VERSION 5.8 ;
BUSBITCHARS "[]" ;
DIVIDERCHAR "/" ;
UNITS
    DATABASE MICRONS 1000 ;
END UNITS

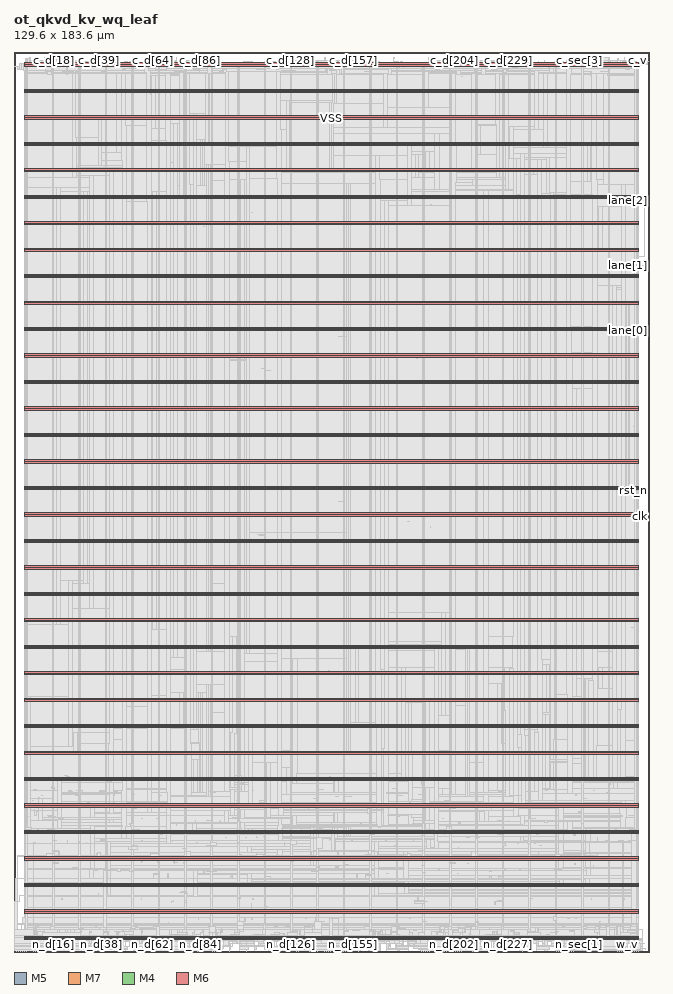
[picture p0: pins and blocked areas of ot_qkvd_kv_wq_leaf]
MACRO ot_qkvd_kv_wq_leaf
  FOREIGN ot_qkvd_kv_wq_leaf 0 0 ;
  CLASS BLOCK ;
  SIZE 129.6 BY 183.6 ;
  PIN c_d[0]
    DIRECTION INPUT ;
    USE SIGNAL ;
    PORT
      LAYER M5 ;
        RECT  0.192 183.516 0.216 183.6 ;
    END
  END c_d[0]
  PIN c_d[100]
    DIRECTION INPUT ;
    USE SIGNAL ;
    PORT
      LAYER M7 ;
        RECT  44.16 183.53 44.192 183.6 ;
    END
  END c_d[100]
  PIN c_d[101]
    DIRECTION INPUT ;
    USE SIGNAL ;
    PORT
      LAYER M7 ;
        RECT  44.544 183.53 44.576 183.6 ;
    END
  END c_d[101]
  PIN c_d[102]
    DIRECTION INPUT ;
    USE SIGNAL ;
    PORT
      LAYER M7 ;
        RECT  44.992 183.53 45.024 183.6 ;
    END
  END c_d[102]
  PIN c_d[103]
    DIRECTION INPUT ;
    USE SIGNAL ;
    PORT
      LAYER M7 ;
        RECT  45.44 183.53 45.472 183.6 ;
    END
  END c_d[103]
  PIN c_d[104]
    DIRECTION INPUT ;
    USE SIGNAL ;
    PORT
      LAYER M7 ;
        RECT  45.888 183.53 45.92 183.6 ;
    END
  END c_d[104]
  PIN c_d[105]
    DIRECTION INPUT ;
    USE SIGNAL ;
    PORT
      LAYER M7 ;
        RECT  46.336 183.53 46.368 183.6 ;
    END
  END c_d[105]
  PIN c_d[106]
    DIRECTION INPUT ;
    USE SIGNAL ;
    PORT
      LAYER M7 ;
        RECT  46.784 183.53 46.816 183.6 ;
    END
  END c_d[106]
  PIN c_d[107]
    DIRECTION INPUT ;
    USE SIGNAL ;
    PORT
      LAYER M7 ;
        RECT  47.232 183.53 47.264 183.6 ;
    END
  END c_d[107]
  PIN c_d[108]
    DIRECTION INPUT ;
    USE SIGNAL ;
    PORT
      LAYER M7 ;
        RECT  47.68 183.53 47.712 183.6 ;
    END
  END c_d[108]
  PIN c_d[109]
    DIRECTION INPUT ;
    USE SIGNAL ;
    PORT
      LAYER M7 ;
        RECT  48.064 183.53 48.096 183.6 ;
    END
  END c_d[109]
  PIN c_d[10]
    DIRECTION INPUT ;
    USE SIGNAL ;
    PORT
      LAYER M5 ;
        RECT  4.608 183.516 4.632 183.6 ;
    END
  END c_d[10]
  PIN c_d[110]
    DIRECTION INPUT ;
    USE SIGNAL ;
    PORT
      LAYER M7 ;
        RECT  48.512 183.53 48.544 183.6 ;
    END
  END c_d[110]
  PIN c_d[111]
    DIRECTION INPUT ;
    USE SIGNAL ;
    PORT
      LAYER M7 ;
        RECT  48.96 183.53 48.992 183.6 ;
    END
  END c_d[111]
  PIN c_d[112]
    DIRECTION INPUT ;
    USE SIGNAL ;
    PORT
      LAYER M7 ;
        RECT  49.408 183.53 49.44 183.6 ;
    END
  END c_d[112]
  PIN c_d[113]
    DIRECTION INPUT ;
    USE SIGNAL ;
    PORT
      LAYER M7 ;
        RECT  49.856 183.53 49.888 183.6 ;
    END
  END c_d[113]
  PIN c_d[114]
    DIRECTION INPUT ;
    USE SIGNAL ;
    PORT
      LAYER M7 ;
        RECT  50.304 183.53 50.336 183.6 ;
    END
  END c_d[114]
  PIN c_d[115]
    DIRECTION INPUT ;
    USE SIGNAL ;
    PORT
      LAYER M7 ;
        RECT  50.752 183.53 50.784 183.6 ;
    END
  END c_d[115]
  PIN c_d[116]
    DIRECTION INPUT ;
    USE SIGNAL ;
    PORT
      LAYER M7 ;
        RECT  51.136 183.53 51.168 183.6 ;
    END
  END c_d[116]
  PIN c_d[117]
    DIRECTION INPUT ;
    USE SIGNAL ;
    PORT
      LAYER M7 ;
        RECT  51.584 183.53 51.616 183.6 ;
    END
  END c_d[117]
  PIN c_d[118]
    DIRECTION INPUT ;
    USE SIGNAL ;
    PORT
      LAYER M7 ;
        RECT  52.032 183.53 52.064 183.6 ;
    END
  END c_d[118]
  PIN c_d[119]
    DIRECTION INPUT ;
    USE SIGNAL ;
    PORT
      LAYER M7 ;
        RECT  52.48 183.53 52.512 183.6 ;
    END
  END c_d[119]
  PIN c_d[11]
    DIRECTION INPUT ;
    USE SIGNAL ;
    PORT
      LAYER M5 ;
        RECT  5.04 183.516 5.064 183.6 ;
    END
  END c_d[11]
  PIN c_d[120]
    DIRECTION INPUT ;
    USE SIGNAL ;
    PORT
      LAYER M7 ;
        RECT  52.928 183.53 52.96 183.6 ;
    END
  END c_d[120]
  PIN c_d[121]
    DIRECTION INPUT ;
    USE SIGNAL ;
    PORT
      LAYER M7 ;
        RECT  53.376 183.53 53.408 183.6 ;
    END
  END c_d[121]
  PIN c_d[122]
    DIRECTION INPUT ;
    USE SIGNAL ;
    PORT
      LAYER M7 ;
        RECT  53.824 183.53 53.856 183.6 ;
    END
  END c_d[122]
  PIN c_d[123]
    DIRECTION INPUT ;
    USE SIGNAL ;
    PORT
      LAYER M7 ;
        RECT  54.272 183.53 54.304 183.6 ;
    END
  END c_d[123]
  PIN c_d[124]
    DIRECTION INPUT ;
    USE SIGNAL ;
    PORT
      LAYER M7 ;
        RECT  54.656 183.53 54.688 183.6 ;
    END
  END c_d[124]
  PIN c_d[125]
    DIRECTION INPUT ;
    USE SIGNAL ;
    PORT
      LAYER M7 ;
        RECT  55.104 183.53 55.136 183.6 ;
    END
  END c_d[125]
  PIN c_d[126]
    DIRECTION INPUT ;
    USE SIGNAL ;
    PORT
      LAYER M7 ;
        RECT  55.552 183.53 55.584 183.6 ;
    END
  END c_d[126]
  PIN c_d[127]
    DIRECTION INPUT ;
    USE SIGNAL ;
    PORT
      LAYER M7 ;
        RECT  56 183.53 56.032 183.6 ;
    END
  END c_d[127]
  PIN c_d[128]
    DIRECTION INPUT ;
    USE SIGNAL ;
    PORT
      LAYER M5 ;
        RECT  56.448 183.516 56.472 183.6 ;
    END
  END c_d[128]
  PIN c_d[129]
    DIRECTION INPUT ;
    USE SIGNAL ;
    PORT
      LAYER M5 ;
        RECT  56.88 183.516 56.904 183.6 ;
    END
  END c_d[129]
  PIN c_d[12]
    DIRECTION INPUT ;
    USE SIGNAL ;
    PORT
      LAYER M5 ;
        RECT  5.472 183.516 5.496 183.6 ;
    END
  END c_d[12]
  PIN c_d[130]
    DIRECTION INPUT ;
    USE SIGNAL ;
    PORT
      LAYER M5 ;
        RECT  57.312 183.516 57.336 183.6 ;
    END
  END c_d[130]
  PIN c_d[131]
    DIRECTION INPUT ;
    USE SIGNAL ;
    PORT
      LAYER M5 ;
        RECT  57.744 183.516 57.768 183.6 ;
    END
  END c_d[131]
  PIN c_d[132]
    DIRECTION INPUT ;
    USE SIGNAL ;
    PORT
      LAYER M5 ;
        RECT  58.176 183.516 58.2 183.6 ;
    END
  END c_d[132]
  PIN c_d[133]
    DIRECTION INPUT ;
    USE SIGNAL ;
    PORT
      LAYER M5 ;
        RECT  58.656 183.516 58.68 183.6 ;
    END
  END c_d[133]
  PIN c_d[134]
    DIRECTION INPUT ;
    USE SIGNAL ;
    PORT
      LAYER M5 ;
        RECT  59.088 183.516 59.112 183.6 ;
    END
  END c_d[134]
  PIN c_d[135]
    DIRECTION INPUT ;
    USE SIGNAL ;
    PORT
      LAYER M5 ;
        RECT  59.52 183.516 59.544 183.6 ;
    END
  END c_d[135]
  PIN c_d[136]
    DIRECTION INPUT ;
    USE SIGNAL ;
    PORT
      LAYER M5 ;
        RECT  59.952 183.516 59.976 183.6 ;
    END
  END c_d[136]
  PIN c_d[137]
    DIRECTION INPUT ;
    USE SIGNAL ;
    PORT
      LAYER M5 ;
        RECT  60.384 183.516 60.408 183.6 ;
    END
  END c_d[137]
  PIN c_d[138]
    DIRECTION INPUT ;
    USE SIGNAL ;
    PORT
      LAYER M5 ;
        RECT  60.816 183.516 60.84 183.6 ;
    END
  END c_d[138]
  PIN c_d[139]
    DIRECTION INPUT ;
    USE SIGNAL ;
    PORT
      LAYER M5 ;
        RECT  61.296 183.516 61.32 183.6 ;
    END
  END c_d[139]
  PIN c_d[13]
    DIRECTION INPUT ;
    USE SIGNAL ;
    PORT
      LAYER M5 ;
        RECT  5.904 183.516 5.928 183.6 ;
    END
  END c_d[13]
  PIN c_d[140]
    DIRECTION INPUT ;
    USE SIGNAL ;
    PORT
      LAYER M5 ;
        RECT  61.728 183.516 61.752 183.6 ;
    END
  END c_d[140]
  PIN c_d[141]
    DIRECTION INPUT ;
    USE SIGNAL ;
    PORT
      LAYER M5 ;
        RECT  62.16 183.516 62.184 183.6 ;
    END
  END c_d[141]
  PIN c_d[142]
    DIRECTION INPUT ;
    USE SIGNAL ;
    PORT
      LAYER M5 ;
        RECT  62.592 183.516 62.616 183.6 ;
    END
  END c_d[142]
  PIN c_d[143]
    DIRECTION INPUT ;
    USE SIGNAL ;
    PORT
      LAYER M5 ;
        RECT  63.024 183.516 63.048 183.6 ;
    END
  END c_d[143]
  PIN c_d[144]
    DIRECTION INPUT ;
    USE SIGNAL ;
    PORT
      LAYER M5 ;
        RECT  63.456 183.516 63.48 183.6 ;
    END
  END c_d[144]
  PIN c_d[145]
    DIRECTION INPUT ;
    USE SIGNAL ;
    PORT
      LAYER M5 ;
        RECT  63.888 183.516 63.912 183.6 ;
    END
  END c_d[145]
  PIN c_d[146]
    DIRECTION INPUT ;
    USE SIGNAL ;
    PORT
      LAYER M5 ;
        RECT  64.368 183.516 64.392 183.6 ;
    END
  END c_d[146]
  PIN c_d[147]
    DIRECTION INPUT ;
    USE SIGNAL ;
    PORT
      LAYER M5 ;
        RECT  64.8 183.516 64.824 183.6 ;
    END
  END c_d[147]
  PIN c_d[148]
    DIRECTION INPUT ;
    USE SIGNAL ;
    PORT
      LAYER M5 ;
        RECT  65.232 183.516 65.256 183.6 ;
    END
  END c_d[148]
  PIN c_d[149]
    DIRECTION INPUT ;
    USE SIGNAL ;
    PORT
      LAYER M5 ;
        RECT  65.664 183.516 65.688 183.6 ;
    END
  END c_d[149]
  PIN c_d[14]
    DIRECTION INPUT ;
    USE SIGNAL ;
    PORT
      LAYER M5 ;
        RECT  6.336 183.516 6.36 183.6 ;
    END
  END c_d[14]
  PIN c_d[150]
    DIRECTION INPUT ;
    USE SIGNAL ;
    PORT
      LAYER M5 ;
        RECT  66.096 183.516 66.12 183.6 ;
    END
  END c_d[150]
  PIN c_d[151]
    DIRECTION INPUT ;
    USE SIGNAL ;
    PORT
      LAYER M5 ;
        RECT  66.528 183.516 66.552 183.6 ;
    END
  END c_d[151]
  PIN c_d[152]
    DIRECTION INPUT ;
    USE SIGNAL ;
    PORT
      LAYER M5 ;
        RECT  67.008 183.516 67.032 183.6 ;
    END
  END c_d[152]
  PIN c_d[153]
    DIRECTION INPUT ;
    USE SIGNAL ;
    PORT
      LAYER M5 ;
        RECT  67.44 183.516 67.464 183.6 ;
    END
  END c_d[153]
  PIN c_d[154]
    DIRECTION INPUT ;
    USE SIGNAL ;
    PORT
      LAYER M5 ;
        RECT  67.872 183.516 67.896 183.6 ;
    END
  END c_d[154]
  PIN c_d[155]
    DIRECTION INPUT ;
    USE SIGNAL ;
    PORT
      LAYER M5 ;
        RECT  68.304 183.516 68.328 183.6 ;
    END
  END c_d[155]
  PIN c_d[156]
    DIRECTION INPUT ;
    USE SIGNAL ;
    PORT
      LAYER M5 ;
        RECT  68.736 183.516 68.76 183.6 ;
    END
  END c_d[156]
  PIN c_d[157]
    DIRECTION INPUT ;
    USE SIGNAL ;
    PORT
      LAYER M5 ;
        RECT  69.168 183.516 69.192 183.6 ;
    END
  END c_d[157]
  PIN c_d[158]
    DIRECTION INPUT ;
    USE SIGNAL ;
    PORT
      LAYER M5 ;
        RECT  69.6 183.516 69.624 183.6 ;
    END
  END c_d[158]
  PIN c_d[159]
    DIRECTION INPUT ;
    USE SIGNAL ;
    PORT
      LAYER M5 ;
        RECT  70.08 183.516 70.104 183.6 ;
    END
  END c_d[159]
  PIN c_d[15]
    DIRECTION INPUT ;
    USE SIGNAL ;
    PORT
      LAYER M5 ;
        RECT  6.816 183.516 6.84 183.6 ;
    END
  END c_d[15]
  PIN c_d[160]
    DIRECTION INPUT ;
    USE SIGNAL ;
    PORT
      LAYER M7 ;
        RECT  70.464 183.53 70.496 183.6 ;
    END
  END c_d[160]
  PIN c_d[161]
    DIRECTION INPUT ;
    USE SIGNAL ;
    PORT
      LAYER M7 ;
        RECT  70.912 183.53 70.944 183.6 ;
    END
  END c_d[161]
  PIN c_d[162]
    DIRECTION INPUT ;
    USE SIGNAL ;
    PORT
      LAYER M7 ;
        RECT  71.36 183.53 71.392 183.6 ;
    END
  END c_d[162]
  PIN c_d[163]
    DIRECTION INPUT ;
    USE SIGNAL ;
    PORT
      LAYER M7 ;
        RECT  71.808 183.53 71.84 183.6 ;
    END
  END c_d[163]
  PIN c_d[164]
    DIRECTION INPUT ;
    USE SIGNAL ;
    PORT
      LAYER M7 ;
        RECT  72.256 183.53 72.288 183.6 ;
    END
  END c_d[164]
  PIN c_d[165]
    DIRECTION INPUT ;
    USE SIGNAL ;
    PORT
      LAYER M7 ;
        RECT  72.704 183.53 72.736 183.6 ;
    END
  END c_d[165]
  PIN c_d[166]
    DIRECTION INPUT ;
    USE SIGNAL ;
    PORT
      LAYER M7 ;
        RECT  73.152 183.53 73.184 183.6 ;
    END
  END c_d[166]
  PIN c_d[167]
    DIRECTION INPUT ;
    USE SIGNAL ;
    PORT
      LAYER M7 ;
        RECT  73.6 183.53 73.632 183.6 ;
    END
  END c_d[167]
  PIN c_d[168]
    DIRECTION INPUT ;
    USE SIGNAL ;
    PORT
      LAYER M7 ;
        RECT  73.984 183.53 74.016 183.6 ;
    END
  END c_d[168]
  PIN c_d[169]
    DIRECTION INPUT ;
    USE SIGNAL ;
    PORT
      LAYER M7 ;
        RECT  74.432 183.53 74.464 183.6 ;
    END
  END c_d[169]
  PIN c_d[16]
    DIRECTION INPUT ;
    USE SIGNAL ;
    PORT
      LAYER M5 ;
        RECT  7.248 183.516 7.272 183.6 ;
    END
  END c_d[16]
  PIN c_d[170]
    DIRECTION INPUT ;
    USE SIGNAL ;
    PORT
      LAYER M7 ;
        RECT  74.88 183.53 74.912 183.6 ;
    END
  END c_d[170]
  PIN c_d[171]
    DIRECTION INPUT ;
    USE SIGNAL ;
    PORT
      LAYER M7 ;
        RECT  75.328 183.53 75.36 183.6 ;
    END
  END c_d[171]
  PIN c_d[172]
    DIRECTION INPUT ;
    USE SIGNAL ;
    PORT
      LAYER M7 ;
        RECT  75.776 183.53 75.808 183.6 ;
    END
  END c_d[172]
  PIN c_d[173]
    DIRECTION INPUT ;
    USE SIGNAL ;
    PORT
      LAYER M7 ;
        RECT  76.224 183.53 76.256 183.6 ;
    END
  END c_d[173]
  PIN c_d[174]
    DIRECTION INPUT ;
    USE SIGNAL ;
    PORT
      LAYER M7 ;
        RECT  76.672 183.53 76.704 183.6 ;
    END
  END c_d[174]
  PIN c_d[175]
    DIRECTION INPUT ;
    USE SIGNAL ;
    PORT
      LAYER M7 ;
        RECT  77.056 183.53 77.088 183.6 ;
    END
  END c_d[175]
  PIN c_d[176]
    DIRECTION INPUT ;
    USE SIGNAL ;
    PORT
      LAYER M7 ;
        RECT  77.504 183.53 77.536 183.6 ;
    END
  END c_d[176]
  PIN c_d[177]
    DIRECTION INPUT ;
    USE SIGNAL ;
    PORT
      LAYER M7 ;
        RECT  77.952 183.53 77.984 183.6 ;
    END
  END c_d[177]
  PIN c_d[178]
    DIRECTION INPUT ;
    USE SIGNAL ;
    PORT
      LAYER M7 ;
        RECT  78.4 183.53 78.432 183.6 ;
    END
  END c_d[178]
  PIN c_d[179]
    DIRECTION INPUT ;
    USE SIGNAL ;
    PORT
      LAYER M7 ;
        RECT  78.848 183.53 78.88 183.6 ;
    END
  END c_d[179]
  PIN c_d[17]
    DIRECTION INPUT ;
    USE SIGNAL ;
    PORT
      LAYER M5 ;
        RECT  7.68 183.516 7.704 183.6 ;
    END
  END c_d[17]
  PIN c_d[180]
    DIRECTION INPUT ;
    USE SIGNAL ;
    PORT
      LAYER M7 ;
        RECT  79.296 183.53 79.328 183.6 ;
    END
  END c_d[180]
  PIN c_d[181]
    DIRECTION INPUT ;
    USE SIGNAL ;
    PORT
      LAYER M7 ;
        RECT  79.744 183.53 79.776 183.6 ;
    END
  END c_d[181]
  PIN c_d[182]
    DIRECTION INPUT ;
    USE SIGNAL ;
    PORT
      LAYER M7 ;
        RECT  80.192 183.53 80.224 183.6 ;
    END
  END c_d[182]
  PIN c_d[183]
    DIRECTION INPUT ;
    USE SIGNAL ;
    PORT
      LAYER M7 ;
        RECT  80.576 183.53 80.608 183.6 ;
    END
  END c_d[183]
  PIN c_d[184]
    DIRECTION INPUT ;
    USE SIGNAL ;
    PORT
      LAYER M7 ;
        RECT  81.024 183.53 81.056 183.6 ;
    END
  END c_d[184]
  PIN c_d[185]
    DIRECTION INPUT ;
    USE SIGNAL ;
    PORT
      LAYER M7 ;
        RECT  81.472 183.53 81.504 183.6 ;
    END
  END c_d[185]
  PIN c_d[186]
    DIRECTION INPUT ;
    USE SIGNAL ;
    PORT
      LAYER M7 ;
        RECT  81.92 183.53 81.952 183.6 ;
    END
  END c_d[186]
  PIN c_d[187]
    DIRECTION INPUT ;
    USE SIGNAL ;
    PORT
      LAYER M7 ;
        RECT  82.368 183.53 82.4 183.6 ;
    END
  END c_d[187]
  PIN c_d[188]
    DIRECTION INPUT ;
    USE SIGNAL ;
    PORT
      LAYER M7 ;
        RECT  82.816 183.53 82.848 183.6 ;
    END
  END c_d[188]
  PIN c_d[189]
    DIRECTION INPUT ;
    USE SIGNAL ;
    PORT
      LAYER M7 ;
        RECT  83.264 183.53 83.296 183.6 ;
    END
  END c_d[189]
  PIN c_d[18]
    DIRECTION INPUT ;
    USE SIGNAL ;
    PORT
      LAYER M5 ;
        RECT  8.112 183.516 8.136 183.6 ;
    END
  END c_d[18]
  PIN c_d[190]
    DIRECTION INPUT ;
    USE SIGNAL ;
    PORT
      LAYER M7 ;
        RECT  83.648 183.53 83.68 183.6 ;
    END
  END c_d[190]
  PIN c_d[191]
    DIRECTION INPUT ;
    USE SIGNAL ;
    PORT
      LAYER M7 ;
        RECT  84.096 183.53 84.128 183.6 ;
    END
  END c_d[191]
  PIN c_d[192]
    DIRECTION INPUT ;
    USE SIGNAL ;
    PORT
      LAYER M5 ;
        RECT  84.576 183.516 84.6 183.6 ;
    END
  END c_d[192]
  PIN c_d[193]
    DIRECTION INPUT ;
    USE SIGNAL ;
    PORT
      LAYER M5 ;
        RECT  85.008 183.516 85.032 183.6 ;
    END
  END c_d[193]
  PIN c_d[194]
    DIRECTION INPUT ;
    USE SIGNAL ;
    PORT
      LAYER M5 ;
        RECT  85.44 183.516 85.464 183.6 ;
    END
  END c_d[194]
  PIN c_d[195]
    DIRECTION INPUT ;
    USE SIGNAL ;
    PORT
      LAYER M5 ;
        RECT  85.872 183.516 85.896 183.6 ;
    END
  END c_d[195]
  PIN c_d[196]
    DIRECTION INPUT ;
    USE SIGNAL ;
    PORT
      LAYER M5 ;
        RECT  86.304 183.516 86.328 183.6 ;
    END
  END c_d[196]
  PIN c_d[197]
    DIRECTION INPUT ;
    USE SIGNAL ;
    PORT
      LAYER M5 ;
        RECT  86.736 183.516 86.76 183.6 ;
    END
  END c_d[197]
  PIN c_d[198]
    DIRECTION INPUT ;
    USE SIGNAL ;
    PORT
      LAYER M5 ;
        RECT  87.216 183.516 87.24 183.6 ;
    END
  END c_d[198]
  PIN c_d[199]
    DIRECTION INPUT ;
    USE SIGNAL ;
    PORT
      LAYER M5 ;
        RECT  87.648 183.516 87.672 183.6 ;
    END
  END c_d[199]
  PIN c_d[19]
    DIRECTION INPUT ;
    USE SIGNAL ;
    PORT
      LAYER M5 ;
        RECT  8.544 183.516 8.568 183.6 ;
    END
  END c_d[19]
  PIN c_d[1]
    DIRECTION INPUT ;
    USE SIGNAL ;
    PORT
      LAYER M5 ;
        RECT  0.624 183.516 0.648 183.6 ;
    END
  END c_d[1]
  PIN c_d[200]
    DIRECTION INPUT ;
    USE SIGNAL ;
    PORT
      LAYER M5 ;
        RECT  88.08 183.516 88.104 183.6 ;
    END
  END c_d[200]
  PIN c_d[201]
    DIRECTION INPUT ;
    USE SIGNAL ;
    PORT
      LAYER M5 ;
        RECT  88.512 183.516 88.536 183.6 ;
    END
  END c_d[201]
  PIN c_d[202]
    DIRECTION INPUT ;
    USE SIGNAL ;
    PORT
      LAYER M5 ;
        RECT  88.944 183.516 88.968 183.6 ;
    END
  END c_d[202]
  PIN c_d[203]
    DIRECTION INPUT ;
    USE SIGNAL ;
    PORT
      LAYER M5 ;
        RECT  89.376 183.516 89.4 183.6 ;
    END
  END c_d[203]
  PIN c_d[204]
    DIRECTION INPUT ;
    USE SIGNAL ;
    PORT
      LAYER M5 ;
        RECT  89.808 183.516 89.832 183.6 ;
    END
  END c_d[204]
  PIN c_d[205]
    DIRECTION INPUT ;
    USE SIGNAL ;
    PORT
      LAYER M5 ;
        RECT  90.288 183.516 90.312 183.6 ;
    END
  END c_d[205]
  PIN c_d[206]
    DIRECTION INPUT ;
    USE SIGNAL ;
    PORT
      LAYER M5 ;
        RECT  90.72 183.516 90.744 183.6 ;
    END
  END c_d[206]
  PIN c_d[207]
    DIRECTION INPUT ;
    USE SIGNAL ;
    PORT
      LAYER M5 ;
        RECT  91.152 183.516 91.176 183.6 ;
    END
  END c_d[207]
  PIN c_d[208]
    DIRECTION INPUT ;
    USE SIGNAL ;
    PORT
      LAYER M5 ;
        RECT  91.584 183.516 91.608 183.6 ;
    END
  END c_d[208]
  PIN c_d[209]
    DIRECTION INPUT ;
    USE SIGNAL ;
    PORT
      LAYER M5 ;
        RECT  92.016 183.516 92.04 183.6 ;
    END
  END c_d[209]
  PIN c_d[20]
    DIRECTION INPUT ;
    USE SIGNAL ;
    PORT
      LAYER M5 ;
        RECT  8.976 183.516 9 183.6 ;
    END
  END c_d[20]
  PIN c_d[210]
    DIRECTION INPUT ;
    USE SIGNAL ;
    PORT
      LAYER M5 ;
        RECT  92.448 183.516 92.472 183.6 ;
    END
  END c_d[210]
  PIN c_d[211]
    DIRECTION INPUT ;
    USE SIGNAL ;
    PORT
      LAYER M5 ;
        RECT  92.928 183.516 92.952 183.6 ;
    END
  END c_d[211]
  PIN c_d[212]
    DIRECTION INPUT ;
    USE SIGNAL ;
    PORT
      LAYER M5 ;
        RECT  93.36 183.516 93.384 183.6 ;
    END
  END c_d[212]
  PIN c_d[213]
    DIRECTION INPUT ;
    USE SIGNAL ;
    PORT
      LAYER M5 ;
        RECT  93.792 183.516 93.816 183.6 ;
    END
  END c_d[213]
  PIN c_d[214]
    DIRECTION INPUT ;
    USE SIGNAL ;
    PORT
      LAYER M5 ;
        RECT  94.224 183.516 94.248 183.6 ;
    END
  END c_d[214]
  PIN c_d[215]
    DIRECTION INPUT ;
    USE SIGNAL ;
    PORT
      LAYER M5 ;
        RECT  94.656 183.516 94.68 183.6 ;
    END
  END c_d[215]
  PIN c_d[216]
    DIRECTION INPUT ;
    USE SIGNAL ;
    PORT
      LAYER M5 ;
        RECT  95.088 183.516 95.112 183.6 ;
    END
  END c_d[216]
  PIN c_d[217]
    DIRECTION INPUT ;
    USE SIGNAL ;
    PORT
      LAYER M5 ;
        RECT  95.52 183.516 95.544 183.6 ;
    END
  END c_d[217]
  PIN c_d[218]
    DIRECTION INPUT ;
    USE SIGNAL ;
    PORT
      LAYER M5 ;
        RECT  96 183.516 96.024 183.6 ;
    END
  END c_d[218]
  PIN c_d[219]
    DIRECTION INPUT ;
    USE SIGNAL ;
    PORT
      LAYER M5 ;
        RECT  96.432 183.516 96.456 183.6 ;
    END
  END c_d[219]
  PIN c_d[21]
    DIRECTION INPUT ;
    USE SIGNAL ;
    PORT
      LAYER M5 ;
        RECT  9.456 183.516 9.48 183.6 ;
    END
  END c_d[21]
  PIN c_d[220]
    DIRECTION INPUT ;
    USE SIGNAL ;
    PORT
      LAYER M5 ;
        RECT  96.864 183.516 96.888 183.6 ;
    END
  END c_d[220]
  PIN c_d[221]
    DIRECTION INPUT ;
    USE SIGNAL ;
    PORT
      LAYER M5 ;
        RECT  97.296 183.516 97.32 183.6 ;
    END
  END c_d[221]
  PIN c_d[222]
    DIRECTION INPUT ;
    USE SIGNAL ;
    PORT
      LAYER M5 ;
        RECT  97.728 183.516 97.752 183.6 ;
    END
  END c_d[222]
  PIN c_d[223]
    DIRECTION INPUT ;
    USE SIGNAL ;
    PORT
      LAYER M5 ;
        RECT  98.16 183.516 98.184 183.6 ;
    END
  END c_d[223]
  PIN c_d[224]
    DIRECTION INPUT ;
    USE SIGNAL ;
    PORT
      LAYER M7 ;
        RECT  98.624 183.53 98.656 183.6 ;
    END
  END c_d[224]
  PIN c_d[225]
    DIRECTION INPUT ;
    USE SIGNAL ;
    PORT
      LAYER M7 ;
        RECT  99.072 183.53 99.104 183.6 ;
    END
  END c_d[225]
  PIN c_d[226]
    DIRECTION INPUT ;
    USE SIGNAL ;
    PORT
      LAYER M7 ;
        RECT  99.52 183.53 99.552 183.6 ;
    END
  END c_d[226]
  PIN c_d[227]
    DIRECTION INPUT ;
    USE SIGNAL ;
    PORT
      LAYER M7 ;
        RECT  99.904 183.53 99.936 183.6 ;
    END
  END c_d[227]
  PIN c_d[228]
    DIRECTION INPUT ;
    USE SIGNAL ;
    PORT
      LAYER M7 ;
        RECT  100.352 183.53 100.384 183.6 ;
    END
  END c_d[228]
  PIN c_d[229]
    DIRECTION INPUT ;
    USE SIGNAL ;
    PORT
      LAYER M7 ;
        RECT  100.8 183.53 100.832 183.6 ;
    END
  END c_d[229]
  PIN c_d[22]
    DIRECTION INPUT ;
    USE SIGNAL ;
    PORT
      LAYER M5 ;
        RECT  9.888 183.516 9.912 183.6 ;
    END
  END c_d[22]
  PIN c_d[230]
    DIRECTION INPUT ;
    USE SIGNAL ;
    PORT
      LAYER M7 ;
        RECT  101.248 183.53 101.28 183.6 ;
    END
  END c_d[230]
  PIN c_d[231]
    DIRECTION INPUT ;
    USE SIGNAL ;
    PORT
      LAYER M7 ;
        RECT  101.696 183.53 101.728 183.6 ;
    END
  END c_d[231]
  PIN c_d[232]
    DIRECTION INPUT ;
    USE SIGNAL ;
    PORT
      LAYER M7 ;
        RECT  102.144 183.53 102.176 183.6 ;
    END
  END c_d[232]
  PIN c_d[233]
    DIRECTION INPUT ;
    USE SIGNAL ;
    PORT
      LAYER M7 ;
        RECT  102.592 183.53 102.624 183.6 ;
    END
  END c_d[233]
  PIN c_d[234]
    DIRECTION INPUT ;
    USE SIGNAL ;
    PORT
      LAYER M7 ;
        RECT  102.976 183.53 103.008 183.6 ;
    END
  END c_d[234]
  PIN c_d[235]
    DIRECTION INPUT ;
    USE SIGNAL ;
    PORT
      LAYER M7 ;
        RECT  103.424 183.53 103.456 183.6 ;
    END
  END c_d[235]
  PIN c_d[236]
    DIRECTION INPUT ;
    USE SIGNAL ;
    PORT
      LAYER M7 ;
        RECT  103.872 183.53 103.904 183.6 ;
    END
  END c_d[236]
  PIN c_d[237]
    DIRECTION INPUT ;
    USE SIGNAL ;
    PORT
      LAYER M7 ;
        RECT  104.32 183.53 104.352 183.6 ;
    END
  END c_d[237]
  PIN c_d[238]
    DIRECTION INPUT ;
    USE SIGNAL ;
    PORT
      LAYER M7 ;
        RECT  104.768 183.53 104.8 183.6 ;
    END
  END c_d[238]
  PIN c_d[239]
    DIRECTION INPUT ;
    USE SIGNAL ;
    PORT
      LAYER M7 ;
        RECT  105.216 183.53 105.248 183.6 ;
    END
  END c_d[239]
  PIN c_d[23]
    DIRECTION INPUT ;
    USE SIGNAL ;
    PORT
      LAYER M5 ;
        RECT  10.32 183.516 10.344 183.6 ;
    END
  END c_d[23]
  PIN c_d[240]
    DIRECTION INPUT ;
    USE SIGNAL ;
    PORT
      LAYER M7 ;
        RECT  105.664 183.53 105.696 183.6 ;
    END
  END c_d[240]
  PIN c_d[241]
    DIRECTION INPUT ;
    USE SIGNAL ;
    PORT
      LAYER M7 ;
        RECT  106.112 183.53 106.144 183.6 ;
    END
  END c_d[241]
  PIN c_d[242]
    DIRECTION INPUT ;
    USE SIGNAL ;
    PORT
      LAYER M7 ;
        RECT  106.496 183.53 106.528 183.6 ;
    END
  END c_d[242]
  PIN c_d[243]
    DIRECTION INPUT ;
    USE SIGNAL ;
    PORT
      LAYER M7 ;
        RECT  106.944 183.53 106.976 183.6 ;
    END
  END c_d[243]
  PIN c_d[244]
    DIRECTION INPUT ;
    USE SIGNAL ;
    PORT
      LAYER M7 ;
        RECT  107.392 183.53 107.424 183.6 ;
    END
  END c_d[244]
  PIN c_d[245]
    DIRECTION INPUT ;
    USE SIGNAL ;
    PORT
      LAYER M7 ;
        RECT  107.84 183.53 107.872 183.6 ;
    END
  END c_d[245]
  PIN c_d[246]
    DIRECTION INPUT ;
    USE SIGNAL ;
    PORT
      LAYER M7 ;
        RECT  108.288 183.53 108.32 183.6 ;
    END
  END c_d[246]
  PIN c_d[247]
    DIRECTION INPUT ;
    USE SIGNAL ;
    PORT
      LAYER M7 ;
        RECT  108.736 183.53 108.768 183.6 ;
    END
  END c_d[247]
  PIN c_d[248]
    DIRECTION INPUT ;
    USE SIGNAL ;
    PORT
      LAYER M7 ;
        RECT  109.184 183.53 109.216 183.6 ;
    END
  END c_d[248]
  PIN c_d[249]
    DIRECTION INPUT ;
    USE SIGNAL ;
    PORT
      LAYER M7 ;
        RECT  109.568 183.53 109.6 183.6 ;
    END
  END c_d[249]
  PIN c_d[24]
    DIRECTION INPUT ;
    USE SIGNAL ;
    PORT
      LAYER M5 ;
        RECT  10.752 183.516 10.776 183.6 ;
    END
  END c_d[24]
  PIN c_d[250]
    DIRECTION INPUT ;
    USE SIGNAL ;
    PORT
      LAYER M7 ;
        RECT  110.016 183.53 110.048 183.6 ;
    END
  END c_d[250]
  PIN c_d[251]
    DIRECTION INPUT ;
    USE SIGNAL ;
    PORT
      LAYER M7 ;
        RECT  110.464 183.53 110.496 183.6 ;
    END
  END c_d[251]
  PIN c_d[252]
    DIRECTION INPUT ;
    USE SIGNAL ;
    PORT
      LAYER M7 ;
        RECT  110.912 183.53 110.944 183.6 ;
    END
  END c_d[252]
  PIN c_d[253]
    DIRECTION INPUT ;
    USE SIGNAL ;
    PORT
      LAYER M7 ;
        RECT  111.36 183.53 111.392 183.6 ;
    END
  END c_d[253]
  PIN c_d[254]
    DIRECTION INPUT ;
    USE SIGNAL ;
    PORT
      LAYER M7 ;
        RECT  111.808 183.53 111.84 183.6 ;
    END
  END c_d[254]
  PIN c_d[255]
    DIRECTION INPUT ;
    USE SIGNAL ;
    PORT
      LAYER M7 ;
        RECT  112.256 183.53 112.288 183.6 ;
    END
  END c_d[255]
  PIN c_d[25]
    DIRECTION INPUT ;
    USE SIGNAL ;
    PORT
      LAYER M5 ;
        RECT  11.184 183.516 11.208 183.6 ;
    END
  END c_d[25]
  PIN c_d[26]
    DIRECTION INPUT ;
    USE SIGNAL ;
    PORT
      LAYER M5 ;
        RECT  11.616 183.516 11.64 183.6 ;
    END
  END c_d[26]
  PIN c_d[27]
    DIRECTION INPUT ;
    USE SIGNAL ;
    PORT
      LAYER M5 ;
        RECT  12.048 183.516 12.072 183.6 ;
    END
  END c_d[27]
  PIN c_d[28]
    DIRECTION INPUT ;
    USE SIGNAL ;
    PORT
      LAYER M5 ;
        RECT  12.528 183.516 12.552 183.6 ;
    END
  END c_d[28]
  PIN c_d[29]
    DIRECTION INPUT ;
    USE SIGNAL ;
    PORT
      LAYER M5 ;
        RECT  12.96 183.516 12.984 183.6 ;
    END
  END c_d[29]
  PIN c_d[2]
    DIRECTION INPUT ;
    USE SIGNAL ;
    PORT
      LAYER M5 ;
        RECT  1.104 183.516 1.128 183.6 ;
    END
  END c_d[2]
  PIN c_d[30]
    DIRECTION INPUT ;
    USE SIGNAL ;
    PORT
      LAYER M5 ;
        RECT  13.392 183.516 13.416 183.6 ;
    END
  END c_d[30]
  PIN c_d[31]
    DIRECTION INPUT ;
    USE SIGNAL ;
    PORT
      LAYER M5 ;
        RECT  13.824 183.516 13.848 183.6 ;
    END
  END c_d[31]
  PIN c_d[32]
    DIRECTION INPUT ;
    USE SIGNAL ;
    PORT
      LAYER M7 ;
        RECT  14.272 183.53 14.304 183.6 ;
    END
  END c_d[32]
  PIN c_d[33]
    DIRECTION INPUT ;
    USE SIGNAL ;
    PORT
      LAYER M7 ;
        RECT  14.72 183.53 14.752 183.6 ;
    END
  END c_d[33]
  PIN c_d[34]
    DIRECTION INPUT ;
    USE SIGNAL ;
    PORT
      LAYER M7 ;
        RECT  15.168 183.53 15.2 183.6 ;
    END
  END c_d[34]
  PIN c_d[35]
    DIRECTION INPUT ;
    USE SIGNAL ;
    PORT
      LAYER M7 ;
        RECT  15.552 183.53 15.584 183.6 ;
    END
  END c_d[35]
  PIN c_d[36]
    DIRECTION INPUT ;
    USE SIGNAL ;
    PORT
      LAYER M7 ;
        RECT  16 183.53 16.032 183.6 ;
    END
  END c_d[36]
  PIN c_d[37]
    DIRECTION INPUT ;
    USE SIGNAL ;
    PORT
      LAYER M7 ;
        RECT  16.448 183.53 16.48 183.6 ;
    END
  END c_d[37]
  PIN c_d[38]
    DIRECTION INPUT ;
    USE SIGNAL ;
    PORT
      LAYER M7 ;
        RECT  16.896 183.53 16.928 183.6 ;
    END
  END c_d[38]
  PIN c_d[39]
    DIRECTION INPUT ;
    USE SIGNAL ;
    PORT
      LAYER M7 ;
        RECT  17.344 183.53 17.376 183.6 ;
    END
  END c_d[39]
  PIN c_d[3]
    DIRECTION INPUT ;
    USE SIGNAL ;
    PORT
      LAYER M5 ;
        RECT  1.536 183.516 1.56 183.6 ;
    END
  END c_d[3]
  PIN c_d[40]
    DIRECTION INPUT ;
    USE SIGNAL ;
    PORT
      LAYER M7 ;
        RECT  17.792 183.53 17.824 183.6 ;
    END
  END c_d[40]
  PIN c_d[41]
    DIRECTION INPUT ;
    USE SIGNAL ;
    PORT
      LAYER M7 ;
        RECT  18.24 183.53 18.272 183.6 ;
    END
  END c_d[41]
  PIN c_d[42]
    DIRECTION INPUT ;
    USE SIGNAL ;
    PORT
      LAYER M7 ;
        RECT  18.624 183.53 18.656 183.6 ;
    END
  END c_d[42]
  PIN c_d[43]
    DIRECTION INPUT ;
    USE SIGNAL ;
    PORT
      LAYER M7 ;
        RECT  19.072 183.53 19.104 183.6 ;
    END
  END c_d[43]
  PIN c_d[44]
    DIRECTION INPUT ;
    USE SIGNAL ;
    PORT
      LAYER M7 ;
        RECT  19.52 183.53 19.552 183.6 ;
    END
  END c_d[44]
  PIN c_d[45]
    DIRECTION INPUT ;
    USE SIGNAL ;
    PORT
      LAYER M7 ;
        RECT  19.968 183.53 20 183.6 ;
    END
  END c_d[45]
  PIN c_d[46]
    DIRECTION INPUT ;
    USE SIGNAL ;
    PORT
      LAYER M7 ;
        RECT  20.416 183.53 20.448 183.6 ;
    END
  END c_d[46]
  PIN c_d[47]
    DIRECTION INPUT ;
    USE SIGNAL ;
    PORT
      LAYER M7 ;
        RECT  20.864 183.53 20.896 183.6 ;
    END
  END c_d[47]
  PIN c_d[48]
    DIRECTION INPUT ;
    USE SIGNAL ;
    PORT
      LAYER M7 ;
        RECT  21.312 183.53 21.344 183.6 ;
    END
  END c_d[48]
  PIN c_d[49]
    DIRECTION INPUT ;
    USE SIGNAL ;
    PORT
      LAYER M7 ;
        RECT  21.76 183.53 21.792 183.6 ;
    END
  END c_d[49]
  PIN c_d[4]
    DIRECTION INPUT ;
    USE SIGNAL ;
    PORT
      LAYER M5 ;
        RECT  1.968 183.516 1.992 183.6 ;
    END
  END c_d[4]
  PIN c_d[50]
    DIRECTION INPUT ;
    USE SIGNAL ;
    PORT
      LAYER M7 ;
        RECT  22.144 183.53 22.176 183.6 ;
    END
  END c_d[50]
  PIN c_d[51]
    DIRECTION INPUT ;
    USE SIGNAL ;
    PORT
      LAYER M7 ;
        RECT  22.592 183.53 22.624 183.6 ;
    END
  END c_d[51]
  PIN c_d[52]
    DIRECTION INPUT ;
    USE SIGNAL ;
    PORT
      LAYER M7 ;
        RECT  23.04 183.53 23.072 183.6 ;
    END
  END c_d[52]
  PIN c_d[53]
    DIRECTION INPUT ;
    USE SIGNAL ;
    PORT
      LAYER M7 ;
        RECT  23.488 183.53 23.52 183.6 ;
    END
  END c_d[53]
  PIN c_d[54]
    DIRECTION INPUT ;
    USE SIGNAL ;
    PORT
      LAYER M7 ;
        RECT  23.936 183.53 23.968 183.6 ;
    END
  END c_d[54]
  PIN c_d[55]
    DIRECTION INPUT ;
    USE SIGNAL ;
    PORT
      LAYER M7 ;
        RECT  24.384 183.53 24.416 183.6 ;
    END
  END c_d[55]
  PIN c_d[56]
    DIRECTION INPUT ;
    USE SIGNAL ;
    PORT
      LAYER M7 ;
        RECT  24.832 183.53 24.864 183.6 ;
    END
  END c_d[56]
  PIN c_d[57]
    DIRECTION INPUT ;
    USE SIGNAL ;
    PORT
      LAYER M7 ;
        RECT  25.216 183.53 25.248 183.6 ;
    END
  END c_d[57]
  PIN c_d[58]
    DIRECTION INPUT ;
    USE SIGNAL ;
    PORT
      LAYER M7 ;
        RECT  25.664 183.53 25.696 183.6 ;
    END
  END c_d[58]
  PIN c_d[59]
    DIRECTION INPUT ;
    USE SIGNAL ;
    PORT
      LAYER M7 ;
        RECT  26.112 183.53 26.144 183.6 ;
    END
  END c_d[59]
  PIN c_d[5]
    DIRECTION INPUT ;
    USE SIGNAL ;
    PORT
      LAYER M5 ;
        RECT  2.4 183.516 2.424 183.6 ;
    END
  END c_d[5]
  PIN c_d[60]
    DIRECTION INPUT ;
    USE SIGNAL ;
    PORT
      LAYER M7 ;
        RECT  26.56 183.53 26.592 183.6 ;
    END
  END c_d[60]
  PIN c_d[61]
    DIRECTION INPUT ;
    USE SIGNAL ;
    PORT
      LAYER M7 ;
        RECT  27.008 183.53 27.04 183.6 ;
    END
  END c_d[61]
  PIN c_d[62]
    DIRECTION INPUT ;
    USE SIGNAL ;
    PORT
      LAYER M7 ;
        RECT  27.456 183.53 27.488 183.6 ;
    END
  END c_d[62]
  PIN c_d[63]
    DIRECTION INPUT ;
    USE SIGNAL ;
    PORT
      LAYER M7 ;
        RECT  27.904 183.53 27.936 183.6 ;
    END
  END c_d[63]
  PIN c_d[64]
    DIRECTION INPUT ;
    USE SIGNAL ;
    PORT
      LAYER M5 ;
        RECT  28.32 183.516 28.344 183.6 ;
    END
  END c_d[64]
  PIN c_d[65]
    DIRECTION INPUT ;
    USE SIGNAL ;
    PORT
      LAYER M5 ;
        RECT  28.752 183.516 28.776 183.6 ;
    END
  END c_d[65]
  PIN c_d[66]
    DIRECTION INPUT ;
    USE SIGNAL ;
    PORT
      LAYER M5 ;
        RECT  29.184 183.516 29.208 183.6 ;
    END
  END c_d[66]
  PIN c_d[67]
    DIRECTION INPUT ;
    USE SIGNAL ;
    PORT
      LAYER M5 ;
        RECT  29.664 183.516 29.688 183.6 ;
    END
  END c_d[67]
  PIN c_d[68]
    DIRECTION INPUT ;
    USE SIGNAL ;
    PORT
      LAYER M5 ;
        RECT  30.096 183.516 30.12 183.6 ;
    END
  END c_d[68]
  PIN c_d[69]
    DIRECTION INPUT ;
    USE SIGNAL ;
    PORT
      LAYER M5 ;
        RECT  30.528 183.516 30.552 183.6 ;
    END
  END c_d[69]
  PIN c_d[6]
    DIRECTION INPUT ;
    USE SIGNAL ;
    PORT
      LAYER M5 ;
        RECT  2.832 183.516 2.856 183.6 ;
    END
  END c_d[6]
  PIN c_d[70]
    DIRECTION INPUT ;
    USE SIGNAL ;
    PORT
      LAYER M5 ;
        RECT  30.96 183.516 30.984 183.6 ;
    END
  END c_d[70]
  PIN c_d[71]
    DIRECTION INPUT ;
    USE SIGNAL ;
    PORT
      LAYER M5 ;
        RECT  31.392 183.516 31.416 183.6 ;
    END
  END c_d[71]
  PIN c_d[72]
    DIRECTION INPUT ;
    USE SIGNAL ;
    PORT
      LAYER M5 ;
        RECT  31.824 183.516 31.848 183.6 ;
    END
  END c_d[72]
  PIN c_d[73]
    DIRECTION INPUT ;
    USE SIGNAL ;
    PORT
      LAYER M5 ;
        RECT  32.256 183.516 32.28 183.6 ;
    END
  END c_d[73]
  PIN c_d[74]
    DIRECTION INPUT ;
    USE SIGNAL ;
    PORT
      LAYER M5 ;
        RECT  32.736 183.516 32.76 183.6 ;
    END
  END c_d[74]
  PIN c_d[75]
    DIRECTION INPUT ;
    USE SIGNAL ;
    PORT
      LAYER M5 ;
        RECT  33.168 183.516 33.192 183.6 ;
    END
  END c_d[75]
  PIN c_d[76]
    DIRECTION INPUT ;
    USE SIGNAL ;
    PORT
      LAYER M5 ;
        RECT  33.6 183.516 33.624 183.6 ;
    END
  END c_d[76]
  PIN c_d[77]
    DIRECTION INPUT ;
    USE SIGNAL ;
    PORT
      LAYER M5 ;
        RECT  34.032 183.516 34.056 183.6 ;
    END
  END c_d[77]
  PIN c_d[78]
    DIRECTION INPUT ;
    USE SIGNAL ;
    PORT
      LAYER M5 ;
        RECT  34.464 183.516 34.488 183.6 ;
    END
  END c_d[78]
  PIN c_d[79]
    DIRECTION INPUT ;
    USE SIGNAL ;
    PORT
      LAYER M5 ;
        RECT  34.896 183.516 34.92 183.6 ;
    END
  END c_d[79]
  PIN c_d[7]
    DIRECTION INPUT ;
    USE SIGNAL ;
    PORT
      LAYER M5 ;
        RECT  3.264 183.516 3.288 183.6 ;
    END
  END c_d[7]
  PIN c_d[80]
    DIRECTION INPUT ;
    USE SIGNAL ;
    PORT
      LAYER M5 ;
        RECT  35.376 183.516 35.4 183.6 ;
    END
  END c_d[80]
  PIN c_d[81]
    DIRECTION INPUT ;
    USE SIGNAL ;
    PORT
      LAYER M5 ;
        RECT  35.808 183.516 35.832 183.6 ;
    END
  END c_d[81]
  PIN c_d[82]
    DIRECTION INPUT ;
    USE SIGNAL ;
    PORT
      LAYER M5 ;
        RECT  36.24 183.516 36.264 183.6 ;
    END
  END c_d[82]
  PIN c_d[83]
    DIRECTION INPUT ;
    USE SIGNAL ;
    PORT
      LAYER M5 ;
        RECT  36.672 183.516 36.696 183.6 ;
    END
  END c_d[83]
  PIN c_d[84]
    DIRECTION INPUT ;
    USE SIGNAL ;
    PORT
      LAYER M5 ;
        RECT  37.104 183.516 37.128 183.6 ;
    END
  END c_d[84]
  PIN c_d[85]
    DIRECTION INPUT ;
    USE SIGNAL ;
    PORT
      LAYER M5 ;
        RECT  37.536 183.516 37.56 183.6 ;
    END
  END c_d[85]
  PIN c_d[86]
    DIRECTION INPUT ;
    USE SIGNAL ;
    PORT
      LAYER M5 ;
        RECT  37.968 183.516 37.992 183.6 ;
    END
  END c_d[86]
  PIN c_d[87]
    DIRECTION INPUT ;
    USE SIGNAL ;
    PORT
      LAYER M5 ;
        RECT  38.448 183.516 38.472 183.6 ;
    END
  END c_d[87]
  PIN c_d[88]
    DIRECTION INPUT ;
    USE SIGNAL ;
    PORT
      LAYER M5 ;
        RECT  38.88 183.516 38.904 183.6 ;
    END
  END c_d[88]
  PIN c_d[89]
    DIRECTION INPUT ;
    USE SIGNAL ;
    PORT
      LAYER M5 ;
        RECT  39.312 183.516 39.336 183.6 ;
    END
  END c_d[89]
  PIN c_d[8]
    DIRECTION INPUT ;
    USE SIGNAL ;
    PORT
      LAYER M5 ;
        RECT  3.744 183.516 3.768 183.6 ;
    END
  END c_d[8]
  PIN c_d[90]
    DIRECTION INPUT ;
    USE SIGNAL ;
    PORT
      LAYER M5 ;
        RECT  39.744 183.516 39.768 183.6 ;
    END
  END c_d[90]
  PIN c_d[91]
    DIRECTION INPUT ;
    USE SIGNAL ;
    PORT
      LAYER M5 ;
        RECT  40.176 183.516 40.2 183.6 ;
    END
  END c_d[91]
  PIN c_d[92]
    DIRECTION INPUT ;
    USE SIGNAL ;
    PORT
      LAYER M5 ;
        RECT  40.608 183.516 40.632 183.6 ;
    END
  END c_d[92]
  PIN c_d[93]
    DIRECTION INPUT ;
    USE SIGNAL ;
    PORT
      LAYER M5 ;
        RECT  41.088 183.516 41.112 183.6 ;
    END
  END c_d[93]
  PIN c_d[94]
    DIRECTION INPUT ;
    USE SIGNAL ;
    PORT
      LAYER M5 ;
        RECT  41.52 183.516 41.544 183.6 ;
    END
  END c_d[94]
  PIN c_d[95]
    DIRECTION INPUT ;
    USE SIGNAL ;
    PORT
      LAYER M5 ;
        RECT  41.952 183.516 41.976 183.6 ;
    END
  END c_d[95]
  PIN c_d[96]
    DIRECTION INPUT ;
    USE SIGNAL ;
    PORT
      LAYER M7 ;
        RECT  42.368 183.53 42.4 183.6 ;
    END
  END c_d[96]
  PIN c_d[97]
    DIRECTION INPUT ;
    USE SIGNAL ;
    PORT
      LAYER M7 ;
        RECT  42.816 183.53 42.848 183.6 ;
    END
  END c_d[97]
  PIN c_d[98]
    DIRECTION INPUT ;
    USE SIGNAL ;
    PORT
      LAYER M7 ;
        RECT  43.264 183.53 43.296 183.6 ;
    END
  END c_d[98]
  PIN c_d[99]
    DIRECTION INPUT ;
    USE SIGNAL ;
    PORT
      LAYER M7 ;
        RECT  43.712 183.53 43.744 183.6 ;
    END
  END c_d[99]
  PIN c_d[9]
    DIRECTION INPUT ;
    USE SIGNAL ;
    PORT
      LAYER M5 ;
        RECT  4.176 183.516 4.2 183.6 ;
    END
  END c_d[9]
  PIN c_lane[0]
    DIRECTION INPUT ;
    USE SIGNAL ;
    PORT
      LAYER M5 ;
        RECT  112.656 183.516 112.68 183.6 ;
    END
  END c_lane[0]
  PIN c_lane[1]
    DIRECTION INPUT ;
    USE SIGNAL ;
    PORT
      LAYER M5 ;
        RECT  113.136 183.516 113.16 183.6 ;
    END
  END c_lane[1]
  PIN c_lane[2]
    DIRECTION INPUT ;
    USE SIGNAL ;
    PORT
      LAYER M5 ;
        RECT  113.568 183.516 113.592 183.6 ;
    END
  END c_lane[2]
  PIN c_sec[0]
    DIRECTION INPUT ;
    USE SIGNAL ;
    PORT
      LAYER M5 ;
        RECT  114 183.516 114.024 183.6 ;
    END
  END c_sec[0]
  PIN c_sec[10]
    DIRECTION INPUT ;
    USE SIGNAL ;
    PORT
      LAYER M5 ;
        RECT  118.368 183.516 118.392 183.6 ;
    END
  END c_sec[10]
  PIN c_sec[11]
    DIRECTION INPUT ;
    USE SIGNAL ;
    PORT
      LAYER M5 ;
        RECT  118.848 183.516 118.872 183.6 ;
    END
  END c_sec[11]
  PIN c_sec[12]
    DIRECTION INPUT ;
    USE SIGNAL ;
    PORT
      LAYER M5 ;
        RECT  119.28 183.516 119.304 183.6 ;
    END
  END c_sec[12]
  PIN c_sec[13]
    DIRECTION INPUT ;
    USE SIGNAL ;
    PORT
      LAYER M5 ;
        RECT  119.712 183.516 119.736 183.6 ;
    END
  END c_sec[13]
  PIN c_sec[14]
    DIRECTION INPUT ;
    USE SIGNAL ;
    PORT
      LAYER M5 ;
        RECT  120.144 183.516 120.168 183.6 ;
    END
  END c_sec[14]
  PIN c_sec[15]
    DIRECTION INPUT ;
    USE SIGNAL ;
    PORT
      LAYER M5 ;
        RECT  120.576 183.516 120.6 183.6 ;
    END
  END c_sec[15]
  PIN c_sec[16]
    DIRECTION INPUT ;
    USE SIGNAL ;
    PORT
      LAYER M5 ;
        RECT  121.008 183.516 121.032 183.6 ;
    END
  END c_sec[16]
  PIN c_sec[17]
    DIRECTION INPUT ;
    USE SIGNAL ;
    PORT
      LAYER M5 ;
        RECT  121.44 183.516 121.464 183.6 ;
    END
  END c_sec[17]
  PIN c_sec[18]
    DIRECTION INPUT ;
    USE SIGNAL ;
    PORT
      LAYER M5 ;
        RECT  121.92 183.516 121.944 183.6 ;
    END
  END c_sec[18]
  PIN c_sec[19]
    DIRECTION INPUT ;
    USE SIGNAL ;
    PORT
      LAYER M5 ;
        RECT  122.352 183.516 122.376 183.6 ;
    END
  END c_sec[19]
  PIN c_sec[1]
    DIRECTION INPUT ;
    USE SIGNAL ;
    PORT
      LAYER M5 ;
        RECT  114.432 183.516 114.456 183.6 ;
    END
  END c_sec[1]
  PIN c_sec[20]
    DIRECTION INPUT ;
    USE SIGNAL ;
    PORT
      LAYER M5 ;
        RECT  122.784 183.516 122.808 183.6 ;
    END
  END c_sec[20]
  PIN c_sec[21]
    DIRECTION INPUT ;
    USE SIGNAL ;
    PORT
      LAYER M5 ;
        RECT  123.216 183.516 123.24 183.6 ;
    END
  END c_sec[21]
  PIN c_sec[22]
    DIRECTION INPUT ;
    USE SIGNAL ;
    PORT
      LAYER M5 ;
        RECT  123.648 183.516 123.672 183.6 ;
    END
  END c_sec[22]
  PIN c_sec[23]
    DIRECTION INPUT ;
    USE SIGNAL ;
    PORT
      LAYER M5 ;
        RECT  124.08 183.516 124.104 183.6 ;
    END
  END c_sec[23]
  PIN c_sec[2]
    DIRECTION INPUT ;
    USE SIGNAL ;
    PORT
      LAYER M5 ;
        RECT  114.864 183.516 114.888 183.6 ;
    END
  END c_sec[2]
  PIN c_sec[3]
    DIRECTION INPUT ;
    USE SIGNAL ;
    PORT
      LAYER M5 ;
        RECT  115.296 183.516 115.32 183.6 ;
    END
  END c_sec[3]
  PIN c_sec[4]
    DIRECTION INPUT ;
    USE SIGNAL ;
    PORT
      LAYER M5 ;
        RECT  115.728 183.516 115.752 183.6 ;
    END
  END c_sec[4]
  PIN c_sec[5]
    DIRECTION INPUT ;
    USE SIGNAL ;
    PORT
      LAYER M5 ;
        RECT  116.208 183.516 116.232 183.6 ;
    END
  END c_sec[5]
  PIN c_sec[6]
    DIRECTION INPUT ;
    USE SIGNAL ;
    PORT
      LAYER M5 ;
        RECT  116.64 183.516 116.664 183.6 ;
    END
  END c_sec[6]
  PIN c_sec[7]
    DIRECTION INPUT ;
    USE SIGNAL ;
    PORT
      LAYER M5 ;
        RECT  117.072 183.516 117.096 183.6 ;
    END
  END c_sec[7]
  PIN c_sec[8]
    DIRECTION INPUT ;
    USE SIGNAL ;
    PORT
      LAYER M5 ;
        RECT  117.504 183.516 117.528 183.6 ;
    END
  END c_sec[8]
  PIN c_sec[9]
    DIRECTION INPUT ;
    USE SIGNAL ;
    PORT
      LAYER M5 ;
        RECT  117.936 183.516 117.96 183.6 ;
    END
  END c_sec[9]
  PIN c_tag[0]
    DIRECTION INPUT ;
    USE SIGNAL ;
    PORT
      LAYER M5 ;
        RECT  124.56 183.516 124.584 183.6 ;
    END
  END c_tag[0]
  PIN c_tag[1]
    DIRECTION INPUT ;
    USE SIGNAL ;
    PORT
      LAYER M5 ;
        RECT  124.992 183.516 125.016 183.6 ;
    END
  END c_tag[1]
  PIN c_tag[2]
    DIRECTION INPUT ;
    USE SIGNAL ;
    PORT
      LAYER M5 ;
        RECT  125.424 183.516 125.448 183.6 ;
    END
  END c_tag[2]
  PIN c_tag[3]
    DIRECTION INPUT ;
    USE SIGNAL ;
    PORT
      LAYER M5 ;
        RECT  125.856 183.516 125.88 183.6 ;
    END
  END c_tag[3]
  PIN c_tag[4]
    DIRECTION INPUT ;
    USE SIGNAL ;
    PORT
      LAYER M5 ;
        RECT  126.288 183.516 126.312 183.6 ;
    END
  END c_tag[4]
  PIN c_tag[5]
    DIRECTION INPUT ;
    USE SIGNAL ;
    PORT
      LAYER M7 ;
        RECT  126.72 183.53 126.752 183.6 ;
    END
  END c_tag[5]
  PIN c_tag[6]
    DIRECTION INPUT ;
    USE SIGNAL ;
    PORT
      LAYER M7 ;
        RECT  127.168 183.53 127.2 183.6 ;
    END
  END c_tag[6]
  PIN c_tag[7]
    DIRECTION INPUT ;
    USE SIGNAL ;
    PORT
      LAYER M7 ;
        RECT  127.616 183.53 127.648 183.6 ;
    END
  END c_tag[7]
  PIN c_tag[8]
    DIRECTION INPUT ;
    USE SIGNAL ;
    PORT
      LAYER M7 ;
        RECT  128.064 183.53 128.096 183.6 ;
    END
  END c_tag[8]
  PIN c_v
    DIRECTION INPUT ;
    USE SIGNAL ;
    PORT
      LAYER M7 ;
        RECT  128.512 183.53 128.544 183.6 ;
    END
  END c_v
  PIN clk
    DIRECTION INPUT ;
    USE SIGNAL ;
    PORT
      LAYER M4 ;
        RECT  129.516 88.752 129.6 88.776 ;
    END
  END clk
  PIN dn_bad
    DIRECTION INPUT ;
    USE SIGNAL ;
    PORT
      LAYER M5 ;
        RECT  0.24 0 0.264 0.084 ;
    END
  END dn_bad
  PIN dn_v
    DIRECTION INPUT ;
    USE SIGNAL ;
    PORT
      LAYER M5 ;
        RECT  0.672 0 0.696 0.084 ;
    END
  END dn_v
  PIN dp_bad
    DIRECTION OUTPUT ;
    USE SIGNAL ;
    PORT
      LAYER M7 ;
        RECT  128.896 183.53 128.928 183.6 ;
    END
  END dp_bad
  PIN dp_v
    DIRECTION OUTPUT ;
    USE SIGNAL ;
    PORT
      LAYER M7 ;
        RECT  129.344 183.53 129.376 183.6 ;
    END
  END dp_v
  PIN lane[0]
    DIRECTION INPUT ;
    USE SIGNAL ;
    PORT
      LAYER M4 ;
        RECT  129.516 126.672 129.6 126.696 ;
    END
  END lane[0]
  PIN lane[1]
    DIRECTION INPUT ;
    USE SIGNAL ;
    PORT
      LAYER M4 ;
        RECT  129.516 139.968 129.6 139.992 ;
    END
  END lane[1]
  PIN lane[2]
    DIRECTION INPUT ;
    USE SIGNAL ;
    PORT
      LAYER M4 ;
        RECT  129.516 153.312 129.6 153.336 ;
    END
  END lane[2]
  PIN n_d[0]
    DIRECTION OUTPUT ;
    USE SIGNAL ;
    PORT
      LAYER M5 ;
        RECT  1.104 0 1.128 0.084 ;
    END
  END n_d[0]
  PIN n_d[100]
    DIRECTION OUTPUT ;
    USE SIGNAL ;
    PORT
      LAYER M7 ;
        RECT  45.056 0 45.088 0.07 ;
    END
  END n_d[100]
  PIN n_d[101]
    DIRECTION OUTPUT ;
    USE SIGNAL ;
    PORT
      LAYER M7 ;
        RECT  45.504 0 45.536 0.07 ;
    END
  END n_d[101]
  PIN n_d[102]
    DIRECTION OUTPUT ;
    USE SIGNAL ;
    PORT
      LAYER M7 ;
        RECT  45.888 0 45.92 0.07 ;
    END
  END n_d[102]
  PIN n_d[103]
    DIRECTION OUTPUT ;
    USE SIGNAL ;
    PORT
      LAYER M7 ;
        RECT  46.336 0 46.368 0.07 ;
    END
  END n_d[103]
  PIN n_d[104]
    DIRECTION OUTPUT ;
    USE SIGNAL ;
    PORT
      LAYER M7 ;
        RECT  46.784 0 46.816 0.07 ;
    END
  END n_d[104]
  PIN n_d[105]
    DIRECTION OUTPUT ;
    USE SIGNAL ;
    PORT
      LAYER M7 ;
        RECT  47.232 0 47.264 0.07 ;
    END
  END n_d[105]
  PIN n_d[106]
    DIRECTION OUTPUT ;
    USE SIGNAL ;
    PORT
      LAYER M7 ;
        RECT  47.68 0 47.712 0.07 ;
    END
  END n_d[106]
  PIN n_d[107]
    DIRECTION OUTPUT ;
    USE SIGNAL ;
    PORT
      LAYER M7 ;
        RECT  48.064 0 48.096 0.07 ;
    END
  END n_d[107]
  PIN n_d[108]
    DIRECTION OUTPUT ;
    USE SIGNAL ;
    PORT
      LAYER M7 ;
        RECT  48.512 0 48.544 0.07 ;
    END
  END n_d[108]
  PIN n_d[109]
    DIRECTION OUTPUT ;
    USE SIGNAL ;
    PORT
      LAYER M7 ;
        RECT  48.96 0 48.992 0.07 ;
    END
  END n_d[109]
  PIN n_d[10]
    DIRECTION OUTPUT ;
    USE SIGNAL ;
    PORT
      LAYER M5 ;
        RECT  5.472 0 5.496 0.084 ;
    END
  END n_d[10]
  PIN n_d[110]
    DIRECTION OUTPUT ;
    USE SIGNAL ;
    PORT
      LAYER M7 ;
        RECT  49.408 0 49.44 0.07 ;
    END
  END n_d[110]
  PIN n_d[111]
    DIRECTION OUTPUT ;
    USE SIGNAL ;
    PORT
      LAYER M7 ;
        RECT  49.856 0 49.888 0.07 ;
    END
  END n_d[111]
  PIN n_d[112]
    DIRECTION OUTPUT ;
    USE SIGNAL ;
    PORT
      LAYER M7 ;
        RECT  50.304 0 50.336 0.07 ;
    END
  END n_d[112]
  PIN n_d[113]
    DIRECTION OUTPUT ;
    USE SIGNAL ;
    PORT
      LAYER M7 ;
        RECT  50.752 0 50.784 0.07 ;
    END
  END n_d[113]
  PIN n_d[114]
    DIRECTION OUTPUT ;
    USE SIGNAL ;
    PORT
      LAYER M7 ;
        RECT  51.136 0 51.168 0.07 ;
    END
  END n_d[114]
  PIN n_d[115]
    DIRECTION OUTPUT ;
    USE SIGNAL ;
    PORT
      LAYER M7 ;
        RECT  51.584 0 51.616 0.07 ;
    END
  END n_d[115]
  PIN n_d[116]
    DIRECTION OUTPUT ;
    USE SIGNAL ;
    PORT
      LAYER M7 ;
        RECT  52.032 0 52.064 0.07 ;
    END
  END n_d[116]
  PIN n_d[117]
    DIRECTION OUTPUT ;
    USE SIGNAL ;
    PORT
      LAYER M7 ;
        RECT  52.48 0 52.512 0.07 ;
    END
  END n_d[117]
  PIN n_d[118]
    DIRECTION OUTPUT ;
    USE SIGNAL ;
    PORT
      LAYER M7 ;
        RECT  52.928 0 52.96 0.07 ;
    END
  END n_d[118]
  PIN n_d[119]
    DIRECTION OUTPUT ;
    USE SIGNAL ;
    PORT
      LAYER M7 ;
        RECT  53.376 0 53.408 0.07 ;
    END
  END n_d[119]
  PIN n_d[11]
    DIRECTION OUTPUT ;
    USE SIGNAL ;
    PORT
      LAYER M5 ;
        RECT  5.904 0 5.928 0.084 ;
    END
  END n_d[11]
  PIN n_d[120]
    DIRECTION OUTPUT ;
    USE SIGNAL ;
    PORT
      LAYER M7 ;
        RECT  53.824 0 53.856 0.07 ;
    END
  END n_d[120]
  PIN n_d[121]
    DIRECTION OUTPUT ;
    USE SIGNAL ;
    PORT
      LAYER M7 ;
        RECT  54.272 0 54.304 0.07 ;
    END
  END n_d[121]
  PIN n_d[122]
    DIRECTION OUTPUT ;
    USE SIGNAL ;
    PORT
      LAYER M7 ;
        RECT  54.656 0 54.688 0.07 ;
    END
  END n_d[122]
  PIN n_d[123]
    DIRECTION OUTPUT ;
    USE SIGNAL ;
    PORT
      LAYER M7 ;
        RECT  55.104 0 55.136 0.07 ;
    END
  END n_d[123]
  PIN n_d[124]
    DIRECTION OUTPUT ;
    USE SIGNAL ;
    PORT
      LAYER M7 ;
        RECT  55.552 0 55.584 0.07 ;
    END
  END n_d[124]
  PIN n_d[125]
    DIRECTION OUTPUT ;
    USE SIGNAL ;
    PORT
      LAYER M7 ;
        RECT  56 0 56.032 0.07 ;
    END
  END n_d[125]
  PIN n_d[126]
    DIRECTION OUTPUT ;
    USE SIGNAL ;
    PORT
      LAYER M5 ;
        RECT  56.448 0 56.472 0.084 ;
    END
  END n_d[126]
  PIN n_d[127]
    DIRECTION OUTPUT ;
    USE SIGNAL ;
    PORT
      LAYER M5 ;
        RECT  56.88 0 56.904 0.084 ;
    END
  END n_d[127]
  PIN n_d[128]
    DIRECTION OUTPUT ;
    USE SIGNAL ;
    PORT
      LAYER M5 ;
        RECT  57.312 0 57.336 0.084 ;
    END
  END n_d[128]
  PIN n_d[129]
    DIRECTION OUTPUT ;
    USE SIGNAL ;
    PORT
      LAYER M5 ;
        RECT  57.744 0 57.768 0.084 ;
    END
  END n_d[129]
  PIN n_d[12]
    DIRECTION OUTPUT ;
    USE SIGNAL ;
    PORT
      LAYER M5 ;
        RECT  6.336 0 6.36 0.084 ;
    END
  END n_d[12]
  PIN n_d[130]
    DIRECTION OUTPUT ;
    USE SIGNAL ;
    PORT
      LAYER M5 ;
        RECT  58.176 0 58.2 0.084 ;
    END
  END n_d[130]
  PIN n_d[131]
    DIRECTION OUTPUT ;
    USE SIGNAL ;
    PORT
      LAYER M5 ;
        RECT  58.656 0 58.68 0.084 ;
    END
  END n_d[131]
  PIN n_d[132]
    DIRECTION OUTPUT ;
    USE SIGNAL ;
    PORT
      LAYER M5 ;
        RECT  59.088 0 59.112 0.084 ;
    END
  END n_d[132]
  PIN n_d[133]
    DIRECTION OUTPUT ;
    USE SIGNAL ;
    PORT
      LAYER M5 ;
        RECT  59.52 0 59.544 0.084 ;
    END
  END n_d[133]
  PIN n_d[134]
    DIRECTION OUTPUT ;
    USE SIGNAL ;
    PORT
      LAYER M5 ;
        RECT  59.952 0 59.976 0.084 ;
    END
  END n_d[134]
  PIN n_d[135]
    DIRECTION OUTPUT ;
    USE SIGNAL ;
    PORT
      LAYER M5 ;
        RECT  60.384 0 60.408 0.084 ;
    END
  END n_d[135]
  PIN n_d[136]
    DIRECTION OUTPUT ;
    USE SIGNAL ;
    PORT
      LAYER M5 ;
        RECT  60.816 0 60.84 0.084 ;
    END
  END n_d[136]
  PIN n_d[137]
    DIRECTION OUTPUT ;
    USE SIGNAL ;
    PORT
      LAYER M5 ;
        RECT  61.296 0 61.32 0.084 ;
    END
  END n_d[137]
  PIN n_d[138]
    DIRECTION OUTPUT ;
    USE SIGNAL ;
    PORT
      LAYER M5 ;
        RECT  61.728 0 61.752 0.084 ;
    END
  END n_d[138]
  PIN n_d[139]
    DIRECTION OUTPUT ;
    USE SIGNAL ;
    PORT
      LAYER M5 ;
        RECT  62.16 0 62.184 0.084 ;
    END
  END n_d[139]
  PIN n_d[13]
    DIRECTION OUTPUT ;
    USE SIGNAL ;
    PORT
      LAYER M5 ;
        RECT  6.816 0 6.84 0.084 ;
    END
  END n_d[13]
  PIN n_d[140]
    DIRECTION OUTPUT ;
    USE SIGNAL ;
    PORT
      LAYER M5 ;
        RECT  62.592 0 62.616 0.084 ;
    END
  END n_d[140]
  PIN n_d[141]
    DIRECTION OUTPUT ;
    USE SIGNAL ;
    PORT
      LAYER M5 ;
        RECT  63.024 0 63.048 0.084 ;
    END
  END n_d[141]
  PIN n_d[142]
    DIRECTION OUTPUT ;
    USE SIGNAL ;
    PORT
      LAYER M5 ;
        RECT  63.456 0 63.48 0.084 ;
    END
  END n_d[142]
  PIN n_d[143]
    DIRECTION OUTPUT ;
    USE SIGNAL ;
    PORT
      LAYER M5 ;
        RECT  63.888 0 63.912 0.084 ;
    END
  END n_d[143]
  PIN n_d[144]
    DIRECTION OUTPUT ;
    USE SIGNAL ;
    PORT
      LAYER M5 ;
        RECT  64.416 0 64.44 0.084 ;
    END
  END n_d[144]
  PIN n_d[145]
    DIRECTION OUTPUT ;
    USE SIGNAL ;
    PORT
      LAYER M5 ;
        RECT  64.848 0 64.872 0.084 ;
    END
  END n_d[145]
  PIN n_d[146]
    DIRECTION OUTPUT ;
    USE SIGNAL ;
    PORT
      LAYER M5 ;
        RECT  65.28 0 65.304 0.084 ;
    END
  END n_d[146]
  PIN n_d[147]
    DIRECTION OUTPUT ;
    USE SIGNAL ;
    PORT
      LAYER M5 ;
        RECT  65.712 0 65.736 0.084 ;
    END
  END n_d[147]
  PIN n_d[148]
    DIRECTION OUTPUT ;
    USE SIGNAL ;
    PORT
      LAYER M5 ;
        RECT  66.144 0 66.168 0.084 ;
    END
  END n_d[148]
  PIN n_d[149]
    DIRECTION OUTPUT ;
    USE SIGNAL ;
    PORT
      LAYER M5 ;
        RECT  66.576 0 66.6 0.084 ;
    END
  END n_d[149]
  PIN n_d[14]
    DIRECTION OUTPUT ;
    USE SIGNAL ;
    PORT
      LAYER M5 ;
        RECT  7.248 0 7.272 0.084 ;
    END
  END n_d[14]
  PIN n_d[150]
    DIRECTION OUTPUT ;
    USE SIGNAL ;
    PORT
      LAYER M5 ;
        RECT  67.008 0 67.032 0.084 ;
    END
  END n_d[150]
  PIN n_d[151]
    DIRECTION OUTPUT ;
    USE SIGNAL ;
    PORT
      LAYER M5 ;
        RECT  67.44 0 67.464 0.084 ;
    END
  END n_d[151]
  PIN n_d[152]
    DIRECTION OUTPUT ;
    USE SIGNAL ;
    PORT
      LAYER M5 ;
        RECT  67.872 0 67.896 0.084 ;
    END
  END n_d[152]
  PIN n_d[153]
    DIRECTION OUTPUT ;
    USE SIGNAL ;
    PORT
      LAYER M5 ;
        RECT  68.304 0 68.328 0.084 ;
    END
  END n_d[153]
  PIN n_d[154]
    DIRECTION OUTPUT ;
    USE SIGNAL ;
    PORT
      LAYER M5 ;
        RECT  68.736 0 68.76 0.084 ;
    END
  END n_d[154]
  PIN n_d[155]
    DIRECTION OUTPUT ;
    USE SIGNAL ;
    PORT
      LAYER M5 ;
        RECT  69.168 0 69.192 0.084 ;
    END
  END n_d[155]
  PIN n_d[156]
    DIRECTION OUTPUT ;
    USE SIGNAL ;
    PORT
      LAYER M5 ;
        RECT  69.6 0 69.624 0.084 ;
    END
  END n_d[156]
  PIN n_d[157]
    DIRECTION OUTPUT ;
    USE SIGNAL ;
    PORT
      LAYER M5 ;
        RECT  70.08 0 70.104 0.084 ;
    END
  END n_d[157]
  PIN n_d[158]
    DIRECTION OUTPUT ;
    USE SIGNAL ;
    PORT
      LAYER M7 ;
        RECT  70.464 0 70.496 0.07 ;
    END
  END n_d[158]
  PIN n_d[159]
    DIRECTION OUTPUT ;
    USE SIGNAL ;
    PORT
      LAYER M7 ;
        RECT  70.912 0 70.944 0.07 ;
    END
  END n_d[159]
  PIN n_d[15]
    DIRECTION OUTPUT ;
    USE SIGNAL ;
    PORT
      LAYER M5 ;
        RECT  7.68 0 7.704 0.084 ;
    END
  END n_d[15]
  PIN n_d[160]
    DIRECTION OUTPUT ;
    USE SIGNAL ;
    PORT
      LAYER M7 ;
        RECT  71.36 0 71.392 0.07 ;
    END
  END n_d[160]
  PIN n_d[161]
    DIRECTION OUTPUT ;
    USE SIGNAL ;
    PORT
      LAYER M7 ;
        RECT  71.808 0 71.84 0.07 ;
    END
  END n_d[161]
  PIN n_d[162]
    DIRECTION OUTPUT ;
    USE SIGNAL ;
    PORT
      LAYER M7 ;
        RECT  72.256 0 72.288 0.07 ;
    END
  END n_d[162]
  PIN n_d[163]
    DIRECTION OUTPUT ;
    USE SIGNAL ;
    PORT
      LAYER M7 ;
        RECT  72.704 0 72.736 0.07 ;
    END
  END n_d[163]
  PIN n_d[164]
    DIRECTION OUTPUT ;
    USE SIGNAL ;
    PORT
      LAYER M7 ;
        RECT  73.152 0 73.184 0.07 ;
    END
  END n_d[164]
  PIN n_d[165]
    DIRECTION OUTPUT ;
    USE SIGNAL ;
    PORT
      LAYER M7 ;
        RECT  73.6 0 73.632 0.07 ;
    END
  END n_d[165]
  PIN n_d[166]
    DIRECTION OUTPUT ;
    USE SIGNAL ;
    PORT
      LAYER M7 ;
        RECT  73.984 0 74.016 0.07 ;
    END
  END n_d[166]
  PIN n_d[167]
    DIRECTION OUTPUT ;
    USE SIGNAL ;
    PORT
      LAYER M7 ;
        RECT  74.432 0 74.464 0.07 ;
    END
  END n_d[167]
  PIN n_d[168]
    DIRECTION OUTPUT ;
    USE SIGNAL ;
    PORT
      LAYER M7 ;
        RECT  74.88 0 74.912 0.07 ;
    END
  END n_d[168]
  PIN n_d[169]
    DIRECTION OUTPUT ;
    USE SIGNAL ;
    PORT
      LAYER M7 ;
        RECT  75.328 0 75.36 0.07 ;
    END
  END n_d[169]
  PIN n_d[16]
    DIRECTION OUTPUT ;
    USE SIGNAL ;
    PORT
      LAYER M5 ;
        RECT  8.112 0 8.136 0.084 ;
    END
  END n_d[16]
  PIN n_d[170]
    DIRECTION OUTPUT ;
    USE SIGNAL ;
    PORT
      LAYER M7 ;
        RECT  75.776 0 75.808 0.07 ;
    END
  END n_d[170]
  PIN n_d[171]
    DIRECTION OUTPUT ;
    USE SIGNAL ;
    PORT
      LAYER M7 ;
        RECT  76.224 0 76.256 0.07 ;
    END
  END n_d[171]
  PIN n_d[172]
    DIRECTION OUTPUT ;
    USE SIGNAL ;
    PORT
      LAYER M7 ;
        RECT  76.672 0 76.704 0.07 ;
    END
  END n_d[172]
  PIN n_d[173]
    DIRECTION OUTPUT ;
    USE SIGNAL ;
    PORT
      LAYER M7 ;
        RECT  77.056 0 77.088 0.07 ;
    END
  END n_d[173]
  PIN n_d[174]
    DIRECTION OUTPUT ;
    USE SIGNAL ;
    PORT
      LAYER M7 ;
        RECT  77.504 0 77.536 0.07 ;
    END
  END n_d[174]
  PIN n_d[175]
    DIRECTION OUTPUT ;
    USE SIGNAL ;
    PORT
      LAYER M7 ;
        RECT  77.952 0 77.984 0.07 ;
    END
  END n_d[175]
  PIN n_d[176]
    DIRECTION OUTPUT ;
    USE SIGNAL ;
    PORT
      LAYER M7 ;
        RECT  78.4 0 78.432 0.07 ;
    END
  END n_d[176]
  PIN n_d[177]
    DIRECTION OUTPUT ;
    USE SIGNAL ;
    PORT
      LAYER M7 ;
        RECT  78.848 0 78.88 0.07 ;
    END
  END n_d[177]
  PIN n_d[178]
    DIRECTION OUTPUT ;
    USE SIGNAL ;
    PORT
      LAYER M7 ;
        RECT  79.296 0 79.328 0.07 ;
    END
  END n_d[178]
  PIN n_d[179]
    DIRECTION OUTPUT ;
    USE SIGNAL ;
    PORT
      LAYER M7 ;
        RECT  79.744 0 79.776 0.07 ;
    END
  END n_d[179]
  PIN n_d[17]
    DIRECTION OUTPUT ;
    USE SIGNAL ;
    PORT
      LAYER M5 ;
        RECT  8.544 0 8.568 0.084 ;
    END
  END n_d[17]
  PIN n_d[180]
    DIRECTION OUTPUT ;
    USE SIGNAL ;
    PORT
      LAYER M7 ;
        RECT  80.192 0 80.224 0.07 ;
    END
  END n_d[180]
  PIN n_d[181]
    DIRECTION OUTPUT ;
    USE SIGNAL ;
    PORT
      LAYER M7 ;
        RECT  80.576 0 80.608 0.07 ;
    END
  END n_d[181]
  PIN n_d[182]
    DIRECTION OUTPUT ;
    USE SIGNAL ;
    PORT
      LAYER M7 ;
        RECT  81.024 0 81.056 0.07 ;
    END
  END n_d[182]
  PIN n_d[183]
    DIRECTION OUTPUT ;
    USE SIGNAL ;
    PORT
      LAYER M7 ;
        RECT  81.472 0 81.504 0.07 ;
    END
  END n_d[183]
  PIN n_d[184]
    DIRECTION OUTPUT ;
    USE SIGNAL ;
    PORT
      LAYER M7 ;
        RECT  81.92 0 81.952 0.07 ;
    END
  END n_d[184]
  PIN n_d[185]
    DIRECTION OUTPUT ;
    USE SIGNAL ;
    PORT
      LAYER M7 ;
        RECT  82.368 0 82.4 0.07 ;
    END
  END n_d[185]
  PIN n_d[186]
    DIRECTION OUTPUT ;
    USE SIGNAL ;
    PORT
      LAYER M7 ;
        RECT  82.816 0 82.848 0.07 ;
    END
  END n_d[186]
  PIN n_d[187]
    DIRECTION OUTPUT ;
    USE SIGNAL ;
    PORT
      LAYER M7 ;
        RECT  83.264 0 83.296 0.07 ;
    END
  END n_d[187]
  PIN n_d[188]
    DIRECTION OUTPUT ;
    USE SIGNAL ;
    PORT
      LAYER M7 ;
        RECT  83.648 0 83.68 0.07 ;
    END
  END n_d[188]
  PIN n_d[189]
    DIRECTION OUTPUT ;
    USE SIGNAL ;
    PORT
      LAYER M7 ;
        RECT  84.096 0 84.128 0.07 ;
    END
  END n_d[189]
  PIN n_d[18]
    DIRECTION OUTPUT ;
    USE SIGNAL ;
    PORT
      LAYER M5 ;
        RECT  8.976 0 9 0.084 ;
    END
  END n_d[18]
  PIN n_d[190]
    DIRECTION OUTPUT ;
    USE SIGNAL ;
    PORT
      LAYER M5 ;
        RECT  84.624 0 84.648 0.084 ;
    END
  END n_d[190]
  PIN n_d[191]
    DIRECTION OUTPUT ;
    USE SIGNAL ;
    PORT
      LAYER M5 ;
        RECT  85.056 0 85.08 0.084 ;
    END
  END n_d[191]
  PIN n_d[192]
    DIRECTION OUTPUT ;
    USE SIGNAL ;
    PORT
      LAYER M5 ;
        RECT  85.488 0 85.512 0.084 ;
    END
  END n_d[192]
  PIN n_d[193]
    DIRECTION OUTPUT ;
    USE SIGNAL ;
    PORT
      LAYER M5 ;
        RECT  85.92 0 85.944 0.084 ;
    END
  END n_d[193]
  PIN n_d[194]
    DIRECTION OUTPUT ;
    USE SIGNAL ;
    PORT
      LAYER M5 ;
        RECT  86.352 0 86.376 0.084 ;
    END
  END n_d[194]
  PIN n_d[195]
    DIRECTION OUTPUT ;
    USE SIGNAL ;
    PORT
      LAYER M5 ;
        RECT  86.784 0 86.808 0.084 ;
    END
  END n_d[195]
  PIN n_d[196]
    DIRECTION OUTPUT ;
    USE SIGNAL ;
    PORT
      LAYER M5 ;
        RECT  87.216 0 87.24 0.084 ;
    END
  END n_d[196]
  PIN n_d[197]
    DIRECTION OUTPUT ;
    USE SIGNAL ;
    PORT
      LAYER M5 ;
        RECT  87.648 0 87.672 0.084 ;
    END
  END n_d[197]
  PIN n_d[198]
    DIRECTION OUTPUT ;
    USE SIGNAL ;
    PORT
      LAYER M5 ;
        RECT  88.08 0 88.104 0.084 ;
    END
  END n_d[198]
  PIN n_d[199]
    DIRECTION OUTPUT ;
    USE SIGNAL ;
    PORT
      LAYER M5 ;
        RECT  88.512 0 88.536 0.084 ;
    END
  END n_d[199]
  PIN n_d[19]
    DIRECTION OUTPUT ;
    USE SIGNAL ;
    PORT
      LAYER M5 ;
        RECT  9.456 0 9.48 0.084 ;
    END
  END n_d[19]
  PIN n_d[1]
    DIRECTION OUTPUT ;
    USE SIGNAL ;
    PORT
      LAYER M5 ;
        RECT  1.536 0 1.56 0.084 ;
    END
  END n_d[1]
  PIN n_d[200]
    DIRECTION OUTPUT ;
    USE SIGNAL ;
    PORT
      LAYER M5 ;
        RECT  88.944 0 88.968 0.084 ;
    END
  END n_d[200]
  PIN n_d[201]
    DIRECTION OUTPUT ;
    USE SIGNAL ;
    PORT
      LAYER M5 ;
        RECT  89.376 0 89.4 0.084 ;
    END
  END n_d[201]
  PIN n_d[202]
    DIRECTION OUTPUT ;
    USE SIGNAL ;
    PORT
      LAYER M5 ;
        RECT  89.808 0 89.832 0.084 ;
    END
  END n_d[202]
  PIN n_d[203]
    DIRECTION OUTPUT ;
    USE SIGNAL ;
    PORT
      LAYER M5 ;
        RECT  90.288 0 90.312 0.084 ;
    END
  END n_d[203]
  PIN n_d[204]
    DIRECTION OUTPUT ;
    USE SIGNAL ;
    PORT
      LAYER M5 ;
        RECT  90.72 0 90.744 0.084 ;
    END
  END n_d[204]
  PIN n_d[205]
    DIRECTION OUTPUT ;
    USE SIGNAL ;
    PORT
      LAYER M5 ;
        RECT  91.152 0 91.176 0.084 ;
    END
  END n_d[205]
  PIN n_d[206]
    DIRECTION OUTPUT ;
    USE SIGNAL ;
    PORT
      LAYER M5 ;
        RECT  91.584 0 91.608 0.084 ;
    END
  END n_d[206]
  PIN n_d[207]
    DIRECTION OUTPUT ;
    USE SIGNAL ;
    PORT
      LAYER M5 ;
        RECT  92.016 0 92.04 0.084 ;
    END
  END n_d[207]
  PIN n_d[208]
    DIRECTION OUTPUT ;
    USE SIGNAL ;
    PORT
      LAYER M5 ;
        RECT  92.448 0 92.472 0.084 ;
    END
  END n_d[208]
  PIN n_d[209]
    DIRECTION OUTPUT ;
    USE SIGNAL ;
    PORT
      LAYER M5 ;
        RECT  92.928 0 92.952 0.084 ;
    END
  END n_d[209]
  PIN n_d[20]
    DIRECTION OUTPUT ;
    USE SIGNAL ;
    PORT
      LAYER M5 ;
        RECT  9.888 0 9.912 0.084 ;
    END
  END n_d[20]
  PIN n_d[210]
    DIRECTION OUTPUT ;
    USE SIGNAL ;
    PORT
      LAYER M5 ;
        RECT  93.36 0 93.384 0.084 ;
    END
  END n_d[210]
  PIN n_d[211]
    DIRECTION OUTPUT ;
    USE SIGNAL ;
    PORT
      LAYER M5 ;
        RECT  93.792 0 93.816 0.084 ;
    END
  END n_d[211]
  PIN n_d[212]
    DIRECTION OUTPUT ;
    USE SIGNAL ;
    PORT
      LAYER M5 ;
        RECT  94.224 0 94.248 0.084 ;
    END
  END n_d[212]
  PIN n_d[213]
    DIRECTION OUTPUT ;
    USE SIGNAL ;
    PORT
      LAYER M5 ;
        RECT  94.656 0 94.68 0.084 ;
    END
  END n_d[213]
  PIN n_d[214]
    DIRECTION OUTPUT ;
    USE SIGNAL ;
    PORT
      LAYER M5 ;
        RECT  95.088 0 95.112 0.084 ;
    END
  END n_d[214]
  PIN n_d[215]
    DIRECTION OUTPUT ;
    USE SIGNAL ;
    PORT
      LAYER M5 ;
        RECT  95.52 0 95.544 0.084 ;
    END
  END n_d[215]
  PIN n_d[216]
    DIRECTION OUTPUT ;
    USE SIGNAL ;
    PORT
      LAYER M5 ;
        RECT  96 0 96.024 0.084 ;
    END
  END n_d[216]
  PIN n_d[217]
    DIRECTION OUTPUT ;
    USE SIGNAL ;
    PORT
      LAYER M5 ;
        RECT  96.432 0 96.456 0.084 ;
    END
  END n_d[217]
  PIN n_d[218]
    DIRECTION OUTPUT ;
    USE SIGNAL ;
    PORT
      LAYER M5 ;
        RECT  96.864 0 96.888 0.084 ;
    END
  END n_d[218]
  PIN n_d[219]
    DIRECTION OUTPUT ;
    USE SIGNAL ;
    PORT
      LAYER M5 ;
        RECT  97.296 0 97.32 0.084 ;
    END
  END n_d[219]
  PIN n_d[21]
    DIRECTION OUTPUT ;
    USE SIGNAL ;
    PORT
      LAYER M5 ;
        RECT  10.32 0 10.344 0.084 ;
    END
  END n_d[21]
  PIN n_d[220]
    DIRECTION OUTPUT ;
    USE SIGNAL ;
    PORT
      LAYER M5 ;
        RECT  97.728 0 97.752 0.084 ;
    END
  END n_d[220]
  PIN n_d[221]
    DIRECTION OUTPUT ;
    USE SIGNAL ;
    PORT
      LAYER M5 ;
        RECT  98.16 0 98.184 0.084 ;
    END
  END n_d[221]
  PIN n_d[222]
    DIRECTION OUTPUT ;
    USE SIGNAL ;
    PORT
      LAYER M7 ;
        RECT  98.624 0 98.656 0.07 ;
    END
  END n_d[222]
  PIN n_d[223]
    DIRECTION OUTPUT ;
    USE SIGNAL ;
    PORT
      LAYER M7 ;
        RECT  99.072 0 99.104 0.07 ;
    END
  END n_d[223]
  PIN n_d[224]
    DIRECTION OUTPUT ;
    USE SIGNAL ;
    PORT
      LAYER M7 ;
        RECT  99.52 0 99.552 0.07 ;
    END
  END n_d[224]
  PIN n_d[225]
    DIRECTION OUTPUT ;
    USE SIGNAL ;
    PORT
      LAYER M7 ;
        RECT  99.904 0 99.936 0.07 ;
    END
  END n_d[225]
  PIN n_d[226]
    DIRECTION OUTPUT ;
    USE SIGNAL ;
    PORT
      LAYER M7 ;
        RECT  100.352 0 100.384 0.07 ;
    END
  END n_d[226]
  PIN n_d[227]
    DIRECTION OUTPUT ;
    USE SIGNAL ;
    PORT
      LAYER M7 ;
        RECT  100.8 0 100.832 0.07 ;
    END
  END n_d[227]
  PIN n_d[228]
    DIRECTION OUTPUT ;
    USE SIGNAL ;
    PORT
      LAYER M7 ;
        RECT  101.248 0 101.28 0.07 ;
    END
  END n_d[228]
  PIN n_d[229]
    DIRECTION OUTPUT ;
    USE SIGNAL ;
    PORT
      LAYER M7 ;
        RECT  101.696 0 101.728 0.07 ;
    END
  END n_d[229]
  PIN n_d[22]
    DIRECTION OUTPUT ;
    USE SIGNAL ;
    PORT
      LAYER M5 ;
        RECT  10.752 0 10.776 0.084 ;
    END
  END n_d[22]
  PIN n_d[230]
    DIRECTION OUTPUT ;
    USE SIGNAL ;
    PORT
      LAYER M7 ;
        RECT  102.144 0 102.176 0.07 ;
    END
  END n_d[230]
  PIN n_d[231]
    DIRECTION OUTPUT ;
    USE SIGNAL ;
    PORT
      LAYER M7 ;
        RECT  102.592 0 102.624 0.07 ;
    END
  END n_d[231]
  PIN n_d[232]
    DIRECTION OUTPUT ;
    USE SIGNAL ;
    PORT
      LAYER M7 ;
        RECT  102.976 0 103.008 0.07 ;
    END
  END n_d[232]
  PIN n_d[233]
    DIRECTION OUTPUT ;
    USE SIGNAL ;
    PORT
      LAYER M7 ;
        RECT  103.424 0 103.456 0.07 ;
    END
  END n_d[233]
  PIN n_d[234]
    DIRECTION OUTPUT ;
    USE SIGNAL ;
    PORT
      LAYER M7 ;
        RECT  103.872 0 103.904 0.07 ;
    END
  END n_d[234]
  PIN n_d[235]
    DIRECTION OUTPUT ;
    USE SIGNAL ;
    PORT
      LAYER M7 ;
        RECT  104.32 0 104.352 0.07 ;
    END
  END n_d[235]
  PIN n_d[236]
    DIRECTION OUTPUT ;
    USE SIGNAL ;
    PORT
      LAYER M7 ;
        RECT  104.768 0 104.8 0.07 ;
    END
  END n_d[236]
  PIN n_d[237]
    DIRECTION OUTPUT ;
    USE SIGNAL ;
    PORT
      LAYER M7 ;
        RECT  105.216 0 105.248 0.07 ;
    END
  END n_d[237]
  PIN n_d[238]
    DIRECTION OUTPUT ;
    USE SIGNAL ;
    PORT
      LAYER M7 ;
        RECT  105.728 0 105.76 0.07 ;
    END
  END n_d[238]
  PIN n_d[239]
    DIRECTION OUTPUT ;
    USE SIGNAL ;
    PORT
      LAYER M7 ;
        RECT  106.176 0 106.208 0.07 ;
    END
  END n_d[239]
  PIN n_d[23]
    DIRECTION OUTPUT ;
    USE SIGNAL ;
    PORT
      LAYER M5 ;
        RECT  11.184 0 11.208 0.084 ;
    END
  END n_d[23]
  PIN n_d[240]
    DIRECTION OUTPUT ;
    USE SIGNAL ;
    PORT
      LAYER M7 ;
        RECT  106.496 0 106.528 0.07 ;
    END
  END n_d[240]
  PIN n_d[241]
    DIRECTION OUTPUT ;
    USE SIGNAL ;
    PORT
      LAYER M7 ;
        RECT  106.944 0 106.976 0.07 ;
    END
  END n_d[241]
  PIN n_d[242]
    DIRECTION OUTPUT ;
    USE SIGNAL ;
    PORT
      LAYER M7 ;
        RECT  107.456 0 107.488 0.07 ;
    END
  END n_d[242]
  PIN n_d[243]
    DIRECTION OUTPUT ;
    USE SIGNAL ;
    PORT
      LAYER M7 ;
        RECT  107.904 0 107.936 0.07 ;
    END
  END n_d[243]
  PIN n_d[244]
    DIRECTION OUTPUT ;
    USE SIGNAL ;
    PORT
      LAYER M7 ;
        RECT  108.352 0 108.384 0.07 ;
    END
  END n_d[244]
  PIN n_d[245]
    DIRECTION OUTPUT ;
    USE SIGNAL ;
    PORT
      LAYER M7 ;
        RECT  108.736 0 108.768 0.07 ;
    END
  END n_d[245]
  PIN n_d[246]
    DIRECTION OUTPUT ;
    USE SIGNAL ;
    PORT
      LAYER M7 ;
        RECT  109.184 0 109.216 0.07 ;
    END
  END n_d[246]
  PIN n_d[247]
    DIRECTION OUTPUT ;
    USE SIGNAL ;
    PORT
      LAYER M7 ;
        RECT  109.632 0 109.664 0.07 ;
    END
  END n_d[247]
  PIN n_d[248]
    DIRECTION OUTPUT ;
    USE SIGNAL ;
    PORT
      LAYER M7 ;
        RECT  110.08 0 110.112 0.07 ;
    END
  END n_d[248]
  PIN n_d[249]
    DIRECTION OUTPUT ;
    USE SIGNAL ;
    PORT
      LAYER M7 ;
        RECT  110.464 0 110.496 0.07 ;
    END
  END n_d[249]
  PIN n_d[24]
    DIRECTION OUTPUT ;
    USE SIGNAL ;
    PORT
      LAYER M5 ;
        RECT  11.616 0 11.64 0.084 ;
    END
  END n_d[24]
  PIN n_d[250]
    DIRECTION OUTPUT ;
    USE SIGNAL ;
    PORT
      LAYER M7 ;
        RECT  110.912 0 110.944 0.07 ;
    END
  END n_d[250]
  PIN n_d[251]
    DIRECTION OUTPUT ;
    USE SIGNAL ;
    PORT
      LAYER M7 ;
        RECT  111.36 0 111.392 0.07 ;
    END
  END n_d[251]
  PIN n_d[252]
    DIRECTION OUTPUT ;
    USE SIGNAL ;
    PORT
      LAYER M7 ;
        RECT  111.808 0 111.84 0.07 ;
    END
  END n_d[252]
  PIN n_d[253]
    DIRECTION OUTPUT ;
    USE SIGNAL ;
    PORT
      LAYER M7 ;
        RECT  112.256 0 112.288 0.07 ;
    END
  END n_d[253]
  PIN n_d[254]
    DIRECTION OUTPUT ;
    USE SIGNAL ;
    PORT
      LAYER M5 ;
        RECT  112.656 0 112.68 0.084 ;
    END
  END n_d[254]
  PIN n_d[255]
    DIRECTION OUTPUT ;
    USE SIGNAL ;
    PORT
      LAYER M5 ;
        RECT  113.136 0 113.16 0.084 ;
    END
  END n_d[255]
  PIN n_d[25]
    DIRECTION OUTPUT ;
    USE SIGNAL ;
    PORT
      LAYER M5 ;
        RECT  12.048 0 12.072 0.084 ;
    END
  END n_d[25]
  PIN n_d[26]
    DIRECTION OUTPUT ;
    USE SIGNAL ;
    PORT
      LAYER M5 ;
        RECT  12.528 0 12.552 0.084 ;
    END
  END n_d[26]
  PIN n_d[27]
    DIRECTION OUTPUT ;
    USE SIGNAL ;
    PORT
      LAYER M5 ;
        RECT  12.96 0 12.984 0.084 ;
    END
  END n_d[27]
  PIN n_d[28]
    DIRECTION OUTPUT ;
    USE SIGNAL ;
    PORT
      LAYER M5 ;
        RECT  13.392 0 13.416 0.084 ;
    END
  END n_d[28]
  PIN n_d[29]
    DIRECTION OUTPUT ;
    USE SIGNAL ;
    PORT
      LAYER M5 ;
        RECT  13.824 0 13.848 0.084 ;
    END
  END n_d[29]
  PIN n_d[2]
    DIRECTION OUTPUT ;
    USE SIGNAL ;
    PORT
      LAYER M5 ;
        RECT  1.968 0 1.992 0.084 ;
    END
  END n_d[2]
  PIN n_d[30]
    DIRECTION OUTPUT ;
    USE SIGNAL ;
    PORT
      LAYER M7 ;
        RECT  14.272 0 14.304 0.07 ;
    END
  END n_d[30]
  PIN n_d[31]
    DIRECTION OUTPUT ;
    USE SIGNAL ;
    PORT
      LAYER M7 ;
        RECT  14.72 0 14.752 0.07 ;
    END
  END n_d[31]
  PIN n_d[32]
    DIRECTION OUTPUT ;
    USE SIGNAL ;
    PORT
      LAYER M7 ;
        RECT  15.168 0 15.2 0.07 ;
    END
  END n_d[32]
  PIN n_d[33]
    DIRECTION OUTPUT ;
    USE SIGNAL ;
    PORT
      LAYER M7 ;
        RECT  15.552 0 15.584 0.07 ;
    END
  END n_d[33]
  PIN n_d[34]
    DIRECTION OUTPUT ;
    USE SIGNAL ;
    PORT
      LAYER M7 ;
        RECT  16 0 16.032 0.07 ;
    END
  END n_d[34]
  PIN n_d[35]
    DIRECTION OUTPUT ;
    USE SIGNAL ;
    PORT
      LAYER M7 ;
        RECT  16.448 0 16.48 0.07 ;
    END
  END n_d[35]
  PIN n_d[36]
    DIRECTION OUTPUT ;
    USE SIGNAL ;
    PORT
      LAYER M7 ;
        RECT  16.896 0 16.928 0.07 ;
    END
  END n_d[36]
  PIN n_d[37]
    DIRECTION OUTPUT ;
    USE SIGNAL ;
    PORT
      LAYER M7 ;
        RECT  17.344 0 17.376 0.07 ;
    END
  END n_d[37]
  PIN n_d[38]
    DIRECTION OUTPUT ;
    USE SIGNAL ;
    PORT
      LAYER M7 ;
        RECT  17.792 0 17.824 0.07 ;
    END
  END n_d[38]
  PIN n_d[39]
    DIRECTION OUTPUT ;
    USE SIGNAL ;
    PORT
      LAYER M7 ;
        RECT  18.24 0 18.272 0.07 ;
    END
  END n_d[39]
  PIN n_d[3]
    DIRECTION OUTPUT ;
    USE SIGNAL ;
    PORT
      LAYER M5 ;
        RECT  2.4 0 2.424 0.084 ;
    END
  END n_d[3]
  PIN n_d[40]
    DIRECTION OUTPUT ;
    USE SIGNAL ;
    PORT
      LAYER M7 ;
        RECT  18.624 0 18.656 0.07 ;
    END
  END n_d[40]
  PIN n_d[41]
    DIRECTION OUTPUT ;
    USE SIGNAL ;
    PORT
      LAYER M7 ;
        RECT  19.072 0 19.104 0.07 ;
    END
  END n_d[41]
  PIN n_d[42]
    DIRECTION OUTPUT ;
    USE SIGNAL ;
    PORT
      LAYER M7 ;
        RECT  19.52 0 19.552 0.07 ;
    END
  END n_d[42]
  PIN n_d[43]
    DIRECTION OUTPUT ;
    USE SIGNAL ;
    PORT
      LAYER M7 ;
        RECT  19.968 0 20 0.07 ;
    END
  END n_d[43]
  PIN n_d[44]
    DIRECTION OUTPUT ;
    USE SIGNAL ;
    PORT
      LAYER M7 ;
        RECT  20.48 0 20.512 0.07 ;
    END
  END n_d[44]
  PIN n_d[45]
    DIRECTION OUTPUT ;
    USE SIGNAL ;
    PORT
      LAYER M7 ;
        RECT  20.928 0 20.96 0.07 ;
    END
  END n_d[45]
  PIN n_d[46]
    DIRECTION OUTPUT ;
    USE SIGNAL ;
    PORT
      LAYER M7 ;
        RECT  21.376 0 21.408 0.07 ;
    END
  END n_d[46]
  PIN n_d[47]
    DIRECTION OUTPUT ;
    USE SIGNAL ;
    PORT
      LAYER M7 ;
        RECT  21.824 0 21.856 0.07 ;
    END
  END n_d[47]
  PIN n_d[48]
    DIRECTION OUTPUT ;
    USE SIGNAL ;
    PORT
      LAYER M7 ;
        RECT  22.208 0 22.24 0.07 ;
    END
  END n_d[48]
  PIN n_d[49]
    DIRECTION OUTPUT ;
    USE SIGNAL ;
    PORT
      LAYER M7 ;
        RECT  22.656 0 22.688 0.07 ;
    END
  END n_d[49]
  PIN n_d[4]
    DIRECTION OUTPUT ;
    USE SIGNAL ;
    PORT
      LAYER M5 ;
        RECT  2.832 0 2.856 0.084 ;
    END
  END n_d[4]
  PIN n_d[50]
    DIRECTION OUTPUT ;
    USE SIGNAL ;
    PORT
      LAYER M7 ;
        RECT  23.104 0 23.136 0.07 ;
    END
  END n_d[50]
  PIN n_d[51]
    DIRECTION OUTPUT ;
    USE SIGNAL ;
    PORT
      LAYER M7 ;
        RECT  23.488 0 23.52 0.07 ;
    END
  END n_d[51]
  PIN n_d[52]
    DIRECTION OUTPUT ;
    USE SIGNAL ;
    PORT
      LAYER M7 ;
        RECT  23.936 0 23.968 0.07 ;
    END
  END n_d[52]
  PIN n_d[53]
    DIRECTION OUTPUT ;
    USE SIGNAL ;
    PORT
      LAYER M7 ;
        RECT  24.384 0 24.416 0.07 ;
    END
  END n_d[53]
  PIN n_d[54]
    DIRECTION OUTPUT ;
    USE SIGNAL ;
    PORT
      LAYER M7 ;
        RECT  24.832 0 24.864 0.07 ;
    END
  END n_d[54]
  PIN n_d[55]
    DIRECTION OUTPUT ;
    USE SIGNAL ;
    PORT
      LAYER M7 ;
        RECT  25.216 0 25.248 0.07 ;
    END
  END n_d[55]
  PIN n_d[56]
    DIRECTION OUTPUT ;
    USE SIGNAL ;
    PORT
      LAYER M7 ;
        RECT  25.664 0 25.696 0.07 ;
    END
  END n_d[56]
  PIN n_d[57]
    DIRECTION OUTPUT ;
    USE SIGNAL ;
    PORT
      LAYER M7 ;
        RECT  26.112 0 26.144 0.07 ;
    END
  END n_d[57]
  PIN n_d[58]
    DIRECTION OUTPUT ;
    USE SIGNAL ;
    PORT
      LAYER M7 ;
        RECT  26.56 0 26.592 0.07 ;
    END
  END n_d[58]
  PIN n_d[59]
    DIRECTION OUTPUT ;
    USE SIGNAL ;
    PORT
      LAYER M7 ;
        RECT  27.008 0 27.04 0.07 ;
    END
  END n_d[59]
  PIN n_d[5]
    DIRECTION OUTPUT ;
    USE SIGNAL ;
    PORT
      LAYER M5 ;
        RECT  3.264 0 3.288 0.084 ;
    END
  END n_d[5]
  PIN n_d[60]
    DIRECTION OUTPUT ;
    USE SIGNAL ;
    PORT
      LAYER M7 ;
        RECT  27.456 0 27.488 0.07 ;
    END
  END n_d[60]
  PIN n_d[61]
    DIRECTION OUTPUT ;
    USE SIGNAL ;
    PORT
      LAYER M7 ;
        RECT  27.904 0 27.936 0.07 ;
    END
  END n_d[61]
  PIN n_d[62]
    DIRECTION OUTPUT ;
    USE SIGNAL ;
    PORT
      LAYER M5 ;
        RECT  28.32 0 28.344 0.084 ;
    END
  END n_d[62]
  PIN n_d[63]
    DIRECTION OUTPUT ;
    USE SIGNAL ;
    PORT
      LAYER M5 ;
        RECT  28.752 0 28.776 0.084 ;
    END
  END n_d[63]
  PIN n_d[64]
    DIRECTION OUTPUT ;
    USE SIGNAL ;
    PORT
      LAYER M5 ;
        RECT  29.184 0 29.208 0.084 ;
    END
  END n_d[64]
  PIN n_d[65]
    DIRECTION OUTPUT ;
    USE SIGNAL ;
    PORT
      LAYER M5 ;
        RECT  29.664 0 29.688 0.084 ;
    END
  END n_d[65]
  PIN n_d[66]
    DIRECTION OUTPUT ;
    USE SIGNAL ;
    PORT
      LAYER M5 ;
        RECT  30.096 0 30.12 0.084 ;
    END
  END n_d[66]
  PIN n_d[67]
    DIRECTION OUTPUT ;
    USE SIGNAL ;
    PORT
      LAYER M5 ;
        RECT  30.528 0 30.552 0.084 ;
    END
  END n_d[67]
  PIN n_d[68]
    DIRECTION OUTPUT ;
    USE SIGNAL ;
    PORT
      LAYER M5 ;
        RECT  30.96 0 30.984 0.084 ;
    END
  END n_d[68]
  PIN n_d[69]
    DIRECTION OUTPUT ;
    USE SIGNAL ;
    PORT
      LAYER M5 ;
        RECT  31.392 0 31.416 0.084 ;
    END
  END n_d[69]
  PIN n_d[6]
    DIRECTION OUTPUT ;
    USE SIGNAL ;
    PORT
      LAYER M5 ;
        RECT  3.744 0 3.768 0.084 ;
    END
  END n_d[6]
  PIN n_d[70]
    DIRECTION OUTPUT ;
    USE SIGNAL ;
    PORT
      LAYER M5 ;
        RECT  31.824 0 31.848 0.084 ;
    END
  END n_d[70]
  PIN n_d[71]
    DIRECTION OUTPUT ;
    USE SIGNAL ;
    PORT
      LAYER M5 ;
        RECT  32.256 0 32.28 0.084 ;
    END
  END n_d[71]
  PIN n_d[72]
    DIRECTION OUTPUT ;
    USE SIGNAL ;
    PORT
      LAYER M5 ;
        RECT  32.736 0 32.76 0.084 ;
    END
  END n_d[72]
  PIN n_d[73]
    DIRECTION OUTPUT ;
    USE SIGNAL ;
    PORT
      LAYER M5 ;
        RECT  33.168 0 33.192 0.084 ;
    END
  END n_d[73]
  PIN n_d[74]
    DIRECTION OUTPUT ;
    USE SIGNAL ;
    PORT
      LAYER M5 ;
        RECT  33.6 0 33.624 0.084 ;
    END
  END n_d[74]
  PIN n_d[75]
    DIRECTION OUTPUT ;
    USE SIGNAL ;
    PORT
      LAYER M5 ;
        RECT  34.032 0 34.056 0.084 ;
    END
  END n_d[75]
  PIN n_d[76]
    DIRECTION OUTPUT ;
    USE SIGNAL ;
    PORT
      LAYER M5 ;
        RECT  34.464 0 34.488 0.084 ;
    END
  END n_d[76]
  PIN n_d[77]
    DIRECTION OUTPUT ;
    USE SIGNAL ;
    PORT
      LAYER M5 ;
        RECT  34.896 0 34.92 0.084 ;
    END
  END n_d[77]
  PIN n_d[78]
    DIRECTION OUTPUT ;
    USE SIGNAL ;
    PORT
      LAYER M5 ;
        RECT  35.376 0 35.4 0.084 ;
    END
  END n_d[78]
  PIN n_d[79]
    DIRECTION OUTPUT ;
    USE SIGNAL ;
    PORT
      LAYER M5 ;
        RECT  35.808 0 35.832 0.084 ;
    END
  END n_d[79]
  PIN n_d[7]
    DIRECTION OUTPUT ;
    USE SIGNAL ;
    PORT
      LAYER M5 ;
        RECT  4.176 0 4.2 0.084 ;
    END
  END n_d[7]
  PIN n_d[80]
    DIRECTION OUTPUT ;
    USE SIGNAL ;
    PORT
      LAYER M5 ;
        RECT  36.24 0 36.264 0.084 ;
    END
  END n_d[80]
  PIN n_d[81]
    DIRECTION OUTPUT ;
    USE SIGNAL ;
    PORT
      LAYER M5 ;
        RECT  36.672 0 36.696 0.084 ;
    END
  END n_d[81]
  PIN n_d[82]
    DIRECTION OUTPUT ;
    USE SIGNAL ;
    PORT
      LAYER M5 ;
        RECT  37.104 0 37.128 0.084 ;
    END
  END n_d[82]
  PIN n_d[83]
    DIRECTION OUTPUT ;
    USE SIGNAL ;
    PORT
      LAYER M5 ;
        RECT  37.536 0 37.56 0.084 ;
    END
  END n_d[83]
  PIN n_d[84]
    DIRECTION OUTPUT ;
    USE SIGNAL ;
    PORT
      LAYER M5 ;
        RECT  37.968 0 37.992 0.084 ;
    END
  END n_d[84]
  PIN n_d[85]
    DIRECTION OUTPUT ;
    USE SIGNAL ;
    PORT
      LAYER M5 ;
        RECT  38.448 0 38.472 0.084 ;
    END
  END n_d[85]
  PIN n_d[86]
    DIRECTION OUTPUT ;
    USE SIGNAL ;
    PORT
      LAYER M5 ;
        RECT  38.88 0 38.904 0.084 ;
    END
  END n_d[86]
  PIN n_d[87]
    DIRECTION OUTPUT ;
    USE SIGNAL ;
    PORT
      LAYER M5 ;
        RECT  39.312 0 39.336 0.084 ;
    END
  END n_d[87]
  PIN n_d[88]
    DIRECTION OUTPUT ;
    USE SIGNAL ;
    PORT
      LAYER M5 ;
        RECT  39.744 0 39.768 0.084 ;
    END
  END n_d[88]
  PIN n_d[89]
    DIRECTION OUTPUT ;
    USE SIGNAL ;
    PORT
      LAYER M5 ;
        RECT  40.176 0 40.2 0.084 ;
    END
  END n_d[89]
  PIN n_d[8]
    DIRECTION OUTPUT ;
    USE SIGNAL ;
    PORT
      LAYER M5 ;
        RECT  4.608 0 4.632 0.084 ;
    END
  END n_d[8]
  PIN n_d[90]
    DIRECTION OUTPUT ;
    USE SIGNAL ;
    PORT
      LAYER M5 ;
        RECT  40.608 0 40.632 0.084 ;
    END
  END n_d[90]
  PIN n_d[91]
    DIRECTION OUTPUT ;
    USE SIGNAL ;
    PORT
      LAYER M5 ;
        RECT  41.136 0 41.16 0.084 ;
    END
  END n_d[91]
  PIN n_d[92]
    DIRECTION OUTPUT ;
    USE SIGNAL ;
    PORT
      LAYER M5 ;
        RECT  41.52 0 41.544 0.084 ;
    END
  END n_d[92]
  PIN n_d[93]
    DIRECTION OUTPUT ;
    USE SIGNAL ;
    PORT
      LAYER M5 ;
        RECT  41.952 0 41.976 0.084 ;
    END
  END n_d[93]
  PIN n_d[94]
    DIRECTION OUTPUT ;
    USE SIGNAL ;
    PORT
      LAYER M7 ;
        RECT  42.432 0 42.464 0.07 ;
    END
  END n_d[94]
  PIN n_d[95]
    DIRECTION OUTPUT ;
    USE SIGNAL ;
    PORT
      LAYER M7 ;
        RECT  42.88 0 42.912 0.07 ;
    END
  END n_d[95]
  PIN n_d[96]
    DIRECTION OUTPUT ;
    USE SIGNAL ;
    PORT
      LAYER M7 ;
        RECT  43.328 0 43.36 0.07 ;
    END
  END n_d[96]
  PIN n_d[97]
    DIRECTION OUTPUT ;
    USE SIGNAL ;
    PORT
      LAYER M7 ;
        RECT  43.776 0 43.808 0.07 ;
    END
  END n_d[97]
  PIN n_d[98]
    DIRECTION OUTPUT ;
    USE SIGNAL ;
    PORT
      LAYER M7 ;
        RECT  44.16 0 44.192 0.07 ;
    END
  END n_d[98]
  PIN n_d[99]
    DIRECTION OUTPUT ;
    USE SIGNAL ;
    PORT
      LAYER M7 ;
        RECT  44.608 0 44.64 0.07 ;
    END
  END n_d[99]
  PIN n_d[9]
    DIRECTION OUTPUT ;
    USE SIGNAL ;
    PORT
      LAYER M5 ;
        RECT  5.04 0 5.064 0.084 ;
    END
  END n_d[9]
  PIN n_lane[0]
    DIRECTION OUTPUT ;
    USE SIGNAL ;
    PORT
      LAYER M5 ;
        RECT  113.568 0 113.592 0.084 ;
    END
  END n_lane[0]
  PIN n_lane[1]
    DIRECTION OUTPUT ;
    USE SIGNAL ;
    PORT
      LAYER M5 ;
        RECT  114 0 114.024 0.084 ;
    END
  END n_lane[1]
  PIN n_lane[2]
    DIRECTION OUTPUT ;
    USE SIGNAL ;
    PORT
      LAYER M5 ;
        RECT  114.432 0 114.456 0.084 ;
    END
  END n_lane[2]
  PIN n_sec[0]
    DIRECTION OUTPUT ;
    USE SIGNAL ;
    PORT
      LAYER M5 ;
        RECT  114.864 0 114.888 0.084 ;
    END
  END n_sec[0]
  PIN n_sec[10]
    DIRECTION OUTPUT ;
    USE SIGNAL ;
    PORT
      LAYER M5 ;
        RECT  119.28 0 119.304 0.084 ;
    END
  END n_sec[10]
  PIN n_sec[11]
    DIRECTION OUTPUT ;
    USE SIGNAL ;
    PORT
      LAYER M5 ;
        RECT  119.712 0 119.736 0.084 ;
    END
  END n_sec[11]
  PIN n_sec[12]
    DIRECTION OUTPUT ;
    USE SIGNAL ;
    PORT
      LAYER M5 ;
        RECT  120.144 0 120.168 0.084 ;
    END
  END n_sec[12]
  PIN n_sec[13]
    DIRECTION OUTPUT ;
    USE SIGNAL ;
    PORT
      LAYER M5 ;
        RECT  120.576 0 120.6 0.084 ;
    END
  END n_sec[13]
  PIN n_sec[14]
    DIRECTION OUTPUT ;
    USE SIGNAL ;
    PORT
      LAYER M5 ;
        RECT  121.008 0 121.032 0.084 ;
    END
  END n_sec[14]
  PIN n_sec[15]
    DIRECTION OUTPUT ;
    USE SIGNAL ;
    PORT
      LAYER M5 ;
        RECT  121.44 0 121.464 0.084 ;
    END
  END n_sec[15]
  PIN n_sec[16]
    DIRECTION OUTPUT ;
    USE SIGNAL ;
    PORT
      LAYER M5 ;
        RECT  121.92 0 121.944 0.084 ;
    END
  END n_sec[16]
  PIN n_sec[17]
    DIRECTION OUTPUT ;
    USE SIGNAL ;
    PORT
      LAYER M5 ;
        RECT  122.352 0 122.376 0.084 ;
    END
  END n_sec[17]
  PIN n_sec[18]
    DIRECTION OUTPUT ;
    USE SIGNAL ;
    PORT
      LAYER M5 ;
        RECT  122.784 0 122.808 0.084 ;
    END
  END n_sec[18]
  PIN n_sec[19]
    DIRECTION OUTPUT ;
    USE SIGNAL ;
    PORT
      LAYER M5 ;
        RECT  123.216 0 123.24 0.084 ;
    END
  END n_sec[19]
  PIN n_sec[1]
    DIRECTION OUTPUT ;
    USE SIGNAL ;
    PORT
      LAYER M5 ;
        RECT  115.296 0 115.32 0.084 ;
    END
  END n_sec[1]
  PIN n_sec[20]
    DIRECTION OUTPUT ;
    USE SIGNAL ;
    PORT
      LAYER M5 ;
        RECT  123.648 0 123.672 0.084 ;
    END
  END n_sec[20]
  PIN n_sec[21]
    DIRECTION OUTPUT ;
    USE SIGNAL ;
    PORT
      LAYER M5 ;
        RECT  124.08 0 124.104 0.084 ;
    END
  END n_sec[21]
  PIN n_sec[22]
    DIRECTION OUTPUT ;
    USE SIGNAL ;
    PORT
      LAYER M5 ;
        RECT  124.56 0 124.584 0.084 ;
    END
  END n_sec[22]
  PIN n_sec[23]
    DIRECTION OUTPUT ;
    USE SIGNAL ;
    PORT
      LAYER M5 ;
        RECT  124.992 0 125.016 0.084 ;
    END
  END n_sec[23]
  PIN n_sec[2]
    DIRECTION OUTPUT ;
    USE SIGNAL ;
    PORT
      LAYER M5 ;
        RECT  115.728 0 115.752 0.084 ;
    END
  END n_sec[2]
  PIN n_sec[3]
    DIRECTION OUTPUT ;
    USE SIGNAL ;
    PORT
      LAYER M5 ;
        RECT  116.208 0 116.232 0.084 ;
    END
  END n_sec[3]
  PIN n_sec[4]
    DIRECTION OUTPUT ;
    USE SIGNAL ;
    PORT
      LAYER M5 ;
        RECT  116.64 0 116.664 0.084 ;
    END
  END n_sec[4]
  PIN n_sec[5]
    DIRECTION OUTPUT ;
    USE SIGNAL ;
    PORT
      LAYER M5 ;
        RECT  117.072 0 117.096 0.084 ;
    END
  END n_sec[5]
  PIN n_sec[6]
    DIRECTION OUTPUT ;
    USE SIGNAL ;
    PORT
      LAYER M5 ;
        RECT  117.504 0 117.528 0.084 ;
    END
  END n_sec[6]
  PIN n_sec[7]
    DIRECTION OUTPUT ;
    USE SIGNAL ;
    PORT
      LAYER M5 ;
        RECT  117.936 0 117.96 0.084 ;
    END
  END n_sec[7]
  PIN n_sec[8]
    DIRECTION OUTPUT ;
    USE SIGNAL ;
    PORT
      LAYER M5 ;
        RECT  118.368 0 118.392 0.084 ;
    END
  END n_sec[8]
  PIN n_sec[9]
    DIRECTION OUTPUT ;
    USE SIGNAL ;
    PORT
      LAYER M5 ;
        RECT  118.848 0 118.872 0.084 ;
    END
  END n_sec[9]
  PIN n_tag[0]
    DIRECTION OUTPUT ;
    USE SIGNAL ;
    PORT
      LAYER M5 ;
        RECT  125.424 0 125.448 0.084 ;
    END
  END n_tag[0]
  PIN n_tag[1]
    DIRECTION OUTPUT ;
    USE SIGNAL ;
    PORT
      LAYER M5 ;
        RECT  125.856 0 125.88 0.084 ;
    END
  END n_tag[1]
  PIN n_tag[2]
    DIRECTION OUTPUT ;
    USE SIGNAL ;
    PORT
      LAYER M5 ;
        RECT  126.288 0 126.312 0.084 ;
    END
  END n_tag[2]
  PIN n_tag[3]
    DIRECTION OUTPUT ;
    USE SIGNAL ;
    PORT
      LAYER M7 ;
        RECT  126.72 0 126.752 0.07 ;
    END
  END n_tag[3]
  PIN n_tag[4]
    DIRECTION OUTPUT ;
    USE SIGNAL ;
    PORT
      LAYER M7 ;
        RECT  127.168 0 127.2 0.07 ;
    END
  END n_tag[4]
  PIN n_tag[5]
    DIRECTION OUTPUT ;
    USE SIGNAL ;
    PORT
      LAYER M7 ;
        RECT  127.68 0 127.712 0.07 ;
    END
  END n_tag[5]
  PIN n_tag[6]
    DIRECTION OUTPUT ;
    USE SIGNAL ;
    PORT
      LAYER M7 ;
        RECT  128.128 0 128.16 0.07 ;
    END
  END n_tag[6]
  PIN n_tag[7]
    DIRECTION OUTPUT ;
    USE SIGNAL ;
    PORT
      LAYER M7 ;
        RECT  128.576 0 128.608 0.07 ;
    END
  END n_tag[7]
  PIN n_tag[8]
    DIRECTION OUTPUT ;
    USE SIGNAL ;
    PORT
      LAYER M7 ;
        RECT  128.896 0 128.928 0.07 ;
    END
  END n_tag[8]
  PIN n_v
    DIRECTION OUTPUT ;
    USE SIGNAL ;
    PORT
      LAYER M7 ;
        RECT  129.408 0 129.44 0.07 ;
    END
  END n_v
  PIN rst_n
    DIRECTION INPUT ;
    USE SIGNAL ;
    PORT
      LAYER M4 ;
        RECT  129.516 94.224 129.6 94.248 ;
    END
  END rst_n
  PIN w_data[0]
    DIRECTION OUTPUT ;
    USE SIGNAL ;
    PORT
      LAYER M5 ;
        RECT  0.192 0 0.216 0.084 ;
    END
  END w_data[0]
  PIN w_data[100]
    DIRECTION OUTPUT ;
    USE SIGNAL ;
    PORT
      LAYER M7 ;
        RECT  43.264 0 43.296 0.07 ;
    END
  END w_data[100]
  PIN w_data[101]
    DIRECTION OUTPUT ;
    USE SIGNAL ;
    PORT
      LAYER M7 ;
        RECT  43.712 0 43.744 0.07 ;
    END
  END w_data[101]
  PIN w_data[102]
    DIRECTION OUTPUT ;
    USE SIGNAL ;
    PORT
      LAYER M7 ;
        RECT  44.096 0 44.128 0.07 ;
    END
  END w_data[102]
  PIN w_data[103]
    DIRECTION OUTPUT ;
    USE SIGNAL ;
    PORT
      LAYER M7 ;
        RECT  44.544 0 44.576 0.07 ;
    END
  END w_data[103]
  PIN w_data[104]
    DIRECTION OUTPUT ;
    USE SIGNAL ;
    PORT
      LAYER M7 ;
        RECT  44.992 0 45.024 0.07 ;
    END
  END w_data[104]
  PIN w_data[105]
    DIRECTION OUTPUT ;
    USE SIGNAL ;
    PORT
      LAYER M7 ;
        RECT  45.44 0 45.472 0.07 ;
    END
  END w_data[105]
  PIN w_data[106]
    DIRECTION OUTPUT ;
    USE SIGNAL ;
    PORT
      LAYER M7 ;
        RECT  45.824 0 45.856 0.07 ;
    END
  END w_data[106]
  PIN w_data[107]
    DIRECTION OUTPUT ;
    USE SIGNAL ;
    PORT
      LAYER M7 ;
        RECT  46.272 0 46.304 0.07 ;
    END
  END w_data[107]
  PIN w_data[108]
    DIRECTION OUTPUT ;
    USE SIGNAL ;
    PORT
      LAYER M7 ;
        RECT  46.72 0 46.752 0.07 ;
    END
  END w_data[108]
  PIN w_data[109]
    DIRECTION OUTPUT ;
    USE SIGNAL ;
    PORT
      LAYER M7 ;
        RECT  47.104 0 47.136 0.07 ;
    END
  END w_data[109]
  PIN w_data[10]
    DIRECTION OUTPUT ;
    USE SIGNAL ;
    PORT
      LAYER M5 ;
        RECT  4.512 0 4.536 0.084 ;
    END
  END w_data[10]
  PIN w_data[110]
    DIRECTION OUTPUT ;
    USE SIGNAL ;
    PORT
      LAYER M7 ;
        RECT  47.552 0 47.584 0.07 ;
    END
  END w_data[110]
  PIN w_data[111]
    DIRECTION OUTPUT ;
    USE SIGNAL ;
    PORT
      LAYER M7 ;
        RECT  48 0 48.032 0.07 ;
    END
  END w_data[111]
  PIN w_data[112]
    DIRECTION OUTPUT ;
    USE SIGNAL ;
    PORT
      LAYER M7 ;
        RECT  48.448 0 48.48 0.07 ;
    END
  END w_data[112]
  PIN w_data[113]
    DIRECTION OUTPUT ;
    USE SIGNAL ;
    PORT
      LAYER M7 ;
        RECT  48.832 0 48.864 0.07 ;
    END
  END w_data[113]
  PIN w_data[114]
    DIRECTION OUTPUT ;
    USE SIGNAL ;
    PORT
      LAYER M7 ;
        RECT  49.28 0 49.312 0.07 ;
    END
  END w_data[114]
  PIN w_data[115]
    DIRECTION OUTPUT ;
    USE SIGNAL ;
    PORT
      LAYER M7 ;
        RECT  49.728 0 49.76 0.07 ;
    END
  END w_data[115]
  PIN w_data[116]
    DIRECTION OUTPUT ;
    USE SIGNAL ;
    PORT
      LAYER M7 ;
        RECT  50.176 0 50.208 0.07 ;
    END
  END w_data[116]
  PIN w_data[117]
    DIRECTION OUTPUT ;
    USE SIGNAL ;
    PORT
      LAYER M7 ;
        RECT  50.56 0 50.592 0.07 ;
    END
  END w_data[117]
  PIN w_data[118]
    DIRECTION OUTPUT ;
    USE SIGNAL ;
    PORT
      LAYER M7 ;
        RECT  51.008 0 51.04 0.07 ;
    END
  END w_data[118]
  PIN w_data[119]
    DIRECTION OUTPUT ;
    USE SIGNAL ;
    PORT
      LAYER M7 ;
        RECT  51.456 0 51.488 0.07 ;
    END
  END w_data[119]
  PIN w_data[11]
    DIRECTION OUTPUT ;
    USE SIGNAL ;
    PORT
      LAYER M5 ;
        RECT  4.944 0 4.968 0.084 ;
    END
  END w_data[11]
  PIN w_data[120]
    DIRECTION OUTPUT ;
    USE SIGNAL ;
    PORT
      LAYER M7 ;
        RECT  51.84 0 51.872 0.07 ;
    END
  END w_data[120]
  PIN w_data[121]
    DIRECTION OUTPUT ;
    USE SIGNAL ;
    PORT
      LAYER M7 ;
        RECT  52.288 0 52.32 0.07 ;
    END
  END w_data[121]
  PIN w_data[122]
    DIRECTION OUTPUT ;
    USE SIGNAL ;
    PORT
      LAYER M7 ;
        RECT  52.736 0 52.768 0.07 ;
    END
  END w_data[122]
  PIN w_data[123]
    DIRECTION OUTPUT ;
    USE SIGNAL ;
    PORT
      LAYER M7 ;
        RECT  53.184 0 53.216 0.07 ;
    END
  END w_data[123]
  PIN w_data[124]
    DIRECTION OUTPUT ;
    USE SIGNAL ;
    PORT
      LAYER M7 ;
        RECT  53.568 0 53.6 0.07 ;
    END
  END w_data[124]
  PIN w_data[125]
    DIRECTION OUTPUT ;
    USE SIGNAL ;
    PORT
      LAYER M7 ;
        RECT  54.016 0 54.048 0.07 ;
    END
  END w_data[125]
  PIN w_data[126]
    DIRECTION OUTPUT ;
    USE SIGNAL ;
    PORT
      LAYER M7 ;
        RECT  54.464 0 54.496 0.07 ;
    END
  END w_data[126]
  PIN w_data[127]
    DIRECTION OUTPUT ;
    USE SIGNAL ;
    PORT
      LAYER M7 ;
        RECT  54.912 0 54.944 0.07 ;
    END
  END w_data[127]
  PIN w_data[128]
    DIRECTION OUTPUT ;
    USE SIGNAL ;
    PORT
      LAYER M5 ;
        RECT  55.296 0 55.32 0.084 ;
    END
  END w_data[128]
  PIN w_data[129]
    DIRECTION OUTPUT ;
    USE SIGNAL ;
    PORT
      LAYER M5 ;
        RECT  55.728 0 55.752 0.084 ;
    END
  END w_data[129]
  PIN w_data[12]
    DIRECTION OUTPUT ;
    USE SIGNAL ;
    PORT
      LAYER M5 ;
        RECT  5.376 0 5.4 0.084 ;
    END
  END w_data[12]
  PIN w_data[130]
    DIRECTION OUTPUT ;
    USE SIGNAL ;
    PORT
      LAYER M5 ;
        RECT  56.16 0 56.184 0.084 ;
    END
  END w_data[130]
  PIN w_data[131]
    DIRECTION OUTPUT ;
    USE SIGNAL ;
    PORT
      LAYER M5 ;
        RECT  56.592 0 56.616 0.084 ;
    END
  END w_data[131]
  PIN w_data[132]
    DIRECTION OUTPUT ;
    USE SIGNAL ;
    PORT
      LAYER M5 ;
        RECT  57.024 0 57.048 0.084 ;
    END
  END w_data[132]
  PIN w_data[133]
    DIRECTION OUTPUT ;
    USE SIGNAL ;
    PORT
      LAYER M5 ;
        RECT  57.456 0 57.48 0.084 ;
    END
  END w_data[133]
  PIN w_data[134]
    DIRECTION OUTPUT ;
    USE SIGNAL ;
    PORT
      LAYER M5 ;
        RECT  57.888 0 57.912 0.084 ;
    END
  END w_data[134]
  PIN w_data[135]
    DIRECTION OUTPUT ;
    USE SIGNAL ;
    PORT
      LAYER M5 ;
        RECT  58.32 0 58.344 0.084 ;
    END
  END w_data[135]
  PIN w_data[136]
    DIRECTION OUTPUT ;
    USE SIGNAL ;
    PORT
      LAYER M5 ;
        RECT  58.752 0 58.776 0.084 ;
    END
  END w_data[136]
  PIN w_data[137]
    DIRECTION OUTPUT ;
    USE SIGNAL ;
    PORT
      LAYER M5 ;
        RECT  59.184 0 59.208 0.084 ;
    END
  END w_data[137]
  PIN w_data[138]
    DIRECTION OUTPUT ;
    USE SIGNAL ;
    PORT
      LAYER M5 ;
        RECT  59.616 0 59.64 0.084 ;
    END
  END w_data[138]
  PIN w_data[139]
    DIRECTION OUTPUT ;
    USE SIGNAL ;
    PORT
      LAYER M5 ;
        RECT  60.048 0 60.072 0.084 ;
    END
  END w_data[139]
  PIN w_data[13]
    DIRECTION OUTPUT ;
    USE SIGNAL ;
    PORT
      LAYER M5 ;
        RECT  5.808 0 5.832 0.084 ;
    END
  END w_data[13]
  PIN w_data[140]
    DIRECTION OUTPUT ;
    USE SIGNAL ;
    PORT
      LAYER M5 ;
        RECT  60.48 0 60.504 0.084 ;
    END
  END w_data[140]
  PIN w_data[141]
    DIRECTION OUTPUT ;
    USE SIGNAL ;
    PORT
      LAYER M5 ;
        RECT  60.912 0 60.936 0.084 ;
    END
  END w_data[141]
  PIN w_data[142]
    DIRECTION OUTPUT ;
    USE SIGNAL ;
    PORT
      LAYER M5 ;
        RECT  61.344 0 61.368 0.084 ;
    END
  END w_data[142]
  PIN w_data[143]
    DIRECTION OUTPUT ;
    USE SIGNAL ;
    PORT
      LAYER M5 ;
        RECT  61.776 0 61.8 0.084 ;
    END
  END w_data[143]
  PIN w_data[144]
    DIRECTION OUTPUT ;
    USE SIGNAL ;
    PORT
      LAYER M5 ;
        RECT  62.208 0 62.232 0.084 ;
    END
  END w_data[144]
  PIN w_data[145]
    DIRECTION OUTPUT ;
    USE SIGNAL ;
    PORT
      LAYER M5 ;
        RECT  62.64 0 62.664 0.084 ;
    END
  END w_data[145]
  PIN w_data[146]
    DIRECTION OUTPUT ;
    USE SIGNAL ;
    PORT
      LAYER M5 ;
        RECT  63.072 0 63.096 0.084 ;
    END
  END w_data[146]
  PIN w_data[147]
    DIRECTION OUTPUT ;
    USE SIGNAL ;
    PORT
      LAYER M5 ;
        RECT  63.504 0 63.528 0.084 ;
    END
  END w_data[147]
  PIN w_data[148]
    DIRECTION OUTPUT ;
    USE SIGNAL ;
    PORT
      LAYER M5 ;
        RECT  63.936 0 63.96 0.084 ;
    END
  END w_data[148]
  PIN w_data[149]
    DIRECTION OUTPUT ;
    USE SIGNAL ;
    PORT
      LAYER M5 ;
        RECT  64.368 0 64.392 0.084 ;
    END
  END w_data[149]
  PIN w_data[14]
    DIRECTION OUTPUT ;
    USE SIGNAL ;
    PORT
      LAYER M5 ;
        RECT  6.24 0 6.264 0.084 ;
    END
  END w_data[14]
  PIN w_data[150]
    DIRECTION OUTPUT ;
    USE SIGNAL ;
    PORT
      LAYER M5 ;
        RECT  64.8 0 64.824 0.084 ;
    END
  END w_data[150]
  PIN w_data[151]
    DIRECTION OUTPUT ;
    USE SIGNAL ;
    PORT
      LAYER M5 ;
        RECT  65.232 0 65.256 0.084 ;
    END
  END w_data[151]
  PIN w_data[152]
    DIRECTION OUTPUT ;
    USE SIGNAL ;
    PORT
      LAYER M5 ;
        RECT  65.664 0 65.688 0.084 ;
    END
  END w_data[152]
  PIN w_data[153]
    DIRECTION OUTPUT ;
    USE SIGNAL ;
    PORT
      LAYER M5 ;
        RECT  66.096 0 66.12 0.084 ;
    END
  END w_data[153]
  PIN w_data[154]
    DIRECTION OUTPUT ;
    USE SIGNAL ;
    PORT
      LAYER M5 ;
        RECT  66.528 0 66.552 0.084 ;
    END
  END w_data[154]
  PIN w_data[155]
    DIRECTION OUTPUT ;
    USE SIGNAL ;
    PORT
      LAYER M5 ;
        RECT  66.96 0 66.984 0.084 ;
    END
  END w_data[155]
  PIN w_data[156]
    DIRECTION OUTPUT ;
    USE SIGNAL ;
    PORT
      LAYER M5 ;
        RECT  67.392 0 67.416 0.084 ;
    END
  END w_data[156]
  PIN w_data[157]
    DIRECTION OUTPUT ;
    USE SIGNAL ;
    PORT
      LAYER M5 ;
        RECT  67.824 0 67.848 0.084 ;
    END
  END w_data[157]
  PIN w_data[158]
    DIRECTION OUTPUT ;
    USE SIGNAL ;
    PORT
      LAYER M5 ;
        RECT  68.256 0 68.28 0.084 ;
    END
  END w_data[158]
  PIN w_data[159]
    DIRECTION OUTPUT ;
    USE SIGNAL ;
    PORT
      LAYER M5 ;
        RECT  68.64 0 68.664 0.084 ;
    END
  END w_data[159]
  PIN w_data[15]
    DIRECTION OUTPUT ;
    USE SIGNAL ;
    PORT
      LAYER M5 ;
        RECT  6.672 0 6.696 0.084 ;
    END
  END w_data[15]
  PIN w_data[160]
    DIRECTION OUTPUT ;
    USE SIGNAL ;
    PORT
      LAYER M7 ;
        RECT  69.12 0 69.152 0.07 ;
    END
  END w_data[160]
  PIN w_data[161]
    DIRECTION OUTPUT ;
    USE SIGNAL ;
    PORT
      LAYER M7 ;
        RECT  69.504 0 69.536 0.07 ;
    END
  END w_data[161]
  PIN w_data[162]
    DIRECTION OUTPUT ;
    USE SIGNAL ;
    PORT
      LAYER M7 ;
        RECT  69.952 0 69.984 0.07 ;
    END
  END w_data[162]
  PIN w_data[163]
    DIRECTION OUTPUT ;
    USE SIGNAL ;
    PORT
      LAYER M7 ;
        RECT  70.4 0 70.432 0.07 ;
    END
  END w_data[163]
  PIN w_data[164]
    DIRECTION OUTPUT ;
    USE SIGNAL ;
    PORT
      LAYER M7 ;
        RECT  70.784 0 70.816 0.07 ;
    END
  END w_data[164]
  PIN w_data[165]
    DIRECTION OUTPUT ;
    USE SIGNAL ;
    PORT
      LAYER M7 ;
        RECT  71.232 0 71.264 0.07 ;
    END
  END w_data[165]
  PIN w_data[166]
    DIRECTION OUTPUT ;
    USE SIGNAL ;
    PORT
      LAYER M7 ;
        RECT  71.68 0 71.712 0.07 ;
    END
  END w_data[166]
  PIN w_data[167]
    DIRECTION OUTPUT ;
    USE SIGNAL ;
    PORT
      LAYER M7 ;
        RECT  72.128 0 72.16 0.07 ;
    END
  END w_data[167]
  PIN w_data[168]
    DIRECTION OUTPUT ;
    USE SIGNAL ;
    PORT
      LAYER M7 ;
        RECT  72.512 0 72.544 0.07 ;
    END
  END w_data[168]
  PIN w_data[169]
    DIRECTION OUTPUT ;
    USE SIGNAL ;
    PORT
      LAYER M7 ;
        RECT  72.96 0 72.992 0.07 ;
    END
  END w_data[169]
  PIN w_data[16]
    DIRECTION OUTPUT ;
    USE SIGNAL ;
    PORT
      LAYER M5 ;
        RECT  7.104 0 7.128 0.084 ;
    END
  END w_data[16]
  PIN w_data[170]
    DIRECTION OUTPUT ;
    USE SIGNAL ;
    PORT
      LAYER M7 ;
        RECT  73.408 0 73.44 0.07 ;
    END
  END w_data[170]
  PIN w_data[171]
    DIRECTION OUTPUT ;
    USE SIGNAL ;
    PORT
      LAYER M7 ;
        RECT  73.856 0 73.888 0.07 ;
    END
  END w_data[171]
  PIN w_data[172]
    DIRECTION OUTPUT ;
    USE SIGNAL ;
    PORT
      LAYER M7 ;
        RECT  74.24 0 74.272 0.07 ;
    END
  END w_data[172]
  PIN w_data[173]
    DIRECTION OUTPUT ;
    USE SIGNAL ;
    PORT
      LAYER M7 ;
        RECT  74.688 0 74.72 0.07 ;
    END
  END w_data[173]
  PIN w_data[174]
    DIRECTION OUTPUT ;
    USE SIGNAL ;
    PORT
      LAYER M7 ;
        RECT  75.136 0 75.168 0.07 ;
    END
  END w_data[174]
  PIN w_data[175]
    DIRECTION OUTPUT ;
    USE SIGNAL ;
    PORT
      LAYER M7 ;
        RECT  75.52 0 75.552 0.07 ;
    END
  END w_data[175]
  PIN w_data[176]
    DIRECTION OUTPUT ;
    USE SIGNAL ;
    PORT
      LAYER M7 ;
        RECT  75.968 0 76 0.07 ;
    END
  END w_data[176]
  PIN w_data[177]
    DIRECTION OUTPUT ;
    USE SIGNAL ;
    PORT
      LAYER M7 ;
        RECT  76.416 0 76.448 0.07 ;
    END
  END w_data[177]
  PIN w_data[178]
    DIRECTION OUTPUT ;
    USE SIGNAL ;
    PORT
      LAYER M7 ;
        RECT  76.864 0 76.896 0.07 ;
    END
  END w_data[178]
  PIN w_data[179]
    DIRECTION OUTPUT ;
    USE SIGNAL ;
    PORT
      LAYER M7 ;
        RECT  77.248 0 77.28 0.07 ;
    END
  END w_data[179]
  PIN w_data[17]
    DIRECTION OUTPUT ;
    USE SIGNAL ;
    PORT
      LAYER M5 ;
        RECT  7.536 0 7.56 0.084 ;
    END
  END w_data[17]
  PIN w_data[180]
    DIRECTION OUTPUT ;
    USE SIGNAL ;
    PORT
      LAYER M7 ;
        RECT  77.696 0 77.728 0.07 ;
    END
  END w_data[180]
  PIN w_data[181]
    DIRECTION OUTPUT ;
    USE SIGNAL ;
    PORT
      LAYER M7 ;
        RECT  78.144 0 78.176 0.07 ;
    END
  END w_data[181]
  PIN w_data[182]
    DIRECTION OUTPUT ;
    USE SIGNAL ;
    PORT
      LAYER M7 ;
        RECT  78.592 0 78.624 0.07 ;
    END
  END w_data[182]
  PIN w_data[183]
    DIRECTION OUTPUT ;
    USE SIGNAL ;
    PORT
      LAYER M7 ;
        RECT  78.976 0 79.008 0.07 ;
    END
  END w_data[183]
  PIN w_data[184]
    DIRECTION OUTPUT ;
    USE SIGNAL ;
    PORT
      LAYER M7 ;
        RECT  79.424 0 79.456 0.07 ;
    END
  END w_data[184]
  PIN w_data[185]
    DIRECTION OUTPUT ;
    USE SIGNAL ;
    PORT
      LAYER M7 ;
        RECT  79.872 0 79.904 0.07 ;
    END
  END w_data[185]
  PIN w_data[186]
    DIRECTION OUTPUT ;
    USE SIGNAL ;
    PORT
      LAYER M7 ;
        RECT  80.256 0 80.288 0.07 ;
    END
  END w_data[186]
  PIN w_data[187]
    DIRECTION OUTPUT ;
    USE SIGNAL ;
    PORT
      LAYER M7 ;
        RECT  80.704 0 80.736 0.07 ;
    END
  END w_data[187]
  PIN w_data[188]
    DIRECTION OUTPUT ;
    USE SIGNAL ;
    PORT
      LAYER M7 ;
        RECT  81.152 0 81.184 0.07 ;
    END
  END w_data[188]
  PIN w_data[189]
    DIRECTION OUTPUT ;
    USE SIGNAL ;
    PORT
      LAYER M7 ;
        RECT  81.6 0 81.632 0.07 ;
    END
  END w_data[189]
  PIN w_data[18]
    DIRECTION OUTPUT ;
    USE SIGNAL ;
    PORT
      LAYER M5 ;
        RECT  7.968 0 7.992 0.084 ;
    END
  END w_data[18]
  PIN w_data[190]
    DIRECTION OUTPUT ;
    USE SIGNAL ;
    PORT
      LAYER M7 ;
        RECT  81.984 0 82.016 0.07 ;
    END
  END w_data[190]
  PIN w_data[191]
    DIRECTION OUTPUT ;
    USE SIGNAL ;
    PORT
      LAYER M7 ;
        RECT  82.432 0 82.464 0.07 ;
    END
  END w_data[191]
  PIN w_data[192]
    DIRECTION OUTPUT ;
    USE SIGNAL ;
    PORT
      LAYER M5 ;
        RECT  82.896 0 82.92 0.084 ;
    END
  END w_data[192]
  PIN w_data[193]
    DIRECTION OUTPUT ;
    USE SIGNAL ;
    PORT
      LAYER M5 ;
        RECT  83.28 0 83.304 0.084 ;
    END
  END w_data[193]
  PIN w_data[194]
    DIRECTION OUTPUT ;
    USE SIGNAL ;
    PORT
      LAYER M5 ;
        RECT  83.712 0 83.736 0.084 ;
    END
  END w_data[194]
  PIN w_data[195]
    DIRECTION OUTPUT ;
    USE SIGNAL ;
    PORT
      LAYER M5 ;
        RECT  84.144 0 84.168 0.084 ;
    END
  END w_data[195]
  PIN w_data[196]
    DIRECTION OUTPUT ;
    USE SIGNAL ;
    PORT
      LAYER M5 ;
        RECT  84.576 0 84.6 0.084 ;
    END
  END w_data[196]
  PIN w_data[197]
    DIRECTION OUTPUT ;
    USE SIGNAL ;
    PORT
      LAYER M5 ;
        RECT  85.008 0 85.032 0.084 ;
    END
  END w_data[197]
  PIN w_data[198]
    DIRECTION OUTPUT ;
    USE SIGNAL ;
    PORT
      LAYER M5 ;
        RECT  85.44 0 85.464 0.084 ;
    END
  END w_data[198]
  PIN w_data[199]
    DIRECTION OUTPUT ;
    USE SIGNAL ;
    PORT
      LAYER M5 ;
        RECT  85.872 0 85.896 0.084 ;
    END
  END w_data[199]
  PIN w_data[19]
    DIRECTION OUTPUT ;
    USE SIGNAL ;
    PORT
      LAYER M5 ;
        RECT  8.4 0 8.424 0.084 ;
    END
  END w_data[19]
  PIN w_data[1]
    DIRECTION OUTPUT ;
    USE SIGNAL ;
    PORT
      LAYER M5 ;
        RECT  0.624 0 0.648 0.084 ;
    END
  END w_data[1]
  PIN w_data[200]
    DIRECTION OUTPUT ;
    USE SIGNAL ;
    PORT
      LAYER M5 ;
        RECT  86.304 0 86.328 0.084 ;
    END
  END w_data[200]
  PIN w_data[201]
    DIRECTION OUTPUT ;
    USE SIGNAL ;
    PORT
      LAYER M5 ;
        RECT  86.736 0 86.76 0.084 ;
    END
  END w_data[201]
  PIN w_data[202]
    DIRECTION OUTPUT ;
    USE SIGNAL ;
    PORT
      LAYER M5 ;
        RECT  87.168 0 87.192 0.084 ;
    END
  END w_data[202]
  PIN w_data[203]
    DIRECTION OUTPUT ;
    USE SIGNAL ;
    PORT
      LAYER M5 ;
        RECT  87.6 0 87.624 0.084 ;
    END
  END w_data[203]
  PIN w_data[204]
    DIRECTION OUTPUT ;
    USE SIGNAL ;
    PORT
      LAYER M5 ;
        RECT  88.032 0 88.056 0.084 ;
    END
  END w_data[204]
  PIN w_data[205]
    DIRECTION OUTPUT ;
    USE SIGNAL ;
    PORT
      LAYER M5 ;
        RECT  88.464 0 88.488 0.084 ;
    END
  END w_data[205]
  PIN w_data[206]
    DIRECTION OUTPUT ;
    USE SIGNAL ;
    PORT
      LAYER M5 ;
        RECT  88.896 0 88.92 0.084 ;
    END
  END w_data[206]
  PIN w_data[207]
    DIRECTION OUTPUT ;
    USE SIGNAL ;
    PORT
      LAYER M5 ;
        RECT  89.328 0 89.352 0.084 ;
    END
  END w_data[207]
  PIN w_data[208]
    DIRECTION OUTPUT ;
    USE SIGNAL ;
    PORT
      LAYER M5 ;
        RECT  89.76 0 89.784 0.084 ;
    END
  END w_data[208]
  PIN w_data[209]
    DIRECTION OUTPUT ;
    USE SIGNAL ;
    PORT
      LAYER M5 ;
        RECT  90.192 0 90.216 0.084 ;
    END
  END w_data[209]
  PIN w_data[20]
    DIRECTION OUTPUT ;
    USE SIGNAL ;
    PORT
      LAYER M5 ;
        RECT  8.832 0 8.856 0.084 ;
    END
  END w_data[20]
  PIN w_data[210]
    DIRECTION OUTPUT ;
    USE SIGNAL ;
    PORT
      LAYER M5 ;
        RECT  90.624 0 90.648 0.084 ;
    END
  END w_data[210]
  PIN w_data[211]
    DIRECTION OUTPUT ;
    USE SIGNAL ;
    PORT
      LAYER M5 ;
        RECT  91.056 0 91.08 0.084 ;
    END
  END w_data[211]
  PIN w_data[212]
    DIRECTION OUTPUT ;
    USE SIGNAL ;
    PORT
      LAYER M5 ;
        RECT  91.488 0 91.512 0.084 ;
    END
  END w_data[212]
  PIN w_data[213]
    DIRECTION OUTPUT ;
    USE SIGNAL ;
    PORT
      LAYER M5 ;
        RECT  91.92 0 91.944 0.084 ;
    END
  END w_data[213]
  PIN w_data[214]
    DIRECTION OUTPUT ;
    USE SIGNAL ;
    PORT
      LAYER M5 ;
        RECT  92.352 0 92.376 0.084 ;
    END
  END w_data[214]
  PIN w_data[215]
    DIRECTION OUTPUT ;
    USE SIGNAL ;
    PORT
      LAYER M5 ;
        RECT  92.784 0 92.808 0.084 ;
    END
  END w_data[215]
  PIN w_data[216]
    DIRECTION OUTPUT ;
    USE SIGNAL ;
    PORT
      LAYER M5 ;
        RECT  93.216 0 93.24 0.084 ;
    END
  END w_data[216]
  PIN w_data[217]
    DIRECTION OUTPUT ;
    USE SIGNAL ;
    PORT
      LAYER M5 ;
        RECT  93.648 0 93.672 0.084 ;
    END
  END w_data[217]
  PIN w_data[218]
    DIRECTION OUTPUT ;
    USE SIGNAL ;
    PORT
      LAYER M5 ;
        RECT  94.08 0 94.104 0.084 ;
    END
  END w_data[218]
  PIN w_data[219]
    DIRECTION OUTPUT ;
    USE SIGNAL ;
    PORT
      LAYER M5 ;
        RECT  94.512 0 94.536 0.084 ;
    END
  END w_data[219]
  PIN w_data[21]
    DIRECTION OUTPUT ;
    USE SIGNAL ;
    PORT
      LAYER M5 ;
        RECT  9.264 0 9.288 0.084 ;
    END
  END w_data[21]
  PIN w_data[220]
    DIRECTION OUTPUT ;
    USE SIGNAL ;
    PORT
      LAYER M5 ;
        RECT  94.944 0 94.968 0.084 ;
    END
  END w_data[220]
  PIN w_data[221]
    DIRECTION OUTPUT ;
    USE SIGNAL ;
    PORT
      LAYER M5 ;
        RECT  95.376 0 95.4 0.084 ;
    END
  END w_data[221]
  PIN w_data[222]
    DIRECTION OUTPUT ;
    USE SIGNAL ;
    PORT
      LAYER M5 ;
        RECT  95.808 0 95.832 0.084 ;
    END
  END w_data[222]
  PIN w_data[223]
    DIRECTION OUTPUT ;
    USE SIGNAL ;
    PORT
      LAYER M5 ;
        RECT  96.24 0 96.264 0.084 ;
    END
  END w_data[223]
  PIN w_data[224]
    DIRECTION OUTPUT ;
    USE SIGNAL ;
    PORT
      LAYER M7 ;
        RECT  96.64 0 96.672 0.07 ;
    END
  END w_data[224]
  PIN w_data[225]
    DIRECTION OUTPUT ;
    USE SIGNAL ;
    PORT
      LAYER M7 ;
        RECT  97.088 0 97.12 0.07 ;
    END
  END w_data[225]
  PIN w_data[226]
    DIRECTION OUTPUT ;
    USE SIGNAL ;
    PORT
      LAYER M7 ;
        RECT  97.536 0 97.568 0.07 ;
    END
  END w_data[226]
  PIN w_data[227]
    DIRECTION OUTPUT ;
    USE SIGNAL ;
    PORT
      LAYER M7 ;
        RECT  97.92 0 97.952 0.07 ;
    END
  END w_data[227]
  PIN w_data[228]
    DIRECTION OUTPUT ;
    USE SIGNAL ;
    PORT
      LAYER M7 ;
        RECT  98.368 0 98.4 0.07 ;
    END
  END w_data[228]
  PIN w_data[229]
    DIRECTION OUTPUT ;
    USE SIGNAL ;
    PORT
      LAYER M7 ;
        RECT  98.816 0 98.848 0.07 ;
    END
  END w_data[229]
  PIN w_data[22]
    DIRECTION OUTPUT ;
    USE SIGNAL ;
    PORT
      LAYER M5 ;
        RECT  9.696 0 9.72 0.084 ;
    END
  END w_data[22]
  PIN w_data[230]
    DIRECTION OUTPUT ;
    USE SIGNAL ;
    PORT
      LAYER M7 ;
        RECT  99.2 0 99.232 0.07 ;
    END
  END w_data[230]
  PIN w_data[231]
    DIRECTION OUTPUT ;
    USE SIGNAL ;
    PORT
      LAYER M7 ;
        RECT  99.648 0 99.68 0.07 ;
    END
  END w_data[231]
  PIN w_data[232]
    DIRECTION OUTPUT ;
    USE SIGNAL ;
    PORT
      LAYER M7 ;
        RECT  100.096 0 100.128 0.07 ;
    END
  END w_data[232]
  PIN w_data[233]
    DIRECTION OUTPUT ;
    USE SIGNAL ;
    PORT
      LAYER M7 ;
        RECT  100.544 0 100.576 0.07 ;
    END
  END w_data[233]
  PIN w_data[234]
    DIRECTION OUTPUT ;
    USE SIGNAL ;
    PORT
      LAYER M7 ;
        RECT  100.928 0 100.96 0.07 ;
    END
  END w_data[234]
  PIN w_data[235]
    DIRECTION OUTPUT ;
    USE SIGNAL ;
    PORT
      LAYER M7 ;
        RECT  101.376 0 101.408 0.07 ;
    END
  END w_data[235]
  PIN w_data[236]
    DIRECTION OUTPUT ;
    USE SIGNAL ;
    PORT
      LAYER M7 ;
        RECT  101.824 0 101.856 0.07 ;
    END
  END w_data[236]
  PIN w_data[237]
    DIRECTION OUTPUT ;
    USE SIGNAL ;
    PORT
      LAYER M7 ;
        RECT  102.272 0 102.304 0.07 ;
    END
  END w_data[237]
  PIN w_data[238]
    DIRECTION OUTPUT ;
    USE SIGNAL ;
    PORT
      LAYER M7 ;
        RECT  102.656 0 102.688 0.07 ;
    END
  END w_data[238]
  PIN w_data[239]
    DIRECTION OUTPUT ;
    USE SIGNAL ;
    PORT
      LAYER M7 ;
        RECT  103.104 0 103.136 0.07 ;
    END
  END w_data[239]
  PIN w_data[23]
    DIRECTION OUTPUT ;
    USE SIGNAL ;
    PORT
      LAYER M5 ;
        RECT  10.128 0 10.152 0.084 ;
    END
  END w_data[23]
  PIN w_data[240]
    DIRECTION OUTPUT ;
    USE SIGNAL ;
    PORT
      LAYER M7 ;
        RECT  103.552 0 103.584 0.07 ;
    END
  END w_data[240]
  PIN w_data[241]
    DIRECTION OUTPUT ;
    USE SIGNAL ;
    PORT
      LAYER M7 ;
        RECT  103.936 0 103.968 0.07 ;
    END
  END w_data[241]
  PIN w_data[242]
    DIRECTION OUTPUT ;
    USE SIGNAL ;
    PORT
      LAYER M7 ;
        RECT  104.384 0 104.416 0.07 ;
    END
  END w_data[242]
  PIN w_data[243]
    DIRECTION OUTPUT ;
    USE SIGNAL ;
    PORT
      LAYER M7 ;
        RECT  104.832 0 104.864 0.07 ;
    END
  END w_data[243]
  PIN w_data[244]
    DIRECTION OUTPUT ;
    USE SIGNAL ;
    PORT
      LAYER M7 ;
        RECT  105.28 0 105.312 0.07 ;
    END
  END w_data[244]
  PIN w_data[245]
    DIRECTION OUTPUT ;
    USE SIGNAL ;
    PORT
      LAYER M7 ;
        RECT  105.664 0 105.696 0.07 ;
    END
  END w_data[245]
  PIN w_data[246]
    DIRECTION OUTPUT ;
    USE SIGNAL ;
    PORT
      LAYER M7 ;
        RECT  106.112 0 106.144 0.07 ;
    END
  END w_data[246]
  PIN w_data[247]
    DIRECTION OUTPUT ;
    USE SIGNAL ;
    PORT
      LAYER M7 ;
        RECT  106.56 0 106.592 0.07 ;
    END
  END w_data[247]
  PIN w_data[248]
    DIRECTION OUTPUT ;
    USE SIGNAL ;
    PORT
      LAYER M7 ;
        RECT  107.008 0 107.04 0.07 ;
    END
  END w_data[248]
  PIN w_data[249]
    DIRECTION OUTPUT ;
    USE SIGNAL ;
    PORT
      LAYER M7 ;
        RECT  107.392 0 107.424 0.07 ;
    END
  END w_data[249]
  PIN w_data[24]
    DIRECTION OUTPUT ;
    USE SIGNAL ;
    PORT
      LAYER M5 ;
        RECT  10.56 0 10.584 0.084 ;
    END
  END w_data[24]
  PIN w_data[250]
    DIRECTION OUTPUT ;
    USE SIGNAL ;
    PORT
      LAYER M7 ;
        RECT  107.84 0 107.872 0.07 ;
    END
  END w_data[250]
  PIN w_data[251]
    DIRECTION OUTPUT ;
    USE SIGNAL ;
    PORT
      LAYER M7 ;
        RECT  108.288 0 108.32 0.07 ;
    END
  END w_data[251]
  PIN w_data[252]
    DIRECTION OUTPUT ;
    USE SIGNAL ;
    PORT
      LAYER M7 ;
        RECT  108.672 0 108.704 0.07 ;
    END
  END w_data[252]
  PIN w_data[253]
    DIRECTION OUTPUT ;
    USE SIGNAL ;
    PORT
      LAYER M7 ;
        RECT  109.12 0 109.152 0.07 ;
    END
  END w_data[253]
  PIN w_data[254]
    DIRECTION OUTPUT ;
    USE SIGNAL ;
    PORT
      LAYER M7 ;
        RECT  109.568 0 109.6 0.07 ;
    END
  END w_data[254]
  PIN w_data[255]
    DIRECTION OUTPUT ;
    USE SIGNAL ;
    PORT
      LAYER M7 ;
        RECT  110.016 0 110.048 0.07 ;
    END
  END w_data[255]
  PIN w_data[25]
    DIRECTION OUTPUT ;
    USE SIGNAL ;
    PORT
      LAYER M5 ;
        RECT  10.944 0 10.968 0.084 ;
    END
  END w_data[25]
  PIN w_data[26]
    DIRECTION OUTPUT ;
    USE SIGNAL ;
    PORT
      LAYER M5 ;
        RECT  11.376 0 11.4 0.084 ;
    END
  END w_data[26]
  PIN w_data[27]
    DIRECTION OUTPUT ;
    USE SIGNAL ;
    PORT
      LAYER M5 ;
        RECT  11.808 0 11.832 0.084 ;
    END
  END w_data[27]
  PIN w_data[28]
    DIRECTION OUTPUT ;
    USE SIGNAL ;
    PORT
      LAYER M5 ;
        RECT  12.24 0 12.264 0.084 ;
    END
  END w_data[28]
  PIN w_data[29]
    DIRECTION OUTPUT ;
    USE SIGNAL ;
    PORT
      LAYER M5 ;
        RECT  12.672 0 12.696 0.084 ;
    END
  END w_data[29]
  PIN w_data[2]
    DIRECTION OUTPUT ;
    USE SIGNAL ;
    PORT
      LAYER M5 ;
        RECT  1.056 0 1.08 0.084 ;
    END
  END w_data[2]
  PIN w_data[30]
    DIRECTION OUTPUT ;
    USE SIGNAL ;
    PORT
      LAYER M5 ;
        RECT  13.104 0 13.128 0.084 ;
    END
  END w_data[30]
  PIN w_data[31]
    DIRECTION OUTPUT ;
    USE SIGNAL ;
    PORT
      LAYER M5 ;
        RECT  13.536 0 13.56 0.084 ;
    END
  END w_data[31]
  PIN w_data[32]
    DIRECTION OUTPUT ;
    USE SIGNAL ;
    PORT
      LAYER M7 ;
        RECT  13.952 0 13.984 0.07 ;
    END
  END w_data[32]
  PIN w_data[33]
    DIRECTION OUTPUT ;
    USE SIGNAL ;
    PORT
      LAYER M7 ;
        RECT  14.4 0 14.432 0.07 ;
    END
  END w_data[33]
  PIN w_data[34]
    DIRECTION OUTPUT ;
    USE SIGNAL ;
    PORT
      LAYER M7 ;
        RECT  14.848 0 14.88 0.07 ;
    END
  END w_data[34]
  PIN w_data[35]
    DIRECTION OUTPUT ;
    USE SIGNAL ;
    PORT
      LAYER M7 ;
        RECT  15.296 0 15.328 0.07 ;
    END
  END w_data[35]
  PIN w_data[36]
    DIRECTION OUTPUT ;
    USE SIGNAL ;
    PORT
      LAYER M7 ;
        RECT  15.68 0 15.712 0.07 ;
    END
  END w_data[36]
  PIN w_data[37]
    DIRECTION OUTPUT ;
    USE SIGNAL ;
    PORT
      LAYER M7 ;
        RECT  16.128 0 16.16 0.07 ;
    END
  END w_data[37]
  PIN w_data[38]
    DIRECTION OUTPUT ;
    USE SIGNAL ;
    PORT
      LAYER M7 ;
        RECT  16.576 0 16.608 0.07 ;
    END
  END w_data[38]
  PIN w_data[39]
    DIRECTION OUTPUT ;
    USE SIGNAL ;
    PORT
      LAYER M7 ;
        RECT  16.96 0 16.992 0.07 ;
    END
  END w_data[39]
  PIN w_data[3]
    DIRECTION OUTPUT ;
    USE SIGNAL ;
    PORT
      LAYER M5 ;
        RECT  1.488 0 1.512 0.084 ;
    END
  END w_data[3]
  PIN w_data[40]
    DIRECTION OUTPUT ;
    USE SIGNAL ;
    PORT
      LAYER M7 ;
        RECT  17.408 0 17.44 0.07 ;
    END
  END w_data[40]
  PIN w_data[41]
    DIRECTION OUTPUT ;
    USE SIGNAL ;
    PORT
      LAYER M7 ;
        RECT  17.856 0 17.888 0.07 ;
    END
  END w_data[41]
  PIN w_data[42]
    DIRECTION OUTPUT ;
    USE SIGNAL ;
    PORT
      LAYER M7 ;
        RECT  18.304 0 18.336 0.07 ;
    END
  END w_data[42]
  PIN w_data[43]
    DIRECTION OUTPUT ;
    USE SIGNAL ;
    PORT
      LAYER M7 ;
        RECT  18.688 0 18.72 0.07 ;
    END
  END w_data[43]
  PIN w_data[44]
    DIRECTION OUTPUT ;
    USE SIGNAL ;
    PORT
      LAYER M7 ;
        RECT  19.136 0 19.168 0.07 ;
    END
  END w_data[44]
  PIN w_data[45]
    DIRECTION OUTPUT ;
    USE SIGNAL ;
    PORT
      LAYER M7 ;
        RECT  19.584 0 19.616 0.07 ;
    END
  END w_data[45]
  PIN w_data[46]
    DIRECTION OUTPUT ;
    USE SIGNAL ;
    PORT
      LAYER M7 ;
        RECT  20.032 0 20.064 0.07 ;
    END
  END w_data[46]
  PIN w_data[47]
    DIRECTION OUTPUT ;
    USE SIGNAL ;
    PORT
      LAYER M7 ;
        RECT  20.416 0 20.448 0.07 ;
    END
  END w_data[47]
  PIN w_data[48]
    DIRECTION OUTPUT ;
    USE SIGNAL ;
    PORT
      LAYER M7 ;
        RECT  20.864 0 20.896 0.07 ;
    END
  END w_data[48]
  PIN w_data[49]
    DIRECTION OUTPUT ;
    USE SIGNAL ;
    PORT
      LAYER M7 ;
        RECT  21.312 0 21.344 0.07 ;
    END
  END w_data[49]
  PIN w_data[4]
    DIRECTION OUTPUT ;
    USE SIGNAL ;
    PORT
      LAYER M5 ;
        RECT  1.92 0 1.944 0.084 ;
    END
  END w_data[4]
  PIN w_data[50]
    DIRECTION OUTPUT ;
    USE SIGNAL ;
    PORT
      LAYER M7 ;
        RECT  21.76 0 21.792 0.07 ;
    END
  END w_data[50]
  PIN w_data[51]
    DIRECTION OUTPUT ;
    USE SIGNAL ;
    PORT
      LAYER M7 ;
        RECT  22.144 0 22.176 0.07 ;
    END
  END w_data[51]
  PIN w_data[52]
    DIRECTION OUTPUT ;
    USE SIGNAL ;
    PORT
      LAYER M7 ;
        RECT  22.592 0 22.624 0.07 ;
    END
  END w_data[52]
  PIN w_data[53]
    DIRECTION OUTPUT ;
    USE SIGNAL ;
    PORT
      LAYER M7 ;
        RECT  23.04 0 23.072 0.07 ;
    END
  END w_data[53]
  PIN w_data[54]
    DIRECTION OUTPUT ;
    USE SIGNAL ;
    PORT
      LAYER M7 ;
        RECT  23.424 0 23.456 0.07 ;
    END
  END w_data[54]
  PIN w_data[55]
    DIRECTION OUTPUT ;
    USE SIGNAL ;
    PORT
      LAYER M7 ;
        RECT  23.872 0 23.904 0.07 ;
    END
  END w_data[55]
  PIN w_data[56]
    DIRECTION OUTPUT ;
    USE SIGNAL ;
    PORT
      LAYER M7 ;
        RECT  24.32 0 24.352 0.07 ;
    END
  END w_data[56]
  PIN w_data[57]
    DIRECTION OUTPUT ;
    USE SIGNAL ;
    PORT
      LAYER M7 ;
        RECT  24.768 0 24.8 0.07 ;
    END
  END w_data[57]
  PIN w_data[58]
    DIRECTION OUTPUT ;
    USE SIGNAL ;
    PORT
      LAYER M7 ;
        RECT  25.152 0 25.184 0.07 ;
    END
  END w_data[58]
  PIN w_data[59]
    DIRECTION OUTPUT ;
    USE SIGNAL ;
    PORT
      LAYER M7 ;
        RECT  25.6 0 25.632 0.07 ;
    END
  END w_data[59]
  PIN w_data[5]
    DIRECTION OUTPUT ;
    USE SIGNAL ;
    PORT
      LAYER M5 ;
        RECT  2.352 0 2.376 0.084 ;
    END
  END w_data[5]
  PIN w_data[60]
    DIRECTION OUTPUT ;
    USE SIGNAL ;
    PORT
      LAYER M7 ;
        RECT  26.048 0 26.08 0.07 ;
    END
  END w_data[60]
  PIN w_data[61]
    DIRECTION OUTPUT ;
    USE SIGNAL ;
    PORT
      LAYER M7 ;
        RECT  26.496 0 26.528 0.07 ;
    END
  END w_data[61]
  PIN w_data[62]
    DIRECTION OUTPUT ;
    USE SIGNAL ;
    PORT
      LAYER M7 ;
        RECT  26.88 0 26.912 0.07 ;
    END
  END w_data[62]
  PIN w_data[63]
    DIRECTION OUTPUT ;
    USE SIGNAL ;
    PORT
      LAYER M7 ;
        RECT  27.328 0 27.36 0.07 ;
    END
  END w_data[63]
  PIN w_data[64]
    DIRECTION OUTPUT ;
    USE SIGNAL ;
    PORT
      LAYER M5 ;
        RECT  27.744 0 27.768 0.084 ;
    END
  END w_data[64]
  PIN w_data[65]
    DIRECTION OUTPUT ;
    USE SIGNAL ;
    PORT
      LAYER M5 ;
        RECT  28.176 0 28.2 0.084 ;
    END
  END w_data[65]
  PIN w_data[66]
    DIRECTION OUTPUT ;
    USE SIGNAL ;
    PORT
      LAYER M5 ;
        RECT  28.608 0 28.632 0.084 ;
    END
  END w_data[66]
  PIN w_data[67]
    DIRECTION OUTPUT ;
    USE SIGNAL ;
    PORT
      LAYER M5 ;
        RECT  29.04 0 29.064 0.084 ;
    END
  END w_data[67]
  PIN w_data[68]
    DIRECTION OUTPUT ;
    USE SIGNAL ;
    PORT
      LAYER M5 ;
        RECT  29.472 0 29.496 0.084 ;
    END
  END w_data[68]
  PIN w_data[69]
    DIRECTION OUTPUT ;
    USE SIGNAL ;
    PORT
      LAYER M5 ;
        RECT  29.904 0 29.928 0.084 ;
    END
  END w_data[69]
  PIN w_data[6]
    DIRECTION OUTPUT ;
    USE SIGNAL ;
    PORT
      LAYER M5 ;
        RECT  2.784 0 2.808 0.084 ;
    END
  END w_data[6]
  PIN w_data[70]
    DIRECTION OUTPUT ;
    USE SIGNAL ;
    PORT
      LAYER M5 ;
        RECT  30.336 0 30.36 0.084 ;
    END
  END w_data[70]
  PIN w_data[71]
    DIRECTION OUTPUT ;
    USE SIGNAL ;
    PORT
      LAYER M5 ;
        RECT  30.768 0 30.792 0.084 ;
    END
  END w_data[71]
  PIN w_data[72]
    DIRECTION OUTPUT ;
    USE SIGNAL ;
    PORT
      LAYER M5 ;
        RECT  31.2 0 31.224 0.084 ;
    END
  END w_data[72]
  PIN w_data[73]
    DIRECTION OUTPUT ;
    USE SIGNAL ;
    PORT
      LAYER M5 ;
        RECT  31.632 0 31.656 0.084 ;
    END
  END w_data[73]
  PIN w_data[74]
    DIRECTION OUTPUT ;
    USE SIGNAL ;
    PORT
      LAYER M5 ;
        RECT  32.064 0 32.088 0.084 ;
    END
  END w_data[74]
  PIN w_data[75]
    DIRECTION OUTPUT ;
    USE SIGNAL ;
    PORT
      LAYER M5 ;
        RECT  32.496 0 32.52 0.084 ;
    END
  END w_data[75]
  PIN w_data[76]
    DIRECTION OUTPUT ;
    USE SIGNAL ;
    PORT
      LAYER M5 ;
        RECT  32.928 0 32.952 0.084 ;
    END
  END w_data[76]
  PIN w_data[77]
    DIRECTION OUTPUT ;
    USE SIGNAL ;
    PORT
      LAYER M5 ;
        RECT  33.36 0 33.384 0.084 ;
    END
  END w_data[77]
  PIN w_data[78]
    DIRECTION OUTPUT ;
    USE SIGNAL ;
    PORT
      LAYER M5 ;
        RECT  33.792 0 33.816 0.084 ;
    END
  END w_data[78]
  PIN w_data[79]
    DIRECTION OUTPUT ;
    USE SIGNAL ;
    PORT
      LAYER M5 ;
        RECT  34.224 0 34.248 0.084 ;
    END
  END w_data[79]
  PIN w_data[7]
    DIRECTION OUTPUT ;
    USE SIGNAL ;
    PORT
      LAYER M5 ;
        RECT  3.216 0 3.24 0.084 ;
    END
  END w_data[7]
  PIN w_data[80]
    DIRECTION OUTPUT ;
    USE SIGNAL ;
    PORT
      LAYER M5 ;
        RECT  34.656 0 34.68 0.084 ;
    END
  END w_data[80]
  PIN w_data[81]
    DIRECTION OUTPUT ;
    USE SIGNAL ;
    PORT
      LAYER M5 ;
        RECT  35.088 0 35.112 0.084 ;
    END
  END w_data[81]
  PIN w_data[82]
    DIRECTION OUTPUT ;
    USE SIGNAL ;
    PORT
      LAYER M5 ;
        RECT  35.52 0 35.544 0.084 ;
    END
  END w_data[82]
  PIN w_data[83]
    DIRECTION OUTPUT ;
    USE SIGNAL ;
    PORT
      LAYER M5 ;
        RECT  35.952 0 35.976 0.084 ;
    END
  END w_data[83]
  PIN w_data[84]
    DIRECTION OUTPUT ;
    USE SIGNAL ;
    PORT
      LAYER M5 ;
        RECT  36.384 0 36.408 0.084 ;
    END
  END w_data[84]
  PIN w_data[85]
    DIRECTION OUTPUT ;
    USE SIGNAL ;
    PORT
      LAYER M5 ;
        RECT  36.816 0 36.84 0.084 ;
    END
  END w_data[85]
  PIN w_data[86]
    DIRECTION OUTPUT ;
    USE SIGNAL ;
    PORT
      LAYER M5 ;
        RECT  37.248 0 37.272 0.084 ;
    END
  END w_data[86]
  PIN w_data[87]
    DIRECTION OUTPUT ;
    USE SIGNAL ;
    PORT
      LAYER M5 ;
        RECT  37.68 0 37.704 0.084 ;
    END
  END w_data[87]
  PIN w_data[88]
    DIRECTION OUTPUT ;
    USE SIGNAL ;
    PORT
      LAYER M5 ;
        RECT  38.112 0 38.136 0.084 ;
    END
  END w_data[88]
  PIN w_data[89]
    DIRECTION OUTPUT ;
    USE SIGNAL ;
    PORT
      LAYER M5 ;
        RECT  38.544 0 38.568 0.084 ;
    END
  END w_data[89]
  PIN w_data[8]
    DIRECTION OUTPUT ;
    USE SIGNAL ;
    PORT
      LAYER M5 ;
        RECT  3.648 0 3.672 0.084 ;
    END
  END w_data[8]
  PIN w_data[90]
    DIRECTION OUTPUT ;
    USE SIGNAL ;
    PORT
      LAYER M5 ;
        RECT  38.976 0 39 0.084 ;
    END
  END w_data[90]
  PIN w_data[91]
    DIRECTION OUTPUT ;
    USE SIGNAL ;
    PORT
      LAYER M5 ;
        RECT  39.408 0 39.432 0.084 ;
    END
  END w_data[91]
  PIN w_data[92]
    DIRECTION OUTPUT ;
    USE SIGNAL ;
    PORT
      LAYER M5 ;
        RECT  39.792 0 39.816 0.084 ;
    END
  END w_data[92]
  PIN w_data[93]
    DIRECTION OUTPUT ;
    USE SIGNAL ;
    PORT
      LAYER M5 ;
        RECT  40.224 0 40.248 0.084 ;
    END
  END w_data[93]
  PIN w_data[94]
    DIRECTION OUTPUT ;
    USE SIGNAL ;
    PORT
      LAYER M5 ;
        RECT  40.656 0 40.68 0.084 ;
    END
  END w_data[94]
  PIN w_data[95]
    DIRECTION OUTPUT ;
    USE SIGNAL ;
    PORT
      LAYER M5 ;
        RECT  41.088 0 41.112 0.084 ;
    END
  END w_data[95]
  PIN w_data[96]
    DIRECTION OUTPUT ;
    USE SIGNAL ;
    PORT
      LAYER M7 ;
        RECT  41.536 0 41.568 0.07 ;
    END
  END w_data[96]
  PIN w_data[97]
    DIRECTION OUTPUT ;
    USE SIGNAL ;
    PORT
      LAYER M7 ;
        RECT  41.984 0 42.016 0.07 ;
    END
  END w_data[97]
  PIN w_data[98]
    DIRECTION OUTPUT ;
    USE SIGNAL ;
    PORT
      LAYER M7 ;
        RECT  42.368 0 42.4 0.07 ;
    END
  END w_data[98]
  PIN w_data[99]
    DIRECTION OUTPUT ;
    USE SIGNAL ;
    PORT
      LAYER M7 ;
        RECT  42.816 0 42.848 0.07 ;
    END
  END w_data[99]
  PIN w_data[9]
    DIRECTION OUTPUT ;
    USE SIGNAL ;
    PORT
      LAYER M5 ;
        RECT  4.08 0 4.104 0.084 ;
    END
  END w_data[9]
  PIN w_room
    DIRECTION INPUT ;
    USE SIGNAL ;
    PORT
      LAYER M5 ;
        RECT  110.448 0 110.472 0.084 ;
    END
  END w_room
  PIN w_sec[0]
    DIRECTION OUTPUT ;
    USE SIGNAL ;
    PORT
      LAYER M5 ;
        RECT  110.88 0 110.904 0.084 ;
    END
  END w_sec[0]
  PIN w_sec[10]
    DIRECTION OUTPUT ;
    USE SIGNAL ;
    PORT
      LAYER M5 ;
        RECT  115.152 0 115.176 0.084 ;
    END
  END w_sec[10]
  PIN w_sec[11]
    DIRECTION OUTPUT ;
    USE SIGNAL ;
    PORT
      LAYER M5 ;
        RECT  115.584 0 115.608 0.084 ;
    END
  END w_sec[11]
  PIN w_sec[12]
    DIRECTION OUTPUT ;
    USE SIGNAL ;
    PORT
      LAYER M5 ;
        RECT  116.016 0 116.04 0.084 ;
    END
  END w_sec[12]
  PIN w_sec[13]
    DIRECTION OUTPUT ;
    USE SIGNAL ;
    PORT
      LAYER M5 ;
        RECT  116.448 0 116.472 0.084 ;
    END
  END w_sec[13]
  PIN w_sec[14]
    DIRECTION OUTPUT ;
    USE SIGNAL ;
    PORT
      LAYER M5 ;
        RECT  116.88 0 116.904 0.084 ;
    END
  END w_sec[14]
  PIN w_sec[15]
    DIRECTION OUTPUT ;
    USE SIGNAL ;
    PORT
      LAYER M5 ;
        RECT  117.312 0 117.336 0.084 ;
    END
  END w_sec[15]
  PIN w_sec[16]
    DIRECTION OUTPUT ;
    USE SIGNAL ;
    PORT
      LAYER M5 ;
        RECT  117.744 0 117.768 0.084 ;
    END
  END w_sec[16]
  PIN w_sec[17]
    DIRECTION OUTPUT ;
    USE SIGNAL ;
    PORT
      LAYER M5 ;
        RECT  118.176 0 118.2 0.084 ;
    END
  END w_sec[17]
  PIN w_sec[18]
    DIRECTION OUTPUT ;
    USE SIGNAL ;
    PORT
      LAYER M5 ;
        RECT  118.608 0 118.632 0.084 ;
    END
  END w_sec[18]
  PIN w_sec[19]
    DIRECTION OUTPUT ;
    USE SIGNAL ;
    PORT
      LAYER M5 ;
        RECT  119.04 0 119.064 0.084 ;
    END
  END w_sec[19]
  PIN w_sec[1]
    DIRECTION OUTPUT ;
    USE SIGNAL ;
    PORT
      LAYER M5 ;
        RECT  111.312 0 111.336 0.084 ;
    END
  END w_sec[1]
  PIN w_sec[20]
    DIRECTION OUTPUT ;
    USE SIGNAL ;
    PORT
      LAYER M5 ;
        RECT  119.472 0 119.496 0.084 ;
    END
  END w_sec[20]
  PIN w_sec[21]
    DIRECTION OUTPUT ;
    USE SIGNAL ;
    PORT
      LAYER M5 ;
        RECT  119.904 0 119.928 0.084 ;
    END
  END w_sec[21]
  PIN w_sec[22]
    DIRECTION OUTPUT ;
    USE SIGNAL ;
    PORT
      LAYER M5 ;
        RECT  120.336 0 120.36 0.084 ;
    END
  END w_sec[22]
  PIN w_sec[23]
    DIRECTION OUTPUT ;
    USE SIGNAL ;
    PORT
      LAYER M5 ;
        RECT  120.768 0 120.792 0.084 ;
    END
  END w_sec[23]
  PIN w_sec[2]
    DIRECTION OUTPUT ;
    USE SIGNAL ;
    PORT
      LAYER M5 ;
        RECT  111.744 0 111.768 0.084 ;
    END
  END w_sec[2]
  PIN w_sec[3]
    DIRECTION OUTPUT ;
    USE SIGNAL ;
    PORT
      LAYER M5 ;
        RECT  112.128 0 112.152 0.084 ;
    END
  END w_sec[3]
  PIN w_sec[4]
    DIRECTION OUTPUT ;
    USE SIGNAL ;
    PORT
      LAYER M5 ;
        RECT  112.56 0 112.584 0.084 ;
    END
  END w_sec[4]
  PIN w_sec[5]
    DIRECTION OUTPUT ;
    USE SIGNAL ;
    PORT
      LAYER M5 ;
        RECT  112.992 0 113.016 0.084 ;
    END
  END w_sec[5]
  PIN w_sec[6]
    DIRECTION OUTPUT ;
    USE SIGNAL ;
    PORT
      LAYER M5 ;
        RECT  113.424 0 113.448 0.084 ;
    END
  END w_sec[6]
  PIN w_sec[7]
    DIRECTION OUTPUT ;
    USE SIGNAL ;
    PORT
      LAYER M5 ;
        RECT  113.856 0 113.88 0.084 ;
    END
  END w_sec[7]
  PIN w_sec[8]
    DIRECTION OUTPUT ;
    USE SIGNAL ;
    PORT
      LAYER M5 ;
        RECT  114.288 0 114.312 0.084 ;
    END
  END w_sec[8]
  PIN w_sec[9]
    DIRECTION OUTPUT ;
    USE SIGNAL ;
    PORT
      LAYER M5 ;
        RECT  114.72 0 114.744 0.084 ;
    END
  END w_sec[9]
  PIN w_tag[0]
    DIRECTION OUTPUT ;
    USE SIGNAL ;
    PORT
      LAYER M5 ;
        RECT  121.2 0 121.224 0.084 ;
    END
  END w_tag[0]
  PIN w_tag[1]
    DIRECTION OUTPUT ;
    USE SIGNAL ;
    PORT
      LAYER M5 ;
        RECT  121.632 0 121.656 0.084 ;
    END
  END w_tag[1]
  PIN w_tag[2]
    DIRECTION OUTPUT ;
    USE SIGNAL ;
    PORT
      LAYER M5 ;
        RECT  122.064 0 122.088 0.084 ;
    END
  END w_tag[2]
  PIN w_tag[3]
    DIRECTION OUTPUT ;
    USE SIGNAL ;
    PORT
      LAYER M5 ;
        RECT  122.496 0 122.52 0.084 ;
    END
  END w_tag[3]
  PIN w_tag[4]
    DIRECTION OUTPUT ;
    USE SIGNAL ;
    PORT
      LAYER M5 ;
        RECT  122.928 0 122.952 0.084 ;
    END
  END w_tag[4]
  PIN w_tag[5]
    DIRECTION OUTPUT ;
    USE SIGNAL ;
    PORT
      LAYER M5 ;
        RECT  123.36 0 123.384 0.084 ;
    END
  END w_tag[5]
  PIN w_tag[6]
    DIRECTION OUTPUT ;
    USE SIGNAL ;
    PORT
      LAYER M5 ;
        RECT  123.792 0 123.816 0.084 ;
    END
  END w_tag[6]
  PIN w_tag[7]
    DIRECTION OUTPUT ;
    USE SIGNAL ;
    PORT
      LAYER M7 ;
        RECT  124.224 0 124.256 0.07 ;
    END
  END w_tag[7]
  PIN w_tag[8]
    DIRECTION OUTPUT ;
    USE SIGNAL ;
    PORT
      LAYER M7 ;
        RECT  124.608 0 124.64 0.07 ;
    END
  END w_tag[8]
  PIN w_v
    DIRECTION OUTPUT ;
    USE SIGNAL ;
    PORT
      LAYER M7 ;
        RECT  125.056 0 125.088 0.07 ;
    END
  END w_v
  PIN wd_tag[0]
    DIRECTION INPUT ;
    USE SIGNAL ;
    PORT
      LAYER M7 ;
        RECT  125.504 0 125.536 0.07 ;
    END
  END wd_tag[0]
  PIN wd_tag[1]
    DIRECTION INPUT ;
    USE SIGNAL ;
    PORT
      LAYER M7 ;
        RECT  125.952 0 125.984 0.07 ;
    END
  END wd_tag[1]
  PIN wd_tag[2]
    DIRECTION INPUT ;
    USE SIGNAL ;
    PORT
      LAYER M7 ;
        RECT  126.336 0 126.368 0.07 ;
    END
  END wd_tag[2]
  PIN wd_tag[3]
    DIRECTION INPUT ;
    USE SIGNAL ;
    PORT
      LAYER M7 ;
        RECT  126.784 0 126.816 0.07 ;
    END
  END wd_tag[3]
  PIN wd_tag[4]
    DIRECTION INPUT ;
    USE SIGNAL ;
    PORT
      LAYER M7 ;
        RECT  127.232 0 127.264 0.07 ;
    END
  END wd_tag[4]
  PIN wd_tag[5]
    DIRECTION INPUT ;
    USE SIGNAL ;
    PORT
      LAYER M7 ;
        RECT  127.616 0 127.648 0.07 ;
    END
  END wd_tag[5]
  PIN wd_tag[6]
    DIRECTION INPUT ;
    USE SIGNAL ;
    PORT
      LAYER M7 ;
        RECT  128.064 0 128.096 0.07 ;
    END
  END wd_tag[6]
  PIN wd_tag[7]
    DIRECTION INPUT ;
    USE SIGNAL ;
    PORT
      LAYER M7 ;
        RECT  128.512 0 128.544 0.07 ;
    END
  END wd_tag[7]
  PIN wd_tag[8]
    DIRECTION INPUT ;
    USE SIGNAL ;
    PORT
      LAYER M7 ;
        RECT  128.96 0 128.992 0.07 ;
    END
  END wd_tag[8]
  PIN wd_v
    DIRECTION INPUT ;
    USE SIGNAL ;
    PORT
      LAYER M7 ;
        RECT  129.344 0 129.376 0.07 ;
    END
  END wd_v
  PIN VDD
    DIRECTION INOUT ;
    USE POWER ;
    PORT
      LAYER M6 ;
        RECT  2.16 181.113 127.44 181.401 ;
        RECT  2.16 175.713 127.44 176.001 ;
        RECT  2.16 170.313 127.44 170.601 ;
        RECT  2.16 164.913 127.44 165.201 ;
        RECT  2.16 159.513 127.44 159.801 ;
        RECT  2.16 154.113 127.44 154.401 ;
        RECT  2.16 148.713 127.44 149.001 ;
        RECT  2.16 143.313 127.44 143.601 ;
        RECT  2.16 137.913 127.44 138.201 ;
        RECT  2.16 132.513 127.44 132.801 ;
        RECT  2.16 127.113 127.44 127.401 ;
        RECT  2.16 121.713 127.44 122.001 ;
        RECT  2.16 116.313 127.44 116.601 ;
        RECT  2.16 110.913 127.44 111.201 ;
        RECT  2.16 105.513 127.44 105.801 ;
        RECT  2.16 100.113 127.44 100.401 ;
        RECT  2.16 94.713 127.44 95.001 ;
        RECT  2.16 89.313 127.44 89.601 ;
        RECT  2.16 83.913 127.44 84.201 ;
        RECT  2.16 78.513 127.44 78.801 ;
        RECT  2.16 73.113 127.44 73.401 ;
        RECT  2.16 67.713 127.44 68.001 ;
        RECT  2.16 62.313 127.44 62.601 ;
        RECT  2.16 56.913 127.44 57.201 ;
        RECT  2.16 51.513 127.44 51.801 ;
        RECT  2.16 46.113 127.44 46.401 ;
        RECT  2.16 40.713 127.44 41.001 ;
        RECT  2.16 35.313 127.44 35.601 ;
        RECT  2.16 29.913 127.44 30.201 ;
        RECT  2.16 24.513 127.44 24.801 ;
        RECT  2.16 19.113 127.44 19.401 ;
        RECT  2.16 13.713 127.44 14.001 ;
        RECT  2.16 8.313 127.44 8.601 ;
        RECT  2.16 2.913 127.44 3.201 ;
    END
  END VDD
  PIN VSS
    DIRECTION INOUT ;
    USE GROUND ;
    PORT
      LAYER M6 ;
        RECT  2.16 180.729 127.44 181.017 ;
        RECT  2.16 175.329 127.44 175.617 ;
        RECT  2.16 169.929 127.44 170.217 ;
        RECT  2.16 164.529 127.44 164.817 ;
        RECT  2.16 159.129 127.44 159.417 ;
        RECT  2.16 153.729 127.44 154.017 ;
        RECT  2.16 148.329 127.44 148.617 ;
        RECT  2.16 142.929 127.44 143.217 ;
        RECT  2.16 137.529 127.44 137.817 ;
        RECT  2.16 132.129 127.44 132.417 ;
        RECT  2.16 126.729 127.44 127.017 ;
        RECT  2.16 121.329 127.44 121.617 ;
        RECT  2.16 115.929 127.44 116.217 ;
        RECT  2.16 110.529 127.44 110.817 ;
        RECT  2.16 105.129 127.44 105.417 ;
        RECT  2.16 99.729 127.44 100.017 ;
        RECT  2.16 94.329 127.44 94.617 ;
        RECT  2.16 88.929 127.44 89.217 ;
        RECT  2.16 83.529 127.44 83.817 ;
        RECT  2.16 78.129 127.44 78.417 ;
        RECT  2.16 72.729 127.44 73.017 ;
        RECT  2.16 67.329 127.44 67.617 ;
        RECT  2.16 61.929 127.44 62.217 ;
        RECT  2.16 56.529 127.44 56.817 ;
        RECT  2.16 51.129 127.44 51.417 ;
        RECT  2.16 45.729 127.44 46.017 ;
        RECT  2.16 40.329 127.44 40.617 ;
        RECT  2.16 34.929 127.44 35.217 ;
        RECT  2.16 29.529 127.44 29.817 ;
        RECT  2.16 24.129 127.44 24.417 ;
        RECT  2.16 18.729 127.44 19.017 ;
        RECT  2.16 13.329 127.44 13.617 ;
        RECT  2.16 7.929 127.44 8.217 ;
        RECT  2.16 2.529 127.44 2.817 ;
    END
  END VSS
  OBS
    LAYER RVTN ;
     RECT  2.16 2.16 127.44 2.295 ;
     RECT  2.16 2.565 127.44 2.835 ;
     RECT  2.16 3.105 127.44 3.375 ;
     RECT  2.16 3.645 127.44 3.915 ;
     RECT  2.16 4.185 127.44 4.455 ;
     RECT  2.16 4.725 127.44 4.995 ;
     RECT  2.16 5.265 127.44 5.535 ;
     RECT  2.16 5.805 127.44 6.075 ;
     RECT  2.16 6.345 127.44 6.615 ;
     RECT  2.16 6.885 127.44 7.155 ;
     RECT  2.16 7.425 127.44 7.695 ;
     RECT  2.16 7.965 127.44 8.235 ;
     RECT  2.16 8.505 127.44 8.775 ;
     RECT  2.16 9.045 127.44 9.315 ;
     RECT  2.16 9.585 127.44 9.855 ;
     RECT  2.16 10.125 127.44 10.395 ;
     RECT  2.16 10.665 127.44 10.935 ;
     RECT  2.16 11.205 127.44 11.475 ;
     RECT  2.16 11.745 127.44 12.015 ;
     RECT  2.16 12.285 127.44 12.555 ;
     RECT  2.16 12.825 127.44 13.095 ;
     RECT  2.16 13.365 127.44 13.635 ;
     RECT  2.16 13.905 127.44 14.175 ;
     RECT  2.16 14.445 127.44 14.715 ;
     RECT  2.16 14.985 127.44 15.255 ;
     RECT  2.16 15.525 127.44 15.795 ;
     RECT  2.16 16.065 127.44 16.335 ;
     RECT  2.16 16.605 127.44 16.875 ;
     RECT  2.16 17.145 127.44 17.415 ;
     RECT  2.16 17.685 127.44 17.955 ;
     RECT  2.16 18.225 127.44 18.495 ;
     RECT  2.16 18.765 127.44 19.035 ;
     RECT  2.16 19.305 127.44 19.575 ;
     RECT  2.16 19.845 127.44 20.115 ;
     RECT  2.16 20.385 127.44 20.655 ;
     RECT  2.16 20.925 127.44 21.195 ;
     RECT  2.16 21.465 127.44 21.735 ;
     RECT  2.16 22.005 127.44 22.275 ;
     RECT  2.16 22.545 127.44 22.815 ;
     RECT  2.16 23.085 127.44 23.355 ;
     RECT  2.16 23.625 127.44 23.895 ;
     RECT  2.16 24.165 127.44 24.435 ;
     RECT  2.16 24.705 127.44 24.975 ;
     RECT  2.16 25.245 127.44 25.515 ;
     RECT  2.16 25.785 127.44 26.055 ;
     RECT  2.16 26.325 127.44 26.595 ;
     RECT  2.16 26.865 127.44 27.135 ;
     RECT  2.16 27.405 127.44 27.675 ;
     RECT  2.16 27.945 127.44 28.215 ;
     RECT  2.16 28.485 127.44 28.755 ;
     RECT  2.16 29.025 127.44 29.295 ;
     RECT  2.16 29.565 127.44 29.835 ;
     RECT  2.16 30.105 127.44 30.375 ;
     RECT  2.16 30.645 127.44 30.915 ;
     RECT  2.16 31.185 127.44 31.455 ;
     RECT  2.16 31.725 127.44 31.995 ;
     RECT  2.16 32.265 127.44 32.535 ;
     RECT  2.16 32.805 127.44 33.075 ;
     RECT  2.16 33.345 127.44 33.615 ;
     RECT  2.16 33.885 127.44 34.155 ;
     RECT  2.16 34.425 127.44 34.695 ;
     RECT  2.16 34.965 127.44 35.235 ;
     RECT  2.16 35.505 127.44 35.775 ;
     RECT  2.16 36.045 127.44 36.315 ;
     RECT  2.16 36.585 127.44 36.855 ;
     RECT  2.16 37.125 127.44 37.395 ;
     RECT  2.16 37.665 127.44 37.935 ;
     RECT  2.16 38.205 127.44 38.475 ;
     RECT  2.16 38.745 127.44 39.015 ;
     RECT  2.16 39.285 127.44 39.555 ;
     RECT  2.16 39.825 127.44 40.095 ;
     RECT  2.16 40.365 127.44 40.635 ;
     RECT  2.16 40.905 127.44 41.175 ;
     RECT  2.16 41.445 127.44 41.715 ;
     RECT  2.16 41.985 127.44 42.255 ;
     RECT  2.16 42.525 127.44 42.795 ;
     RECT  2.16 43.065 127.44 43.335 ;
     RECT  2.16 43.605 127.44 43.875 ;
     RECT  2.16 44.145 127.44 44.415 ;
     RECT  2.16 44.685 127.44 44.955 ;
     RECT  2.16 45.225 127.44 45.495 ;
     RECT  2.16 45.765 127.44 46.035 ;
     RECT  2.16 46.305 127.44 46.575 ;
     RECT  2.16 46.845 127.44 47.115 ;
     RECT  2.16 47.385 127.44 47.655 ;
     RECT  2.16 47.925 127.44 48.195 ;
     RECT  2.16 48.465 127.44 48.735 ;
     RECT  2.16 49.005 127.44 49.275 ;
     RECT  2.16 49.545 127.44 49.815 ;
     RECT  2.16 50.085 127.44 50.355 ;
     RECT  2.16 50.625 127.44 50.895 ;
     RECT  2.16 51.165 127.44 51.435 ;
     RECT  2.16 51.705 127.44 51.975 ;
     RECT  2.16 52.245 127.44 52.515 ;
     RECT  2.16 52.785 127.44 53.055 ;
     RECT  2.16 53.325 127.44 53.595 ;
     RECT  2.16 53.865 127.44 54.135 ;
     RECT  2.16 54.405 127.44 54.675 ;
     RECT  2.16 54.945 127.44 55.215 ;
     RECT  2.16 55.485 127.44 55.755 ;
     RECT  2.16 56.025 127.44 56.295 ;
     RECT  2.16 56.565 127.44 56.835 ;
     RECT  2.16 57.105 127.44 57.375 ;
     RECT  2.16 57.645 127.44 57.915 ;
     RECT  2.16 58.185 127.44 58.455 ;
     RECT  2.16 58.725 127.44 58.995 ;
     RECT  2.16 59.265 127.44 59.535 ;
     RECT  2.16 59.805 127.44 60.075 ;
     RECT  2.16 60.345 127.44 60.615 ;
     RECT  2.16 60.885 127.44 61.155 ;
     RECT  2.16 61.425 127.44 61.695 ;
     RECT  2.16 61.965 127.44 62.235 ;
     RECT  2.16 62.505 127.44 62.775 ;
     RECT  2.16 63.045 127.44 63.315 ;
     RECT  2.16 63.585 127.44 63.855 ;
     RECT  2.16 64.125 127.44 64.395 ;
     RECT  2.16 64.665 127.44 64.935 ;
     RECT  2.16 65.205 127.44 65.475 ;
     RECT  2.16 65.745 127.44 66.015 ;
     RECT  2.16 66.285 127.44 66.555 ;
     RECT  2.16 66.825 127.44 67.095 ;
     RECT  2.16 67.365 127.44 67.635 ;
     RECT  2.16 67.905 127.44 68.175 ;
     RECT  2.16 68.445 127.44 68.715 ;
     RECT  2.16 68.985 127.44 69.255 ;
     RECT  2.16 69.525 127.44 69.795 ;
     RECT  2.16 70.065 127.44 70.335 ;
     RECT  2.16 70.605 127.44 70.875 ;
     RECT  2.16 71.145 127.44 71.415 ;
     RECT  2.16 71.685 127.44 71.955 ;
     RECT  2.16 72.225 127.44 72.495 ;
     RECT  2.16 72.765 127.44 73.035 ;
     RECT  2.16 73.305 127.44 73.575 ;
     RECT  2.16 73.845 127.44 74.115 ;
     RECT  2.16 74.385 127.44 74.655 ;
     RECT  2.16 74.925 127.44 75.195 ;
     RECT  2.16 75.465 127.44 75.735 ;
     RECT  2.16 76.005 127.44 76.275 ;
     RECT  2.16 76.545 127.44 76.815 ;
     RECT  2.16 77.085 127.44 77.355 ;
     RECT  2.16 77.625 127.44 77.895 ;
     RECT  2.16 78.165 127.44 78.435 ;
     RECT  2.16 78.705 127.44 78.975 ;
     RECT  2.16 79.245 127.44 79.515 ;
     RECT  2.16 79.785 127.44 80.055 ;
     RECT  2.16 80.325 127.44 80.595 ;
     RECT  2.16 80.865 127.44 81.135 ;
     RECT  2.16 81.405 127.44 81.675 ;
     RECT  2.16 81.945 127.44 82.215 ;
     RECT  2.16 82.485 127.44 82.755 ;
     RECT  2.16 83.025 127.44 83.295 ;
     RECT  2.16 83.565 127.44 83.835 ;
     RECT  2.16 84.105 127.44 84.375 ;
     RECT  2.16 84.645 127.44 84.915 ;
     RECT  2.16 85.185 127.44 85.455 ;
     RECT  2.16 85.725 127.44 85.995 ;
     RECT  2.16 86.265 127.44 86.535 ;
     RECT  2.16 86.805 127.44 87.075 ;
     RECT  2.16 87.345 127.44 87.615 ;
     RECT  2.16 87.885 127.44 88.155 ;
     RECT  2.16 88.425 127.44 88.695 ;
     RECT  2.16 88.965 127.44 89.235 ;
     RECT  2.16 89.505 127.44 89.775 ;
     RECT  2.16 90.045 127.44 90.315 ;
     RECT  2.16 90.585 127.44 90.855 ;
     RECT  2.16 91.125 127.44 91.395 ;
     RECT  2.16 91.665 127.44 91.935 ;
     RECT  2.16 92.205 127.44 92.475 ;
     RECT  2.16 92.745 127.44 93.015 ;
     RECT  2.16 93.285 127.44 93.555 ;
     RECT  2.16 93.825 127.44 94.095 ;
     RECT  2.16 94.365 127.44 94.635 ;
     RECT  2.16 94.905 127.44 95.175 ;
     RECT  2.16 95.445 127.44 95.715 ;
     RECT  2.16 95.985 127.44 96.255 ;
     RECT  2.16 96.525 127.44 96.795 ;
     RECT  2.16 97.065 127.44 97.335 ;
     RECT  2.16 97.605 127.44 97.875 ;
     RECT  2.16 98.145 127.44 98.415 ;
     RECT  2.16 98.685 127.44 98.955 ;
     RECT  2.16 99.225 127.44 99.495 ;
     RECT  2.16 99.765 127.44 100.035 ;
     RECT  2.16 100.305 127.44 100.575 ;
     RECT  2.16 100.845 127.44 101.115 ;
     RECT  2.16 101.385 127.44 101.655 ;
     RECT  2.16 101.925 127.44 102.195 ;
     RECT  2.16 102.465 127.44 102.735 ;
     RECT  2.16 103.005 127.44 103.275 ;
     RECT  2.16 103.545 127.44 103.815 ;
     RECT  2.16 104.085 127.44 104.355 ;
     RECT  2.16 104.625 127.44 104.895 ;
     RECT  2.16 105.165 127.44 105.435 ;
     RECT  2.16 105.705 127.44 105.975 ;
     RECT  2.16 106.245 127.44 106.515 ;
     RECT  2.16 106.785 127.44 107.055 ;
     RECT  2.16 107.325 127.44 107.595 ;
     RECT  2.16 107.865 127.44 108.135 ;
     RECT  2.16 108.405 127.44 108.675 ;
     RECT  2.16 108.945 127.44 109.215 ;
     RECT  2.16 109.485 127.44 109.755 ;
     RECT  2.16 110.025 127.44 110.295 ;
     RECT  2.16 110.565 127.44 110.835 ;
     RECT  2.16 111.105 127.44 111.375 ;
     RECT  2.16 111.645 127.44 111.915 ;
     RECT  2.16 112.185 127.44 112.455 ;
     RECT  2.16 112.725 127.44 112.995 ;
     RECT  2.16 113.265 127.44 113.535 ;
     RECT  2.16 113.805 127.44 114.075 ;
     RECT  2.16 114.345 127.44 114.615 ;
     RECT  2.16 114.885 127.44 115.155 ;
     RECT  2.16 115.425 127.44 115.695 ;
     RECT  2.16 115.965 127.44 116.235 ;
     RECT  2.16 116.505 127.44 116.775 ;
     RECT  2.16 117.045 127.44 117.315 ;
     RECT  2.16 117.585 127.44 117.855 ;
     RECT  2.16 118.125 127.44 118.395 ;
     RECT  2.16 118.665 127.44 118.935 ;
     RECT  2.16 119.205 127.44 119.475 ;
     RECT  2.16 119.745 127.44 120.015 ;
     RECT  2.16 120.285 127.44 120.555 ;
     RECT  2.16 120.825 127.44 121.095 ;
     RECT  2.16 121.365 127.44 121.635 ;
     RECT  2.16 121.905 127.44 122.175 ;
     RECT  2.16 122.445 127.44 122.715 ;
     RECT  2.16 122.985 127.44 123.255 ;
     RECT  2.16 123.525 127.44 123.795 ;
     RECT  2.16 124.065 127.44 124.335 ;
     RECT  2.16 124.605 127.44 124.875 ;
     RECT  2.16 125.145 127.44 125.415 ;
     RECT  2.16 125.685 127.44 125.955 ;
     RECT  2.16 126.225 127.44 126.495 ;
     RECT  2.16 126.765 127.44 127.035 ;
     RECT  2.16 127.305 127.44 127.575 ;
     RECT  2.16 127.845 127.44 128.115 ;
     RECT  2.16 128.385 127.44 128.655 ;
     RECT  2.16 128.925 127.44 129.195 ;
     RECT  2.16 129.465 127.44 129.735 ;
     RECT  2.16 130.005 127.44 130.275 ;
     RECT  2.16 130.545 127.44 130.815 ;
     RECT  2.16 131.085 127.44 131.355 ;
     RECT  2.16 131.625 127.44 131.895 ;
     RECT  2.16 132.165 127.44 132.435 ;
     RECT  2.16 132.705 127.44 132.975 ;
     RECT  2.16 133.245 127.44 133.515 ;
     RECT  2.16 133.785 127.44 134.055 ;
     RECT  2.16 134.325 127.44 134.595 ;
     RECT  2.16 134.865 127.44 135.135 ;
     RECT  2.16 135.405 127.44 135.675 ;
     RECT  2.16 135.945 127.44 136.215 ;
     RECT  2.16 136.485 127.44 136.755 ;
     RECT  2.16 137.025 127.44 137.295 ;
     RECT  2.16 137.565 127.44 137.835 ;
     RECT  2.16 138.105 127.44 138.375 ;
     RECT  2.16 138.645 127.44 138.915 ;
     RECT  2.16 139.185 127.44 139.455 ;
     RECT  2.16 139.725 127.44 139.995 ;
     RECT  2.16 140.265 127.44 140.535 ;
     RECT  2.16 140.805 127.44 141.075 ;
     RECT  2.16 141.345 127.44 141.615 ;
     RECT  2.16 141.885 127.44 142.155 ;
     RECT  2.16 142.425 127.44 142.695 ;
     RECT  2.16 142.965 127.44 143.235 ;
     RECT  2.16 143.505 127.44 143.775 ;
     RECT  2.16 144.045 127.44 144.315 ;
     RECT  2.16 144.585 127.44 144.855 ;
     RECT  2.16 145.125 127.44 145.395 ;
     RECT  2.16 145.665 127.44 145.935 ;
     RECT  2.16 146.205 127.44 146.475 ;
     RECT  2.16 146.745 127.44 147.015 ;
     RECT  2.16 147.285 127.44 147.555 ;
     RECT  2.16 147.825 127.44 148.095 ;
     RECT  2.16 148.365 127.44 148.635 ;
     RECT  2.16 148.905 127.44 149.175 ;
     RECT  2.16 149.445 127.44 149.715 ;
     RECT  2.16 149.985 127.44 150.255 ;
     RECT  2.16 150.525 127.44 150.795 ;
     RECT  2.16 151.065 127.44 151.335 ;
     RECT  2.16 151.605 127.44 151.875 ;
     RECT  2.16 152.145 127.44 152.415 ;
     RECT  2.16 152.685 127.44 152.955 ;
     RECT  2.16 153.225 127.44 153.495 ;
     RECT  2.16 153.765 127.44 154.035 ;
     RECT  2.16 154.305 127.44 154.575 ;
     RECT  2.16 154.845 127.44 155.115 ;
     RECT  2.16 155.385 127.44 155.655 ;
     RECT  2.16 155.925 127.44 156.195 ;
     RECT  2.16 156.465 127.44 156.735 ;
     RECT  2.16 157.005 127.44 157.275 ;
     RECT  2.16 157.545 127.44 157.815 ;
     RECT  2.16 158.085 127.44 158.355 ;
     RECT  2.16 158.625 127.44 158.895 ;
     RECT  2.16 159.165 127.44 159.435 ;
     RECT  2.16 159.705 127.44 159.975 ;
     RECT  2.16 160.245 127.44 160.515 ;
     RECT  2.16 160.785 127.44 161.055 ;
     RECT  2.16 161.325 127.44 161.595 ;
     RECT  2.16 161.865 127.44 162.135 ;
     RECT  2.16 162.405 127.44 162.675 ;
     RECT  2.16 162.945 127.44 163.215 ;
     RECT  2.16 163.485 127.44 163.755 ;
     RECT  2.16 164.025 127.44 164.295 ;
     RECT  2.16 164.565 127.44 164.835 ;
     RECT  2.16 165.105 127.44 165.375 ;
     RECT  2.16 165.645 127.44 165.915 ;
     RECT  2.16 166.185 127.44 166.455 ;
     RECT  2.16 166.725 127.44 166.995 ;
     RECT  2.16 167.265 127.44 167.535 ;
     RECT  2.16 167.805 127.44 168.075 ;
     RECT  2.16 168.345 127.44 168.615 ;
     RECT  2.16 168.885 127.44 169.155 ;
     RECT  2.16 169.425 127.44 169.695 ;
     RECT  2.16 169.965 127.44 170.235 ;
     RECT  2.16 170.505 127.44 170.775 ;
     RECT  2.16 171.045 127.44 171.315 ;
     RECT  2.16 171.585 127.44 171.855 ;
     RECT  2.16 172.125 127.44 172.395 ;
     RECT  2.16 172.665 127.44 172.935 ;
     RECT  2.16 173.205 127.44 173.475 ;
     RECT  2.16 173.745 127.44 174.015 ;
     RECT  2.16 174.285 127.44 174.555 ;
     RECT  2.16 174.825 127.44 175.095 ;
     RECT  2.16 175.365 127.44 175.635 ;
     RECT  2.16 175.905 127.44 176.175 ;
     RECT  2.16 176.445 127.44 176.715 ;
     RECT  2.16 176.985 127.44 177.255 ;
     RECT  2.16 177.525 127.44 177.795 ;
     RECT  2.16 178.065 127.44 178.335 ;
     RECT  2.16 178.605 127.44 178.875 ;
     RECT  2.16 179.145 127.44 179.415 ;
     RECT  2.16 179.685 127.44 179.955 ;
     RECT  2.16 180.225 127.44 180.495 ;
     RECT  2.16 180.765 127.44 181.035 ;
     RECT  2.16 181.305 127.44 181.44 ;
    LAYER RVTP ;
     RECT  2.16 2.295 127.44 2.565 ;
     RECT  2.16 2.835 127.44 3.105 ;
     RECT  2.16 3.375 127.44 3.645 ;
     RECT  2.16 3.915 127.44 4.185 ;
     RECT  2.16 4.455 127.44 4.725 ;
     RECT  2.16 4.995 127.44 5.265 ;
     RECT  2.16 5.535 127.44 5.805 ;
     RECT  2.16 6.075 127.44 6.345 ;
     RECT  2.16 6.615 127.44 6.885 ;
     RECT  2.16 7.155 127.44 7.425 ;
     RECT  2.16 7.695 127.44 7.965 ;
     RECT  2.16 8.235 127.44 8.505 ;
     RECT  2.16 8.775 127.44 9.045 ;
     RECT  2.16 9.315 127.44 9.585 ;
     RECT  2.16 9.855 127.44 10.125 ;
     RECT  2.16 10.395 127.44 10.665 ;
     RECT  2.16 10.935 127.44 11.205 ;
     RECT  2.16 11.475 127.44 11.745 ;
     RECT  2.16 12.015 127.44 12.285 ;
     RECT  2.16 12.555 127.44 12.825 ;
     RECT  2.16 13.095 127.44 13.365 ;
     RECT  2.16 13.635 127.44 13.905 ;
     RECT  2.16 14.175 127.44 14.445 ;
     RECT  2.16 14.715 127.44 14.985 ;
     RECT  2.16 15.255 127.44 15.525 ;
     RECT  2.16 15.795 127.44 16.065 ;
     RECT  2.16 16.335 127.44 16.605 ;
     RECT  2.16 16.875 127.44 17.145 ;
     RECT  2.16 17.415 127.44 17.685 ;
     RECT  2.16 17.955 127.44 18.225 ;
     RECT  2.16 18.495 127.44 18.765 ;
     RECT  2.16 19.035 127.44 19.305 ;
     RECT  2.16 19.575 127.44 19.845 ;
     RECT  2.16 20.115 127.44 20.385 ;
     RECT  2.16 20.655 127.44 20.925 ;
     RECT  2.16 21.195 127.44 21.465 ;
     RECT  2.16 21.735 127.44 22.005 ;
     RECT  2.16 22.275 127.44 22.545 ;
     RECT  2.16 22.815 127.44 23.085 ;
     RECT  2.16 23.355 127.44 23.625 ;
     RECT  2.16 23.895 127.44 24.165 ;
     RECT  2.16 24.435 127.44 24.705 ;
     RECT  2.16 24.975 127.44 25.245 ;
     RECT  2.16 25.515 127.44 25.785 ;
     RECT  2.16 26.055 127.44 26.325 ;
     RECT  2.16 26.595 127.44 26.865 ;
     RECT  2.16 27.135 127.44 27.405 ;
     RECT  2.16 27.675 127.44 27.945 ;
     RECT  2.16 28.215 127.44 28.485 ;
     RECT  2.16 28.755 127.44 29.025 ;
     RECT  2.16 29.295 127.44 29.565 ;
     RECT  2.16 29.835 127.44 30.105 ;
     RECT  2.16 30.375 127.44 30.645 ;
     RECT  2.16 30.915 127.44 31.185 ;
     RECT  2.16 31.455 127.44 31.725 ;
     RECT  2.16 31.995 127.44 32.265 ;
     RECT  2.16 32.535 127.44 32.805 ;
     RECT  2.16 33.075 127.44 33.345 ;
     RECT  2.16 33.615 127.44 33.885 ;
     RECT  2.16 34.155 127.44 34.425 ;
     RECT  2.16 34.695 127.44 34.965 ;
     RECT  2.16 35.235 127.44 35.505 ;
     RECT  2.16 35.775 127.44 36.045 ;
     RECT  2.16 36.315 127.44 36.585 ;
     RECT  2.16 36.855 127.44 37.125 ;
     RECT  2.16 37.395 127.44 37.665 ;
     RECT  2.16 37.935 127.44 38.205 ;
     RECT  2.16 38.475 127.44 38.745 ;
     RECT  2.16 39.015 127.44 39.285 ;
     RECT  2.16 39.555 127.44 39.825 ;
     RECT  2.16 40.095 127.44 40.365 ;
     RECT  2.16 40.635 127.44 40.905 ;
     RECT  2.16 41.175 127.44 41.445 ;
     RECT  2.16 41.715 127.44 41.985 ;
     RECT  2.16 42.255 127.44 42.525 ;
     RECT  2.16 42.795 127.44 43.065 ;
     RECT  2.16 43.335 127.44 43.605 ;
     RECT  2.16 43.875 127.44 44.145 ;
     RECT  2.16 44.415 127.44 44.685 ;
     RECT  2.16 44.955 127.44 45.225 ;
     RECT  2.16 45.495 127.44 45.765 ;
     RECT  2.16 46.035 127.44 46.305 ;
     RECT  2.16 46.575 127.44 46.845 ;
     RECT  2.16 47.115 127.44 47.385 ;
     RECT  2.16 47.655 127.44 47.925 ;
     RECT  2.16 48.195 127.44 48.465 ;
     RECT  2.16 48.735 127.44 49.005 ;
     RECT  2.16 49.275 127.44 49.545 ;
     RECT  2.16 49.815 127.44 50.085 ;
     RECT  2.16 50.355 127.44 50.625 ;
     RECT  2.16 50.895 127.44 51.165 ;
     RECT  2.16 51.435 127.44 51.705 ;
     RECT  2.16 51.975 127.44 52.245 ;
     RECT  2.16 52.515 127.44 52.785 ;
     RECT  2.16 53.055 127.44 53.325 ;
     RECT  2.16 53.595 127.44 53.865 ;
     RECT  2.16 54.135 127.44 54.405 ;
     RECT  2.16 54.675 127.44 54.945 ;
     RECT  2.16 55.215 127.44 55.485 ;
     RECT  2.16 55.755 127.44 56.025 ;
     RECT  2.16 56.295 127.44 56.565 ;
     RECT  2.16 56.835 127.44 57.105 ;
     RECT  2.16 57.375 127.44 57.645 ;
     RECT  2.16 57.915 127.44 58.185 ;
     RECT  2.16 58.455 127.44 58.725 ;
     RECT  2.16 58.995 127.44 59.265 ;
     RECT  2.16 59.535 127.44 59.805 ;
     RECT  2.16 60.075 127.44 60.345 ;
     RECT  2.16 60.615 127.44 60.885 ;
     RECT  2.16 61.155 127.44 61.425 ;
     RECT  2.16 61.695 127.44 61.965 ;
     RECT  2.16 62.235 127.44 62.505 ;
     RECT  2.16 62.775 127.44 63.045 ;
     RECT  2.16 63.315 127.44 63.585 ;
     RECT  2.16 63.855 127.44 64.125 ;
     RECT  2.16 64.395 127.44 64.665 ;
     RECT  2.16 64.935 127.44 65.205 ;
     RECT  2.16 65.475 127.44 65.745 ;
     RECT  2.16 66.015 127.44 66.285 ;
     RECT  2.16 66.555 127.44 66.825 ;
     RECT  2.16 67.095 127.44 67.365 ;
     RECT  2.16 67.635 127.44 67.905 ;
     RECT  2.16 68.175 127.44 68.445 ;
     RECT  2.16 68.715 127.44 68.985 ;
     RECT  2.16 69.255 127.44 69.525 ;
     RECT  2.16 69.795 127.44 70.065 ;
     RECT  2.16 70.335 127.44 70.605 ;
     RECT  2.16 70.875 127.44 71.145 ;
     RECT  2.16 71.415 127.44 71.685 ;
     RECT  2.16 71.955 127.44 72.225 ;
     RECT  2.16 72.495 127.44 72.765 ;
     RECT  2.16 73.035 127.44 73.305 ;
     RECT  2.16 73.575 127.44 73.845 ;
     RECT  2.16 74.115 127.44 74.385 ;
     RECT  2.16 74.655 127.44 74.925 ;
     RECT  2.16 75.195 127.44 75.465 ;
     RECT  2.16 75.735 127.44 76.005 ;
     RECT  2.16 76.275 127.44 76.545 ;
     RECT  2.16 76.815 127.44 77.085 ;
     RECT  2.16 77.355 127.44 77.625 ;
     RECT  2.16 77.895 127.44 78.165 ;
     RECT  2.16 78.435 127.44 78.705 ;
     RECT  2.16 78.975 127.44 79.245 ;
     RECT  2.16 79.515 127.44 79.785 ;
     RECT  2.16 80.055 127.44 80.325 ;
     RECT  2.16 80.595 127.44 80.865 ;
     RECT  2.16 81.135 127.44 81.405 ;
     RECT  2.16 81.675 127.44 81.945 ;
     RECT  2.16 82.215 127.44 82.485 ;
     RECT  2.16 82.755 127.44 83.025 ;
     RECT  2.16 83.295 127.44 83.565 ;
     RECT  2.16 83.835 127.44 84.105 ;
     RECT  2.16 84.375 127.44 84.645 ;
     RECT  2.16 84.915 127.44 85.185 ;
     RECT  2.16 85.455 127.44 85.725 ;
     RECT  2.16 85.995 127.44 86.265 ;
     RECT  2.16 86.535 127.44 86.805 ;
     RECT  2.16 87.075 127.44 87.345 ;
     RECT  2.16 87.615 127.44 87.885 ;
     RECT  2.16 88.155 127.44 88.425 ;
     RECT  2.16 88.695 127.44 88.965 ;
     RECT  2.16 89.235 127.44 89.505 ;
     RECT  2.16 89.775 127.44 90.045 ;
     RECT  2.16 90.315 127.44 90.585 ;
     RECT  2.16 90.855 127.44 91.125 ;
     RECT  2.16 91.395 127.44 91.665 ;
     RECT  2.16 91.935 127.44 92.205 ;
     RECT  2.16 92.475 127.44 92.745 ;
     RECT  2.16 93.015 127.44 93.285 ;
     RECT  2.16 93.555 127.44 93.825 ;
     RECT  2.16 94.095 127.44 94.365 ;
     RECT  2.16 94.635 127.44 94.905 ;
     RECT  2.16 95.175 127.44 95.445 ;
     RECT  2.16 95.715 127.44 95.985 ;
     RECT  2.16 96.255 127.44 96.525 ;
     RECT  2.16 96.795 127.44 97.065 ;
     RECT  2.16 97.335 127.44 97.605 ;
     RECT  2.16 97.875 127.44 98.145 ;
     RECT  2.16 98.415 127.44 98.685 ;
     RECT  2.16 98.955 127.44 99.225 ;
     RECT  2.16 99.495 127.44 99.765 ;
     RECT  2.16 100.035 127.44 100.305 ;
     RECT  2.16 100.575 127.44 100.845 ;
     RECT  2.16 101.115 127.44 101.385 ;
     RECT  2.16 101.655 127.44 101.925 ;
     RECT  2.16 102.195 127.44 102.465 ;
     RECT  2.16 102.735 127.44 103.005 ;
     RECT  2.16 103.275 127.44 103.545 ;
     RECT  2.16 103.815 127.44 104.085 ;
     RECT  2.16 104.355 127.44 104.625 ;
     RECT  2.16 104.895 127.44 105.165 ;
     RECT  2.16 105.435 127.44 105.705 ;
     RECT  2.16 105.975 127.44 106.245 ;
     RECT  2.16 106.515 127.44 106.785 ;
     RECT  2.16 107.055 127.44 107.325 ;
     RECT  2.16 107.595 127.44 107.865 ;
     RECT  2.16 108.135 127.44 108.405 ;
     RECT  2.16 108.675 127.44 108.945 ;
     RECT  2.16 109.215 127.44 109.485 ;
     RECT  2.16 109.755 127.44 110.025 ;
     RECT  2.16 110.295 127.44 110.565 ;
     RECT  2.16 110.835 127.44 111.105 ;
     RECT  2.16 111.375 127.44 111.645 ;
     RECT  2.16 111.915 127.44 112.185 ;
     RECT  2.16 112.455 127.44 112.725 ;
     RECT  2.16 112.995 127.44 113.265 ;
     RECT  2.16 113.535 127.44 113.805 ;
     RECT  2.16 114.075 127.44 114.345 ;
     RECT  2.16 114.615 127.44 114.885 ;
     RECT  2.16 115.155 127.44 115.425 ;
     RECT  2.16 115.695 127.44 115.965 ;
     RECT  2.16 116.235 127.44 116.505 ;
     RECT  2.16 116.775 127.44 117.045 ;
     RECT  2.16 117.315 127.44 117.585 ;
     RECT  2.16 117.855 127.44 118.125 ;
     RECT  2.16 118.395 127.44 118.665 ;
     RECT  2.16 118.935 127.44 119.205 ;
     RECT  2.16 119.475 127.44 119.745 ;
     RECT  2.16 120.015 127.44 120.285 ;
     RECT  2.16 120.555 127.44 120.825 ;
     RECT  2.16 121.095 127.44 121.365 ;
     RECT  2.16 121.635 127.44 121.905 ;
     RECT  2.16 122.175 127.44 122.445 ;
     RECT  2.16 122.715 127.44 122.985 ;
     RECT  2.16 123.255 127.44 123.525 ;
     RECT  2.16 123.795 127.44 124.065 ;
     RECT  2.16 124.335 127.44 124.605 ;
     RECT  2.16 124.875 127.44 125.145 ;
     RECT  2.16 125.415 127.44 125.685 ;
     RECT  2.16 125.955 127.44 126.225 ;
     RECT  2.16 126.495 127.44 126.765 ;
     RECT  2.16 127.035 127.44 127.305 ;
     RECT  2.16 127.575 127.44 127.845 ;
     RECT  2.16 128.115 127.44 128.385 ;
     RECT  2.16 128.655 127.44 128.925 ;
     RECT  2.16 129.195 127.44 129.465 ;
     RECT  2.16 129.735 127.44 130.005 ;
     RECT  2.16 130.275 127.44 130.545 ;
     RECT  2.16 130.815 127.44 131.085 ;
     RECT  2.16 131.355 127.44 131.625 ;
     RECT  2.16 131.895 127.44 132.165 ;
     RECT  2.16 132.435 127.44 132.705 ;
     RECT  2.16 132.975 127.44 133.245 ;
     RECT  2.16 133.515 127.44 133.785 ;
     RECT  2.16 134.055 127.44 134.325 ;
     RECT  2.16 134.595 127.44 134.865 ;
     RECT  2.16 135.135 127.44 135.405 ;
     RECT  2.16 135.675 127.44 135.945 ;
     RECT  2.16 136.215 127.44 136.485 ;
     RECT  2.16 136.755 127.44 137.025 ;
     RECT  2.16 137.295 127.44 137.565 ;
     RECT  2.16 137.835 127.44 138.105 ;
     RECT  2.16 138.375 127.44 138.645 ;
     RECT  2.16 138.915 127.44 139.185 ;
     RECT  2.16 139.455 127.44 139.725 ;
     RECT  2.16 139.995 127.44 140.265 ;
     RECT  2.16 140.535 127.44 140.805 ;
     RECT  2.16 141.075 127.44 141.345 ;
     RECT  2.16 141.615 127.44 141.885 ;
     RECT  2.16 142.155 127.44 142.425 ;
     RECT  2.16 142.695 127.44 142.965 ;
     RECT  2.16 143.235 127.44 143.505 ;
     RECT  2.16 143.775 127.44 144.045 ;
     RECT  2.16 144.315 127.44 144.585 ;
     RECT  2.16 144.855 127.44 145.125 ;
     RECT  2.16 145.395 127.44 145.665 ;
     RECT  2.16 145.935 127.44 146.205 ;
     RECT  2.16 146.475 127.44 146.745 ;
     RECT  2.16 147.015 127.44 147.285 ;
     RECT  2.16 147.555 127.44 147.825 ;
     RECT  2.16 148.095 127.44 148.365 ;
     RECT  2.16 148.635 127.44 148.905 ;
     RECT  2.16 149.175 127.44 149.445 ;
     RECT  2.16 149.715 127.44 149.985 ;
     RECT  2.16 150.255 127.44 150.525 ;
     RECT  2.16 150.795 127.44 151.065 ;
     RECT  2.16 151.335 127.44 151.605 ;
     RECT  2.16 151.875 127.44 152.145 ;
     RECT  2.16 152.415 127.44 152.685 ;
     RECT  2.16 152.955 127.44 153.225 ;
     RECT  2.16 153.495 127.44 153.765 ;
     RECT  2.16 154.035 127.44 154.305 ;
     RECT  2.16 154.575 127.44 154.845 ;
     RECT  2.16 155.115 127.44 155.385 ;
     RECT  2.16 155.655 127.44 155.925 ;
     RECT  2.16 156.195 127.44 156.465 ;
     RECT  2.16 156.735 127.44 157.005 ;
     RECT  2.16 157.275 127.44 157.545 ;
     RECT  2.16 157.815 127.44 158.085 ;
     RECT  2.16 158.355 127.44 158.625 ;
     RECT  2.16 158.895 127.44 159.165 ;
     RECT  2.16 159.435 127.44 159.705 ;
     RECT  2.16 159.975 127.44 160.245 ;
     RECT  2.16 160.515 127.44 160.785 ;
     RECT  2.16 161.055 127.44 161.325 ;
     RECT  2.16 161.595 127.44 161.865 ;
     RECT  2.16 162.135 127.44 162.405 ;
     RECT  2.16 162.675 127.44 162.945 ;
     RECT  2.16 163.215 127.44 163.485 ;
     RECT  2.16 163.755 127.44 164.025 ;
     RECT  2.16 164.295 127.44 164.565 ;
     RECT  2.16 164.835 127.44 165.105 ;
     RECT  2.16 165.375 127.44 165.645 ;
     RECT  2.16 165.915 127.44 166.185 ;
     RECT  2.16 166.455 127.44 166.725 ;
     RECT  2.16 166.995 127.44 167.265 ;
     RECT  2.16 167.535 127.44 167.805 ;
     RECT  2.16 168.075 127.44 168.345 ;
     RECT  2.16 168.615 127.44 168.885 ;
     RECT  2.16 169.155 127.44 169.425 ;
     RECT  2.16 169.695 127.44 169.965 ;
     RECT  2.16 170.235 127.44 170.505 ;
     RECT  2.16 170.775 127.44 171.045 ;
     RECT  2.16 171.315 127.44 171.585 ;
     RECT  2.16 171.855 127.44 172.125 ;
     RECT  2.16 172.395 127.44 172.665 ;
     RECT  2.16 172.935 127.44 173.205 ;
     RECT  2.16 173.475 127.44 173.745 ;
     RECT  2.16 174.015 127.44 174.285 ;
     RECT  2.16 174.555 127.44 174.825 ;
     RECT  2.16 175.095 127.44 175.365 ;
     RECT  2.16 175.635 127.44 175.905 ;
     RECT  2.16 176.175 127.44 176.445 ;
     RECT  2.16 176.715 127.44 176.985 ;
     RECT  2.16 177.255 127.44 177.525 ;
     RECT  2.16 177.795 127.44 178.065 ;
     RECT  2.16 178.335 127.44 178.605 ;
     RECT  2.16 178.875 127.44 179.145 ;
     RECT  2.16 179.415 127.44 179.685 ;
     RECT  2.16 179.955 127.44 180.225 ;
     RECT  2.16 180.495 127.44 180.765 ;
     RECT  2.16 181.035 127.44 181.305 ;
    LAYER M1 ;
     RECT  2.16 2.151 127.44 181.449 ;
    LAYER M2 ;
     RECT  1.723 2.106 2.16 2.124 ;
     RECT  1.399 4.356 2.16 4.374 ;
     RECT  1.507 5.706 2.16 5.724 ;
     RECT  1.723 7.056 2.16 7.074 ;
     RECT  1.147 11.556 2.16 11.574 ;
     RECT  1.111 181.116 2.16 181.134 ;
     RECT  2.16 2.106 2.399 181.449 ;
     RECT  2.399 2.151 3.703 181.449 ;
     RECT  3.703 2.106 4.595 181.449 ;
     RECT  4.595 2.151 6.691 181.449 ;
     RECT  6.691 2.106 7.223 181.449 ;
     RECT  7.223 2.151 12.991 181.449 ;
     RECT  12.991 2.106 13.199 181.449 ;
     RECT  13.199 2.151 31.855 181.449 ;
     RECT  31.855 2.106 32.099 181.449 ;
     RECT  32.099 2.151 33.583 181.449 ;
     RECT  33.583 2.106 34.979 181.449 ;
     RECT  34.979 2.151 37.975 181.449 ;
     RECT  37.975 2.106 38.399 181.449 ;
     RECT  38.399 2.151 39.775 181.449 ;
     RECT  39.775 2.106 40.199 181.449 ;
     RECT  40.199 2.151 41.539 181.449 ;
     RECT  41.539 2.106 41.855 181.449 ;
     RECT  63.895 1.152 64.067 1.17 ;
     RECT  41.855 2.151 64.867 181.449 ;
     RECT  64.867 2.106 65.399 181.449 ;
     RECT  65.399 2.151 66.595 181.449 ;
     RECT  66.595 2.106 67.091 181.449 ;
     RECT  67.091 2.151 68.323 181.449 ;
     RECT  68.323 2.106 70.583 181.449 ;
     RECT  70.583 2.151 91.183 181.449 ;
     RECT  91.183 2.106 92.507 181.449 ;
     RECT  95.395 1.152 95.603 1.17 ;
     RECT  92.507 2.151 116.239 181.449 ;
     RECT  116.239 2.106 116.555 181.449 ;
     RECT  116.555 2.151 123.619 181.449 ;
     RECT  123.619 2.106 125.311 181.449 ;
     RECT  125.311 1.962 126.815 181.449 ;
     RECT  126.815 2.034 127.247 181.449 ;
     RECT  127.247 2.106 127.44 181.449 ;
     RECT  127.44 2.106 127.679 2.754 ;
     RECT  127.679 2.736 127.715 2.754 ;
     RECT  127.44 139.194 127.715 139.212 ;
     RECT  127.44 4.626 128.183 4.644 ;
     RECT  127.44 180.81 128.507 181.26 ;
     RECT  127.44 141.858 128.543 141.876 ;
     RECT  128.507 181.116 128.903 181.26 ;
     RECT  128.903 181.116 129.335 181.134 ;
    LAYER M3 ;
     RECT  94.824 0.091 94.842 0.139 ;
     RECT  114.84 0.091 114.858 0.139 ;
     RECT  115.596 0.091 115.758 0.139 ;
     RECT  87.192 0.139 87.21 0.187 ;
     RECT  84.816 0.139 84.834 0.235 ;
     RECT  124.236 0.091 124.254 0.235 ;
     RECT  125.1 0.091 125.118 0.235 ;
     RECT  2.556 0.139 2.574 0.523 ;
     RECT  39.204 0.091 39.222 0.523 ;
     RECT  58.356 0.091 58.374 0.523 ;
     RECT  64.8 0.139 64.818 0.523 ;
     RECT  113.04 0.091 113.346 0.523 ;
     RECT  120.024 0.091 120.042 0.523 ;
     RECT  2.34 0.523 2.574 0.571 ;
     RECT  6.192 0.091 6.21 0.571 ;
     RECT  7.704 0.091 7.722 0.571 ;
     RECT  8.46 0.091 8.478 0.571 ;
     RECT  12.78 0.091 12.798 0.571 ;
     RECT  28.62 0.091 29.574 0.571 ;
     RECT  30.852 0.091 31.23 0.571 ;
     RECT  32.58 0.091 32.994 0.571 ;
     RECT  35.208 0.091 35.766 0.571 ;
     RECT  38.916 0.523 39.222 0.571 ;
     RECT  40.068 0.523 40.086 0.571 ;
     RECT  41.076 0.475 41.094 0.571 ;
     RECT  56.628 0.091 57.186 0.571 ;
     RECT  59.184 0.091 59.202 0.571 ;
     RECT  60.048 0.091 60.066 0.571 ;
     RECT  60.84 0.091 60.858 0.571 ;
     RECT  64.8 0.523 65.25 0.571 ;
     RECT  65.988 0.139 68.166 0.571 ;
     RECT  84.6 0.235 84.834 0.571 ;
     RECT  85.788 0.139 85.806 0.571 ;
     RECT  87.192 0.187 87.606 0.571 ;
     RECT  89.208 0.139 89.226 0.571 ;
     RECT  90.504 0.091 90.522 0.571 ;
     RECT  94.644 0.139 94.842 0.571 ;
     RECT  95.724 0.091 95.742 0.571 ;
     RECT  96.588 0.091 96.606 0.571 ;
     RECT  111.312 0.523 113.346 0.571 ;
     RECT  114.84 0.139 115.758 0.571 ;
     RECT  117.324 0.091 118.206 0.571 ;
     RECT  119.844 0.523 120.042 0.571 ;
     RECT  121.716 0.091 122.382 0.571 ;
     RECT  78.336 0.571 78.354 0.619 ;
     RECT  97.884 0.091 98.514 0.619 ;
     RECT  127.188 0.235 127.206 0.619 ;
     RECT  128.16 0.235 128.178 0.619 ;
     RECT  62.316 0.571 62.334 0.667 ;
     RECT  63.18 0.571 63.198 0.667 ;
     RECT  86.544 0.571 89.226 0.667 ;
     RECT  90 0.571 90.882 0.667 ;
     RECT  62.316 0.667 63.198 1.051 ;
     RECT  61.668 1.051 63.198 1.099 ;
     RECT  3.924 0.571 4.122 1.147 ;
     RECT  10.98 0.571 10.998 1.147 ;
     RECT  12.78 0.571 12.834 1.147 ;
     RECT  14.472 0.619 14.49 1.147 ;
     RECT  19.764 0.619 20.214 1.147 ;
     RECT  22.032 0.619 22.05 1.147 ;
     RECT  28.332 0.571 31.698 1.147 ;
     RECT  32.58 0.571 33.39 1.147 ;
     RECT  34.236 0.091 34.254 1.147 ;
     RECT  35.136 0.571 35.766 1.147 ;
     RECT  37.296 0.091 37.71 1.147 ;
     RECT  40.932 0.571 41.382 1.147 ;
     RECT  55.44 0.091 55.458 1.147 ;
     RECT  56.304 0.571 57.186 1.147 ;
     RECT  61.668 1.099 63.918 1.147 ;
     RECT  64.8 0.571 68.166 1.147 ;
     RECT  68.94 0.571 68.958 1.147 ;
     RECT  69.876 0.091 69.894 1.147 ;
     RECT  74.736 0.091 74.754 1.147 ;
     RECT  76.824 0.619 76.842 1.147 ;
     RECT  83.556 0.523 83.574 1.147 ;
     RECT  84.6 0.571 85.806 1.147 ;
     RECT  86.544 0.667 90.882 1.147 ;
     RECT  92.16 0.571 92.682 1.147 ;
     RECT  93.636 0.523 93.654 1.147 ;
     RECT  94.536 0.571 96.606 1.147 ;
     RECT  108.324 0.331 108.342 1.147 ;
     RECT  111.06 0.571 118.206 1.147 ;
     RECT  119.448 0.571 120.042 1.147 ;
     RECT  121.104 0.571 123.462 1.147 ;
     RECT  124.236 0.235 125.118 1.147 ;
     RECT  125.856 0.571 125.874 1.147 ;
     RECT  127.188 0.619 128.178 1.147 ;
     RECT  93.42 1.147 96.606 1.175 ;
     RECT  1.728 0.571 2.574 1.195 ;
     RECT  12.528 1.147 14.922 1.195 ;
     RECT  16.848 1.147 16.866 1.195 ;
     RECT  17.676 1.147 17.694 1.195 ;
     RECT  25.092 1.147 25.11 1.195 ;
     RECT  26.82 1.147 26.838 1.195 ;
     RECT  42.66 0.619 42.678 1.195 ;
     RECT  46.26 1.147 46.278 1.195 ;
     RECT  47.304 1.147 47.322 1.195 ;
     RECT  48.06 1.147 48.078 1.195 ;
     RECT  49.824 1.147 49.842 1.195 ;
     RECT  51.624 1.147 51.642 1.195 ;
     RECT  52.416 0.619 52.434 1.195 ;
     RECT  53.172 1.147 53.19 1.195 ;
     RECT  56.304 1.147 57.51 1.195 ;
     RECT  64.8 1.147 70.11 1.195 ;
     RECT  71.28 1.147 71.298 1.195 ;
     RECT  73.044 1.147 73.062 1.195 ;
     RECT  79.236 1.147 79.254 1.195 ;
     RECT  81.756 1.147 81.774 1.195 ;
     RECT  101.016 1.147 101.034 1.195 ;
     RECT  109.548 1.147 109.566 1.195 ;
     RECT  110.556 1.147 120.042 1.195 ;
     RECT  16.416 1.195 16.866 1.243 ;
     RECT  80.244 1.147 80.262 1.243 ;
     RECT  4.896 0.091 5.418 1.675 ;
     RECT  9.648 1.147 9.666 1.723 ;
     RECT  109.548 1.195 120.042 1.723 ;
     RECT  121.104 1.147 125.118 1.723 ;
     RECT  12.528 1.195 15.354 1.771 ;
     RECT  16.344 1.243 16.866 1.771 ;
     RECT  17.676 1.195 18.09 1.771 ;
     RECT  19.44 1.147 20.214 1.771 ;
     RECT  20.988 0.619 21.006 1.771 ;
     RECT  22.032 1.147 22.374 1.771 ;
     RECT  25.092 1.195 25.506 1.771 ;
     RECT  26.82 1.195 27.162 1.771 ;
     RECT  27.9 1.147 36.486 1.771 ;
     RECT  44.604 1.147 44.622 1.771 ;
     RECT  46.26 1.195 47.322 1.771 ;
     RECT  48.06 1.195 48.222 1.771 ;
     RECT  49.824 1.195 50.238 1.771 ;
     RECT  51.156 1.195 51.642 1.771 ;
     RECT  54.216 1.147 55.458 1.771 ;
     RECT  56.196 1.195 57.51 1.771 ;
     RECT  64.8 1.195 71.766 1.771 ;
     RECT  73.044 1.195 73.458 1.771 ;
     RECT  74.664 1.147 74.754 1.771 ;
     RECT  76.5 1.147 76.842 1.771 ;
     RECT  77.904 0.619 78.354 1.771 ;
     RECT  79.236 1.195 79.506 1.771 ;
     RECT  80.244 1.243 80.298 1.771 ;
     RECT  81.252 1.195 81.774 1.771 ;
     RECT  97.884 0.619 98.91 1.771 ;
     RECT  100.62 1.195 101.034 1.771 ;
     RECT  102.384 1.195 102.402 1.771 ;
     RECT  107.892 1.147 108.342 1.771 ;
     RECT  109.548 1.723 125.118 1.771 ;
     RECT  125.856 1.147 128.178 1.771 ;
     RECT  73.044 1.771 73.926 1.819 ;
     RECT  74.664 1.771 75.762 1.819 ;
     RECT  3.672 1.147 4.122 2.101 ;
     RECT  4.86 1.675 5.418 2.101 ;
     RECT  6.192 0.571 6.642 2.101 ;
     RECT  7.704 0.571 8.91 2.101 ;
     RECT  37.296 1.147 37.998 2.101 ;
     RECT  38.916 0.571 40.086 2.101 ;
     RECT  40.932 1.147 41.562 2.101 ;
     RECT  84.492 1.147 91.206 2.101 ;
     RECT  92.052 1.147 92.682 2.101 ;
     RECT  1.728 1.195 2.826 2.129 ;
     RECT  23.472 1.147 23.49 2.143 ;
     RECT  24.228 1.771 24.246 2.143 ;
     RECT  37.296 2.101 40.194 2.143 ;
     RECT  40.932 2.101 41.85 2.143 ;
     RECT  44.604 1.771 45.414 2.143 ;
     RECT  46.26 1.771 48.87 2.143 ;
     RECT  64.8 1.771 72.054 2.143 ;
     RECT  73.044 1.819 75.762 2.143 ;
     RECT  97.884 1.771 99.162 2.143 ;
     RECT  100.224 1.771 102.87 2.143 ;
     RECT  103.608 1.771 104.598 2.143 ;
     RECT  3.672 2.101 5.418 2.191 ;
     RECT  17.676 1.771 20.214 2.191 ;
     RECT  20.988 1.771 22.374 2.191 ;
     RECT  54.216 1.771 57.51 2.218 ;
     RECT  95.58 1.175 96.606 2.219 ;
     RECT  3.6 2.191 5.418 2.227 ;
     RECT  6.192 2.101 8.91 2.227 ;
     RECT  10.8 1.147 11.394 2.227 ;
     RECT  23.472 2.143 24.246 2.227 ;
     RECT  26.82 1.771 36.486 2.227 ;
     RECT  37.296 2.143 41.85 2.227 ;
     RECT  49.824 1.771 51.642 2.227 ;
     RECT  54.216 2.218 57.546 2.227 ;
     RECT  58.32 0.523 58.374 2.227 ;
     RECT  80.244 1.771 81.99 2.227 ;
     RECT  82.764 1.147 83.574 2.227 ;
     RECT  97.884 2.143 102.87 2.227 ;
     RECT  103.608 2.143 105.105 2.227 ;
     RECT  2.304 2.129 2.826 2.263 ;
     RECT  3.6 2.227 8.91 2.263 ;
     RECT  12.528 1.771 16.866 2.263 ;
     RECT  17.676 2.191 22.374 2.263 ;
     RECT  37.224 2.227 41.85 2.263 ;
     RECT  42.66 1.195 43.758 2.263 ;
     RECT  54.216 2.227 58.374 2.263 ;
     RECT  97.884 2.227 105.105 2.263 ;
     RECT  9.648 1.723 10.026 2.299 ;
     RECT  10.8 2.227 11.466 2.299 ;
     RECT  54.072 2.263 58.374 2.299 ;
     RECT  59.184 0.571 60.858 2.299 ;
     RECT  64.8 2.143 75.762 2.335 ;
     RECT  76.5 1.771 78.354 2.335 ;
     RECT  97.668 2.263 105.105 2.335 ;
     RECT  105.984 1.771 107.082 2.335 ;
     RECT  109.548 1.771 128.178 2.335 ;
     RECT  25.092 1.771 25.974 2.347 ;
     RECT  26.712 2.227 36.486 2.347 ;
     RECT  52.416 1.195 53.19 2.347 ;
     RECT  54.072 2.299 60.858 2.347 ;
     RECT  37.224 2.263 43.758 2.371 ;
     RECT  44.604 2.143 48.87 2.371 ;
     RECT  23.364 2.227 24.246 2.413 ;
     RECT  80.244 2.227 83.574 2.413 ;
     RECT  97.344 2.335 105.105 2.413 ;
     RECT  105.876 2.335 107.082 2.413 ;
     RECT  37.224 2.371 48.87 2.569 ;
     RECT  49.752 2.227 51.642 2.569 ;
     RECT  61.668 1.147 64.062 2.569 ;
     RECT  64.8 2.335 78.354 2.569 ;
     RECT  23.364 2.413 24.297 2.605 ;
     RECT  25.092 2.347 36.486 2.605 ;
     RECT  37.224 2.569 51.642 2.605 ;
     RECT  52.416 2.347 60.858 2.605 ;
     RECT  80.244 2.413 83.697 2.605 ;
     RECT  84.492 2.101 92.682 2.605 ;
     RECT  9.648 2.299 11.466 2.641 ;
     RECT  12.384 2.263 22.374 2.641 ;
     RECT  23.364 2.605 24.354 2.641 ;
     RECT  25.092 2.605 60.858 2.641 ;
     RECT  61.668 2.569 78.354 2.641 ;
     RECT  79.2 1.771 79.506 2.641 ;
     RECT  80.244 2.605 92.682 2.641 ;
     RECT  93.42 1.175 94.842 2.641 ;
     RECT  95.58 2.219 96.534 2.641 ;
     RECT  97.344 2.413 107.082 2.641 ;
     RECT  107.892 1.771 108.558 2.641 ;
     RECT  109.512 2.335 128.178 2.641 ;
     RECT  97.308 2.641 107.082 2.731 ;
     RECT  107.892 2.641 128.178 2.731 ;
     RECT  97.308 2.731 128.178 2.759 ;
     RECT  2.304 2.263 8.91 2.867 ;
     RECT  2.34 2.867 8.91 2.875 ;
     RECT  9.648 2.641 79.506 2.875 ;
     RECT  97.308 2.759 127.314 3.029 ;
     RECT  2.34 2.875 79.506 3.101 ;
     RECT  80.244 2.641 96.534 3.145 ;
     RECT  97.308 3.029 127.278 3.145 ;
     RECT  2.376 3.101 79.506 3.271 ;
     RECT  80.244 3.145 127.278 3.271 ;
     RECT  1.404 2.299 1.422 4.379 ;
     RECT  2.376 3.271 127.278 4.495 ;
     RECT  128.16 2.759 128.178 4.649 ;
     RECT  2.34 4.495 127.278 5.035 ;
     RECT  2.304 5.035 127.278 5.341 ;
     RECT  1.512 4.555 1.53 5.707 ;
     RECT  2.304 5.341 127.314 5.707 ;
     RECT  1.512 5.707 127.314 5.729 ;
     RECT  1.728 5.729 127.314 7.079 ;
     RECT  2.304 7.079 127.314 9.005 ;
     RECT  2.304 9.005 127.098 11.273 ;
     RECT  37.44 11.273 127.098 11.435 ;
     RECT  1.152 10.267 1.17 11.579 ;
     RECT  2.304 11.273 36.594 11.579 ;
     RECT  74.34 11.435 127.098 11.939 ;
     RECT  80.424 11.939 127.098 12.209 ;
     RECT  80.424 12.209 127.062 12.551 ;
     RECT  80.424 12.551 126.954 12.749 ;
     RECT  19.728 11.579 36.594 13.559 ;
     RECT  37.44 11.435 73.566 13.675 ;
     RECT  74.34 11.939 79.614 13.675 ;
     RECT  80.424 12.749 126.897 13.829 ;
     RECT  117.432 13.829 126.897 13.865 ;
     RECT  2.304 11.579 18.99 14.099 ;
     RECT  37.44 13.675 79.614 14.243 ;
     RECT  48.384 14.243 79.614 14.449 ;
     RECT  80.424 13.829 111.258 14.449 ;
     RECT  48.384 14.449 111.258 14.791 ;
     RECT  111.996 13.829 116.658 14.791 ;
     RECT  2.415 14.099 18.99 14.909 ;
     RECT  48.384 14.791 116.658 14.909 ;
     RECT  117.468 13.865 126.897 14.917 ;
     RECT  74.376 14.909 116.658 14.981 ;
     RECT  80.424 14.981 116.658 15.025 ;
     RECT  117.432 14.917 126.897 15.025 ;
     RECT  80.424 15.025 126.897 15.521 ;
     RECT  37.44 14.243 47.574 15.871 ;
     RECT  37.44 15.871 47.61 16.105 ;
     RECT  48.384 14.909 73.566 16.105 ;
     RECT  19.728 13.559 36.558 16.645 ;
     RECT  37.44 16.105 73.566 16.645 ;
     RECT  80.424 15.521 116.766 16.681 ;
     RECT  2.415 14.909 15.498 16.747 ;
     RECT  16.272 14.909 18.99 16.747 ;
     RECT  19.728 16.645 73.566 16.747 ;
     RECT  2.415 16.747 73.566 16.799 ;
     RECT  74.376 14.981 79.398 16.807 ;
     RECT  74.376 16.807 79.47 16.951 ;
     RECT  80.388 16.681 116.766 16.951 ;
     RECT  117.504 15.521 126.897 16.951 ;
     RECT  19.728 16.799 73.566 17.035 ;
     RECT  74.376 16.951 79.578 17.035 ;
     RECT  2.415 16.799 18.99 17.069 ;
     RECT  19.728 17.035 79.578 17.069 ;
     RECT  80.388 16.951 126.897 17.069 ;
     RECT  19.728 17.069 79.47 17.105 ;
     RECT  74.376 17.105 79.47 17.141 ;
     RECT  111.96 17.069 126.897 17.177 ;
     RECT  111.996 17.177 116.694 17.249 ;
     RECT  19.728 17.105 73.566 17.681 ;
     RECT  74.376 17.141 79.398 18.571 ;
     RECT  74.376 18.571 79.506 18.797 ;
     RECT  80.388 17.069 111.15 18.833 ;
     RECT  19.728 17.681 60.426 18.841 ;
     RECT  61.164 17.681 73.566 18.841 ;
     RECT  19.728 18.841 73.566 18.959 ;
     RECT  2.415 17.069 15.606 19.381 ;
     RECT  16.452 17.069 18.99 19.381 ;
     RECT  2.415 19.381 18.99 19.499 ;
     RECT  19.728 18.959 60.426 19.571 ;
     RECT  74.376 18.797 79.434 19.768 ;
     RECT  80.424 18.833 111.15 19.768 ;
     RECT  74.376 19.768 111.15 19.805 ;
     RECT  80.208 19.805 111.15 19.885 ;
     RECT  111.996 17.249 116.658 19.885 ;
     RECT  80.208 19.885 116.658 19.949 ;
     RECT  111.996 19.949 116.658 20.155 ;
     RECT  117.504 17.177 126.897 20.155 ;
     RECT  19.728 19.571 53.694 20.309 ;
     RECT  111.996 20.155 126.897 20.309 ;
     RECT  61.164 18.959 73.566 20.425 ;
     RECT  74.376 19.805 79.434 20.425 ;
     RECT  54.72 19.571 60.426 20.461 ;
     RECT  61.164 20.425 79.434 20.461 ;
     RECT  54.72 20.461 79.434 20.477 ;
     RECT  54.72 20.477 73.566 20.525 ;
     RECT  74.376 20.477 79.434 20.551 ;
     RECT  80.208 19.949 111.15 20.551 ;
     RECT  111.996 20.309 116.658 20.687 ;
     RECT  61.164 20.525 73.566 20.723 ;
     RECT  48.348 20.309 53.694 20.893 ;
     RECT  54.72 20.525 60.426 20.893 ;
     RECT  74.376 20.551 111.15 21.119 ;
     RECT  84.96 21.119 85.77 21.389 ;
     RECT  74.376 21.119 84.186 21.461 ;
     RECT  19.728 20.309 47.574 21.505 ;
     RECT  48.348 20.893 60.426 21.505 ;
     RECT  19.728 21.505 60.426 22.037 ;
     RECT  2.415 19.499 15.606 22.081 ;
     RECT  16.452 19.499 18.99 22.081 ;
     RECT  2.415 22.081 18.99 22.199 ;
     RECT  86.508 21.119 111.15 22.315 ;
     RECT  111.996 20.687 116.586 22.315 ;
     RECT  86.508 22.315 116.586 22.411 ;
     RECT  117.468 20.309 126.897 22.411 ;
     RECT  86.508 22.411 126.897 22.469 ;
     RECT  16.452 22.199 18.99 22.477 ;
     RECT  19.728 22.037 31.086 22.477 ;
     RECT  65.52 20.723 73.566 22.549 ;
     RECT  74.376 21.461 84.114 22.549 ;
     RECT  86.508 22.469 103.266 22.585 ;
     RECT  31.932 22.037 60.426 22.739 ;
     RECT  104.004 22.469 116.586 22.775 ;
     RECT  65.52 22.549 84.114 22.981 ;
     RECT  84.96 21.389 85.698 22.981 ;
     RECT  16.452 22.477 31.086 23.153 ;
     RECT  65.52 22.981 85.698 23.153 ;
     RECT  54.72 22.739 60.426 23.161 ;
     RECT  61.164 20.723 64.782 23.161 ;
     RECT  54.72 23.161 64.782 23.309 ;
     RECT  86.472 22.585 103.266 23.521 ;
     RECT  104.004 22.775 111.15 23.521 ;
     RECT  54.72 23.309 60.426 23.549 ;
     RECT  65.916 23.153 85.698 23.621 ;
     RECT  65.916 23.621 67.806 23.657 ;
     RECT  31.932 22.739 53.946 23.999 ;
     RECT  47.052 23.999 53.946 24.089 ;
     RECT  2.415 22.199 15.606 24.431 ;
     RECT  47.052 24.089 53.838 24.431 ;
     RECT  22.896 23.153 31.086 24.475 ;
     RECT  31.932 23.999 46.314 24.503 ;
     RECT  22.716 24.475 31.086 24.511 ;
     RECT  48.708 24.431 53.838 24.539 ;
     RECT  86.472 23.521 111.15 24.629 ;
     RECT  22.644 24.511 31.086 24.701 ;
     RECT  111.996 22.775 116.586 24.709 ;
     RECT  111.996 24.709 116.73 24.773 ;
     RECT  86.508 24.629 111.15 24.781 ;
     RECT  111.996 24.773 112.878 24.781 ;
     RECT  86.508 24.781 112.878 24.899 ;
     RECT  61.164 23.309 64.782 24.907 ;
     RECT  68.544 23.621 85.698 24.935 ;
     RECT  54.756 23.549 60.426 25.141 ;
     RECT  3.456 24.431 15.606 25.169 ;
     RECT  47.052 24.431 47.934 25.177 ;
     RECT  48.708 24.539 53.766 25.177 ;
     RECT  54.54 25.141 60.426 25.181 ;
     RECT  37.188 24.503 46.314 25.277 ;
     RECT  113.94 24.773 116.73 25.285 ;
     RECT  117.504 22.469 126.897 25.285 ;
     RECT  54.756 25.181 60.426 25.321 ;
     RECT  61.164 24.907 65.07 25.321 ;
     RECT  54.756 25.321 65.07 25.411 ;
     RECT  65.916 23.657 67.77 25.411 ;
     RECT  113.94 25.285 126.897 25.439 ;
     RECT  22.824 24.701 31.086 25.511 ;
     RECT  54.756 25.411 67.77 25.519 ;
     RECT  68.544 24.935 84.042 25.519 ;
     RECT  16.452 23.153 21.906 25.555 ;
     RECT  16.452 25.555 22.122 25.613 ;
     RECT  54.756 25.519 84.042 25.619 ;
     RECT  54.756 25.619 74.106 25.709 ;
     RECT  74.88 25.619 84.042 25.709 ;
     RECT  9.612 25.169 15.606 25.717 ;
     RECT  86.508 24.899 111.15 25.817 ;
     RECT  47.052 25.177 53.766 25.825 ;
     RECT  9.612 25.717 15.714 25.861 ;
     RECT  16.452 25.613 21.906 25.861 ;
     RECT  86.508 25.817 103.302 25.949 ;
     RECT  54.756 25.709 56.826 25.951 ;
     RECT  57.564 25.709 74.106 25.979 ;
     RECT  76.428 25.709 84.042 25.979 ;
     RECT  81.288 25.979 84.042 26.051 ;
     RECT  81.324 26.051 84.042 26.123 ;
     RECT  81.36 26.123 84.042 26.249 ;
     RECT  81.396 26.249 84.042 26.251 ;
     RECT  84.78 24.935 85.698 26.251 ;
     RECT  81.396 26.251 85.698 26.285 ;
     RECT  31.932 24.503 36.45 26.293 ;
     RECT  37.188 25.277 46.278 26.293 ;
     RECT  31.932 26.293 46.278 26.329 ;
     RECT  47.052 25.825 53.874 26.329 ;
     RECT  9.612 25.861 21.906 26.357 ;
     RECT  31.932 26.329 53.874 26.429 ;
     RECT  57.564 25.979 73.962 26.429 ;
     RECT  111.996 24.899 112.878 26.599 ;
     RECT  113.94 25.439 123.642 26.599 ;
     RECT  86.508 25.949 103.266 26.663 ;
     RECT  104.04 25.817 111.15 26.671 ;
     RECT  111.996 26.599 123.642 26.671 ;
     RECT  86.508 26.663 96.03 26.699 ;
     RECT  81.468 26.285 85.698 26.825 ;
     RECT  104.04 26.671 123.642 26.861 ;
     RECT  3.456 25.169 8.874 26.897 ;
     RECT  5.868 26.897 8.874 27.067 ;
     RECT  9.612 26.357 19.494 27.067 ;
     RECT  5.868 27.067 19.494 27.103 ;
     RECT  20.268 26.357 21.906 27.103 ;
     RECT  43.74 26.429 53.874 27.139 ;
     RECT  54.648 25.951 56.826 27.139 ;
     RECT  43.74 27.139 56.826 27.239 ;
     RECT  81.468 26.825 84.042 27.337 ;
     RECT  5.868 27.103 21.906 27.365 ;
     RECT  124.668 25.439 126.897 27.365 ;
     RECT  47.052 27.239 56.826 27.473 ;
     RECT  111.996 26.861 123.642 27.481 ;
     RECT  9.612 27.365 21.906 27.509 ;
     RECT  2.415 24.431 2.697 27.547 ;
     RECT  2.415 27.547 2.718 27.599 ;
     RECT  111.996 27.481 123.678 27.679 ;
     RECT  96.768 26.663 103.266 27.707 ;
     RECT  22.968 25.511 31.086 27.751 ;
     RECT  31.932 26.429 43.002 27.751 ;
     RECT  76.428 25.979 80.406 27.751 ;
     RECT  22.968 27.751 43.002 27.821 ;
     RECT  102.744 27.707 103.266 27.841 ;
     RECT  111.996 27.679 124.218 27.869 ;
     RECT  76.32 27.751 80.406 27.877 ;
     RECT  52.272 27.473 56.826 27.905 ;
     RECT  54.972 27.905 56.826 27.913 ;
     RECT  57.564 26.429 65.106 27.913 ;
     RECT  102.744 27.841 103.302 27.913 ;
     RECT  104.04 26.861 111.15 27.913 ;
     RECT  76.176 27.877 80.406 27.917 ;
     RECT  43.74 27.239 46.206 27.941 ;
     RECT  52.272 27.905 54.162 27.941 ;
     RECT  102.744 27.913 111.15 27.941 ;
     RECT  111.996 27.869 124.146 27.941 ;
     RECT  76.428 27.917 80.406 27.985 ;
     RECT  81.18 27.337 84.042 27.985 ;
     RECT  111.996 27.941 123.678 28.319 ;
     RECT  16.38 27.509 21.906 28.349 ;
     RECT  20.268 28.349 21.906 28.409 ;
     RECT  22.968 27.821 31.086 28.409 ;
     RECT  16.38 28.349 19.494 28.445 ;
     RECT  54.972 27.913 65.106 28.489 ;
     RECT  65.916 26.429 73.962 28.489 ;
     RECT  74.88 25.709 75.294 28.525 ;
     RECT  86.508 26.699 94.986 28.687 ;
     RECT  96.012 26.699 96.03 28.687 ;
     RECT  74.88 28.525 75.366 28.787 ;
     RECT  86.508 28.687 96.03 28.795 ;
     RECT  96.768 27.707 101.862 28.795 ;
     RECT  3.456 26.897 5.058 28.831 ;
     RECT  5.868 27.365 8.874 28.831 ;
     RECT  74.88 28.787 75.294 28.831 ;
     RECT  3.456 28.831 8.874 28.949 ;
     RECT  31.932 27.821 43.002 28.957 ;
     RECT  43.74 27.941 44.154 28.957 ;
     RECT  54.972 28.489 73.962 28.957 ;
     RECT  74.7 28.831 75.294 28.957 ;
     RECT  54.972 28.957 75.294 29.021 ;
     RECT  44.892 27.941 46.206 29.029 ;
     RECT  47.052 27.473 51.498 29.029 ;
     RECT  52.272 27.941 53.874 29.219 ;
     RECT  102.816 27.941 111.15 29.219 ;
     RECT  104.04 29.219 111.15 29.533 ;
     RECT  9.612 27.509 15.606 29.569 ;
     RECT  16.452 28.445 19.494 29.569 ;
     RECT  22.968 28.409 27.27 29.569 ;
     RECT  28.008 28.409 31.086 29.569 ;
     RECT  5.868 28.949 8.874 29.659 ;
     RECT  9.612 29.569 19.494 29.659 ;
     RECT  104.04 29.533 111.186 29.759 ;
     RECT  110.268 29.759 111.186 29.767 ;
     RECT  111.996 28.319 123.606 29.767 ;
     RECT  104.04 29.759 109.422 29.795 ;
     RECT  54.972 29.021 73.962 29.803 ;
     RECT  84.78 26.825 85.698 29.875 ;
     RECT  86.508 28.795 101.862 29.875 ;
     RECT  5.868 29.659 19.494 29.903 ;
     RECT  44.892 29.029 51.498 29.911 ;
     RECT  52.272 29.219 53.73 29.911 ;
     RECT  102.816 29.219 103.266 30.001 ;
     RECT  31.932 28.957 44.154 30.029 ;
     RECT  44.892 29.911 53.73 30.029 ;
     RECT  44.892 30.029 51.498 30.065 ;
     RECT  8.856 29.903 19.494 30.145 ;
     RECT  124.956 27.365 126.897 30.283 ;
     RECT  2.415 27.599 2.697 30.307 ;
     RECT  3.456 28.949 5.058 30.307 ;
     RECT  110.268 29.767 123.606 30.343 ;
     RECT  2.415 30.307 5.058 30.365 ;
     RECT  8.856 30.145 19.53 30.371 ;
     RECT  22.968 29.569 31.086 30.415 ;
     RECT  54.72 29.803 73.962 30.451 ;
     RECT  84.78 29.875 101.862 30.569 ;
     RECT  104.292 29.795 109.422 30.577 ;
     RECT  110.268 30.343 123.966 30.577 ;
     RECT  9.612 30.371 19.53 30.712 ;
     RECT  20.268 28.409 21.87 30.712 ;
     RECT  9.612 30.712 21.87 30.749 ;
     RECT  22.968 30.415 31.266 30.749 ;
     RECT  76.428 27.985 84.042 30.749 ;
     RECT  84.78 30.569 95.814 30.749 ;
     RECT  104.292 30.577 123.966 30.839 ;
     RECT  107.712 30.839 123.966 30.883 ;
     RECT  124.812 30.283 126.897 30.883 ;
     RECT  81.18 30.749 84.042 31.145 ;
     RECT  3.456 30.365 5.058 31.261 ;
     RECT  3.456 31.261 5.094 31.351 ;
     RECT  5.868 29.903 8.097 31.351 ;
     RECT  32.004 30.029 44.154 31.649 ;
     RECT  86.508 30.749 95.814 31.649 ;
     RECT  96.768 30.569 101.862 31.649 ;
     RECT  100.98 31.649 101.862 31.867 ;
     RECT  102.816 30.001 103.446 31.867 ;
     RECT  32.004 31.649 39.294 31.919 ;
     RECT  100.98 31.867 103.446 31.919 ;
     RECT  92.952 31.649 95.814 32.035 ;
     RECT  96.768 31.649 100.206 32.035 ;
     RECT  9.612 30.749 19.494 32.063 ;
     RECT  54.612 30.451 73.962 32.063 ;
     RECT  86.508 31.649 92.142 32.189 ;
     RECT  9.756 32.063 19.494 32.341 ;
     RECT  20.268 30.749 21.87 32.341 ;
     RECT  76.428 30.749 80.406 32.341 ;
     RECT  107.712 30.883 126.897 32.381 ;
     RECT  76.176 32.341 80.406 32.395 ;
     RECT  76.032 32.395 80.406 32.459 ;
     RECT  9.756 32.341 21.87 32.477 ;
     RECT  92.952 32.035 100.206 32.477 ;
     RECT  36.144 31.919 39.294 32.495 ;
     RECT  28.008 30.749 31.266 32.531 ;
     RECT  37.368 32.495 39.294 32.567 ;
     RECT  56.34 32.063 73.962 32.639 ;
     RECT  104.292 30.839 106.938 32.729 ;
     RECT  44.892 30.065 47.934 32.765 ;
     RECT  106.056 32.729 106.938 32.765 ;
     RECT  40.068 31.649 44.154 32.801 ;
     RECT  96.768 32.477 100.206 32.873 ;
     RECT  3.456 31.351 8.097 33.019 ;
     RECT  8.856 30.371 8.874 33.019 ;
     RECT  20.268 32.477 21.87 33.043 ;
     RECT  107.712 32.381 112.878 33.071 ;
     RECT  22.968 30.749 27.27 33.115 ;
     RECT  28.008 32.531 31.122 33.115 ;
     RECT  44.028 32.801 44.154 33.115 ;
     RECT  44.892 32.765 46.314 33.115 ;
     RECT  86.508 32.189 86.598 33.269 ;
     RECT  113.94 32.381 126.897 33.269 ;
     RECT  22.968 33.115 31.122 33.305 ;
     RECT  107.712 33.071 109.386 33.413 ;
     RECT  86.58 33.269 86.598 33.421 ;
     RECT  87.372 32.189 89.298 33.421 ;
     RECT  44.028 33.115 46.314 33.575 ;
     RECT  81.216 31.145 84.042 33.583 ;
     RECT  84.78 30.749 85.698 33.583 ;
     RECT  44.892 33.575 46.314 34.267 ;
     RECT  47.052 32.765 47.934 34.267 ;
     RECT  56.34 32.639 65.214 34.349 ;
     RECT  113.94 33.269 122.274 34.591 ;
     RECT  123.012 33.269 126.897 34.591 ;
     RECT  44.892 34.267 47.934 34.655 ;
     RECT  9.756 32.477 19.494 34.663 ;
     RECT  20.268 33.043 22.23 34.663 ;
     RECT  54.612 32.063 55.602 34.735 ;
     RECT  76.428 32.459 80.406 34.763 ;
     RECT  113.94 34.591 126.897 34.763 ;
     RECT  81.216 33.583 85.698 34.889 ;
     RECT  117.18 34.763 126.897 34.925 ;
     RECT  117.18 34.925 123.822 35.033 ;
     RECT  57.708 34.349 65.214 35.131 ;
     RECT  66.204 32.639 73.962 35.131 ;
     RECT  122.904 35.033 123.822 35.159 ;
     RECT  9.756 34.663 22.23 35.267 ;
     RECT  3.456 33.019 8.874 35.311 ;
     RECT  9.756 35.267 19.35 35.311 ;
     RECT  20.196 35.267 22.23 35.339 ;
     RECT  28.008 33.305 31.122 35.401 ;
     RECT  117.18 35.033 122.166 35.699 ;
     RECT  44.892 34.655 46.314 35.969 ;
     RECT  76.428 34.763 79.002 36.391 ;
     RECT  57.708 35.131 73.962 36.509 ;
     RECT  44.028 33.575 44.154 37.597 ;
     RECT  54.504 34.735 55.602 37.597 ;
     RECT  56.34 34.349 56.862 37.597 ;
     RECT  113.94 34.763 116.406 38.551 ;
     RECT  92.952 32.477 95.814 38.669 ;
     RECT  48.708 30.065 51.498 38.749 ;
     RECT  52.272 30.029 53.73 38.749 ;
     RECT  109.26 33.413 109.386 38.749 ;
     RECT  110.124 33.071 112.878 38.749 ;
     RECT  109.26 38.749 112.878 38.777 ;
     RECT  109.332 38.777 112.878 39.209 ;
     RECT  36.144 32.495 36.63 39.361 ;
     RECT  37.368 32.567 37.746 39.361 ;
     RECT  113.904 38.551 116.406 39.479 ;
     RECT  3.456 35.311 19.35 40.289 ;
     RECT  81.216 34.889 84.006 40.711 ;
     RECT  57.816 36.509 73.962 40.829 ;
     RECT  54.504 37.597 56.862 41.099 ;
     RECT  86.58 33.421 89.298 41.099 ;
     RECT  74.88 29.021 75.294 41.521 ;
     RECT  102.816 31.919 103.446 41.791 ;
     RECT  3.456 40.289 12.078 41.909 ;
     RECT  118.872 35.699 122.166 42.089 ;
     RECT  12.852 40.289 19.35 42.601 ;
     RECT  36.144 39.361 37.746 42.601 ;
     RECT  99.576 32.873 100.206 42.601 ;
     RECT  36.036 42.601 37.746 42.719 ;
     RECT  124.812 34.925 126.897 43.141 ;
     RECT  20.304 35.339 22.23 43.259 ;
     RECT  110.124 39.209 112.878 43.367 ;
     RECT  104.292 32.729 105.297 44.221 ;
     RECT  102.744 41.791 103.446 44.339 ;
     RECT  44.892 35.969 46.206 44.609 ;
     RECT  11.916 41.909 12.078 44.761 ;
     RECT  12.852 42.601 19.458 44.761 ;
     RECT  43.92 37.597 44.154 44.761 ;
     RECT  106.128 32.765 106.938 44.879 ;
     RECT  104.184 44.221 105.297 45.391 ;
     RECT  106.128 44.879 106.866 45.391 ;
     RECT  36.036 42.719 37.674 45.419 ;
     RECT  20.304 43.259 22.122 45.571 ;
     RECT  22.968 33.305 27.27 45.689 ;
     RECT  32.004 31.919 35.19 45.689 ;
     RECT  68.688 40.829 73.962 45.959 ;
     RECT  47.052 34.655 47.934 46.111 ;
     RECT  48.708 38.749 53.73 46.111 ;
     RECT  96.768 32.873 98.694 46.381 ;
     RECT  68.688 45.959 73.674 46.769 ;
     RECT  86.58 41.099 89.19 48.299 ;
     RECT  107.712 33.413 108.486 48.469 ;
     RECT  109.332 39.209 109.386 48.469 ;
     RECT  40.068 32.801 43.002 48.929 ;
     RECT  107.712 48.469 109.386 48.929 ;
     RECT  99.504 42.601 100.206 49.199 ;
     RECT  123.012 35.159 123.822 49.549 ;
     RECT  22.968 45.689 27.162 50.125 ;
     RECT  90.072 32.189 92.142 50.251 ;
     RECT  79.776 34.763 80.406 50.971 ;
     RECT  81.144 40.711 84.006 50.971 ;
     RECT  32.004 45.689 33.75 51.241 ;
     RECT  123.012 49.549 123.858 51.241 ;
     RECT  79.776 50.971 84.006 51.781 ;
     RECT  84.78 34.889 85.698 51.781 ;
     RECT  117.18 35.699 118.134 51.781 ;
     RECT  2.415 30.365 2.697 52.051 ;
     RECT  3.456 41.909 11.106 52.051 ;
     RECT  113.904 39.479 116.334 52.169 ;
     RECT  28.008 35.401 31.158 52.241 ;
     RECT  113.904 52.169 113.922 52.321 ;
     RECT  110.304 43.367 112.878 52.439 ;
     RECT  31.896 51.241 33.75 52.861 ;
     RECT  34.56 45.689 35.19 52.861 ;
     RECT  37.296 45.419 37.674 52.987 ;
     RECT  38.484 32.567 39.294 52.987 ;
     RECT  118.944 42.089 122.166 53.789 ;
     RECT  37.296 52.987 39.294 54.481 ;
     RECT  40.068 48.929 42.966 54.481 ;
     RECT  96.696 46.381 98.694 54.841 ;
     RECT  99.504 49.199 100.098 54.841 ;
     RECT  117.108 51.781 118.134 55.409 ;
     RECT  114.66 52.169 116.334 55.831 ;
     RECT  117.108 55.409 118.026 55.831 ;
     RECT  68.688 46.769 69.57 56.911 ;
     RECT  31.896 52.861 35.19 57.569 ;
     RECT  74.88 41.521 75.582 57.721 ;
     RECT  100.98 31.919 101.862 57.839 ;
     RECT  76.428 36.391 79.038 57.991 ;
     RECT  79.776 51.781 85.698 57.991 ;
     RECT  96.696 54.841 100.098 57.991 ;
     RECT  100.98 57.839 101.682 57.991 ;
     RECT  118.944 53.789 119.322 58.117 ;
     RECT  120.06 53.789 122.166 58.117 ;
     RECT  109.332 48.929 109.386 58.649 ;
     RECT  107.712 48.929 108.594 58.693 ;
     RECT  109.332 58.649 109.35 58.693 ;
     RECT  47.052 46.111 53.73 59.189 ;
     RECT  107.712 58.693 109.35 59.611 ;
     RECT  54.504 41.099 56.826 59.809 ;
     RECT  57.816 40.829 67.878 59.809 ;
     RECT  31.896 57.569 35.097 59.999 ;
     RECT  47.052 59.189 53.658 60.809 ;
     RECT  37.296 54.481 42.966 61.349 ;
     RECT  118.944 58.117 122.166 61.349 ;
     RECT  76.428 57.991 85.698 61.501 ;
     RECT  90.072 50.251 92.178 61.771 ;
     RECT  68.616 56.911 69.57 62.041 ;
     RECT  70.308 46.769 73.674 62.041 ;
     RECT  90 61.771 92.178 62.311 ;
     RECT  92.952 38.669 95.742 62.311 ;
     RECT  76.428 61.501 85.842 62.671 ;
     RECT  86.58 48.299 87.282 62.671 ;
     RECT  76.428 62.671 87.282 63.247 ;
     RECT  96.696 57.991 101.682 64.327 ;
     RECT  43.92 44.761 44.586 64.363 ;
     RECT  45.324 44.609 46.206 64.363 ;
     RECT  28.116 52.241 31.158 65.849 ;
     RECT  2.415 52.051 11.106 66.749 ;
     RECT  47.052 60.809 47.358 67.801 ;
     RECT  76.32 63.247 87.282 69.331 ;
     RECT  88.02 48.299 89.19 69.331 ;
     RECT  11.916 44.761 19.458 69.989 ;
     RECT  11.916 69.989 15.462 75.119 ;
     RECT  39.996 61.349 42.966 75.119 ;
     RECT  9.504 66.749 11.106 75.775 ;
     RECT  11.916 75.119 14.202 75.775 ;
     RECT  48.132 60.809 53.658 85.621 ;
     RECT  54.504 59.809 67.878 85.621 ;
     RECT  48.132 85.621 67.878 85.661 ;
     RECT  129.42 88.747 129.438 88.877 ;
     RECT  124.704 43.141 126.897 94.219 ;
     RECT  124.704 94.219 127.098 94.289 ;
     RECT  125.64 94.289 127.098 94.325 ;
     RECT  113.868 52.321 113.922 114.925 ;
     RECT  114.66 55.831 118.026 114.925 ;
     RECT  43.92 64.363 46.206 120.721 ;
     RECT  46.944 67.801 47.358 120.721 ;
     RECT  43.92 120.721 47.358 120.893 ;
     RECT  113.868 114.925 118.026 122.215 ;
     RECT  125.64 94.325 126.897 126.661 ;
     RECT  125.64 126.661 127.134 126.701 ;
     RECT  113.76 122.215 118.026 127.651 ;
     RECT  124.704 94.289 124.902 132.745 ;
     RECT  125.64 126.701 126.897 132.745 ;
     RECT  122.94 51.241 123.858 135.103 ;
     RECT  122.94 135.103 123.966 135.599 ;
     RECT  118.944 61.349 122.13 135.985 ;
     RECT  122.94 135.599 123.894 135.985 ;
     RECT  127.692 139.189 127.71 139.997 ;
     RECT  118.944 135.985 123.894 143.429 ;
     RECT  118.944 143.429 119.322 152.149 ;
     RECT  120.132 143.429 123.894 152.149 ;
     RECT  76.32 69.331 89.19 152.339 ;
     RECT  22.86 50.125 27.162 153.149 ;
     RECT  74.772 57.721 75.582 153.265 ;
     RECT  76.32 152.339 80.334 153.265 ;
     RECT  128.52 141.853 128.538 153.341 ;
     RECT  33.408 59.999 35.097 153.959 ;
     RECT  48.132 85.661 53.658 154.345 ;
     RECT  113.616 127.651 118.026 154.499 ;
     RECT  102.744 44.339 103.338 154.615 ;
     RECT  110.304 52.439 112.806 154.615 ;
     RECT  107.604 59.611 109.35 154.769 ;
     RECT  109.332 154.769 109.35 154.885 ;
     RECT  110.124 154.615 112.806 154.885 ;
     RECT  81.144 152.339 89.19 155.047 ;
     RECT  9.504 75.775 14.202 155.155 ;
     RECT  14.976 75.119 15.462 155.155 ;
     RECT  28.116 65.849 28.17 155.155 ;
     RECT  28.98 65.849 31.158 155.155 ;
     RECT  90 62.311 95.742 155.425 ;
     RECT  96.696 64.327 101.826 155.425 ;
     RECT  81.144 155.047 89.262 155.489 ;
     RECT  86.76 155.489 89.262 155.579 ;
     RECT  90 155.425 101.826 155.579 ;
     RECT  2.415 66.749 8.73 155.965 ;
     RECT  9.504 155.155 15.462 155.965 ;
     RECT  33.408 153.959 33.75 156.389 ;
     RECT  37.296 61.349 39.186 156.389 ;
     RECT  90 155.579 100.206 156.389 ;
     RECT  118.944 152.149 123.894 156.505 ;
     RECT  124.704 132.745 126.897 156.505 ;
     RECT  118.944 156.505 126.897 156.659 ;
     RECT  36.036 45.419 36.522 156.667 ;
     RECT  54.504 85.661 67.878 156.703 ;
     RECT  68.616 62.041 73.674 156.703 ;
     RECT  90 156.389 93.474 156.929 ;
     RECT  113.616 154.499 117.774 157.199 ;
     RECT  39.996 75.119 42.93 157.469 ;
     RECT  43.92 120.893 46.206 157.585 ;
     RECT  46.944 120.893 47.358 157.585 ;
     RECT  74.772 153.265 80.334 157.585 ;
     RECT  90.216 156.929 93.474 157.585 ;
     RECT  94.215 156.389 100.206 157.585 ;
     RECT  118.944 156.659 120.294 157.585 ;
     RECT  48.096 154.345 53.658 157.739 ;
     RECT  2.415 155.965 15.462 158.009 ;
     RECT  81.144 155.489 85.842 158.009 ;
     RECT  90.216 157.585 100.206 158.009 ;
     RECT  12.78 158.009 15.462 158.395 ;
     RECT  16.236 69.989 19.458 158.395 ;
     RECT  104.184 45.391 106.866 158.549 ;
     RECT  54.504 156.703 73.674 159.089 ;
     RECT  82.548 158.009 85.842 159.089 ;
     RECT  90.216 158.009 98.37 159.089 ;
     RECT  54.504 159.089 64.458 159.359 ;
     RECT  104.184 158.549 106.074 159.475 ;
     RECT  106.848 158.549 106.866 159.475 ;
     RECT  39.996 157.469 42.858 159.745 ;
     RECT  12.78 158.395 19.458 160.015 ;
     RECT  20.232 45.571 22.122 160.015 ;
     RECT  12.78 160.015 22.122 160.439 ;
     RECT  38.844 156.389 39.186 160.717 ;
     RECT  39.996 159.745 43.074 160.717 ;
     RECT  31.896 59.999 32.562 161.095 ;
     RECT  43.92 157.585 47.358 161.293 ;
     RECT  17.928 160.439 22.122 161.519 ;
     RECT  104.184 159.475 106.866 161.635 ;
     RECT  107.604 154.769 108.594 161.635 ;
     RECT  100.944 155.579 101.826 161.789 ;
     RECT  101.808 161.789 101.826 161.833 ;
     RECT  102.564 154.615 103.338 161.833 ;
     RECT  104.184 161.635 108.594 162.175 ;
     RECT  109.332 154.885 112.806 162.175 ;
     RECT  65.196 159.089 73.674 162.409 ;
     RECT  74.592 157.585 80.334 162.409 ;
     RECT  94.176 159.089 98.37 162.599 ;
     RECT  81.144 158.009 81.81 162.715 ;
     RECT  82.548 159.089 83.97 162.715 ;
     RECT  104.184 162.175 112.806 162.869 ;
     RECT  101.808 161.833 103.338 162.985 ;
     RECT  104.184 162.869 112.626 162.985 ;
     RECT  17.928 161.519 22.014 163.139 ;
     RECT  81.144 162.715 83.97 163.255 ;
     RECT  84.708 159.089 85.842 163.255 ;
     RECT  101.808 162.985 112.626 164.219 ;
     RECT  43.812 161.293 47.358 164.335 ;
     RECT  48.096 157.739 53.55 164.335 ;
     RECT  38.844 160.717 43.074 164.489 ;
     RECT  65.196 162.409 80.334 164.605 ;
     RECT  81.144 163.255 85.842 164.605 ;
     RECT  90.216 159.089 93.402 164.605 ;
     RECT  31.896 161.095 32.598 164.759 ;
     RECT  2.415 158.009 11.97 165.029 ;
     RECT  99.108 158.009 100.206 165.029 ;
     RECT  117.684 157.199 117.774 165.029 ;
     RECT  113.616 157.199 116.946 165.145 ;
     RECT  117.684 165.029 117.738 165.145 ;
     RECT  34.488 153.959 35.097 165.415 ;
     RECT  28.116 155.155 31.158 165.569 ;
     RECT  37.296 156.389 38.07 165.847 ;
     RECT  38.844 164.489 39.042 165.847 ;
     RECT  12.78 160.439 17.19 166.225 ;
     RECT  65.196 164.605 85.842 166.927 ;
     RECT  86.76 155.579 89.154 166.927 ;
     RECT  101.808 164.219 107.982 167.729 ;
     RECT  54.504 159.359 55.494 167.845 ;
     RECT  28.116 165.569 30.978 167.999 ;
     RECT  28.116 167.999 28.134 168.115 ;
     RECT  65.196 166.927 89.154 168.269 ;
     RECT  100.944 161.789 101.034 168.385 ;
     RECT  101.808 167.729 106.146 168.385 ;
     RECT  22.86 153.149 26.946 168.655 ;
     RECT  94.176 162.599 94.497 168.655 ;
     RECT  95.256 162.599 98.37 168.655 ;
     RECT  94.176 168.655 98.37 168.809 ;
     RECT  31.932 164.759 32.598 168.925 ;
     RECT  33.408 156.389 33.714 168.925 ;
     RECT  12.6 166.225 17.19 170.545 ;
     RECT  17.928 163.139 21.006 170.545 ;
     RECT  35.892 156.667 36.522 170.977 ;
     RECT  37.296 165.847 39.042 170.977 ;
     RECT  76.176 168.269 89.154 172.319 ;
     RECT  65.196 168.269 75.402 173.129 ;
     RECT  56.232 159.359 64.458 173.245 ;
     RECT  54.324 167.845 55.494 173.785 ;
     RECT  56.232 173.245 64.962 173.785 ;
     RECT  28.08 168.115 28.134 174.749 ;
     RECT  28.08 174.749 28.098 174.865 ;
     RECT  27.936 174.865 28.098 178.879 ;
     RECT  28.872 167.999 30.978 178.879 ;
     RECT  31.932 168.925 33.714 178.879 ;
     RECT  121.176 156.659 126.897 178.879 ;
     RECT  99.108 165.029 100.098 178.915 ;
     RECT  100.944 168.385 106.146 178.915 ;
     RECT  31.86 178.879 33.714 178.951 ;
     RECT  121.068 178.879 126.897 178.951 ;
     RECT  54.324 173.785 64.962 179.069 ;
     RECT  65.7 173.129 75.402 179.069 ;
     RECT  76.176 172.319 83.79 179.069 ;
     RECT  89.964 164.605 93.402 179.069 ;
     RECT  94.176 168.809 98.262 179.069 ;
     RECT  113.616 165.145 117.738 179.069 ;
     RECT  66.456 179.069 75.402 179.149 ;
     RECT  76.176 179.069 76.302 179.149 ;
     RECT  2.415 165.029 11.862 179.185 ;
     RECT  12.6 170.545 21.006 179.185 ;
     RECT  21.96 163.139 22.014 179.185 ;
     RECT  22.752 168.655 26.946 179.185 ;
     RECT  27.936 178.879 30.978 179.185 ;
     RECT  31.824 178.951 33.714 179.185 ;
     RECT  34.488 165.415 35.154 179.185 ;
     RECT  35.892 170.977 39.042 179.185 ;
     RECT  64.8 179.069 64.962 179.185 ;
     RECT  65.7 179.069 65.718 179.185 ;
     RECT  84.564 172.319 89.154 179.185 ;
     RECT  89.964 179.069 90.234 179.185 ;
     RECT  106.956 167.729 107.982 179.185 ;
     RECT  108.828 164.219 112.626 179.185 ;
     RECT  118.764 157.585 120.294 179.185 ;
     RECT  121.032 178.951 126.897 179.185 ;
     RECT  2.415 179.185 21.114 179.221 ;
     RECT  21.96 179.185 26.946 179.221 ;
     RECT  27.936 179.185 33.714 179.221 ;
     RECT  34.488 179.185 39.042 179.221 ;
     RECT  39.816 164.489 43.074 179.221 ;
     RECT  91.044 179.069 93.402 179.221 ;
     RECT  94.176 179.069 95.454 179.221 ;
     RECT  96.192 179.069 98.262 179.221 ;
     RECT  99.108 178.915 106.146 179.221 ;
     RECT  106.956 179.185 112.734 179.221 ;
     RECT  113.652 179.069 117.738 179.221 ;
     RECT  118.764 179.185 126.897 179.221 ;
     RECT  2.415 179.221 26.946 179.339 ;
     RECT  34.488 179.221 43.074 179.339 ;
     RECT  54.324 179.069 63.99 179.339 ;
     RECT  91.044 179.221 95.454 179.339 ;
     RECT  106.956 179.221 112.806 179.339 ;
     RECT  27.936 179.221 33.75 179.455 ;
     RECT  34.488 179.339 42.534 179.455 ;
     RECT  84.564 179.185 90.234 179.491 ;
     RECT  43.812 164.335 53.55 179.617 ;
     RECT  54.324 179.339 63.522 179.617 ;
     RECT  77.076 179.069 83.79 179.617 ;
     RECT  84.528 179.491 90.234 179.617 ;
     RECT  96.192 179.221 106.146 179.707 ;
     RECT  2.415 179.339 26.658 179.725 ;
     RECT  27.936 179.455 42.534 179.725 ;
     RECT  96.192 179.707 106.218 179.761 ;
     RECT  106.956 179.339 109.314 179.761 ;
     RECT  2.268 179.725 26.658 179.879 ;
     RECT  27.9 179.725 42.534 179.923 ;
     RECT  64.8 179.185 65.718 179.923 ;
     RECT  77.076 179.617 90.234 179.923 ;
     RECT  91.044 179.339 95.274 179.923 ;
     RECT  64.404 179.923 65.718 179.995 ;
     RECT  66.456 179.149 76.302 179.995 ;
     RECT  27.468 179.923 42.534 180.139 ;
     RECT  43.344 179.617 63.522 180.139 ;
     RECT  64.404 179.995 76.302 180.139 ;
     RECT  77.076 179.923 95.274 180.139 ;
     RECT  96.192 179.761 109.314 180.139 ;
     RECT  77.076 180.139 109.314 180.149 ;
     RECT  96.984 180.149 109.314 180.265 ;
     RECT  110.052 179.339 112.806 180.265 ;
     RECT  113.652 179.221 126.897 180.265 ;
     RECT  113.652 180.265 126.954 180.293 ;
     RECT  27.468 180.139 76.302 180.301 ;
     RECT  77.076 180.149 78.678 180.301 ;
     RECT  96.984 180.265 112.806 180.301 ;
     RECT  113.652 180.293 119.07 180.301 ;
     RECT  119.88 180.293 126.954 180.301 ;
     RECT  119.88 180.301 127.062 180.455 ;
     RECT  2.268 179.879 26.586 180.605 ;
     RECT  2.34 180.605 26.586 180.805 ;
     RECT  27.36 180.301 78.678 180.805 ;
     RECT  2.34 180.805 78.678 180.995 ;
     RECT  2.376 180.995 78.678 181.111 ;
     RECT  79.416 180.149 96.246 181.111 ;
     RECT  96.984 180.301 119.07 181.111 ;
     RECT  119.88 180.455 126.954 181.111 ;
     RECT  1.116 181.111 1.134 181.181 ;
     RECT  128.484 180.805 128.502 181.237 ;
     RECT  129.312 181.111 129.33 181.237 ;
     RECT  2.376 181.111 126.954 181.277 ;
     RECT  23.976 181.277 24.105 181.457 ;
     RECT  45.615 181.277 45.882 181.457 ;
     RECT  51.015 181.277 51.174 181.457 ;
     RECT  56.415 181.277 70.074 181.457 ;
     RECT  77.472 181.277 79.326 181.457 ;
     RECT  83.415 181.277 83.682 181.457 ;
     RECT  105.015 181.277 105.174 181.457 ;
     RECT  110.34 181.277 110.505 181.457 ;
     RECT  45.864 181.457 45.882 181.517 ;
     RECT  83.664 181.457 83.682 181.517 ;
     RECT  51.156 181.457 51.174 181.565 ;
     RECT  18.216 181.277 18.774 181.613 ;
     RECT  23.976 181.457 23.994 181.613 ;
     RECT  71.784 181.277 73.494 181.613 ;
     RECT  77.472 181.457 77.994 181.613 ;
     RECT  99.54 181.277 99.846 181.613 ;
     RECT  110.34 181.457 110.358 181.613 ;
     RECT  7.2 181.277 14.742 181.757 ;
     RECT  15.48 181.277 16.038 181.757 ;
     RECT  20.772 181.277 21.33 181.757 ;
     RECT  22.5 181.277 22.95 181.757 ;
     RECT  27.468 181.277 33.102 181.757 ;
     RECT  46.8 181.277 47.574 181.757 ;
     RECT  48.528 181.277 48.546 181.757 ;
     RECT  53.388 181.277 53.406 181.757 ;
     RECT  71.784 181.613 72.09 181.757 ;
     RECT  74.448 181.277 74.466 181.757 ;
     RECT  78.768 181.457 79.326 181.757 ;
     RECT  97.344 181.277 98.658 181.757 ;
     RECT  99.828 181.613 99.846 181.757 ;
     RECT  105.156 181.457 105.174 181.757 ;
     RECT  106.956 181.277 106.974 181.757 ;
     RECT  111.816 181.277 111.834 181.757 ;
     RECT  124.128 181.277 126.954 181.757 ;
     RECT  128.484 181.237 129.33 181.757 ;
     RECT  2.376 181.277 6.246 181.853 ;
     RECT  7.2 181.757 13.698 181.853 ;
     RECT  18.216 181.613 18.234 181.853 ;
     RECT  28.224 181.757 33.102 181.853 ;
     RECT  33.984 181.277 37.134 181.853 ;
     RECT  38.052 181.277 38.934 181.853 ;
     RECT  39.78 181.277 41.994 181.853 ;
     RECT  52.344 181.277 52.362 181.853 ;
     RECT  56.556 181.457 70.074 181.853 ;
     RECT  71.784 181.757 71.802 181.853 ;
     RECT  84.492 181.277 96.318 181.853 ;
     RECT  97.344 181.757 98.226 181.853 ;
     RECT  108.288 181.277 108.306 181.853 ;
     RECT  112.68 181.277 123.138 181.853 ;
     RECT  124.128 181.757 126.522 181.853 ;
     RECT  124.56 181.853 126.522 181.949 ;
     RECT  34.776 181.853 34.794 182.189 ;
     RECT  123.12 181.853 123.138 182.189 ;
     RECT  2.376 181.853 2.394 182.333 ;
     RECT  3.276 181.853 3.294 182.381 ;
     RECT  5.004 181.853 5.022 182.381 ;
     RECT  28.224 181.853 28.242 182.381 ;
     RECT  29.088 181.853 30.078 182.381 ;
     RECT  33.084 181.853 33.102 182.381 ;
     RECT  59.868 181.853 59.886 182.381 ;
     RECT  63.324 181.853 63.342 182.381 ;
     RECT  68.184 181.853 68.634 182.381 ;
     RECT  73.476 181.613 73.494 182.381 ;
     RECT  77.472 181.613 77.49 182.381 ;
     RECT  84.492 181.853 84.51 182.381 ;
     RECT  85.788 181.853 85.806 182.381 ;
     RECT  91.944 181.853 91.962 182.381 ;
     RECT  117 181.853 117.018 182.381 ;
     RECT  119.16 181.853 119.178 182.381 ;
     RECT  120.132 181.853 120.15 182.381 ;
     RECT  120.996 181.853 121.446 182.381 ;
     RECT  124.56 181.949 124.578 182.381 ;
     RECT  125.856 181.949 126.522 182.381 ;
     RECT  6.228 181.853 6.246 182.429 ;
     RECT  8.46 181.853 8.478 182.429 ;
     RECT  29.556 182.381 29.574 182.429 ;
     RECT  31.284 181.853 31.302 182.429 ;
     RECT  92.808 181.853 92.826 182.429 ;
     RECT  96.3 181.853 96.318 182.429 ;
     RECT  113.904 181.853 113.922 182.429 ;
    LAYER M4 ;
     RECT  0.181 180.576 0.613 180.6 ;
     RECT  0.613 180 1.093 180.6 ;
     RECT  0.181 10.272 1.181 10.296 ;
     RECT  1.045 2.304 1.433 2.328 ;
     RECT  1.093 180 1.525 181.176 ;
     RECT  1.093 0.576 1.757 0.6 ;
     RECT  1.525 2.352 1.957 2.376 ;
     RECT  1.909 3.408 1.957 3.432 ;
     RECT  1.525 180 1.957 181.272 ;
     RECT  1.957 2.352 2.293 3.432 ;
     RECT  1.457 4.56 2.293 4.584 ;
     RECT  2.293 0.192 2.387 0.552 ;
     RECT  2.387 0.192 2.389 0.216 ;
     RECT  2.293 2.352 2.408 4.584 ;
     RECT  0.613 5.712 2.408 5.736 ;
     RECT  0.229 14.928 2.408 14.952 ;
     RECT  0.661 19.584 2.408 19.608 ;
     RECT  1.957 179.76 2.408 181.272 ;
     RECT  2.365 182.304 2.408 182.328 ;
     RECT  2.408 2.148 2.512 182.328 ;
     RECT  2.389 0.144 2.585 0.216 ;
     RECT  2.512 2.304 2.704 182.328 ;
     RECT  2.585 0.192 2.819 0.216 ;
     RECT  2.78 1.2 2.867 1.224 ;
     RECT  2.704 18.432 2.867 18.456 ;
     RECT  2.704 27.552 2.867 27.576 ;
     RECT  2.704 181.248 3.221 182.328 ;
     RECT  3.221 181.248 3.305 182.376 ;
     RECT  2.704 30.336 3.395 30.36 ;
     RECT  2.704 22.176 3.443 22.2 ;
     RECT  2.704 25.296 3.532 25.32 ;
     RECT  3.617 0.576 3.701 1.176 ;
     RECT  2.704 2.304 3.805 4.584 ;
     RECT  3.305 181.248 3.913 181.848 ;
     RECT  3.733 30.96 3.971 30.984 ;
     RECT  3.805 2.256 4.019 4.584 ;
     RECT  3.701 0.576 4.133 0.6 ;
     RECT  4.117 28.752 4.165 29.016 ;
     RECT  4.165 27.792 4.205 29.016 ;
     RECT  4.019 2.256 4.211 2.28 ;
     RECT  4.019 3.408 4.273 4.584 ;
     RECT  4.273 3.408 4.345 4.68 ;
     RECT  3.973 22.224 4.457 22.248 ;
     RECT  4.345 3.408 4.547 5.16 ;
     RECT  4.205 27.792 4.547 28.776 ;
     RECT  3.985 33.12 4.547 33.144 ;
     RECT  4.547 3.408 4.709 4.152 ;
     RECT  4.652 33.024 4.739 33.048 ;
     RECT  4.789 22.176 4.876 22.2 ;
     RECT  4.547 5.136 4.925 5.16 ;
     RECT  4.885 25.008 4.972 25.032 ;
     RECT  4.849 1.68 4.979 1.704 ;
     RECT  3.913 180.96 4.993 181.848 ;
     RECT  4.547 28.752 4.997 28.776 ;
     RECT  4.993 180.96 5.077 182.376 ;
     RECT  5.077 180.96 5.101 181.848 ;
     RECT  5.029 1.152 5.141 1.176 ;
     RECT  5.101 180.192 5.141 181.848 ;
     RECT  5.077 31.536 5.164 31.56 ;
     RECT  2.704 19.584 5.605 19.608 ;
     RECT  5.533 31.872 5.795 31.896 ;
     RECT  4.709 4.128 5.797 4.152 ;
     RECT  5.461 2.88 5.857 2.904 ;
     RECT  5.141 181.824 6.005 181.848 ;
     RECT  5.857 2.832 6.217 2.904 ;
     RECT  5.797 3.984 6.217 4.152 ;
     RECT  4.597 0.096 6.221 0.12 ;
     RECT  6.217 2.832 6.229 4.152 ;
     RECT  6.217 182.4 6.371 182.424 ;
     RECT  5.141 180.192 6.397 180.84 ;
     RECT  6.397 179.52 6.437 180.84 ;
     RECT  5.605 19.584 6.577 19.656 ;
     RECT  6.325 0.576 6.653 0.6 ;
     RECT  6.437 179.52 6.757 179.544 ;
     RECT  6.229 2.832 6.761 4.584 ;
     RECT  6.437 180.816 6.785 180.84 ;
     RECT  6.761 2.832 6.805 3.432 ;
     RECT  6.853 27.888 7.045 27.912 ;
     RECT  6.785 180.816 7.189 181.272 ;
     RECT  6.761 4.56 7.525 4.584 ;
     RECT  6.757 178.992 7.669 179.544 ;
     RECT  7.189 180.816 7.669 181.848 ;
     RECT  6.805 2.304 7.808 3.432 ;
     RECT  7.525 4.56 7.808 5.112 ;
     RECT  2.704 14.928 7.808 14.952 ;
     RECT  6.577 19.584 7.808 20.04 ;
     RECT  6.86 24.816 7.808 24.84 ;
     RECT  7.045 27.6 7.808 27.912 ;
     RECT  7.669 33.264 7.808 33.672 ;
     RECT  7.669 178.992 7.808 181.848 ;
     RECT  7.808 2.148 7.912 181.848 ;
     RECT  7.649 0.096 7.957 0.12 ;
     RECT  7.912 2.418 8.104 181.848 ;
     RECT  8.104 2.88 8.243 5.064 ;
     RECT  8.104 33.024 8.291 33.576 ;
     RECT  8.291 33.552 8.345 33.576 ;
     RECT  8.104 181.824 8.449 181.848 ;
     RECT  7.957 0.096 8.489 0.6 ;
     RECT  8.104 27.6 8.531 27.624 ;
     RECT  8.449 181.824 8.579 182.424 ;
     RECT  8.104 22.704 8.723 22.728 ;
     RECT  8.489 0.576 8.921 0.6 ;
     RECT  8.104 18.144 9.107 18.168 ;
     RECT  8.104 20.592 9.107 20.616 ;
     RECT  8.104 19.584 9.157 19.608 ;
     RECT  8.104 29.664 9.241 29.688 ;
     RECT  9.157 19.584 9.244 20.568 ;
     RECT  8.243 2.88 9.245 4.584 ;
     RECT  9.169 27.12 9.5 27.144 ;
     RECT  9.5 27.12 9.683 27.336 ;
     RECT  9.241 29.664 9.683 30.12 ;
     RECT  9.445 1.152 9.685 1.176 ;
     RECT  9.673 10.8 9.821 10.824 ;
     RECT  9.685 1.152 9.877 1.752 ;
     RECT  9.245 2.88 9.877 4.008 ;
     RECT  9.877 1.152 10.001 4.008 ;
     RECT  10.001 1.152 10.037 2.904 ;
     RECT  9.683 27.312 10.037 27.336 ;
     RECT  10.037 2.304 10.505 2.904 ;
     RECT  10.001 3.984 10.549 4.008 ;
     RECT  9.961 179.568 10.681 179.592 ;
     RECT  9.244 19.584 10.693 19.608 ;
     RECT  10.285 36.048 10.717 36.072 ;
     RECT  10.681 179.088 10.781 179.592 ;
     RECT  8.104 180.816 10.781 180.84 ;
     RECT  10.693 19.584 10.819 19.656 ;
     RECT  10.717 35.76 10.835 36.072 ;
     RECT  10.781 179.088 10.873 180.84 ;
     RECT  10.873 179.088 10.901 179.544 ;
     RECT  10.037 1.152 10.925 1.176 ;
     RECT  10.885 22.704 10.972 22.728 ;
     RECT  10.925 0.576 11.009 1.176 ;
     RECT  10.549 3.984 11.009 4.584 ;
     RECT  10.837 16.992 11.405 17.016 ;
     RECT  10.835 35.76 11.411 35.784 ;
     RECT  11.221 25.248 11.441 25.272 ;
     RECT  11.009 3.984 11.449 4.536 ;
     RECT  11.605 27.072 11.692 27.096 ;
     RECT  11.149 32.832 11.699 32.856 ;
     RECT  10.505 2.88 11.797 2.904 ;
     RECT  11.749 32.736 11.837 32.76 ;
     RECT  9.683 30.096 11.989 30.12 ;
     RECT  11.797 2.88 12.053 3.432 ;
     RECT  10.901 179.52 12.125 179.544 ;
     RECT  12.053 2.88 12.161 2.904 ;
     RECT  11.449 4.512 12.229 4.536 ;
     RECT  12.229 4.512 12.23 4.584 ;
     RECT  11.989 29.664 12.233 30.12 ;
     RECT  12.517 0.096 12.661 0.12 ;
     RECT  11.009 1.152 12.661 1.176 ;
     RECT  12.661 0.096 12.809 1.176 ;
     RECT  12.23 4.56 13.165 4.584 ;
     RECT  13.093 2.832 13.208 2.856 ;
     RECT  13.165 4.56 13.208 4.968 ;
     RECT  8.104 14.928 13.208 14.952 ;
     RECT  11.977 17.136 13.208 17.16 ;
     RECT  10.819 19.584 13.208 19.608 ;
     RECT  13.093 22.416 13.208 22.44 ;
     RECT  13.093 25.296 13.208 25.32 ;
     RECT  12.233 29.664 13.208 30.024 ;
     RECT  12.589 31.968 13.208 31.992 ;
     RECT  12.764 32.976 13.208 33 ;
     RECT  13.093 36.048 13.208 36.072 ;
     RECT  12.553 179.568 13.208 179.592 ;
     RECT  10.873 180.816 13.208 180.84 ;
     RECT  8.579 181.824 13.208 181.848 ;
     RECT  13.208 2.148 13.312 181.848 ;
     RECT  13.312 2.418 13.504 181.848 ;
     RECT  13.504 4.08 13.565 4.968 ;
     RECT  12.809 0.144 13.619 1.176 ;
     RECT  13.504 22.176 13.619 22.2 ;
     RECT  13.619 0.24 13.667 1.176 ;
     RECT  13.504 180.816 13.667 181.848 ;
     RECT  13.565 4.08 13.673 4.68 ;
     RECT  13.504 2.928 13.745 2.952 ;
     RECT  13.667 181.728 13.859 181.848 ;
     RECT  13.504 32.448 13.948 33.048 ;
     RECT  13.673 4.56 14.033 4.68 ;
     RECT  13.504 16.848 14.243 16.872 ;
     RECT  14.033 4.656 14.284 4.68 ;
     RECT  13.948 32.448 14.329 32.472 ;
     RECT  13.667 0.624 14.437 1.176 ;
     RECT  14.437 0.624 14.501 1.8 ;
     RECT  13.859 181.728 14.821 181.752 ;
     RECT  14.501 1.152 14.933 1.8 ;
     RECT  14.821 22.176 14.969 22.2 ;
     RECT  14.497 17.088 15.005 17.112 ;
     RECT  13.504 19.584 15.212 19.608 ;
     RECT  15.212 19.488 15.299 19.608 ;
     RECT  15.037 30.432 15.395 30.456 ;
     RECT  14.933 1.2 15.433 1.8 ;
     RECT  15.397 27.792 15.484 27.816 ;
     RECT  15.397 25.728 15.725 25.752 ;
     RECT  15.433 1.2 15.833 2.664 ;
     RECT  15.301 4.08 15.905 4.104 ;
     RECT  15.932 33.6 16.019 33.624 ;
     RECT  14.821 180.816 16.093 181.752 ;
     RECT  16.021 16.752 16.259 16.776 ;
     RECT  15.833 1.2 16.373 1.272 ;
     RECT  16.373 1.2 16.444 1.224 ;
     RECT  16.444 1.152 16.445 1.224 ;
     RECT  15.973 179.76 16.553 179.784 ;
     RECT  16.597 5.136 16.733 5.16 ;
     RECT  15.299 19.584 16.796 19.608 ;
     RECT  16.549 32.448 16.835 32.472 ;
     RECT  15.833 2.64 17.045 2.664 ;
     RECT  16.796 19.584 17.053 20.04 ;
     RECT  16.981 28.992 17.068 29.016 ;
     RECT  16.369 16.608 17.123 16.632 ;
     RECT  17.045 2.64 17.125 2.904 ;
     RECT  17.221 11.76 17.228 11.784 ;
     RECT  17.125 2.64 17.237 3 ;
     RECT  17.228 11.76 17.308 11.928 ;
     RECT  17.308 11.904 17.315 11.928 ;
     RECT  17.405 4.56 17.555 4.872 ;
     RECT  17.053 19.584 17.603 20.376 ;
     RECT  16.445 1.152 17.705 1.176 ;
     RECT  17.237 2.64 17.893 2.904 ;
     RECT  17.797 1.2 18.101 1.224 ;
     RECT  16.093 180.816 18.181 181.272 ;
     RECT  18.181 180.816 18.268 181.848 ;
     RECT  17.893 2.352 18.277 2.904 ;
     RECT  18.277 1.776 18.284 2.904 ;
     RECT  17.509 16.8 18.325 16.824 ;
     RECT  18.284 1.776 18.469 3.384 ;
     RECT  17.555 4.56 18.469 4.584 ;
     RECT  18.469 1.776 18.608 4.584 ;
     RECT  13.504 14.928 18.608 14.952 ;
     RECT  18.325 16.8 18.608 17.064 ;
     RECT  17.603 19.584 18.608 19.608 ;
     RECT  17.653 22.896 18.608 22.92 ;
     RECT  18.229 30.192 18.608 30.216 ;
     RECT  17.413 32.832 18.608 32.856 ;
     RECT  17.845 179.52 18.608 179.544 ;
     RECT  18.268 180.816 18.608 181.608 ;
     RECT  18.608 1.776 18.785 181.608 ;
     RECT  18.785 2.352 18.796 181.608 ;
     RECT  18.796 2.352 18.904 181.272 ;
     RECT  18.904 179.472 19.109 179.496 ;
     RECT  18.904 2.352 19.181 4.248 ;
     RECT  19.181 3.648 19.325 4.248 ;
     RECT  18.904 25.68 19.379 25.704 ;
     RECT  19.325 4.224 19.433 4.248 ;
     RECT  19.093 1.152 19.469 1.176 ;
     RECT  18.904 30.192 19.469 30.36 ;
     RECT  18.904 34.752 19.708 34.872 ;
     RECT  18.904 16.752 19.715 16.776 ;
     RECT  19.708 34.848 19.907 34.872 ;
     RECT  19.957 32.448 20.365 32.472 ;
     RECT  19.181 2.352 20.405 2.376 ;
     RECT  20.365 31.968 20.437 32.472 ;
     RECT  20.357 4.56 20.441 4.584 ;
     RECT  19.933 30.72 20.444 30.744 ;
     RECT  19.957 28.32 20.509 28.344 ;
     RECT  20.444 30.48 20.531 30.744 ;
     RECT  20.437 31.968 20.531 32.808 ;
     RECT  20.509 28.224 20.54 28.344 ;
     RECT  20.54 28.224 20.627 28.488 ;
     RECT  18.904 180.816 20.761 181.272 ;
     RECT  20.533 2.88 20.801 2.904 ;
     RECT  20.473 4.224 20.869 4.248 ;
     RECT  20.531 32.784 21.053 32.808 ;
     RECT  20.869 3.504 21.089 4.248 ;
     RECT  20.437 17.088 21.109 17.112 ;
     RECT  20.627 28.224 21.161 28.248 ;
     RECT  21.116 20.88 21.203 20.904 ;
     RECT  20.761 180.816 21.385 181.752 ;
     RECT  21.089 3.936 21.557 4.248 ;
     RECT  21.109 16.512 21.629 17.112 ;
     RECT  21.385 180.816 21.701 181.272 ;
     RECT  19.525 0.624 22.061 0.648 ;
     RECT  21.397 1.776 22.097 1.8 ;
     RECT  21.557 4.224 22.157 4.248 ;
     RECT  22.069 25.584 22.211 25.608 ;
     RECT  22.157 4.224 22.241 4.584 ;
     RECT  21.701 181.248 22.252 181.272 ;
     RECT  22.201 180.096 22.835 180.216 ;
     RECT  22.789 2.88 22.933 2.904 ;
     RECT  22.589 3.984 22.933 4.104 ;
     RECT  22.489 181.728 23.075 181.752 ;
     RECT  22.777 21.552 23.365 21.576 ;
     RECT  22.933 2.88 23.461 4.104 ;
     RECT  22.165 1.152 23.501 1.176 ;
     RECT  21.629 17.088 23.641 17.112 ;
     RECT  23.461 2.352 23.829 4.104 ;
     RECT  23.829 2.352 23.852 4.536 ;
     RECT  23.852 2.352 23.941 4.824 ;
     RECT  23.941 1.776 24.008 4.824 ;
     RECT  18.904 14.928 24.008 14.952 ;
     RECT  23.641 16.512 24.008 17.112 ;
     RECT  18.904 19.584 24.008 19.608 ;
     RECT  23.365 20.88 24.008 21.576 ;
     RECT  23.612 26.112 24.008 26.136 ;
     RECT  20.531 30.72 24.008 30.744 ;
     RECT  22.835 180.192 24.008 180.216 ;
     RECT  23.557 181.248 24.008 181.608 ;
     RECT  24.008 1.776 24.028 181.608 ;
     RECT  24.028 1.776 24.112 181.452 ;
     RECT  24.112 1.776 24.304 181.272 ;
     RECT  24.304 16.608 24.329 16.632 ;
     RECT  24.304 24.528 24.445 24.936 ;
     RECT  24.304 1.776 24.467 3.528 ;
     RECT  24.304 4.512 24.473 5.112 ;
     RECT  24.304 32.208 24.515 32.232 ;
     RECT  24.467 1.776 24.689 2.904 ;
     RECT  24.689 1.776 24.853 2.712 ;
     RECT  24.304 29.28 25.091 29.304 ;
     RECT  24.853 1.152 25.121 2.712 ;
     RECT  24.304 20.88 25.139 21.624 ;
     RECT  24.473 5.088 25.193 5.112 ;
     RECT  25.139 21.6 25.193 21.624 ;
     RECT  24.445 24.912 25.201 24.936 ;
     RECT  25.121 1.2 25.517 2.712 ;
     RECT  25.58 24.864 25.667 24.888 ;
     RECT  24.304 180.192 25.769 180.216 ;
     RECT  25.517 1.776 26.017 2.712 ;
     RECT  25.621 4.56 26.053 4.872 ;
     RECT  25.945 10.8 26.057 10.824 ;
     RECT  26.053 18.384 26.14 18.408 ;
     RECT  26.053 27.312 26.14 27.336 ;
     RECT  26.108 22.704 26.195 22.728 ;
     RECT  26.017 1.776 26.197 2.856 ;
     RECT  26.197 1.776 26.309 2.904 ;
     RECT  26.053 4.08 26.309 4.872 ;
     RECT  26.309 1.776 26.581 2.856 ;
     RECT  26.581 1.152 26.669 2.856 ;
     RECT  26.669 1.152 26.705 2.376 ;
     RECT  24.304 181.248 26.773 181.272 ;
     RECT  26.309 4.848 27.269 4.872 ;
     RECT  27.269 4.848 27.353 5.016 ;
     RECT  26.773 180.816 27.413 181.272 ;
     RECT  27.397 33.12 27.497 33.144 ;
     RECT  27.589 30.432 27.676 30.456 ;
     RECT  26.705 1.152 27.785 1.8 ;
     RECT  27.413 180.816 27.923 181.752 ;
     RECT  24.304 19.584 27.925 19.608 ;
     RECT  27.925 2.88 28.145 2.904 ;
     RECT  27.785 1.152 28.165 1.176 ;
     RECT  28.165 0.576 28.361 1.176 ;
     RECT  27.353 4.848 28.412 4.872 ;
     RECT  24.304 14.928 28.412 14.952 ;
     RECT  27.923 180.816 28.825 180.84 ;
     RECT  28.412 4.848 29.029 5.208 ;
     RECT  28.645 3.408 29.173 3.432 ;
     RECT  29.029 4.56 29.173 5.208 ;
     RECT  29.173 3.408 29.408 5.208 ;
     RECT  28.412 14.928 29.408 15.864 ;
     RECT  29.269 18.432 29.408 18.456 ;
     RECT  27.925 19.584 29.408 20.088 ;
     RECT  29.029 27.216 29.408 27.24 ;
     RECT  28.825 180 29.408 180.84 ;
     RECT  28.213 181.824 29.408 182.376 ;
     RECT  29.408 2.148 29.512 182.376 ;
     RECT  29.512 2.418 29.545 182.376 ;
     RECT  28.565 0.096 29.585 0.12 ;
     RECT  28.361 1.152 29.653 1.176 ;
     RECT  29.545 2.418 29.699 182.424 ;
     RECT  29.699 2.418 29.704 182.376 ;
     RECT  29.704 30.72 30.025 30.744 ;
     RECT  29.704 31.968 30.089 31.992 ;
     RECT  29.704 181.824 30.133 182.376 ;
     RECT  29.653 0.576 30.161 1.176 ;
     RECT  29.704 24.048 30.227 24.072 ;
     RECT  30.161 0.576 30.757 0.6 ;
     RECT  29.704 2.88 30.953 2.904 ;
     RECT  29.704 180 31.061 180.84 ;
     RECT  30.757 0.096 31.241 0.6 ;
     RECT  30.133 181.824 31.273 181.848 ;
     RECT  29.704 14.928 31.34 14.952 ;
     RECT  31.34 14.928 31.427 15.864 ;
     RECT  31.273 181.824 31.427 182.424 ;
     RECT  31.436 5.856 31.523 5.88 ;
     RECT  31.484 27.792 31.571 27.816 ;
     RECT  31.241 0.576 31.709 0.6 ;
     RECT  31.189 3.36 31.877 3.432 ;
     RECT  31.621 4.56 31.877 4.584 ;
     RECT  31.805 1.152 31.889 1.176 ;
     RECT  31.877 3.36 31.961 4.584 ;
     RECT  31.961 4.56 32.032 4.584 ;
     RECT  32.032 4.56 32.033 4.632 ;
     RECT  32.029 10.368 32.06 10.392 ;
     RECT  32.06 10.176 32.147 10.392 ;
     RECT  31.961 3.36 32.245 3.48 ;
     RECT  32.348 22.656 32.435 22.68 ;
     RECT  32.147 10.368 32.483 10.392 ;
     RECT  29.704 19.584 32.485 19.608 ;
     RECT  32.485 19.152 32.629 19.608 ;
     RECT  32.485 30.192 32.681 30.216 ;
     RECT  32.629 18.192 32.709 19.608 ;
     RECT  31.427 181.824 32.812 181.848 ;
     RECT  32.245 2.88 32.897 3.48 ;
     RECT  32.485 0.096 33.005 0.12 ;
     RECT  32.897 3.36 33.149 3.48 ;
     RECT  33.073 182.352 33.203 182.376 ;
     RECT  33.157 25.872 33.244 25.896 ;
     RECT  33.157 0.576 33.401 0.6 ;
     RECT  32.709 18.192 33.437 18.216 ;
     RECT  32.821 179.52 33.577 179.544 ;
     RECT  31.061 180.816 33.589 180.84 ;
     RECT  33.577 179.52 33.617 179.64 ;
     RECT  32.033 4.608 33.649 4.632 ;
     RECT  33.589 180.816 33.676 181.272 ;
     RECT  33.649 4.512 33.725 4.632 ;
     RECT  33.725 4.512 33.781 4.536 ;
     RECT  33.901 2.832 34.369 2.856 ;
     RECT  33.781 3.984 34.369 4.536 ;
     RECT  33.577 1.152 34.517 1.176 ;
     RECT  33.973 181.824 34.765 181.848 ;
     RECT  34.369 2.832 34.801 4.536 ;
     RECT  34.801 2.832 34.808 5.064 ;
     RECT  33.829 12.192 34.808 12.216 ;
     RECT  31.427 14.928 34.808 14.952 ;
     RECT  34.513 18.144 34.808 18.168 ;
     RECT  32.709 19.584 34.808 19.608 ;
     RECT  34.441 21.168 34.808 21.192 ;
     RECT  34.801 25.008 34.808 25.032 ;
     RECT  34.693 29.376 34.808 29.4 ;
     RECT  34.117 31.68 34.808 31.704 ;
     RECT  33.617 179.616 34.808 179.64 ;
     RECT  33.676 180.816 34.808 180.84 ;
     RECT  34.765 181.824 34.808 182.184 ;
     RECT  34.181 0.096 34.885 0.12 ;
     RECT  34.808 2.148 34.912 182.184 ;
     RECT  34.912 2.418 34.931 182.184 ;
     RECT  34.931 2.418 35.104 181.848 ;
     RECT  34.885 0.096 35.165 0.6 ;
     RECT  35.104 5.04 35.219 5.064 ;
     RECT  35.104 10.224 35.219 10.344 ;
     RECT  35.104 25.008 35.219 25.032 ;
     RECT  35.104 28.944 35.219 28.968 ;
     RECT  35.104 180.816 35.219 180.84 ;
     RECT  35.219 10.224 35.267 10.248 ;
     RECT  35.104 2.784 35.345 3.912 ;
     RECT  35.104 12 35.417 12.024 ;
     RECT  35.165 0.096 35.561 0.168 ;
     RECT  35.561 0.096 35.777 0.12 ;
     RECT  35.104 19.584 35.932 20.472 ;
     RECT  35.345 2.784 36.373 3.432 ;
     RECT  36.332 29.424 36.419 29.448 ;
     RECT  36.373 2.784 36.461 4.008 ;
     RECT  36.38 32.448 36.467 32.472 ;
     RECT  36.229 1.152 36.497 1.176 ;
     RECT  36.949 26.496 36.961 26.52 ;
     RECT  36.961 26.496 37.036 26.76 ;
     RECT  37.036 26.736 37.045 26.76 ;
     RECT  36.461 2.784 37.217 3.528 ;
     RECT  37.093 0.096 37.237 0.12 ;
     RECT  37.244 28.944 37.331 28.968 ;
     RECT  37.141 22.32 37.379 22.344 ;
     RECT  35.932 19.584 37.429 19.608 ;
     RECT  36.805 4.56 37.433 4.584 ;
     RECT  37.237 0.096 37.505 0.168 ;
     RECT  37.429 19.584 37.516 19.704 ;
     RECT  35.104 181.824 37.525 181.848 ;
     RECT  37.525 181.248 37.649 181.848 ;
     RECT  37.609 5.184 37.693 5.208 ;
     RECT  37.505 0.096 37.721 0.12 ;
     RECT  37.609 6.72 37.721 6.744 ;
     RECT  36.637 180 37.897 180.024 ;
     RECT  37.897 179.184 37.937 180.024 ;
     RECT  37.925 1.152 38.009 1.176 ;
     RECT  37.217 2.88 38.101 3.528 ;
     RECT  38.101 2.88 38.189 4.008 ;
     RECT  37.717 22.752 38.189 22.776 ;
     RECT  38.684 16.368 38.771 16.392 ;
     RECT  38.684 148.032 38.771 148.056 ;
     RECT  38.533 4.56 38.837 4.584 ;
     RECT  38.869 0.096 38.905 0.12 ;
     RECT  39.077 148.176 39.161 148.2 ;
     RECT  38.905 0.096 39.233 0.552 ;
     RECT  37.649 181.824 39.301 181.848 ;
     RECT  39.301 181.248 39.349 181.848 ;
     RECT  39.233 0.144 39.397 0.552 ;
     RECT  37.937 179.184 39.397 179.208 ;
     RECT  39.349 180.72 39.397 181.848 ;
     RECT  39.397 0.144 39.725 0.6 ;
     RECT  39.761 3.984 39.877 4.008 ;
     RECT  39.661 5.136 39.877 5.16 ;
     RECT  38.189 2.88 39.985 2.904 ;
     RECT  39.877 3.984 39.985 5.16 ;
     RECT  39.985 2.88 40.208 5.16 ;
     RECT  39.877 6.816 40.208 6.84 ;
     RECT  35.104 14.928 40.208 14.952 ;
     RECT  39.193 16.512 40.208 16.536 ;
     RECT  37.516 19.584 40.208 19.608 ;
     RECT  39.193 21.648 40.208 21.672 ;
     RECT  40.021 22.752 40.208 22.776 ;
     RECT  39.349 26.832 40.208 26.856 ;
     RECT  39.877 32.736 40.208 32.76 ;
     RECT  39.397 179.184 40.208 181.848 ;
     RECT  39.725 0.144 40.211 1.176 ;
     RECT  40.208 2.148 40.312 181.848 ;
     RECT  40.312 2.418 40.504 181.848 ;
     RECT  40.504 23.952 41.027 23.976 ;
     RECT  40.504 32.544 41.069 32.568 ;
     RECT  40.504 2.832 41.075 5.112 ;
     RECT  40.211 0.48 41.123 1.176 ;
     RECT  41.075 2.832 41.213 4.536 ;
     RECT  40.504 16.416 41.26 16.44 ;
     RECT  40.504 21.936 41.357 21.96 ;
     RECT  41.123 0.576 41.393 1.176 ;
     RECT  41.393 1.152 41.573 1.176 ;
     RECT  41.213 2.832 41.605 2.904 ;
     RECT  40.504 181.824 42.028 181.848 ;
     RECT  41.213 3.984 42.041 4.536 ;
     RECT  41.893 26.688 42.179 26.712 ;
     RECT  42.041 4.08 42.284 4.536 ;
     RECT  40.504 30 42.323 30.024 ;
     RECT  41.605 2.544 42.365 2.904 ;
     RECT  42.284 4.08 42.371 5.064 ;
     RECT  42.371 4.08 42.509 4.584 ;
     RECT  42.325 16.032 42.545 16.056 ;
     RECT  42.469 0.624 42.689 0.648 ;
     RECT  42.001 179.52 42.757 179.544 ;
     RECT  42.757 179.52 42.803 180.168 ;
     RECT  42.365 2.544 42.853 2.568 ;
     RECT  42.803 180 42.941 180.168 ;
     RECT  40.504 19.152 43.085 19.608 ;
     RECT  42.853 2.352 43.193 2.568 ;
     RECT  43.193 2.544 43.265 2.568 ;
     RECT  43.045 23.28 43.331 23.304 ;
     RECT  42.509 4.56 43.337 4.584 ;
     RECT  42.941 180 43.373 180.024 ;
     RECT  43.549 2.784 43.901 2.808 ;
     RECT  43.901 2.784 44.101 3 ;
     RECT  44.06 24.096 44.147 24.12 ;
     RECT  42.901 1.2 44.197 1.224 ;
     RECT  40.504 14.928 44.197 14.952 ;
     RECT  44.197 14.928 44.483 15.48 ;
     RECT  44.197 1.152 44.581 1.224 ;
     RECT  44.581 1.152 44.633 1.8 ;
     RECT  44.101 2.784 44.917 3.528 ;
     RECT  43.621 4.512 44.917 4.536 ;
     RECT  43.085 19.584 45.601 19.608 ;
     RECT  44.633 1.776 45.608 1.8 ;
     RECT  44.917 2.784 45.608 4.536 ;
     RECT  44.483 14.928 45.608 14.952 ;
     RECT  45.601 18.72 45.608 19.608 ;
     RECT  44.581 27.408 45.608 27.432 ;
     RECT  45.349 30.96 45.608 30.984 ;
     RECT  44.521 33.12 45.608 33.144 ;
     RECT  42.373 181.248 45.608 181.272 ;
     RECT  45.608 1.776 45.836 181.452 ;
     RECT  45.836 1.776 45.904 181.512 ;
     RECT  45.904 1.776 45.925 1.8 ;
     RECT  45.904 22.176 46.019 22.2 ;
     RECT  45.904 2.832 46.045 2.904 ;
     RECT  45.904 10.848 46.115 11.064 ;
     RECT  45.904 18.72 46.163 19.8 ;
     RECT  46.115 10.944 46.181 11.064 ;
     RECT  45.904 26.688 46.181 26.712 ;
     RECT  46.163 19.584 46.397 19.8 ;
     RECT  45.904 181.248 46.403 181.512 ;
     RECT  45.904 120.864 46.649 120.888 ;
     RECT  45.904 4.224 46.739 6.168 ;
     RECT  46.739 4.224 46.829 4.248 ;
     RECT  46.739 5.328 46.835 6.168 ;
     RECT  45.904 34.368 46.969 34.632 ;
     RECT  46.969 34.272 46.973 34.632 ;
     RECT  46.961 150.576 46.988 150.6 ;
     RECT  46.988 150.576 47.045 150.984 ;
     RECT  46.973 34.272 47.053 34.296 ;
     RECT  46.969 120.912 47.053 120.936 ;
     RECT  47.045 150.96 47.075 150.984 ;
     RECT  46.835 6.144 47.077 6.168 ;
     RECT  47.077 6.144 47.084 6.552 ;
     RECT  46.045 2.832 47.125 2.856 ;
     RECT  47.084 6.144 47.171 6.792 ;
     RECT  47.125 2.832 47.267 3.384 ;
     RECT  47.267 2.88 47.441 3.384 ;
     RECT  47.317 23.376 47.513 23.4 ;
     RECT  45.904 179.616 47.801 179.64 ;
     RECT  46.397 19.584 47.893 19.608 ;
     RECT  47.441 2.928 47.909 3.384 ;
     RECT  47.893 18.672 47.98 19.608 ;
     RECT  47.948 29.472 48.035 29.496 ;
     RECT  46.789 181.728 48.044 181.752 ;
     RECT  45.925 1.152 48.089 1.8 ;
     RECT  48.089 1.2 48.233 1.8 ;
     RECT  48.044 181.248 48.337 181.752 ;
     RECT  48.373 8.976 48.46 9.768 ;
     RECT  48.373 16.656 48.46 16.68 ;
     RECT  48.337 180.72 48.467 181.752 ;
     RECT  48.469 6.72 48.556 6.744 ;
     RECT  48.476 27.312 48.563 27.336 ;
     RECT  48.467 181.248 48.601 181.752 ;
     RECT  48.524 150.912 48.611 150.936 ;
     RECT  48.709 32.976 48.796 33 ;
     RECT  48.661 10.8 48.845 10.824 ;
     RECT  47.909 3.36 48.853 3.384 ;
     RECT  48.233 1.776 48.881 1.8 ;
     RECT  48.853 3.36 48.997 3.528 ;
     RECT  48.997 2.88 49.277 3.528 ;
     RECT  47.98 19.584 49.381 19.608 ;
     RECT  49.381 19.584 49.571 19.992 ;
     RECT  49.525 23.328 49.612 23.352 ;
     RECT  49.621 8.928 49.709 8.952 ;
     RECT  49.429 1.152 49.852 1.176 ;
     RECT  49.852 1.152 49.853 1.224 ;
     RECT  50.005 30.816 50.012 30.84 ;
     RECT  49.705 85.104 50.053 85.128 ;
     RECT  49.853 1.2 50.341 1.224 ;
     RECT  49.277 3.36 50.425 3.528 ;
     RECT  49.561 180 50.461 180.024 ;
     RECT  50.425 3.36 50.713 3.576 ;
     RECT  50.713 2.784 50.741 3.576 ;
     RECT  50.561 4.56 50.741 4.584 ;
     RECT  50.341 1.2 50.869 1.8 ;
     RECT  50.741 2.784 50.869 4.584 ;
     RECT  49.964 5.712 50.869 5.736 ;
     RECT  49.571 19.584 50.869 19.848 ;
     RECT  50.869 1.2 50.929 5.736 ;
     RECT  50.929 1.2 51.008 5.88 ;
     RECT  50.849 8.688 51.008 8.712 ;
     RECT  45.904 14.928 51.008 14.952 ;
     RECT  50.869 19.344 51.008 19.848 ;
     RECT  50.869 23.52 51.008 23.544 ;
     RECT  50.149 27.312 51.008 27.336 ;
     RECT  50.012 30.528 51.008 30.84 ;
     RECT  50.053 84.912 51.008 85.128 ;
     RECT  50.444 119.088 51.008 119.112 ;
     RECT  50.461 180 51.008 180.12 ;
     RECT  48.601 181.248 51.008 181.272 ;
     RECT  51.008 1.2 51.112 181.452 ;
     RECT  51.112 2.418 51.116 181.452 ;
     RECT  51.112 1.2 51.157 1.224 ;
     RECT  51.157 1.152 51.185 1.224 ;
     RECT  51.116 2.418 51.203 181.56 ;
     RECT  51.203 2.418 51.304 181.272 ;
     RECT  51.304 9.168 51.635 9.192 ;
     RECT  51.185 1.152 52.069 1.176 ;
     RECT  51.304 2.688 52.289 3.384 ;
     RECT  51.304 85.584 52.3 85.608 ;
     RECT  51.304 118.608 52.307 118.632 ;
     RECT  51.304 181.248 52.316 181.272 ;
     RECT  51.304 14.928 52.348 15.48 ;
     RECT  52.316 181.248 52.403 181.848 ;
     RECT  52.069 0.624 52.445 1.176 ;
     RECT  52.445 1.152 52.501 1.176 ;
     RECT  51.304 4.56 52.805 4.584 ;
     RECT  52.501 1.152 52.841 1.224 ;
     RECT  52.289 2.688 53.132 3.528 ;
     RECT  53.125 29.088 53.219 29.112 ;
     RECT  52.403 181.248 53.417 181.752 ;
     RECT  51.304 19.584 53.593 19.608 ;
     RECT  53.132 2.688 53.605 3.864 ;
     RECT  53.593 19.584 53.699 19.896 ;
     RECT  53.161 5.136 53.705 5.16 ;
     RECT  53.605 2.352 53.813 3.864 ;
     RECT  53.749 22.704 53.836 22.728 ;
     RECT  53.773 85.632 53.857 85.656 ;
     RECT  53.449 180.096 53.957 180.12 ;
     RECT  53.813 2.592 54.053 3.864 ;
     RECT  54.053 2.592 54.137 4.008 ;
     RECT  52.841 1.152 54.244 1.176 ;
     RECT  54.244 1.152 54.569 1.224 ;
     RECT  54.529 25.152 54.707 25.176 ;
     RECT  54.569 1.152 54.929 1.176 ;
     RECT  54.137 2.592 55.001 3.72 ;
     RECT  54.709 15.984 55.181 16.008 ;
     RECT  55.1 27.264 55.187 27.288 ;
     RECT  55.001 2.88 55.217 3.72 ;
     RECT  55.196 21.792 55.283 21.816 ;
     RECT  55.196 31.392 55.283 31.416 ;
     RECT  55.217 2.88 55.433 2.904 ;
     RECT  55.285 0.096 55.469 0.12 ;
     RECT  55.573 1.776 56.005 1.8 ;
     RECT  56.005 1.2 56.149 1.8 ;
     RECT  56.149 0.576 56.225 1.8 ;
     RECT  56.225 0.576 56.333 1.176 ;
     RECT  55.709 3.984 56.408 4.008 ;
     RECT  55.321 5.184 56.408 5.208 ;
     RECT  52.348 14.928 56.408 14.952 ;
     RECT  53.699 19.584 56.408 19.608 ;
     RECT  55.501 28.464 56.408 28.488 ;
     RECT  54.565 179.856 56.408 179.88 ;
     RECT  53.417 181.248 56.408 181.272 ;
     RECT  56.408 2.148 56.437 181.452 ;
     RECT  56.437 2.148 56.512 181.848 ;
     RECT  56.512 2.418 56.704 181.848 ;
     RECT  56.704 34.368 56.819 34.392 ;
     RECT  56.437 0.096 56.837 0.168 ;
     RECT  56.704 18.432 57.011 18.456 ;
     RECT  56.837 0.096 57.197 0.12 ;
     RECT  56.704 179.904 57.413 179.928 ;
     RECT  56.704 29.76 57.484 29.784 ;
     RECT  56.333 1.152 57.521 1.176 ;
     RECT  56.704 21.984 57.587 22.728 ;
     RECT  56.704 2.832 57.593 4.296 ;
     RECT  56.704 25.824 57.685 25.848 ;
     RECT  57.593 2.88 57.877 4.296 ;
     RECT  57.685 25.68 58.097 25.848 ;
     RECT  57.877 2.88 58.169 4.584 ;
     RECT  58.165 0.096 58.268 0.12 ;
     RECT  58.268 0.096 58.355 0.552 ;
     RECT  58.169 3.408 58.421 4.296 ;
     RECT  58.625 25.056 58.709 25.08 ;
     RECT  58.645 2.304 58.817 2.328 ;
     RECT  58.584 179.616 58.817 179.64 ;
     RECT  58.421 3.408 58.853 3.432 ;
     RECT  58.789 16.944 58.876 16.968 ;
     RECT  58.777 11.664 58.889 11.688 ;
     RECT  58.844 28.944 58.931 28.968 ;
     RECT  59.077 1.152 59.285 1.176 ;
     RECT  59.173 4.56 59.353 4.584 ;
     RECT  59.353 4.56 59.357 5.4 ;
     RECT  59.357 5.184 59.465 5.4 ;
     RECT  59.413 179.472 59.5 179.496 ;
     RECT  58.355 0.096 59.509 0.12 ;
     RECT  59.461 6.816 59.573 6.84 ;
     RECT  56.704 181.824 59.857 181.848 ;
     RECT  59.857 181.824 59.987 182.376 ;
     RECT  60.044 29.184 60.131 29.448 ;
     RECT  59.605 3.984 60.149 4.008 ;
     RECT  59.465 5.184 60.473 5.208 ;
     RECT  56.704 19.584 60.533 19.608 ;
     RECT  59.509 0.096 60.581 0.6 ;
     RECT  60.533 19.584 60.617 20.52 ;
     RECT  60.572 23.28 60.659 23.304 ;
     RECT  60.62 28.464 60.707 28.488 ;
     RECT  60.581 0.096 60.869 0.12 ;
     RECT  60.373 2.88 61.477 2.904 ;
     RECT  61.477 2.88 61.573 3.432 ;
     RECT  61.573 2.88 61.58 3.48 ;
     RECT  60.901 4.56 61.58 5.112 ;
     RECT  61.58 2.88 61.585 5.112 ;
     RECT  61.333 6.288 61.585 6.312 ;
     RECT  61.657 1.056 61.717 1.08 ;
     RECT  61.585 2.88 61.808 6.936 ;
     RECT  56.704 14.928 61.808 14.952 ;
     RECT  60.613 16.512 61.808 16.536 ;
     RECT  60.617 19.584 61.808 19.608 ;
     RECT  61.58 29.376 61.808 29.4 ;
     RECT  60.997 31.344 61.808 31.368 ;
     RECT  59.987 181.824 61.808 181.848 ;
     RECT  61.808 2.148 61.912 181.848 ;
     RECT  61.912 2.418 62.104 181.848 ;
     RECT  61.717 1.056 62.149 1.176 ;
     RECT  62.104 17.328 62.284 17.352 ;
     RECT  62.104 4.656 62.705 4.68 ;
     RECT  62.104 6.24 62.705 6.312 ;
     RECT  62.104 179.616 62.777 179.64 ;
     RECT  62.104 21.024 63.011 21.048 ;
     RECT  62.104 25.056 63.011 25.08 ;
     RECT  62.104 33.216 63.107 33.24 ;
     RECT  63.068 30.192 63.155 30.216 ;
     RECT  62.149 0.576 63.209 1.176 ;
     RECT  62.705 6.24 63.245 6.264 ;
     RECT  62.104 181.824 63.313 181.848 ;
     RECT  63.313 181.824 63.491 182.376 ;
     RECT  63.209 1.104 63.493 1.176 ;
     RECT  63.493 1.104 63.577 1.752 ;
     RECT  63.577 1.104 63.821 1.176 ;
     RECT  63.493 179.52 63.829 179.544 ;
     RECT  63.829 179.52 63.875 180.168 ;
     RECT  62.104 3.408 63.877 3.432 ;
     RECT  63.877 57.552 63.964 57.576 ;
     RECT  64.249 57.312 64.333 57.336 ;
     RECT  63.491 181.824 64.357 181.848 ;
     RECT  63.821 1.104 64.405 1.128 ;
     RECT  63.875 180.144 64.433 180.168 ;
     RECT  64.357 181.248 64.444 181.848 ;
     RECT  64.405 35.712 64.541 35.736 ;
     RECT  64.405 16.8 64.547 16.824 ;
     RECT  63.877 2.88 64.693 3.432 ;
     RECT  64.405 22.896 64.721 22.92 ;
     RECT  64.693 2.784 64.739 3.432 ;
     RECT  64.316 6.816 64.741 6.84 ;
     RECT  64.739 2.784 64.78 2.904 ;
     RECT  64.693 26.112 64.78 26.136 ;
     RECT  64.717 91.824 64.801 91.848 ;
     RECT  64.405 0.144 64.817 1.128 ;
     RECT  64.741 6.24 64.828 6.84 ;
     RECT  64.817 0.144 64.901 1.176 ;
     RECT  64.892 179.568 65.04 179.592 ;
     RECT  64.78 2.88 65.621 2.904 ;
     RECT  64.901 0.144 65.801 0.6 ;
     RECT  62.104 19.584 66.085 19.608 ;
     RECT  64.444 181.824 66.085 181.848 ;
     RECT  65.545 17.328 66.131 17.352 ;
     RECT  65.653 31.728 66.131 31.752 ;
     RECT  66.085 181.248 66.157 181.848 ;
     RECT  66.085 19.584 66.169 20.376 ;
     RECT  66.157 180.72 66.172 181.848 ;
     RECT  66.172 180.72 66.193 180.744 ;
     RECT  65.365 4.56 66.197 4.584 ;
     RECT  64.885 6.864 66.197 6.888 ;
     RECT  66.509 1.728 66.545 1.752 ;
     RECT  66.545 1.152 66.629 1.752 ;
     RECT  66.193 180.144 66.709 180.744 ;
     RECT  66.629 1.728 67.208 1.752 ;
     RECT  66.997 3.024 67.208 3.048 ;
     RECT  66.373 4.944 67.208 4.968 ;
     RECT  62.104 14.928 67.208 14.952 ;
     RECT  66.169 19.584 67.208 19.608 ;
     RECT  66.581 25.872 67.208 25.896 ;
     RECT  66.325 28.8 67.208 28.824 ;
     RECT  66.236 91.968 67.208 91.992 ;
     RECT  66.121 125.472 67.208 125.496 ;
     RECT  66.709 179.232 67.208 180.744 ;
     RECT  66.172 181.824 67.208 181.848 ;
     RECT  67.208 1.728 67.504 181.848 ;
     RECT  67.504 1.728 67.565 1.752 ;
     RECT  67.504 4.272 67.745 4.968 ;
     RECT  67.504 125.472 67.753 125.496 ;
     RECT  65.801 0.144 67.813 0.168 ;
     RECT  67.504 180.144 67.853 180.168 ;
     RECT  67.504 181.824 67.948 181.848 ;
     RECT  67.745 4.272 68.147 4.296 ;
     RECT  67.813 0.144 68.177 0.6 ;
     RECT  67.504 17.856 68.236 17.88 ;
     RECT  68.177 0.576 68.273 0.6 ;
     RECT  67.504 2.832 68.291 2.856 ;
     RECT  68.569 2.256 68.675 2.28 ;
     RECT  68.173 182.352 68.771 182.376 ;
     RECT  67.504 31.68 68.861 31.704 ;
     RECT  68.497 22.896 68.963 22.92 ;
     RECT  68.273 0.576 68.969 1.176 ;
     RECT  68.969 1.152 69.157 1.176 ;
     RECT  69.157 1.152 69.365 1.8 ;
     RECT  69.461 7.44 69.545 7.464 ;
     RECT  68.821 180 69.725 180.024 ;
     RECT  67.504 14.928 69.865 14.952 ;
     RECT  69.788 28.416 69.875 28.44 ;
     RECT  69.589 0.096 69.905 0.12 ;
     RECT  69.865 14.928 70.115 15.768 ;
     RECT  69.541 20.592 70.115 20.616 ;
     RECT  69.157 181.824 70.115 181.848 ;
     RECT  69.365 1.152 70.405 1.176 ;
     RECT  70.115 14.928 70.477 14.952 ;
     RECT  69.037 4.368 70.481 4.392 ;
     RECT  70.369 16.848 70.481 16.872 ;
     RECT  70.477 14.88 70.697 14.952 ;
     RECT  70.693 2.88 70.805 2.904 ;
     RECT  70.765 26.16 70.849 26.184 ;
     RECT  70.405 1.152 71.309 1.224 ;
     RECT  70.117 7.968 71.353 7.992 ;
     RECT  70.549 181.248 71.411 181.272 ;
     RECT  71.197 4.56 71.521 4.584 ;
     RECT  67.504 19.584 71.756 19.608 ;
     RECT  70.697 14.928 71.797 14.952 ;
     RECT  71.701 181.728 71.813 181.848 ;
     RECT  71.309 1.2 71.845 1.224 ;
     RECT  71.845 1.2 72.065 1.8 ;
     RECT  71.813 181.728 72.275 181.752 ;
     RECT  70.981 2.784 72.373 2.808 ;
     RECT  71.756 19.584 72.373 19.944 ;
     RECT  72.373 2.784 72.449 3 ;
     RECT  72.449 2.784 72.608 3.432 ;
     RECT  71.521 4.56 72.608 5.304 ;
     RECT  71.797 14.928 72.608 15.768 ;
     RECT  72.373 19.584 72.608 20.712 ;
     RECT  72.037 28.272 72.608 29.208 ;
     RECT  71.413 179.616 72.608 179.64 ;
     RECT  72.608 2.148 72.796 181.608 ;
     RECT  72.796 2.148 72.904 181.272 ;
     RECT  72.904 179.616 73.001 179.64 ;
     RECT  72.904 20.688 73.043 20.712 ;
     RECT  72.709 1.152 73.073 1.176 ;
     RECT  72.904 2.148 73.189 4.584 ;
     RECT  73.189 1.2 73.325 4.584 ;
     RECT  73.325 1.2 73.469 1.848 ;
     RECT  72.904 23.952 73.523 23.976 ;
     RECT  73.325 2.88 73.541 4.584 ;
     RECT  73.465 182.352 73.549 182.376 ;
     RECT  73.541 2.88 73.667 4.296 ;
     RECT  73.469 1.776 74.009 1.848 ;
     RECT  73.667 2.88 74.153 4.104 ;
     RECT  74.101 17.04 74.188 17.064 ;
     RECT  72.904 19.584 74.204 19.608 ;
     RECT  74.204 19.584 74.291 20.472 ;
     RECT  74.009 1.776 74.437 1.8 ;
     RECT  72.904 181.248 74.437 181.272 ;
     RECT  74.437 181.248 74.521 181.752 ;
     RECT  74.153 3.36 74.549 4.104 ;
     RECT  74.533 28.992 74.62 29.016 ;
     RECT  74.257 25.488 74.675 25.512 ;
     RECT  74.437 1.152 74.693 1.8 ;
     RECT  74.725 0.096 74.809 0.12 ;
     RECT  74.732 179.856 74.819 179.88 ;
     RECT  74.549 3.648 74.861 4.104 ;
     RECT  74.617 11.472 74.873 11.496 ;
     RECT  74.861 3.648 75.149 4.296 ;
     RECT  74.291 19.584 75.253 19.608 ;
     RECT  75.253 18.816 75.449 19.608 ;
     RECT  74.693 1.776 75.541 1.8 ;
     RECT  75.541 1.776 75.773 2.376 ;
     RECT  75.149 3.648 75.829 4.584 ;
     RECT  75.829 2.832 75.875 4.584 ;
     RECT  75.829 22.752 76.025 22.776 ;
     RECT  75.98 32.4 76.067 32.424 ;
     RECT  76.117 27.888 76.205 27.912 ;
     RECT  75.875 2.832 76.313 3.528 ;
     RECT  76.021 15.936 76.403 15.96 ;
     RECT  76.261 1.152 76.529 1.752 ;
     RECT  76.529 1.728 76.673 1.752 ;
     RECT  75.875 4.56 76.877 4.584 ;
     RECT  76.877 3.792 76.961 4.584 ;
     RECT  76.961 4.08 77.101 4.584 ;
     RECT  77.077 1.776 77.465 1.8 ;
     RECT  77.461 182.352 77.545 182.376 ;
     RECT  77.701 2.148 77.893 2.376 ;
     RECT  74.521 181.248 77.941 181.272 ;
     RECT  76.693 0.624 77.989 0.648 ;
     RECT  77.893 2.148 78.008 2.904 ;
     RECT  77.101 4.08 78.008 5.112 ;
     RECT  72.904 14.928 78.008 14.952 ;
     RECT  75.449 19.584 78.008 19.608 ;
     RECT  77.677 21.696 78.008 21.72 ;
     RECT  77.125 33.264 78.008 33.288 ;
     RECT  77.941 181.248 78.008 181.608 ;
     RECT  77.989 0.624 78.181 1.176 ;
     RECT  78.008 2.148 78.304 181.608 ;
     RECT  78.181 0.576 78.365 1.176 ;
     RECT  78.304 7.056 78.419 7.08 ;
     RECT  78.304 17.088 78.419 17.112 ;
     RECT  78.304 8.352 78.445 8.52 ;
     RECT  78.304 181.248 78.508 181.608 ;
     RECT  78.304 4.8 78.563 5.112 ;
     RECT  78.304 2.784 78.659 3.528 ;
     RECT  78.304 27.6 78.659 27.624 ;
     RECT  78.445 8.496 78.748 8.52 ;
     RECT  78.304 24.768 78.941 24.792 ;
     RECT  78.659 2.784 78.995 3.336 ;
     RECT  78.365 1.152 78.997 1.176 ;
     RECT  78.997 1.152 79.229 1.8 ;
     RECT  78.304 31.872 79.235 31.896 ;
     RECT  78.757 181.728 79.337 181.752 ;
     RECT  78.563 4.8 79.429 4.824 ;
     RECT  78.304 19.584 79.813 19.608 ;
     RECT  79.429 4.56 79.877 4.824 ;
     RECT  79.813 19.584 80.233 19.8 ;
     RECT  80.245 87.84 80.269 87.864 ;
     RECT  79.229 1.152 80.273 1.272 ;
     RECT  80.197 26.16 80.309 26.184 ;
     RECT  79.877 4.56 80.341 4.632 ;
     RECT  80.341 4.512 80.345 4.632 ;
     RECT  80.269 87.792 80.387 87.864 ;
     RECT  78.995 2.784 80.389 2.808 ;
     RECT  80.273 1.2 80.581 1.272 ;
     RECT  80.387 87.84 80.597 87.864 ;
     RECT  80.389 2.784 80.669 2.904 ;
     RECT  80.345 4.512 80.693 4.536 ;
     RECT  80.737 30.048 80.773 30.072 ;
     RECT  80.693 3.984 80.777 4.536 ;
     RECT  80.233 19.584 80.849 20.136 ;
     RECT  80.629 6.768 80.921 6.792 ;
     RECT  80.773 29.712 80.963 30.744 ;
     RECT  80.963 29.712 81.101 30.072 ;
     RECT  81.157 3.504 81.281 3.528 ;
     RECT  81.308 34.032 81.395 34.056 ;
     RECT  80.581 1.2 81.445 1.8 ;
     RECT  80.989 17.04 81.491 17.064 ;
     RECT  81.205 22.896 81.491 22.92 ;
     RECT  81.637 28.656 81.724 28.68 ;
     RECT  81.685 34.656 81.772 34.68 ;
     RECT  81.781 22.512 81.893 22.536 ;
     RECT  80.777 4.512 81.989 4.536 ;
     RECT  81.445 1.152 82.069 1.8 ;
     RECT  81.989 4.512 82.073 4.68 ;
     RECT  81.74 10.56 82.249 10.584 ;
     RECT  82.172 121.056 82.259 121.08 ;
     RECT  82.249 10.56 82.361 11.16 ;
     RECT  82.361 10.56 82.645 10.872 ;
     RECT  82.429 179.664 83.077 179.688 ;
     RECT  82.069 1.152 83.113 2.664 ;
     RECT  83.077 179.664 83.249 180.024 ;
     RECT  83.113 1.152 83.257 2.904 ;
     RECT  82.421 3.984 83.257 4.008 ;
     RECT  83.257 1.152 83.405 4.008 ;
     RECT  83.405 2.148 83.408 4.008 ;
     RECT  82.645 9.936 83.408 10.872 ;
     RECT  78.304 14.928 83.408 14.952 ;
     RECT  83.228 17.616 83.408 17.64 ;
     RECT  80.849 19.584 83.408 19.608 ;
     RECT  82.453 20.736 83.408 20.76 ;
     RECT  83.228 23.712 83.408 23.736 ;
     RECT  81.101 30.048 83.408 30.072 ;
     RECT  82.549 32.16 83.408 32.184 ;
     RECT  83.113 34.272 83.408 34.872 ;
     RECT  83.269 87.168 83.408 87.192 ;
     RECT  83.257 120.864 83.408 120.888 ;
     RECT  83.249 179.616 83.408 180.024 ;
     RECT  79.724 181.248 83.408 181.272 ;
     RECT  83.408 2.148 83.512 181.452 ;
     RECT  83.405 1.152 83.545 1.176 ;
     RECT  83.512 2.418 83.612 181.452 ;
     RECT  83.612 2.418 83.699 181.512 ;
     RECT  83.699 2.418 83.704 181.272 ;
     RECT  83.704 180 83.837 180.024 ;
     RECT  83.704 2.88 83.945 3.432 ;
     RECT  83.704 16.224 83.981 16.248 ;
     RECT  83.704 181.248 84.035 181.272 ;
     RECT  83.704 6.24 84.131 6.264 ;
     RECT  83.545 0.528 84.133 1.176 ;
     RECT  84.133 0.096 84.275 1.176 ;
     RECT  83.704 26.256 84.323 26.28 ;
     RECT  83.704 10.32 84.419 10.344 ;
     RECT  84.481 182.352 84.611 182.376 ;
     RECT  84.733 152.208 84.947 152.232 ;
     RECT  84.949 86.688 85.033 86.712 ;
     RECT  84.997 181.824 85.097 181.848 ;
     RECT  83.945 3.408 85.129 3.432 ;
     RECT  85.052 152.496 85.139 152.52 ;
     RECT  84.275 0.144 85.349 1.176 ;
     RECT  85.237 21.216 85.523 21.24 ;
     RECT  85.429 181.248 85.529 181.272 ;
     RECT  85.477 24.336 85.564 24.36 ;
     RECT  85.733 30.72 85.817 30.744 ;
     RECT  85.777 182.352 85.907 182.376 ;
     RECT  85.349 1.152 86.033 1.176 ;
     RECT  85.129 3.408 86.101 4.152 ;
     RECT  85.349 0.144 86.341 0.168 ;
     RECT  85.957 180.096 86.348 180.12 ;
     RECT  86.348 179.232 86.435 180.12 ;
     RECT  86.641 16.944 86.725 16.968 ;
     RECT  86.677 121.44 86.761 121.464 ;
     RECT  86.101 3.264 86.821 4.152 ;
     RECT  86.435 180.096 86.825 180.12 ;
     RECT  86.821 3.264 86.969 5.112 ;
     RECT  87.001 121.968 87.085 121.992 ;
     RECT  83.704 19.584 87.212 19.608 ;
     RECT  86.341 0.144 87.221 0.6 ;
     RECT  87.212 19.584 87.299 19.944 ;
     RECT  87.452 27.264 87.539 27.288 ;
     RECT  87.221 0.192 87.617 0.6 ;
     RECT  87.617 0.576 87.637 0.6 ;
     RECT  87.637 0.576 87.761 1.176 ;
     RECT  86.969 3.984 87.833 5.112 ;
     RECT  87.833 3.984 88.021 4.008 ;
     RECT  87.781 24.576 88.153 24.888 ;
     RECT  87.781 30.864 88.297 30.888 ;
     RECT  87.761 0.576 88.693 0.6 ;
     RECT  88.501 2.304 88.765 2.328 ;
     RECT  88.021 3.408 88.765 4.008 ;
     RECT  88.765 2.304 88.808 4.008 ;
     RECT  87.833 5.088 88.808 5.112 ;
     RECT  83.704 14.928 88.808 14.952 ;
     RECT  87.299 19.584 88.808 19.608 ;
     RECT  88.153 24.576 88.808 25.608 ;
     RECT  88.297 30.816 88.808 30.888 ;
     RECT  88.297 180.144 88.808 180.168 ;
     RECT  86.293 181.824 88.808 181.848 ;
     RECT  88.808 2.148 88.912 181.848 ;
     RECT  88.693 0.24 88.933 0.6 ;
     RECT  88.912 2.304 88.949 181.848 ;
     RECT  88.949 2.4 89.104 181.848 ;
     RECT  89.104 29.376 89.219 29.688 ;
     RECT  88.933 0.144 89.237 0.6 ;
     RECT  89.237 0.576 89.365 0.6 ;
     RECT  89.365 0.576 89.489 1.176 ;
     RECT  89.104 2.4 89.489 3.048 ;
     RECT  89.489 2.4 89.597 2.424 ;
     RECT  89.104 4.08 89.705 4.584 ;
     RECT  89.489 0.576 89.885 0.696 ;
     RECT  89.219 29.376 89.98 29.4 ;
     RECT  89.104 18.144 90.101 18.168 ;
     RECT  89.885 0.576 90.277 0.6 ;
     RECT  90.277 0.096 90.533 0.6 ;
     RECT  90.421 15.984 90.611 16.008 ;
     RECT  90.205 5.712 90.659 5.736 ;
     RECT  90.613 21.216 90.7 21.24 ;
     RECT  90.533 0.576 90.893 0.6 ;
     RECT  89.705 4.08 91.045 4.44 ;
     RECT  90.709 2.304 91.105 2.328 ;
     RECT  91.045 3.408 91.105 4.44 ;
     RECT  90.613 26.304 91.181 26.328 ;
     RECT  91.105 2.304 91.253 4.44 ;
     RECT  91.253 4.08 91.477 4.44 ;
     RECT  91.189 178.56 91.577 178.584 ;
     RECT  91.477 4.08 91.829 5.016 ;
     RECT  91.253 2.304 91.901 2.664 ;
     RECT  91.133 1.152 91.909 1.176 ;
     RECT  89.104 181.824 91.933 181.848 ;
     RECT  91.829 4.08 92.009 4.824 ;
     RECT  92.009 4.8 92.051 4.824 ;
     RECT  91.901 2.304 92.081 2.328 ;
     RECT  91.897 31.632 92.339 31.656 ;
     RECT  91.909 0.576 92.341 1.176 ;
     RECT  92.341 0.576 92.549 1.752 ;
     RECT  92.54 18.096 92.627 18.12 ;
     RECT  91.933 181.824 92.797 182.376 ;
     RECT  92.329 23.376 92.915 23.4 ;
     RECT  92.797 181.824 92.963 182.424 ;
     RECT  92.773 3.408 92.977 3.432 ;
     RECT  93.116 29.232 93.203 29.256 ;
     RECT  92.977 3.408 93.205 3.768 ;
     RECT  92.917 5.136 93.205 5.16 ;
     RECT  93.205 3.408 93.349 5.16 ;
     RECT  89.104 19.584 93.404 19.608 ;
     RECT  92.549 0.576 93.596 1.176 ;
     RECT  91.645 179.184 93.877 179.208 ;
     RECT  93.913 8.688 94.069 8.712 ;
     RECT  93.349 2.88 94.208 5.16 ;
     RECT  94.069 8.688 94.208 8.904 ;
     RECT  89.104 14.928 94.208 14.952 ;
     RECT  94.069 16.56 94.208 16.584 ;
     RECT  93.404 19.584 94.208 20.472 ;
     RECT  94.069 29.04 94.208 29.064 ;
     RECT  93.829 31.632 94.208 31.656 ;
     RECT  94.069 149.376 94.208 149.4 ;
     RECT  93.877 179.184 94.208 180.168 ;
     RECT  92.963 181.824 94.208 181.848 ;
     RECT  93.596 0.528 94.213 1.176 ;
     RECT  94.208 2.148 94.312 181.848 ;
     RECT  94.312 2.256 94.504 181.848 ;
     RECT  94.504 179.184 94.637 180.168 ;
     RECT  94.504 149.76 94.643 149.784 ;
     RECT  94.213 0.144 94.645 1.176 ;
     RECT  94.645 0.096 94.684 1.176 ;
     RECT  94.504 2.256 94.709 3.432 ;
     RECT  94.504 6.144 94.828 6.168 ;
     RECT  94.504 23.28 94.889 23.304 ;
     RECT  94.504 4.56 95.249 4.584 ;
     RECT  94.504 19.584 95.641 19.608 ;
     RECT  94.637 180.144 95.645 180.168 ;
     RECT  95.641 19.344 95.747 19.608 ;
     RECT  94.684 0.096 95.797 0.6 ;
     RECT  95.797 0.096 96.041 1.176 ;
     RECT  94.504 181.824 96.077 181.848 ;
     RECT  95.996 6.432 96.083 6.456 ;
     RECT  94.709 2.88 96.229 3.432 ;
     RECT  96.229 2.88 96.284 3.48 ;
     RECT  96.041 0.096 96.293 0.6 ;
     RECT  96.289 182.4 96.467 182.424 ;
     RECT  96.293 0.096 96.617 0.12 ;
     RECT  96.284 2.688 96.661 3.48 ;
     RECT  96.793 26.688 96.899 26.712 ;
     RECT  96.469 32.448 96.899 32.472 ;
     RECT  94.504 14.928 96.901 14.952 ;
     RECT  96.853 181.248 96.941 181.272 ;
     RECT  96.901 21.168 96.995 21.192 ;
     RECT  96.956 4.848 97.043 4.872 ;
     RECT  96.661 2.688 97.285 3.528 ;
     RECT  97.189 29.52 97.333 29.544 ;
     RECT  96.901 14.928 97.373 15.432 ;
     RECT  97.285 2.304 97.445 3.528 ;
     RECT  97.333 10.512 97.475 10.536 ;
     RECT  97.081 16.512 97.475 16.536 ;
     RECT  97.333 29.232 97.475 29.544 ;
     RECT  97.445 3.36 97.481 3.528 ;
     RECT  97.481 3.504 97.573 3.528 ;
     RECT  97.475 29.52 97.625 29.544 ;
     RECT  97.445 2.304 97.877 2.328 ;
     RECT  98.053 9.744 98.14 10.248 ;
     RECT  97.285 181.824 98.237 181.848 ;
     RECT  97.573 3.504 98.453 4.104 ;
     RECT  97.717 0.096 98.525 0.12 ;
     RECT  97.405 180.096 98.597 180.12 ;
     RECT  95.747 19.584 98.629 19.608 ;
     RECT  98.453 3.552 98.701 4.104 ;
     RECT  98.629 181.728 98.713 181.752 ;
     RECT  98.629 30.144 98.773 30.168 ;
     RECT  97.373 14.928 98.837 14.952 ;
     RECT  98.629 0.624 98.921 0.648 ;
     RECT  98.821 1.776 99.205 1.8 ;
     RECT  98.701 3.552 99.485 4.536 ;
     RECT  99.205 1.776 99.608 2.328 ;
     RECT  99.485 3.552 99.608 5.064 ;
     RECT  98.14 10.224 99.608 10.248 ;
     RECT  98.837 14.928 99.608 15.48 ;
     RECT  98.845 16.992 99.608 17.016 ;
     RECT  98.629 18.672 99.608 19.608 ;
     RECT  98.701 23.952 99.608 23.976 ;
     RECT  98.593 26.736 99.608 26.76 ;
     RECT  98.773 29.664 99.608 30.168 ;
     RECT  98.876 32.688 99.608 32.712 ;
     RECT  99.061 181.248 99.608 181.608 ;
     RECT  99.608 1.776 99.817 181.608 ;
     RECT  99.817 1.776 99.904 181.752 ;
     RECT  99.904 181.248 99.923 181.752 ;
     RECT  99.904 29.856 100.181 30.168 ;
     RECT  99.904 16.656 100.204 17.016 ;
     RECT  100.181 29.856 100.307 29.88 ;
     RECT  99.904 4.512 100.325 4.584 ;
     RECT  99.904 1.776 100.357 3.24 ;
     RECT  100.204 16.992 100.396 17.016 ;
     RECT  99.904 21.792 100.397 21.816 ;
     RECT  99.904 179.328 100.451 180.072 ;
     RECT  100.357 1.2 100.837 3.24 ;
     RECT  100.451 180.048 100.901 180.072 ;
     RECT  100.837 1.152 101.045 3.24 ;
     RECT  100.325 4.512 101.329 4.536 ;
     RECT  101.329 4.272 101.393 4.536 ;
     RECT  101.393 4.272 101.477 4.584 ;
     RECT  100.885 26.688 101.477 26.712 ;
     RECT  99.923 181.248 101.653 181.272 ;
     RECT  101.045 1.776 101.845 3.24 ;
     RECT  101.477 4.272 101.845 4.296 ;
     RECT  101.845 1.776 102.161 4.296 ;
     RECT  102.161 1.776 102.181 4.008 ;
     RECT  102.181 1.2 102.413 4.008 ;
     RECT  102.332 31.872 102.419 31.896 ;
     RECT  102.481 179.232 102.659 179.256 ;
     RECT  101.653 180.384 102.72 181.272 ;
     RECT  102.413 1.776 102.845 4.008 ;
     RECT  102.901 29.376 102.988 29.4 ;
     RECT  102.613 22.176 102.995 22.2 ;
     RECT  102.845 3.984 103.169 4.008 ;
     RECT  103.148 16.656 103.235 16.68 ;
     RECT  99.904 19.584 103.381 19.608 ;
     RECT  103.381 19.584 103.468 19.944 ;
     RECT  103.273 25.92 103.763 25.944 ;
     RECT  102.845 1.776 103.817 2.904 ;
     RECT  103.817 1.776 104.609 2.712 ;
     RECT  104.78 22.464 104.785 22.488 ;
     RECT  104.381 4.56 104.821 4.584 ;
     RECT  104.609 2.148 104.869 2.712 ;
     RECT  104.869 2.148 105.008 2.904 ;
     RECT  104.821 4.08 105.008 4.584 ;
     RECT  99.904 14.928 105.008 14.952 ;
     RECT  104.869 16.8 105.008 16.824 ;
     RECT  103.468 19.584 105.008 19.608 ;
     RECT  104.785 22.176 105.008 22.488 ;
     RECT  104.293 32.736 105.008 32.76 ;
     RECT  103.741 179.712 105.008 179.736 ;
     RECT  102.72 181.248 105.008 181.272 ;
     RECT  105.008 2.148 105.145 181.452 ;
     RECT  105.145 2.148 105.251 181.752 ;
     RECT  105.251 2.148 105.304 181.272 ;
     RECT  105.304 29.664 105.481 29.688 ;
     RECT  105.304 10.848 105.725 10.872 ;
     RECT  105.304 179.712 106.229 179.736 ;
     RECT  105.304 27.312 106.3 27.336 ;
     RECT  106.268 22.176 106.355 22.2 ;
     RECT  105.304 2.88 106.477 4.92 ;
     RECT  106.477 2.832 106.697 4.92 ;
     RECT  106.697 2.832 106.841 2.904 ;
     RECT  105.304 181.248 106.901 181.272 ;
     RECT  105.304 19.584 106.933 19.608 ;
     RECT  106.901 181.248 106.985 181.752 ;
     RECT  106.933 19.584 107.02 20.472 ;
     RECT  105.733 1.776 107.093 1.8 ;
     RECT  106.697 3.984 107.093 4.92 ;
     RECT  106.597 24.048 107.093 24.072 ;
     RECT  107.228 30.48 107.315 30.504 ;
     RECT  107.093 3.984 107.489 4.008 ;
     RECT  107.173 21.648 107.561 21.672 ;
     RECT  106.985 181.248 108.236 181.272 ;
     RECT  108.188 17.04 108.275 17.064 ;
     RECT  106.841 2.832 108.277 2.856 ;
     RECT  107.461 1.152 108.313 1.224 ;
     RECT  108.236 181.248 108.323 181.848 ;
     RECT  108.313 0.336 108.373 1.224 ;
     RECT  108.373 0.336 108.397 1.8 ;
     RECT  108.277 26.496 108.425 26.664 ;
     RECT  108.425 26.496 108.533 26.52 ;
     RECT  108.397 1.152 108.569 1.8 ;
     RECT  108.277 2.832 108.701 2.904 ;
     RECT  108.457 32.928 108.851 32.952 ;
     RECT  108.805 26.448 108.892 26.472 ;
     RECT  108.323 181.248 109.1 181.272 ;
     RECT  109.1 180.384 109.187 181.272 ;
     RECT  108.701 2.832 109.217 3.528 ;
     RECT  109.217 2.832 109.325 2.856 ;
     RECT  109.244 16.992 109.331 17.016 ;
     RECT  108.569 1.152 109.669 1.176 ;
     RECT  109.187 181.248 110.3 181.272 ;
     RECT  109.669 1.152 110.333 1.224 ;
     RECT  110.3 181.248 110.387 181.608 ;
     RECT  109.573 2.352 110.408 2.376 ;
     RECT  109.429 3.936 110.408 3.96 ;
     RECT  109.957 6.48 110.408 7.272 ;
     RECT  105.304 14.928 110.408 14.952 ;
     RECT  110.329 16.608 110.408 16.824 ;
     RECT  107.02 19.584 110.408 19.608 ;
     RECT  109.381 29.952 110.408 29.976 ;
     RECT  110.245 32.88 110.408 32.904 ;
     RECT  110.387 181.248 110.408 181.452 ;
     RECT  110.408 2.148 110.512 181.452 ;
     RECT  110.512 2.418 110.704 181.272 ;
     RECT  110.333 1.152 110.869 1.176 ;
     RECT  110.704 2.88 110.945 2.904 ;
     RECT  110.704 25.008 111.155 25.032 ;
     RECT  110.704 4.128 111.161 4.152 ;
     RECT  110.869 0.576 111.26 1.176 ;
     RECT  111.26 0.528 111.397 1.176 ;
     RECT  110.704 22.32 111.457 22.344 ;
     RECT  110.704 32.4 111.491 32.424 ;
     RECT  110.704 19.584 111.532 19.944 ;
     RECT  111.397 0.528 111.593 1.224 ;
     RECT  110.704 30.528 111.628 30.552 ;
     RECT  110.704 26.832 111.676 26.856 ;
     RECT  110.704 16.8 111.731 16.824 ;
     RECT  110.704 181.248 111.761 181.272 ;
     RECT  111.761 181.248 112.115 181.752 ;
     RECT  111.829 1.776 112.277 1.8 ;
     RECT  111.805 5.136 112.313 5.16 ;
     RECT  112.309 2.88 112.597 2.904 ;
     RECT  111.593 0.528 112.645 0.6 ;
     RECT  112.129 17.088 112.673 17.112 ;
     RECT  112.597 2.784 112.681 3.432 ;
     RECT  110.704 179.328 112.745 179.352 ;
     RECT  112.645 0.528 112.981 1.176 ;
     RECT  112.837 6.768 113.18 6.792 ;
     RECT  113.18 6.768 113.249 7.08 ;
     RECT  113.249 7.056 113.267 7.08 ;
     RECT  112.981 0.096 113.357 1.176 ;
     RECT  113.381 32.352 113.465 32.376 ;
     RECT  113.701 29.232 113.789 29.256 ;
     RECT  112.645 181.824 113.893 181.848 ;
     RECT  113.357 0.576 113.969 1.176 ;
     RECT  113.276 4.368 113.989 4.392 ;
     RECT  113.893 181.824 114.035 182.424 ;
     RECT  113.989 4.272 114.076 4.392 ;
     RECT  114.38 17.952 114.467 17.976 ;
     RECT  113.969 0.576 114.509 0.6 ;
     RECT  114.181 23.856 114.563 23.88 ;
     RECT  114.277 4.56 114.617 4.584 ;
     RECT  114.565 6.768 114.653 6.792 ;
     RECT  114.505 32.016 114.833 32.04 ;
     RECT  114.421 2.304 114.853 2.328 ;
     RECT  114.853 2.304 115.573 2.904 ;
     RECT  114.709 0.096 115.769 0.168 ;
     RECT  115.573 2.304 115.808 3.432 ;
     RECT  110.704 14.928 115.808 14.952 ;
     RECT  115.669 16.848 115.808 16.872 ;
     RECT  111.532 19.584 115.808 19.608 ;
     RECT  115.669 26.16 115.808 26.184 ;
     RECT  115.153 28.56 115.808 28.584 ;
     RECT  114.035 181.824 115.808 181.848 ;
     RECT  115.808 2.148 116.104 181.848 ;
     RECT  116.005 0.576 116.189 0.6 ;
     RECT  116.104 4.8 116.201 6.12 ;
     RECT  116.104 19.584 116.243 20.184 ;
     RECT  116.104 2.736 116.453 2.904 ;
     RECT  116.189 0.576 116.633 1.176 ;
     RECT  116.201 4.8 116.723 5.16 ;
     RECT  116.723 4.8 116.741 4.824 ;
     RECT  116.104 31.344 116.867 31.368 ;
     RECT  116.633 1.152 116.869 1.176 ;
     RECT  116.453 2.88 116.885 2.904 ;
     RECT  116.104 22.416 116.915 22.44 ;
     RECT  116.104 181.824 116.989 181.848 ;
     RECT  116.989 181.824 117.107 182.376 ;
     RECT  116.869 1.152 117.209 1.752 ;
     RECT  116.104 14.928 117.461 14.952 ;
     RECT  116.104 179.52 117.644 179.544 ;
     RECT  117.644 178.8 117.713 179.544 ;
     RECT  117.713 178.8 117.731 178.824 ;
     RECT  117.269 0.096 117.733 0.12 ;
     RECT  117.209 1.152 117.733 1.176 ;
     RECT  117.709 10.8 117.821 10.824 ;
     RECT  117.733 0.096 117.857 1.176 ;
     RECT  117.925 27.36 118.009 27.384 ;
     RECT  117.925 35.712 118.009 35.736 ;
     RECT  118.124 17.52 118.211 17.544 ;
     RECT  117.857 0.096 118.217 0.12 ;
     RECT  118.261 32.976 118.348 33 ;
     RECT  118.309 35.136 118.396 35.16 ;
     RECT  117.565 4.56 118.429 4.584 ;
     RECT  118.429 3.936 118.547 4.584 ;
     RECT  118.547 4.56 118.609 4.584 ;
     RECT  118.357 2.88 118.649 2.904 ;
     RECT  116.243 19.584 118.685 19.608 ;
     RECT  118.673 30.192 118.757 30.216 ;
     RECT  118.933 22.896 118.94 22.92 ;
     RECT  118.892 19.824 118.979 19.848 ;
     RECT  118.94 22.896 119.017 23.208 ;
     RECT  119.017 23.184 119.027 23.208 ;
     RECT  117.857 1.152 119.081 1.176 ;
     RECT  117.107 181.824 119.149 181.848 ;
     RECT  118.609 4.56 119.153 5.16 ;
     RECT  118.825 27.888 119.189 27.912 ;
     RECT  119.269 0.576 119.477 0.6 ;
     RECT  119.461 6.288 119.549 6.312 ;
     RECT  119.153 5.136 119.729 5.16 ;
     RECT  119.756 27.312 119.843 27.336 ;
     RECT  119.701 0.096 119.939 0.552 ;
     RECT  119.029 3.408 119.977 3.432 ;
     RECT  119.939 0.096 120.053 0.12 ;
     RECT  120.325 1.728 120.485 1.752 ;
     RECT  119.977 2.832 120.565 3.432 ;
     RECT  120.565 2.148 121.045 3.432 ;
     RECT  120.757 5.088 121.045 5.112 ;
     RECT  120.997 0.576 121.093 0.6 ;
     RECT  121.045 2.148 121.208 5.112 ;
     RECT  120.62 22.704 121.208 22.728 ;
     RECT  120.908 32.448 121.208 32.472 ;
     RECT  119.653 179.568 121.208 179.592 ;
     RECT  119.149 181.824 121.208 182.376 ;
     RECT  121.208 2.148 121.312 182.376 ;
     RECT  121.312 2.418 121.501 182.376 ;
     RECT  121.501 2.418 121.504 181.848 ;
     RECT  121.093 0.096 121.621 0.6 ;
     RECT  121.504 34.272 121.66 34.296 ;
     RECT  121.504 180.432 121.715 181.848 ;
     RECT  121.621 0.096 121.925 1.176 ;
     RECT  121.504 29.664 122.357 30.456 ;
     RECT  121.925 0.096 122.393 0.6 ;
     RECT  121.504 4.656 122.485 5.064 ;
     RECT  122.485 4.56 122.497 5.064 ;
     RECT  122.357 30.432 122.537 30.456 ;
     RECT  121.504 11.424 122.573 11.448 ;
     RECT  121.504 2.832 122.581 2.904 ;
     RECT  122.497 4.512 122.581 5.064 ;
     RECT  122.569 27.84 122.653 27.864 ;
     RECT  122.581 2.256 122.681 3.096 ;
     RECT  122.732 25.008 122.819 25.032 ;
     RECT  122.581 4.08 123.001 5.064 ;
     RECT  122.681 2.64 123.037 3.096 ;
     RECT  123.001 4.08 123.037 5.112 ;
     RECT  121.715 181.824 123.109 181.848 ;
     RECT  121.715 180.432 123.113 180.456 ;
     RECT  123.109 181.824 123.251 182.184 ;
     RECT  123.356 22.752 123.443 22.776 ;
     RECT  122.393 0.576 123.473 0.6 ;
     RECT  123.251 181.824 123.637 181.848 ;
     RECT  123.037 2.64 123.683 5.112 ;
     RECT  123.637 180.816 123.725 181.848 ;
     RECT  123.685 178.8 124.085 178.824 ;
     RECT  123.683 2.64 124.121 2.904 ;
     RECT  123.683 3.936 124.265 5.112 ;
     RECT  123.725 180.816 124.265 180.84 ;
     RECT  124.261 10.8 124.445 10.824 ;
     RECT  123.725 181.824 124.549 181.848 ;
     RECT  124.069 0.096 124.577 0.12 ;
     RECT  123.781 1.152 124.577 1.176 ;
     RECT  124.508 32.784 124.595 32.808 ;
     RECT  124.549 181.824 124.633 182.376 ;
     RECT  124.577 0.096 124.805 1.176 ;
     RECT  123.541 30.288 124.841 30.312 ;
     RECT  124.121 2.64 125.017 2.856 ;
     RECT  124.805 0.096 125.129 0.6 ;
     RECT  124.265 3.936 125.165 3.96 ;
     RECT  124.837 35.712 125.381 35.736 ;
     RECT  125.017 2.352 125.413 2.856 ;
     RECT  124.801 180.096 125.489 180.12 ;
     RECT  125.509 25.008 125.521 25.032 ;
     RECT  125.413 27.84 125.557 27.864 ;
     RECT  125.521 25.008 125.597 25.176 ;
     RECT  124.909 5.472 125.845 5.496 ;
     RECT  124.633 181.824 125.845 181.944 ;
     RECT  125.129 0.576 125.885 0.6 ;
     RECT  125.845 5.136 126.061 5.496 ;
     RECT  125.413 1.776 126.277 2.856 ;
     RECT  126.277 1.152 126.421 2.856 ;
     RECT  125.845 181.824 126.421 182.376 ;
     RECT  126.421 1.152 126.497 3.432 ;
     RECT  126.421 181.824 126.529 182.472 ;
     RECT  126.529 181.248 126.563 182.472 ;
     RECT  126.497 1.728 126.608 3.432 ;
     RECT  126.061 4.512 126.608 5.496 ;
     RECT  125.413 22.752 126.608 22.776 ;
     RECT  125.597 25.152 126.608 25.176 ;
     RECT  125.557 27.84 126.608 27.912 ;
     RECT  125.413 30.336 126.608 30.36 ;
     RECT  125.605 35.808 126.608 35.832 ;
     RECT  125.989 66.144 126.608 66.168 ;
     RECT  126.469 107.232 126.608 107.256 ;
     RECT  126.563 181.248 126.608 181.752 ;
     RECT  126.608 1.728 126.904 181.752 ;
     RECT  126.904 3.408 127.043 3.672 ;
     RECT  126.904 4.656 127.043 4.68 ;
     RECT  126.904 181.248 127.043 181.752 ;
     RECT  126.904 5.712 127.081 5.736 ;
     RECT  126.904 1.728 127.091 2.28 ;
     RECT  127.043 181.728 127.091 181.752 ;
     RECT  127.091 1.728 127.106 1.944 ;
     RECT  127.043 3.648 127.109 3.672 ;
     RECT  127.177 0.24 127.637 0.744 ;
     RECT  127.106 1.728 127.637 1.896 ;
     RECT  127.637 0.24 127.667 1.896 ;
     RECT  127.667 0.24 127.721 1.8 ;
     RECT  127.721 0.24 128.233 0.744 ;
     RECT  127.721 1.776 128.579 1.8 ;
     RECT  128.233 0.624 128.819 0.744 ;
     RECT  128.819 0.624 128.915 0.648 ;
     RECT  128.473 181.728 129.385 181.752 ;
     RECT  129.397 88.848 129.409 88.872 ;
     RECT  129.409 88.752 129.484 88.872 ;
     RECT  129.484 88.752 129.564 88.776 ;
     RECT  126.904 94.224 129.564 94.248 ;
     RECT  126.904 126.672 129.564 126.696 ;
     RECT  126.904 139.968 129.564 139.992 ;
     RECT  128.509 153.312 129.564 153.336 ;
    LAYER M5 ;
     RECT  55.296 0.016 70.104 0.053 ;
     RECT  74.736 0.047 74.76 0.053 ;
     RECT  74.112 0.053 74.76 0.131 ;
     RECT  82.896 0.016 98.184 0.131 ;
     RECT  54.72 0.053 70.104 0.181 ;
     RECT  72.384 0.053 72.408 0.181 ;
     RECT  110.448 0.016 126.312 0.181 ;
     RECT  110.448 0.181 128.184 0.275 ;
     RECT  17.088 0.181 17.112 0.309 ;
     RECT  24.384 0.181 24.408 0.309 ;
     RECT  43.968 0.181 43.992 0.309 ;
     RECT  0.192 0.016 13.848 0.565 ;
     RECT  17.088 0.309 17.16 0.565 ;
     RECT  19.008 0.501 19.032 0.565 ;
     RECT  20.544 0.181 20.568 0.565 ;
     RECT  22.8 0.181 22.824 0.565 ;
     RECT  24.384 0.309 24.552 0.565 ;
     RECT  26.208 0.181 26.232 0.565 ;
     RECT  27.744 0.016 41.976 0.565 ;
     RECT  43.92 0.309 43.992 0.565 ;
     RECT  45.984 0.181 46.008 0.565 ;
     RECT  47.328 0.053 47.352 0.565 ;
     RECT  49.008 0.053 49.032 0.565 ;
     RECT  51.888 0.053 51.912 0.565 ;
     RECT  53.568 0.053 53.592 0.565 ;
     RECT  54.72 0.181 70.728 0.565 ;
     RECT  72.384 0.181 72.456 0.565 ;
     RECT  75.888 0.053 75.912 0.565 ;
     RECT  78.192 0.053 78.696 0.565 ;
     RECT  80.4 0.181 80.424 0.565 ;
     RECT  82.896 0.131 97.32 0.565 ;
     RECT  99.984 0.053 100.008 0.565 ;
     RECT  106.608 0.181 106.632 0.565 ;
     RECT  108.288 0.181 108.888 0.565 ;
     RECT  27.744 0.565 42.504 0.611 ;
     RECT  110.448 0.275 127.704 0.611 ;
     RECT  82.416 0.565 97.32 0.629 ;
     RECT  19.008 0.565 23.16 0.659 ;
     RECT  75.888 0.565 80.424 0.659 ;
     RECT  98.64 0.565 98.664 0.659 ;
     RECT  128.784 0.565 128.904 0.659 ;
     RECT  81.456 0.629 97.32 0.707 ;
     RECT  128.784 0.659 128.808 0.755 ;
     RECT  0.192 0.565 14.76 1.141 ;
     RECT  16.464 0.565 17.4 1.141 ;
     RECT  24.384 0.565 24.888 1.141 ;
     RECT  26.208 0.565 26.616 1.141 ;
     RECT  27.744 0.611 34.68 1.141 ;
     RECT  35.808 0.611 42.504 1.141 ;
     RECT  43.92 0.565 44.232 1.141 ;
     RECT  45.936 0.565 47.736 1.141 ;
     RECT  49.008 0.565 49.464 1.141 ;
     RECT  51.168 0.565 70.968 1.141 ;
     RECT  72.384 0.565 72.744 1.141 ;
     RECT  74.112 0.131 74.472 1.141 ;
     RECT  78 0.659 80.424 1.141 ;
     RECT  81.456 0.707 89.4 1.141 ;
     RECT  103.2 0.053 103.8 1.141 ;
     RECT  104.88 0.181 105.48 1.141 ;
     RECT  106.608 0.565 109.224 1.141 ;
     RECT  110.448 0.611 124.584 1.141 ;
     RECT  19.008 0.659 19.128 1.187 ;
     RECT  22.176 0.659 23.16 1.187 ;
     RECT  24.384 1.141 34.68 1.187 ;
     RECT  35.808 1.141 44.232 1.187 ;
     RECT  45.936 1.141 71.4 1.187 ;
     RECT  78 1.141 89.4 1.187 ;
     RECT  90.72 0.707 97.32 1.187 ;
     RECT  106.608 1.141 124.584 1.187 ;
     RECT  0.192 1.141 17.832 1.235 ;
     RECT  41.952 1.187 44.232 1.235 ;
     RECT  45.936 1.187 52.536 1.235 ;
     RECT  53.568 1.187 69.192 1.235 ;
     RECT  70.416 1.187 71.4 1.235 ;
     RECT  78 1.187 84.264 1.235 ;
     RECT  106.608 1.187 112.344 1.235 ;
     RECT  0.192 1.235 17.16 1.283 ;
     RECT  78 1.235 80.616 1.283 ;
     RECT  19.008 1.187 19.032 1.717 ;
     RECT  20.544 0.659 20.568 1.717 ;
     RECT  24.384 1.187 27.96 1.717 ;
     RECT  43.92 1.235 44.232 1.717 ;
     RECT  45.936 1.235 46.344 1.717 ;
     RECT  72.384 1.141 74.472 1.717 ;
     RECT  75.888 0.659 76.488 1.717 ;
     RECT  78 1.283 79.032 1.717 ;
     RECT  99.984 0.565 100.872 1.717 ;
     RECT  102.192 1.141 102.216 1.717 ;
     RECT  103.2 1.141 105.48 1.717 ;
     RECT  106.608 1.235 107.016 1.717 ;
     RECT  125.856 0.611 127.704 1.717 ;
     RECT  54.72 1.235 69.192 1.763 ;
     RECT  71.856 1.717 79.032 1.763 ;
     RECT  90.72 1.187 95.112 1.763 ;
     RECT  114.288 1.187 116.904 1.763 ;
     RECT  0.192 1.283 15.624 1.811 ;
     RECT  20.544 1.717 21.816 1.811 ;
     RECT  23.952 1.717 27.96 1.811 ;
     RECT  43.92 1.717 46.344 1.811 ;
     RECT  47.328 1.235 49.032 1.811 ;
     RECT  50.352 1.235 51.912 1.811 ;
     RECT  63.888 1.763 69.192 1.811 ;
     RECT  71.856 1.763 75.912 1.811 ;
     RECT  77.088 1.763 79.032 1.811 ;
     RECT  80.4 1.283 80.616 1.811 ;
     RECT  81.648 1.235 84.264 1.811 ;
     RECT  98.832 1.717 107.016 1.811 ;
     RECT  111.84 1.235 112.344 1.811 ;
     RECT  125.472 1.717 128.568 1.811 ;
     RECT  72.384 1.811 74.136 1.859 ;
     RECT  99.216 1.811 100.968 1.859 ;
     RECT  103.2 1.811 105.48 1.907 ;
     RECT  125.472 1.811 127.656 1.907 ;
     RECT  30.528 1.187 34.68 2.137 ;
     RECT  35.808 1.187 40.32 2.137 ;
     RECT  63.888 1.811 68.664 2.291 ;
     RECT  125.472 1.907 127.08 2.291 ;
     RECT  17.088 1.283 17.16 2.293 ;
     RECT  18.288 1.717 19.032 2.293 ;
     RECT  20.544 1.811 20.568 2.293 ;
     RECT  22.8 1.187 22.824 2.293 ;
     RECT  23.952 1.811 24.552 2.293 ;
     RECT  41.952 1.235 41.976 2.293 ;
     RECT  53.568 1.235 53.592 2.293 ;
     RECT  108.288 1.235 108.888 2.293 ;
     RECT  110.4 1.235 110.808 2.293 ;
     RECT  125.472 2.291 126.912 2.293 ;
     RECT  54.72 1.763 62.664 2.339 ;
     RECT  90.72 1.763 91.608 2.339 ;
     RECT  96.24 1.187 97.32 2.339 ;
     RECT  99.216 1.859 100.008 2.339 ;
     RECT  85.44 1.187 89.352 2.351 ;
     RECT  17.088 2.293 20.568 2.387 ;
     RECT  22.8 2.293 24.552 2.387 ;
     RECT  26.208 1.811 26.568 2.387 ;
     RECT  41.952 2.293 42.888 2.387 ;
     RECT  50.88 1.811 51.912 2.387 ;
     RECT  75.552 1.811 75.912 2.387 ;
     RECT  77.712 1.811 78.696 2.387 ;
     RECT  108.288 2.293 110.808 2.387 ;
     RECT  125.04 2.293 126.912 2.387 ;
     RECT  29.04 1.187 29.52 2.407 ;
     RECT  30.528 2.137 40.32 2.407 ;
     RECT  85.44 2.351 89.544 2.435 ;
     RECT  43.92 1.811 43.992 2.773 ;
     RECT  78 2.387 78.696 2.773 ;
     RECT  112.32 1.811 112.344 2.773 ;
     RECT  47.328 1.811 47.352 2.821 ;
     RECT  53.568 2.293 53.64 2.821 ;
     RECT  54.72 2.339 57.912 2.821 ;
     RECT  63.888 2.291 68.28 2.867 ;
     RECT  0.192 1.811 13.656 2.915 ;
     RECT  17.088 2.387 17.16 2.915 ;
     RECT  20.544 2.387 20.568 2.915 ;
     RECT  24 2.387 24.552 2.915 ;
     RECT  26.208 2.387 26.232 2.915 ;
     RECT  27.936 1.811 27.96 2.915 ;
     RECT  29.04 2.407 40.512 2.915 ;
     RECT  63.888 2.867 67.512 2.915 ;
     RECT  70.704 1.235 70.728 2.915 ;
     RECT  74.112 1.859 74.136 2.915 ;
     RECT  80.4 1.811 80.424 2.915 ;
     RECT  103.2 1.907 103.8 2.915 ;
     RECT  108.288 2.387 108.888 2.915 ;
     RECT  110.4 2.387 110.808 2.915 ;
     RECT  112.32 2.773 112.632 2.915 ;
     RECT  114.288 1.763 116.664 2.915 ;
     RECT  118.368 1.187 123.672 2.915 ;
     RECT  17.136 2.915 17.16 3.011 ;
     RECT  43.92 2.773 44.568 3.011 ;
     RECT  72.384 1.859 72.912 3.011 ;
     RECT  92.784 1.763 95.112 3.011 ;
     RECT  66.096 2.915 67.512 3.059 ;
     RECT  99.6 2.339 100.008 3.205 ;
     RECT  47.232 2.821 47.352 3.311 ;
     RECT  49.008 1.811 49.032 3.311 ;
     RECT  53.568 2.821 57.912 3.311 ;
     RECT  72.48 3.011 72.912 3.311 ;
     RECT  96.24 2.339 96.888 3.311 ;
     RECT  125.856 2.387 126.912 3.317 ;
     RECT  78 2.773 78.984 3.347 ;
     RECT  18.6 2.387 19.032 3.349 ;
     RECT  24 2.915 24.456 3.349 ;
     RECT  122.496 2.915 123.672 3.371 ;
     RECT  47.136 3.311 49.8 3.395 ;
     RECT  51 2.387 51.912 3.395 ;
     RECT  53.232 3.311 57.912 3.395 ;
     RECT  0.192 2.915 4.536 3.443 ;
     RECT  31.2 2.915 36.84 3.443 ;
     RECT  72.48 3.311 73.032 3.443 ;
     RECT  82.896 1.811 84.264 3.443 ;
     RECT  85.44 2.435 89.352 3.443 ;
     RECT  92.784 3.011 94.968 3.443 ;
     RECT  112.608 2.915 112.632 3.443 ;
     RECT  115.584 2.915 116.112 3.443 ;
     RECT  22.8 2.387 22.824 3.445 ;
     RECT  41.952 2.387 41.976 3.445 ;
     RECT  44.112 3.011 44.568 3.445 ;
     RECT  45.6 1.811 46.008 3.445 ;
     RECT  53.232 3.395 54.12 3.445 ;
     RECT  75.84 2.387 75.912 3.445 ;
     RECT  82.896 3.443 83.712 3.445 ;
     RECT  96.24 3.311 97.128 3.445 ;
     RECT  99.6 3.205 100.872 3.445 ;
     RECT  104.88 1.907 105.48 3.445 ;
     RECT  106.608 1.811 106.632 3.445 ;
     RECT  108.72 2.915 108.888 3.445 ;
     RECT  125.856 3.317 127.032 3.445 ;
     RECT  31.632 3.443 35.112 3.491 ;
     RECT  96.24 3.445 98.424 3.491 ;
     RECT  20.88 3.445 21.384 3.539 ;
     RECT  23.856 3.349 24.456 3.539 ;
     RECT  44.112 3.445 46.008 3.539 ;
     RECT  48.864 3.395 49.32 3.539 ;
     RECT  52.32 3.445 54.12 3.539 ;
     RECT  75.84 3.445 76.92 3.539 ;
     RECT  78 3.347 78.648 3.539 ;
     RECT  96.672 3.491 98.424 3.539 ;
     RECT  101.856 3.445 103.128 3.539 ;
     RECT  108.72 3.445 109.176 3.539 ;
     RECT  51 3.395 51.312 3.541 ;
     RECT  22.608 3.445 22.824 3.573 ;
     RECT  23.856 3.539 24.408 3.573 ;
     RECT  75.84 3.539 75.864 3.683 ;
     RECT  125.856 3.445 127.08 3.702 ;
     RECT  76.896 3.539 76.92 3.827 ;
     RECT  53.184 3.539 54.12 3.883 ;
     RECT  39.792 2.915 40.512 3.925 ;
     RECT  41.568 3.445 42.024 3.925 ;
     RECT  110.4 2.915 110.712 3.925 ;
     RECT  119.04 2.915 119.496 3.925 ;
     RECT  125.856 3.702 127.032 3.925 ;
     RECT  110.304 3.925 110.712 3.957 ;
     RECT  21.36 3.539 21.384 3.971 ;
     RECT  110.304 3.957 110.808 4.011 ;
     RECT  5.808 2.915 13.656 4.019 ;
     RECT  33.36 3.491 35.112 4.019 ;
     RECT  36.384 3.443 36.84 4.019 ;
     RECT  38.112 2.915 38.568 4.019 ;
     RECT  39.792 3.925 42.024 4.019 ;
     RECT  44.976 3.539 46.008 4.019 ;
     RECT  54.096 3.883 54.12 4.019 ;
     RECT  55.728 3.395 57.912 4.019 ;
     RECT  59.184 2.339 62.664 4.019 ;
     RECT  80.736 3.445 81.192 4.019 ;
     RECT  82.464 3.445 83.712 4.019 ;
     RECT  86.304 3.443 87.624 4.019 ;
     RECT  97.584 3.539 97.992 4.019 ;
     RECT  103.104 3.539 103.128 4.019 ;
     RECT  104.832 3.445 107.448 4.019 ;
     RECT  15.312 3.445 15.336 4.021 ;
     RECT  18.336 3.349 19.032 4.021 ;
     RECT  78 3.539 78.312 4.021 ;
     RECT  74.256 3.311 74.28 4.069 ;
     RECT  91.056 2.339 91.512 4.069 ;
     RECT  15.312 4.021 15.72 4.115 ;
     RECT  18.336 4.021 19.176 4.115 ;
     RECT  22.608 3.573 24.408 4.115 ;
     RECT  26.064 3.445 26.088 4.115 ;
     RECT  77.28 4.021 78.312 4.115 ;
     RECT  97.584 4.019 97.608 4.115 ;
     RECT  104.832 4.019 106.152 4.115 ;
     RECT  56.4 4.019 57.912 4.153 ;
     RECT  74.064 4.069 74.28 4.153 ;
     RECT  110.4 4.011 110.808 4.163 ;
     RECT  67.2 3.059 67.512 4.243 ;
     RECT  72.6 3.443 73.032 4.243 ;
     RECT  114.288 2.915 114.312 4.243 ;
     RECT  114 4.243 114.312 4.277 ;
     RECT  67.2 4.243 68.136 4.331 ;
     RECT  72.6 4.243 73.656 4.331 ;
     RECT  74.88 4.261 75.192 4.345 ;
     RECT  125.088 3.925 127.032 4.395 ;
     RECT  113.328 4.277 114.312 4.403 ;
     RECT  12.24 4.019 13.656 4.511 ;
     RECT  18.336 4.115 18.912 4.511 ;
     RECT  42.384 4.021 42.408 4.511 ;
     RECT  45.6 4.019 46.008 4.511 ;
     RECT  50.784 3.541 51.312 4.511 ;
     RECT  72.6 4.331 73.464 4.511 ;
     RECT  99.504 3.445 100.872 4.511 ;
     RECT  104.832 4.115 105.432 4.511 ;
     RECT  23.856 4.115 24.408 4.533 ;
     RECT  25.632 4.511 25.656 4.533 ;
     RECT  79.44 4.511 79.464 4.533 ;
     RECT  124.224 4.501 124.248 4.533 ;
     RECT  23.856 4.533 25.656 4.547 ;
     RECT  99.504 4.511 101.448 4.547 ;
     RECT  81.504 4.469 82.056 4.557 ;
     RECT  34.464 4.019 35.112 4.587 ;
     RECT  0.192 3.443 4.008 4.595 ;
     RECT  6.24 4.019 8.856 4.595 ;
     RECT  10.56 4.019 10.584 4.595 ;
     RECT  12.24 4.511 13.992 4.595 ;
     RECT  20.4 4.511 20.424 4.595 ;
     RECT  22.176 4.511 22.2 4.595 ;
     RECT  23.904 4.547 25.656 4.595 ;
     RECT  31.632 3.491 32.088 4.595 ;
     RECT  36.816 4.019 36.84 4.595 ;
     RECT  38.544 4.019 38.568 4.595 ;
     RECT  42.384 4.511 43.32 4.595 ;
     RECT  50.592 4.511 52.776 4.595 ;
     RECT  57.888 4.153 57.912 4.595 ;
     RECT  59.184 4.019 59.208 4.595 ;
     RECT  60.912 4.019 62.664 4.595 ;
     RECT  71.232 4.511 73.464 4.595 ;
     RECT  75.168 4.345 75.192 4.595 ;
     RECT  79.44 4.533 80.328 4.595 ;
     RECT  87.168 4.019 87.624 4.595 ;
     RECT  88.704 3.443 89.352 4.595 ;
     RECT  93.216 3.443 94.968 4.595 ;
     RECT  99.504 4.547 100.152 4.595 ;
     RECT  101.424 4.547 101.448 4.595 ;
     RECT  104.4 4.511 105.432 4.595 ;
     RECT  114.288 4.403 114.312 4.595 ;
     RECT  118.512 3.925 119.496 4.595 ;
     RECT  122.496 3.371 122.952 4.595 ;
     RECT  13.104 4.595 13.992 4.627 ;
     RECT  32.064 4.595 32.088 4.643 ;
     RECT  33.36 4.019 33.384 4.643 ;
     RECT  80.304 4.595 80.328 4.643 ;
     RECT  124.176 4.533 124.248 4.643 ;
     RECT  3.984 4.595 4.008 4.645 ;
     RECT  82.032 4.557 82.056 4.691 ;
     RECT  125.856 4.395 127.032 4.691 ;
     RECT  13.104 4.627 14.232 4.715 ;
     RECT  3.984 4.645 4.536 4.729 ;
     RECT  90.624 4.069 91.512 4.789 ;
     RECT  23.904 4.595 24.84 4.835 ;
     RECT  17.424 4.511 18.912 4.907 ;
     RECT  97.008 4.819 97.032 4.907 ;
     RECT  34.8 4.587 35.112 5.011 ;
     RECT  27.312 4.533 27.336 5.027 ;
     RECT  90.624 4.789 92.04 5.027 ;
     RECT  78 4.115 78.312 5.077 ;
     RECT  92.016 5.027 92.04 5.087 ;
     RECT  34.8 5.011 35.208 5.099 ;
     RECT  42.336 5.011 42.36 5.099 ;
     RECT  115.8 3.443 116.112 5.109 ;
     RECT  99.504 4.595 99.912 5.113 ;
     RECT  7.536 4.595 8.232 5.123 ;
     RECT  24 4.835 24.84 5.123 ;
     RECT  88.704 4.595 89.208 5.123 ;
     RECT  120.768 2.915 121.512 5.123 ;
     RECT  39.888 4.019 41.064 5.133 ;
     RECT  29.04 2.915 29.712 5.139 ;
     RECT  78 5.077 78.552 5.163 ;
     RECT  92.016 5.087 92.952 5.163 ;
     RECT  16.608 5.087 16.632 5.171 ;
     RECT  39.888 5.133 40.512 5.171 ;
     RECT  92.928 5.163 92.952 5.171 ;
     RECT  94.08 4.595 94.512 5.171 ;
     RECT  125.856 4.691 126.912 5.171 ;
     RECT  115.8 5.109 116.712 5.197 ;
     RECT  28.464 5.139 29.712 5.227 ;
     RECT  115.8 5.197 116.328 5.227 ;
     RECT  37.632 5.173 37.656 5.257 ;
     RECT  45.6 4.511 46.728 5.317 ;
     RECT  126 5.171 126.912 5.663 ;
     RECT  50.88 4.595 51.312 5.685 ;
     RECT  90.624 5.027 90.648 5.747 ;
     RECT  126 5.663 127.032 5.747 ;
     RECT  50.016 5.685 51.312 5.773 ;
     RECT  31.488 5.845 31.512 5.931 ;
     RECT  94.2 5.171 94.512 6.099 ;
     RECT  45.6 5.317 46.824 6.133 ;
     RECT  45.6 6.133 47.16 6.179 ;
     RECT  94.2 6.099 94.776 6.187 ;
     RECT  61.344 4.595 62.664 6.191 ;
     RECT  83.4 4.019 83.712 6.197 ;
     RECT  61.344 6.191 62.76 6.275 ;
     RECT  83.4 6.197 84.12 6.285 ;
     RECT  61.344 6.275 62.664 6.323 ;
     RECT  119.472 4.595 119.496 6.323 ;
     RECT  110.4 4.163 110.712 6.453 ;
     RECT  96.048 6.421 96.072 6.507 ;
     RECT  47.088 6.179 47.16 6.571 ;
     RECT  48.48 6.675 48.504 6.763 ;
     RECT  47.136 6.571 47.16 6.803 ;
     RECT  112.848 6.739 112.872 6.827 ;
     RECT  114.576 6.739 114.6 6.827 ;
     RECT  64.368 2.915 64.92 6.851 ;
     RECT  64.896 6.851 64.92 6.899 ;
     RECT  66.096 3.059 66.12 6.899 ;
     RECT  61.632 6.323 62.112 6.947 ;
     RECT  78 5.163 78.312 7.029 ;
     RECT  78 7.029 78.408 7.117 ;
     RECT  113.232 7.029 113.256 7.117 ;
     RECT  109.968 6.453 110.712 7.339 ;
     RECT  69.504 7.391 69.528 7.475 ;
     RECT  70.128 7.797 70.152 8.003 ;
     RECT  71.28 7.797 71.304 8.003 ;
     RECT  78 7.117 78.312 8.341 ;
     RECT  78 8.341 78.408 8.485 ;
     RECT  51 5.773 51.312 8.659 ;
     RECT  94.2 6.187 94.512 8.677 ;
     RECT  50.88 8.659 51.312 8.747 ;
     RECT  78 8.485 78.696 8.747 ;
     RECT  94.032 8.677 94.512 8.761 ;
     RECT  94.08 8.761 94.512 8.939 ;
     RECT  49.632 8.885 49.656 8.973 ;
     RECT  51 8.747 51.312 9.141 ;
     RECT  51 9.141 51.624 9.229 ;
     RECT  48.384 8.965 48.408 9.805 ;
     RECT  98.064 9.717 98.088 9.805 ;
     RECT  83.4 6.285 83.712 9.909 ;
     RECT  83.088 9.909 83.712 9.925 ;
     RECT  82.656 9.925 83.712 9.973 ;
     RECT  34.8 5.099 35.112 10.165 ;
     RECT  99.6 5.113 99.912 10.213 ;
     RECT  32.112 10.131 32.136 10.219 ;
     RECT  81.792 9.973 83.712 10.293 ;
     RECT  0.192 4.595 0.696 10.307 ;
     RECT  81.792 10.293 84.408 10.381 ;
     RECT  32.448 10.357 32.472 10.441 ;
     RECT  34.8 10.165 35.256 10.475 ;
     RECT  34.8 10.475 35.208 10.539 ;
     RECT  97.44 10.463 97.464 10.547 ;
     RECT  81.792 10.381 83.712 10.595 ;
     RECT  98.64 10.213 99.912 10.603 ;
     RECT  45.6 6.179 45.912 10.837 ;
     RECT  45.6 10.837 46.104 11.075 ;
     RECT  82.56 10.595 83.712 11.371 ;
     RECT  17.232 11.731 17.256 11.819 ;
     RECT  17.28 11.859 17.304 11.947 ;
     RECT  34.8 10.539 35.112 11.951 ;
     RECT  34.8 11.951 35.4 12.035 ;
     RECT  34.8 12.035 35.112 12.181 ;
     RECT  34.176 12.181 35.112 12.267 ;
     RECT  0.24 10.307 0.696 14.963 ;
     RECT  99.6 10.603 99.912 15.407 ;
     RECT  51 9.229 51.312 15.413 ;
     RECT  96.912 15.397 96.936 15.481 ;
     RECT  98.88 15.407 99.912 15.491 ;
     RECT  51 15.413 52.296 15.501 ;
     RECT  44.448 15.445 44.472 15.531 ;
     RECT  72.6 4.595 72.912 15.699 ;
     RECT  71.808 15.699 72.912 15.787 ;
     RECT  70.08 15.733 70.104 15.817 ;
     RECT  29.4 5.227 29.712 15.829 ;
     RECT  28.464 15.829 29.712 15.915 ;
     RECT  31.392 15.829 31.416 15.915 ;
     RECT  76.368 15.925 76.392 16.009 ;
     RECT  54.72 15.973 54.744 16.057 ;
     RECT  90.576 15.973 90.6 16.057 ;
     RECT  83.4 11.371 83.712 16.181 ;
     RECT  83.4 16.181 83.928 16.269 ;
     RECT  38.736 16.309 38.76 16.403 ;
     RECT  40.032 5.171 40.512 16.405 ;
     RECT  40.032 16.405 41.208 16.491 ;
     RECT  24 5.123 24.408 16.501 ;
     RECT  61.8 6.947 62.112 16.501 ;
     RECT  94.2 8.939 94.512 16.531 ;
     RECT  23.904 16.501 24.408 16.585 ;
     RECT  60.96 16.501 62.112 16.585 ;
     RECT  97.44 16.501 97.464 16.585 ;
     RECT  99.6 15.491 99.912 16.629 ;
     RECT  18.336 4.907 18.912 16.693 ;
     RECT  105 4.595 105.312 16.693 ;
     RECT  17.088 16.597 17.112 16.723 ;
     RECT  16.224 16.723 17.112 16.741 ;
     RECT  21.12 16.501 21.144 16.747 ;
     RECT  48.384 16.645 48.408 16.747 ;
     RECT  103.2 16.645 103.224 16.747 ;
     RECT  16.032 16.741 17.112 16.757 ;
     RECT  18.336 16.693 19.704 16.757 ;
     RECT  64.512 16.757 64.536 16.789 ;
     RECT  13.104 4.715 13.512 16.799 ;
     RECT  115.8 5.227 116.112 16.799 ;
     RECT  16.032 16.757 19.704 16.811 ;
     RECT  104.88 16.693 105.312 16.835 ;
     RECT  64.416 16.789 64.536 16.845 ;
     RECT  16.032 16.811 16.056 16.875 ;
     RECT  17.088 16.811 19.704 16.875 ;
     RECT  64.416 16.845 64.44 16.875 ;
     RECT  111.696 16.789 111.72 16.875 ;
     RECT  13.104 16.799 14.232 16.883 ;
     RECT  115.68 16.799 116.112 16.883 ;
     RECT  99.6 16.629 100.152 16.981 ;
     RECT  17.088 16.875 17.112 17.003 ;
     RECT  86.688 16.915 86.712 17.003 ;
     RECT  78 8.747 78.312 17.013 ;
     RECT  10.848 16.981 10.872 17.067 ;
     RECT  58.8 16.933 58.824 17.067 ;
     RECT  94.08 16.531 94.512 17.067 ;
     RECT  98.88 16.981 100.344 17.067 ;
     RECT  109.296 16.981 109.32 17.067 ;
     RECT  18.336 16.875 18.912 17.075 ;
     RECT  81.456 16.991 81.48 17.075 ;
     RECT  74.112 17.013 74.136 17.101 ;
     RECT  108.24 17.013 108.264 17.101 ;
     RECT  20.544 16.885 20.568 17.123 ;
     RECT  78 17.013 78.408 17.123 ;
     RECT  61.8 16.585 62.112 17.269 ;
     RECT  61.8 17.269 62.232 17.363 ;
     RECT  66.096 17.317 66.12 17.401 ;
     RECT  83.4 16.269 83.712 17.589 ;
     RECT  118.176 17.509 118.2 17.643 ;
     RECT  83.28 17.589 83.712 17.677 ;
     RECT  67.2 4.331 67.512 17.781 ;
     RECT  67.2 17.781 68.184 17.891 ;
     RECT  114.432 17.909 114.456 17.997 ;
     RECT  7.8 5.123 8.232 18.133 ;
     RECT  88.8 5.123 89.208 18.133 ;
     RECT  92.592 18.067 92.616 18.155 ;
     RECT  7.8 18.133 9.096 18.219 ;
     RECT  88.8 18.133 90.072 18.219 ;
     RECT  29.4 15.915 29.712 18.357 ;
     RECT  56.4 4.153 56.712 18.387 ;
     RECT  2.4 4.595 2.712 18.421 ;
     RECT  26.064 18.357 26.088 18.445 ;
     RECT  29.28 18.357 29.712 18.467 ;
     RECT  56.4 18.387 57 18.475 ;
     RECT  2.4 18.421 2.856 18.505 ;
     RECT  45.6 11.075 45.912 18.613 ;
     RECT  99.6 17.067 99.912 18.613 ;
     RECT  47.904 18.613 47.928 18.707 ;
     RECT  98.64 18.613 99.912 18.707 ;
     RECT  45.6 18.613 46.152 18.755 ;
     RECT  75.264 18.613 75.288 18.851 ;
     RECT  32.64 18.12 32.664 19.141 ;
     RECT  40.032 16.491 40.512 19.141 ;
     RECT  32.496 19.141 32.664 19.187 ;
     RECT  51 15.501 51.312 19.333 ;
     RECT  110.4 7.339 110.712 19.509 ;
     RECT  15.264 19.477 15.288 19.563 ;
     RECT  32.496 19.187 32.52 19.563 ;
     RECT  40.032 19.141 41.016 19.563 ;
     RECT  50.88 19.333 51.312 19.563 ;
     RECT  95.712 19.333 95.736 19.563 ;
     RECT  0.672 14.963 0.696 19.619 ;
     RECT  5.616 19.603 5.64 19.691 ;
     RECT  10.704 19.509 10.728 19.691 ;
     RECT  37.44 19.669 37.464 19.755 ;
     RECT  72.6 15.787 72.912 19.765 ;
     RECT  79.824 19.765 79.848 19.849 ;
     RECT  118.944 19.509 118.968 19.883 ;
     RECT  53.664 19.861 53.688 19.947 ;
     RECT  71.808 19.765 72.912 19.981 ;
     RECT  87.264 19.893 87.288 19.981 ;
     RECT  103.392 19.893 103.416 19.981 ;
     RECT  110.4 19.509 111.48 19.981 ;
     RECT  49.536 19.509 49.56 20.003 ;
     RECT  7.8 18.219 8.232 20.005 ;
     RECT  16.848 19.987 16.872 20.075 ;
     RECT  6.816 20.005 8.232 20.089 ;
     RECT  27.936 20.053 27.96 20.139 ;
     RECT  115.8 16.883 116.112 20.149 ;
     RECT  17.568 20.307 17.592 20.395 ;
     RECT  66.096 20.341 66.12 20.425 ;
     RECT  34.8 12.267 35.112 20.437 ;
     RECT  94.2 17.067 94.512 20.437 ;
     RECT  7.8 20.089 8.232 20.499 ;
     RECT  34.8 20.437 35.88 20.523 ;
     RECT  74.256 20.437 74.28 20.523 ;
     RECT  93.456 20.437 94.512 20.523 ;
     RECT  106.944 20.437 106.968 20.523 ;
     RECT  115.8 20.149 116.232 20.523 ;
     RECT  60.576 20.447 60.6 20.531 ;
     RECT  69.552 20.533 69.576 20.581 ;
     RECT  7.8 20.499 9.192 20.587 ;
     RECT  69.552 20.581 70.104 20.627 ;
     RECT  72.384 19.981 72.912 20.661 ;
     RECT  7.8 20.587 9.096 20.665 ;
     RECT  70.08 20.627 70.104 20.665 ;
     RECT  83.4 17.677 83.712 20.691 ;
     RECT  72.384 20.661 73.032 20.723 ;
     RECT  72.6 20.723 73.032 20.749 ;
     RECT  82.464 20.691 83.712 20.779 ;
     RECT  24 16.585 24.408 20.853 ;
     RECT  21.168 20.853 21.192 20.941 ;
     RECT  23.376 20.853 25.128 20.941 ;
     RECT  61.8 17.363 62.112 21.013 ;
     RECT  34.8 20.523 35.112 21.109 ;
     RECT  34.704 21.109 35.112 21.203 ;
     RECT  96.96 21.109 96.984 21.203 ;
     RECT  85.488 21.167 85.512 21.251 ;
     RECT  90.624 21.167 90.648 21.251 ;
     RECT  23.904 20.941 25.128 21.547 ;
     RECT  24 21.547 25.128 21.589 ;
     RECT  40.032 19.563 40.512 21.599 ;
     RECT  39.312 21.599 40.512 21.621 ;
     RECT  24 21.589 25.176 21.675 ;
     RECT  39.312 21.621 41.304 21.683 ;
     RECT  78 17.123 78.312 21.685 ;
     RECT  107.184 21.637 107.208 21.739 ;
     RECT  77.904 21.685 78.312 21.769 ;
     RECT  99.6 18.707 99.912 21.781 ;
     RECT  56.4 18.475 56.712 21.941 ;
     RECT  56.4 21.941 57.24 21.973 ;
     RECT  2.4 18.505 2.712 22.127 ;
     RECT  3.984 4.729 4.008 22.127 ;
     RECT  2.4 22.127 4.008 22.133 ;
     RECT  13.104 16.883 13.512 22.165 ;
     RECT  45.6 18.755 45.912 22.165 ;
     RECT  102.624 22.127 102.648 22.165 ;
     RECT  105 16.835 105.312 22.165 ;
     RECT  99.6 21.781 100.344 22.187 ;
     RECT  2.4 22.133 4.824 22.211 ;
     RECT  102.624 22.165 102.984 22.211 ;
     RECT  3.984 22.211 4.824 22.221 ;
     RECT  106.32 22.133 106.344 22.221 ;
     RECT  13.104 22.165 13.608 22.251 ;
     RECT  14.832 22.165 14.856 22.251 ;
     RECT  40.032 21.683 41.304 22.251 ;
     RECT  45.6 22.165 46.008 22.251 ;
     RECT  55.248 21.781 55.272 22.251 ;
     RECT  102.96 22.211 102.984 22.251 ;
     RECT  3.984 22.221 4.008 22.259 ;
     RECT  110.4 19.981 110.712 22.261 ;
     RECT  37.344 22.261 37.368 22.355 ;
     RECT  110.4 22.261 111.432 22.355 ;
     RECT  115.8 20.523 116.112 22.389 ;
     RECT  13.104 22.251 13.512 22.451 ;
     RECT  115.8 22.389 116.904 22.477 ;
     RECT  104.832 22.165 105.312 22.507 ;
     RECT  7.8 20.665 8.232 22.645 ;
     RECT  121.2 5.123 121.512 22.675 ;
     RECT  32.4 22.611 32.424 22.699 ;
     RECT  126 5.747 126.912 22.703 ;
     RECT  124.224 4.643 124.248 22.709 ;
     RECT  7.8 22.645 8.712 22.739 ;
     RECT  10.896 22.197 10.92 22.739 ;
     RECT  53.76 22.645 53.784 22.739 ;
     RECT  26.16 22.675 26.184 22.763 ;
     RECT  120.672 22.675 121.512 22.763 ;
     RECT  56.4 21.973 57.576 22.777 ;
     RECT  40.032 22.251 40.512 22.787 ;
     RECT  75.84 22.703 75.864 22.787 ;
     RECT  125.424 22.703 126.912 22.787 ;
     RECT  123.408 22.709 124.248 22.797 ;
     RECT  18.6 17.075 18.912 22.837 ;
     RECT  17.664 22.837 18.912 22.931 ;
     RECT  64.416 22.837 64.44 22.931 ;
     RECT  68.928 22.837 68.952 22.931 ;
     RECT  81.456 22.837 81.48 22.931 ;
     RECT  118.944 22.837 118.968 22.931 ;
     RECT  94.2 20.523 94.512 23.157 ;
     RECT  94.08 23.157 94.512 23.269 ;
     RECT  118.992 23.173 119.016 23.275 ;
     RECT  60.624 23.251 60.648 23.339 ;
     RECT  61.8 21.013 63 23.339 ;
     RECT  94.08 23.269 94.68 23.339 ;
     RECT  43.296 23.269 43.32 23.353 ;
     RECT  94.2 23.339 94.68 23.353 ;
     RECT  47.328 23.327 47.352 23.411 ;
     RECT  92.88 23.327 92.904 23.411 ;
     RECT  51 19.563 51.312 23.477 ;
     RECT  49.536 23.317 49.56 23.531 ;
     RECT  50.88 23.477 51.312 23.565 ;
     RECT  83.4 20.779 83.712 23.701 ;
     RECT  83.28 23.701 83.712 23.787 ;
     RECT  40.2 22.787 40.512 23.903 ;
     RECT  72.6 20.749 72.912 23.903 ;
     RECT  99.6 22.187 99.912 23.903 ;
     RECT  114.528 23.845 114.552 23.929 ;
     RECT  40.2 23.903 41.016 23.987 ;
     RECT  72.6 23.903 73.512 23.987 ;
     RECT  98.736 23.903 99.912 23.987 ;
     RECT  29.4 18.467 29.712 23.989 ;
     RECT  29.4 23.989 30.216 24.083 ;
     RECT  106.608 23.989 106.632 24.083 ;
     RECT  44.112 23.989 44.136 24.131 ;
     RECT  85.488 23.989 85.512 24.371 ;
     RECT  78 21.769 78.312 24.757 ;
     RECT  7.8 22.739 8.232 24.805 ;
     RECT  24 21.675 24.408 24.863 ;
     RECT  25.632 24.853 25.656 24.863 ;
     RECT  6.912 24.805 8.232 24.939 ;
     RECT  24 24.863 25.656 24.939 ;
     RECT  87.792 23.989 87.816 24.939 ;
     RECT  24 24.939 25.176 24.947 ;
     RECT  126 22.787 126.912 24.979 ;
     RECT  34.8 21.203 35.112 24.997 ;
     RECT  110.4 22.355 110.712 24.997 ;
     RECT  2.4 22.211 2.712 25.013 ;
     RECT  61.8 23.339 62.112 25.013 ;
     RECT  4.896 24.885 4.92 25.067 ;
     RECT  78 24.757 78.888 25.067 ;
     RECT  122.784 24.979 122.808 25.067 ;
     RECT  125.52 24.979 126.912 25.067 ;
     RECT  34.8 24.997 35.208 25.081 ;
     RECT  110.4 24.997 111.144 25.081 ;
     RECT  58.656 25.013 58.68 25.101 ;
     RECT  61.8 25.013 63 25.101 ;
     RECT  54.672 25.141 54.696 25.225 ;
     RECT  13.2 22.451 13.512 25.285 ;
     RECT  2.4 25.013 3.48 25.387 ;
     RECT  13.104 25.285 13.512 25.387 ;
     RECT  74.64 25.439 74.664 25.523 ;
     RECT  88.8 18.219 89.208 25.573 ;
     RECT  18.6 22.931 18.912 25.631 ;
     RECT  88.176 25.573 89.208 25.657 ;
     RECT  22.08 25.573 22.2 25.707 ;
     RECT  18.6 25.631 19.368 25.715 ;
     RECT  24 24.947 24.312 25.717 ;
     RECT  57.696 25.653 57.72 25.741 ;
     RECT  22.176 25.707 22.2 25.771 ;
     RECT  15.408 25.717 15.432 25.801 ;
     RECT  67.2 17.891 67.512 25.861 ;
     RECT  33.168 25.717 33.192 25.963 ;
     RECT  66.624 25.861 67.512 25.963 ;
     RECT  103.728 25.909 103.752 25.993 ;
     RECT  115.8 22.477 116.112 26.131 ;
     RECT  23.664 25.717 24.312 26.155 ;
     RECT  64.704 26.067 64.728 26.155 ;
     RECT  83.4 23.787 83.712 26.207 ;
     RECT  115.68 26.131 116.112 26.219 ;
     RECT  70.8 26.149 70.824 26.233 ;
     RECT  80.208 26.149 80.232 26.233 ;
     RECT  83.4 26.207 84.312 26.291 ;
     RECT  90.624 26.293 90.648 26.377 ;
     RECT  108.816 26.421 108.84 26.485 ;
     RECT  36.96 26.421 36.984 26.531 ;
     RECT  45.6 22.251 45.912 26.677 ;
     RECT  99.6 23.987 99.912 26.677 ;
     RECT  108.288 26.485 108.84 26.731 ;
     RECT  42.144 26.677 42.168 26.761 ;
     RECT  45.6 26.677 46.008 26.761 ;
     RECT  96.864 26.677 96.888 26.761 ;
     RECT  100.896 26.677 100.92 26.761 ;
     RECT  98.64 26.677 99.912 26.771 ;
     RECT  40.2 23.987 40.512 26.805 ;
     RECT  110.4 25.081 110.712 26.805 ;
     RECT  37.008 26.725 37.032 26.859 ;
     RECT  108.288 26.731 108.312 26.859 ;
     RECT  39.36 26.805 40.512 26.893 ;
     RECT  110.4 26.805 111.624 26.893 ;
     RECT  11.616 27.027 11.64 27.115 ;
     RECT  9.648 27.061 9.672 27.155 ;
     RECT  29.4 24.083 29.712 27.205 ;
     RECT  51 23.565 51.312 27.283 ;
     RECT  105 22.507 105.312 27.283 ;
     RECT  87.504 26.805 87.528 27.299 ;
     RECT  55.152 27.219 55.176 27.307 ;
     RECT  9.552 27.283 9.576 27.371 ;
     RECT  26.064 27.283 26.088 27.371 ;
     RECT  29.04 27.205 29.712 27.371 ;
     RECT  48.528 27.283 48.552 27.371 ;
     RECT  50.16 27.283 51.312 27.371 ;
     RECT  105 27.283 106.248 27.371 ;
     RECT  119.808 27.283 119.832 27.371 ;
     RECT  117.936 27.311 117.96 27.395 ;
     RECT  44.592 27.359 44.616 27.443 ;
     RECT  2.4 25.387 2.712 27.503 ;
     RECT  7.8 24.939 8.232 27.551 ;
     RECT  78 25.067 78.312 27.551 ;
     RECT  7.8 27.551 8.52 27.573 ;
     RECT  2.4 27.503 2.856 27.587 ;
     RECT  7.056 27.573 8.52 27.635 ;
     RECT  78 27.551 78.648 27.635 ;
     RECT  7.056 27.635 8.232 27.765 ;
     RECT  4.512 27.743 4.536 27.827 ;
     RECT  126 25.067 126.912 27.829 ;
     RECT  15.408 27.781 15.432 27.883 ;
     RECT  31.536 27.317 31.56 27.883 ;
     RECT  122.592 27.317 122.616 27.883 ;
     RECT  125.424 27.829 126.912 27.913 ;
     RECT  6.864 27.765 8.232 27.923 ;
     RECT  7.68 27.923 8.232 27.947 ;
     RECT  76.128 27.859 76.152 27.947 ;
     RECT  72.6 23.987 72.912 28.261 ;
     RECT  19.968 28.309 19.992 28.395 ;
     RECT  56.4 22.777 56.712 28.453 ;
     RECT  69.84 28.371 69.864 28.459 ;
     RECT  115.8 26.219 116.112 28.511 ;
     RECT  20.592 28.435 20.616 28.523 ;
     RECT  55.824 28.453 56.712 28.537 ;
     RECT  115.2 28.511 116.112 28.595 ;
     RECT  81.648 28.597 81.672 28.691 ;
     RECT  67.2 25.963 67.512 28.755 ;
     RECT  66.336 28.755 67.512 28.843 ;
     RECT  34.8 25.081 35.112 28.917 ;
     RECT  34.8 28.917 35.208 29.005 ;
     RECT  36.384 28.917 37.32 29.005 ;
     RECT  58.896 28.917 58.92 29.005 ;
     RECT  94.2 23.353 94.512 29.029 ;
     RECT  4.128 28.741 4.152 29.035 ;
     RECT  16.992 28.947 17.016 29.035 ;
     RECT  74.544 28.947 74.568 29.035 ;
     RECT  60.672 28.453 60.696 29.109 ;
     RECT  53.184 29.039 53.208 29.123 ;
     RECT  94.08 29.029 94.512 29.203 ;
     RECT  97.44 29.173 97.464 29.203 ;
     RECT  72.048 28.261 72.912 29.219 ;
     RECT  99.6 26.771 99.912 29.237 ;
     RECT  97.344 29.203 97.464 29.267 ;
     RECT  24 26.155 24.312 29.269 ;
     RECT  93.168 29.203 94.512 29.291 ;
     RECT  97.344 29.267 97.368 29.291 ;
     RECT  113.712 29.203 113.736 29.291 ;
     RECT  121.2 22.763 121.512 29.301 ;
     RECT  60.096 29.109 60.696 29.331 ;
     RECT  61.8 25.101 62.112 29.331 ;
     RECT  88.8 25.657 89.208 29.331 ;
     RECT  24 29.269 25.08 29.355 ;
     RECT  9.552 29.301 9.576 29.365 ;
     RECT  13.2 25.387 13.512 29.365 ;
     RECT  34.8 29.005 35.112 29.365 ;
     RECT  56.4 28.537 56.712 29.365 ;
     RECT  98.64 29.237 99.912 29.365 ;
     RECT  105 27.371 105.312 29.365 ;
     RECT  60.096 29.331 62.112 29.419 ;
     RECT  88.8 29.331 89.928 29.419 ;
     RECT  102.912 29.331 102.936 29.419 ;
     RECT  34.704 29.365 35.112 29.449 ;
     RECT  36.384 29.005 36.408 29.459 ;
     RECT  60.096 29.419 60.12 29.459 ;
     RECT  48 29.365 48.024 29.507 ;
     RECT  9.552 29.365 9.672 29.699 ;
     RECT  12 29.365 13.512 29.699 ;
     RECT  88.8 29.419 89.208 29.699 ;
     RECT  105 29.365 105.432 29.699 ;
     RECT  121.2 29.301 121.992 29.699 ;
     RECT  80.88 29.365 80.904 29.747 ;
     RECT  56.4 29.365 57.432 29.795 ;
     RECT  98.64 29.365 100.296 29.891 ;
     RECT  12.672 29.699 13.512 30.035 ;
     RECT  42.288 29.365 42.312 30.035 ;
     RECT  83.4 26.291 83.712 30.037 ;
     RECT  9.552 29.699 9.576 30.131 ;
     RECT  98.64 29.891 99.912 30.179 ;
     RECT  18.6 25.715 18.912 30.181 ;
     RECT  124.224 22.797 124.248 30.323 ;
     RECT  2.4 27.587 2.712 30.325 ;
     RECT  24 29.355 24.312 30.325 ;
     RECT  29.4 27.371 29.712 30.325 ;
     RECT  126 27.913 126.912 30.325 ;
     RECT  32.496 30.181 32.52 30.379 ;
     RECT  63.12 30.181 63.144 30.379 ;
     RECT  82.656 30.037 83.712 30.379 ;
     RECT  118.704 30.181 118.728 30.379 ;
     RECT  2.4 30.325 3.384 30.409 ;
     RECT  125.424 30.325 126.912 30.409 ;
     RECT  18.24 30.181 19.368 30.443 ;
     RECT  110.4 26.893 110.712 30.453 ;
     RECT  15.36 30.383 15.384 30.467 ;
     RECT  51 27.371 51.312 30.483 ;
     RECT  27.6 30.421 27.624 30.507 ;
     RECT  109.392 29.941 109.416 30.507 ;
     RECT  122.496 30.421 122.52 30.507 ;
     RECT  20.496 30.431 20.52 30.515 ;
     RECT  107.28 30.453 107.304 30.541 ;
     RECT  110.4 30.453 111.576 30.563 ;
     RECT  24 30.325 24.84 30.675 ;
     RECT  23.904 30.675 24.84 30.763 ;
     RECT  29.4 30.325 29.976 30.763 ;
     RECT  80.928 30.675 80.952 30.763 ;
     RECT  99.168 30.179 99.912 30.763 ;
     RECT  88.8 29.699 89.112 30.773 ;
     RECT  50.064 30.483 51.312 30.805 ;
     RECT  88.32 30.773 89.112 30.815 ;
     RECT  45.6 26.761 45.912 30.837 ;
     RECT  87.792 30.815 89.112 30.861 ;
     RECT  85.776 30.709 85.8 30.891 ;
     RECT  87.792 30.861 87.816 30.899 ;
     RECT  45.36 30.837 45.912 31.019 ;
     RECT  61.8 29.419 62.112 31.029 ;
     RECT  50.016 30.805 51.312 31.083 ;
     RECT  115.8 28.595 116.112 31.333 ;
     RECT  3.936 30.888 3.96 31.349 ;
     RECT  61.008 31.029 62.112 31.379 ;
     RECT  3.936 31.349 4.728 31.403 ;
     RECT  115.8 31.333 116.856 31.417 ;
     RECT  55.248 31.349 55.272 31.437 ;
     RECT  4.704 31.403 4.728 31.507 ;
     RECT  4.704 31.507 5.112 31.595 ;
     RECT  94.2 29.291 94.512 31.605 ;
     RECT  67.2 28.843 67.512 31.635 ;
     RECT  92.304 31.583 92.328 31.667 ;
     RECT  34.8 29.449 35.112 31.669 ;
     RECT  93.84 31.605 94.512 31.693 ;
     RECT  67.2 31.635 68.088 31.723 ;
     RECT  34.176 31.669 35.112 31.753 ;
     RECT  66.096 31.669 66.12 31.763 ;
     RECT  78 27.635 78.312 31.861 ;
     RECT  102.384 31.797 102.408 31.907 ;
     RECT  13.2 30.035 13.512 31.919 ;
     RECT  29.4 30.763 29.712 31.919 ;
     RECT  24 30.763 24.312 31.925 ;
     RECT  78 31.861 79.224 31.945 ;
     RECT  12.624 31.919 13.512 32.003 ;
     RECT  20.496 31.919 20.52 32.003 ;
     RECT  29.4 31.919 30.024 32.003 ;
     RECT  83.4 30.379 83.712 32.117 ;
     RECT  82.56 32.117 83.712 32.205 ;
     RECT  24 31.925 24.504 32.243 ;
     RECT  110.4 30.563 110.712 32.373 ;
     RECT  121.2 29.699 121.512 32.403 ;
     RECT  113.424 32.341 113.448 32.427 ;
     RECT  12.816 32.003 13.512 32.437 ;
     RECT  16.8 32.373 16.824 32.437 ;
     RECT  99.6 30.763 99.912 32.437 ;
     RECT  76.032 32.373 76.056 32.461 ;
     RECT  110.4 32.373 111.48 32.461 ;
     RECT  19.968 32.403 20.472 32.491 ;
     RECT  120.96 32.403 121.512 32.491 ;
     RECT  12.816 32.437 14.28 32.521 ;
     RECT  16.56 32.437 16.824 32.521 ;
     RECT  96.864 32.437 96.888 32.521 ;
     RECT  105 29.699 105.312 32.687 ;
     RECT  98.928 32.437 99.912 32.723 ;
     RECT  40.2 26.893 40.512 32.725 ;
     RECT  18.6 30.443 18.912 32.757 ;
     RECT  104.304 32.687 105.312 32.771 ;
     RECT  11.76 32.725 11.784 32.811 ;
     RECT  36.432 31.669 36.456 32.811 ;
     RECT  39.888 32.725 40.512 32.811 ;
     RECT  18.192 32.757 18.912 32.821 ;
     RECT  20.448 32.491 20.472 32.845 ;
     RECT  110.4 32.461 110.712 32.851 ;
     RECT  17.424 32.821 18.912 32.867 ;
     RECT  124.56 32.773 124.584 32.875 ;
     RECT  7.8 27.947 8.232 32.885 ;
     RECT  5.76 31.861 5.784 32.939 ;
     RECT  11.664 32.821 11.688 32.939 ;
     RECT  110.256 32.851 110.712 32.939 ;
     RECT  108.816 32.879 108.84 32.963 ;
     RECT  12.816 32.521 13.896 33.011 ;
     RECT  48.72 32.949 48.744 33.037 ;
     RECT  118.272 32.949 118.296 33.037 ;
     RECT  4.704 31.595 4.728 33.059 ;
     RECT  7.8 32.885 8.28 33.059 ;
     RECT  17.424 32.867 17.448 33.067 ;
     RECT  45.6 31.019 45.912 33.071 ;
     RECT  7.8 33.059 8.232 33.077 ;
     RECT  61.8 31.379 62.112 33.141 ;
     RECT  4.512 33.071 4.536 33.155 ;
     RECT  27.408 33.071 27.432 33.155 ;
     RECT  44.976 33.071 45.912 33.155 ;
     RECT  78 31.945 78.312 33.205 ;
     RECT  61.8 33.141 63.096 33.251 ;
     RECT  77.136 33.205 78.312 33.299 ;
     RECT  7.68 33.077 8.232 33.587 ;
     RECT  13.2 33.011 13.896 33.643 ;
     RECT  15.984 33.013 16.008 33.643 ;
     RECT  7.68 33.587 8.112 33.707 ;
     RECT  81.36 33.973 81.384 34.067 ;
     RECT  83.4 32.205 83.712 34.223 ;
     RECT  121.2 32.491 121.512 34.223 ;
     RECT  56.4 29.795 56.712 34.229 ;
     RECT  46.992 34.223 47.016 34.307 ;
     RECT  83.136 34.223 83.712 34.307 ;
     RECT  121.2 34.223 121.608 34.307 ;
     RECT  45.6 33.155 45.912 34.323 ;
     RECT  56.4 34.229 56.808 34.403 ;
     RECT  18.6 32.867 18.912 34.677 ;
     RECT  45.6 34.323 46.776 34.681 ;
     RECT  81.696 34.613 81.72 34.701 ;
     RECT  18.6 34.677 19.656 34.799 ;
     RECT  18.6 34.799 19.896 34.883 ;
     RECT  83.184 34.307 83.712 34.883 ;
     RECT  118.32 34.805 118.344 35.171 ;
     RECT  64.416 35.701 64.44 35.785 ;
     RECT  117.936 35.701 117.96 35.785 ;
     RECT  124.848 35.701 124.872 35.785 ;
     RECT  11.376 35.701 11.4 35.795 ;
     RECT  126 30.409 126.912 35.797 ;
     RECT  122.544 35.701 122.568 35.883 ;
     RECT  125.616 35.797 126.912 35.883 ;
     RECT  13.2 33.643 13.512 36.021 ;
     RECT  10.8 35.999 10.824 36.083 ;
     RECT  13.104 36.021 13.512 36.109 ;
     RECT  64.272 57.263 64.296 57.347 ;
     RECT  63.888 57.525 63.912 57.613 ;
     RECT  126 35.883 126.912 66.179 ;
     RECT  51 31.083 51.312 84.853 ;
     RECT  50.064 84.853 51.312 84.947 ;
     RECT  50.112 84.947 51.312 85.177 ;
     RECT  51 85.177 51.312 85.557 ;
     RECT  51 85.557 52.248 85.645 ;
     RECT  53.808 85.621 53.832 85.705 ;
     RECT  84.96 86.645 84.984 86.733 ;
     RECT  83.4 34.883 83.712 87.123 ;
     RECT  83.28 87.123 83.712 87.211 ;
     RECT  80.352 87.781 80.376 87.791 ;
     RECT  80.256 87.791 80.376 87.865 ;
     RECT  80.256 87.865 80.28 87.875 ;
     RECT  129.408 88.693 129.432 88.883 ;
     RECT  64.752 91.813 64.776 91.897 ;
     RECT  67.2 31.723 67.512 91.923 ;
     RECT  66.288 91.923 67.512 92.011 ;
     RECT  126.6 66.179 126.912 107.183 ;
     RECT  126.48 107.183 126.912 107.267 ;
     RECT  51 85.645 51.312 118.581 ;
     RECT  51 118.581 52.296 118.669 ;
     RECT  51 118.669 51.312 119.059 ;
     RECT  50.496 119.059 51.312 119.147 ;
     RECT  45.6 34.681 45.912 120.757 ;
     RECT  83.4 87.211 83.712 120.815 ;
     RECT  45.6 120.757 46.632 120.863 ;
     RECT  45.6 120.863 47.016 120.899 ;
     RECT  83.28 120.815 83.712 120.899 ;
     RECT  46.992 120.899 47.016 120.947 ;
     RECT  82.224 121.013 82.248 121.101 ;
     RECT  86.688 121.013 86.712 121.475 ;
     RECT  87.024 121.957 87.048 122.155 ;
     RECT  67.2 92.011 67.512 125.423 ;
     RECT  66.288 125.423 67.704 125.507 ;
     RECT  38.736 148.021 38.76 148.105 ;
     RECT  39.12 148.127 39.144 148.211 ;
     RECT  94.2 31.693 94.512 149.365 ;
     RECT  94.08 149.365 94.512 149.449 ;
     RECT  94.2 149.449 94.512 149.749 ;
     RECT  94.2 149.749 94.632 149.833 ;
     RECT  46.992 150.517 47.016 150.611 ;
     RECT  48.576 150.867 48.6 150.955 ;
     RECT  47.04 150.901 47.064 150.995 ;
     RECT  84.912 152.159 84.936 152.243 ;
     RECT  85.104 152.467 85.128 152.555 ;
     RECT  91.2 178.549 91.224 178.633 ;
     RECT  117.696 178.771 117.72 178.859 ;
     RECT  123.696 178.789 123.72 178.873 ;
     RECT  40.2 32.811 40.512 179.173 ;
     RECT  67.2 125.507 67.512 179.221 ;
     RECT  99.6 32.723 99.912 179.283 ;
     RECT  99.6 179.283 100.44 179.371 ;
     RECT  7.8 33.707 8.112 179.509 ;
     RECT  59.424 179.461 59.448 179.509 ;
     RECT  58.656 179.509 59.448 179.563 ;
     RECT  83.4 120.899 83.712 179.567 ;
     RECT  64.944 179.539 64.968 179.627 ;
     RECT  58.656 179.563 58.68 179.651 ;
     RECT  83.28 179.567 83.712 179.651 ;
     RECT  2.4 30.409 2.712 179.749 ;
     RECT  56.4 34.403 56.712 179.893 ;
     RECT  66.72 179.221 67.512 179.893 ;
     RECT  6.816 179.509 8.112 179.947 ;
     RECT  74.784 179.845 74.808 179.947 ;
     RECT  56.4 179.893 57.048 179.977 ;
     RECT  10.8 179.509 10.824 180.131 ;
     RECT  86.4 179.221 86.424 180.131 ;
     RECT  7.68 179.947 8.112 180.179 ;
     RECT  42.768 179.509 42.792 180.179 ;
     RECT  63.84 179.509 63.864 180.179 ;
     RECT  121.2 34.307 121.512 180.421 ;
     RECT  0.624 179.989 0.648 180.565 ;
     RECT  13.2 36.109 13.512 180.597 ;
     RECT  34.8 31.753 35.112 180.597 ;
     RECT  39.408 179.173 40.512 180.597 ;
     RECT  22.8 180.085 22.824 180.651 ;
     RECT  66.672 179.893 67.512 180.755 ;
     RECT  34.8 180.597 35.208 180.851 ;
     RECT  0.192 180.565 0.648 181.141 ;
     RECT  1.968 179.749 2.712 181.141 ;
     RECT  7.8 180.179 8.112 181.237 ;
     RECT  14.832 180.597 14.856 181.237 ;
     RECT  18.6 34.883 18.912 181.237 ;
     RECT  24 32.243 24.312 181.237 ;
     RECT  26.784 180.597 26.808 181.237 ;
     RECT  39.36 180.597 40.512 181.237 ;
     RECT  45.6 120.899 45.912 181.237 ;
     RECT  48.432 180.597 48.456 181.237 ;
     RECT  51 119.147 51.312 181.237 ;
     RECT  56.4 179.977 56.712 181.237 ;
     RECT  72.6 29.219 72.912 181.237 ;
     RECT  78 33.299 78.312 181.237 ;
     RECT  83.4 179.651 83.712 181.237 ;
     RECT  99.6 179.371 99.912 181.237 ;
     RECT  102.624 179.221 102.648 181.237 ;
     RECT  105 32.771 105.312 181.237 ;
     RECT  109.152 180.341 109.176 181.237 ;
     RECT  110.4 32.939 110.712 181.237 ;
     RECT  126.6 107.267 126.912 181.237 ;
     RECT  16.464 181.237 20.472 181.547 ;
     RECT  21.792 181.237 22.2 181.547 ;
     RECT  23.568 181.237 26.904 181.547 ;
     RECT  42.384 181.237 46.392 181.547 ;
     RECT  48.096 181.237 56.712 181.547 ;
     RECT  70.56 181.237 71.4 181.547 ;
     RECT  72.6 181.237 78.456 181.547 ;
     RECT  79.776 181.237 84.024 181.547 ;
     RECT  99.072 181.237 112.104 181.547 ;
     RECT  45.888 181.547 46.392 181.561 ;
     RECT  83.664 181.547 84.024 181.561 ;
     RECT  51.168 181.547 51.192 181.611 ;
     RECT  18.192 181.547 18.744 181.675 ;
     RECT  23.568 181.547 23.976 181.675 ;
     RECT  72.6 181.547 74.472 181.675 ;
     RECT  77.472 181.547 78.456 181.675 ;
     RECT  99.072 181.547 99.912 181.675 ;
     RECT  110.352 181.547 110.376 181.675 ;
     RECT  13.2 180.597 13.656 181.717 ;
     RECT  14.832 181.237 15.192 181.717 ;
     RECT  48.096 181.547 48.552 181.717 ;
     RECT  126.6 181.237 127.032 181.717 ;
     RECT  13.2 181.717 16.056 181.803 ;
     RECT  20.832 181.717 21.336 181.803 ;
     RECT  22.56 181.717 23.064 181.803 ;
     RECT  27.456 181.717 27.912 181.803 ;
     RECT  46.8 181.717 48.552 181.803 ;
     RECT  53.376 181.547 53.4 181.803 ;
     RECT  71.712 181.717 72.264 181.803 ;
     RECT  73.488 181.675 74.472 181.803 ;
     RECT  78.816 181.717 79.32 181.803 ;
     RECT  98.64 181.717 98.664 181.803 ;
     RECT  99.888 181.675 99.912 181.803 ;
     RECT  105.216 181.547 105.24 181.803 ;
     RECT  106.944 181.547 106.968 181.803 ;
     RECT  111.792 181.547 112.104 181.803 ;
     RECT  126.6 181.717 127.08 181.803 ;
     RECT  128.496 181.717 129.336 181.803 ;
     RECT  0.192 181.141 2.712 181.813 ;
     RECT  6.816 181.237 8.112 181.813 ;
     RECT  13.2 181.803 13.848 181.813 ;
     RECT  29.4 32.003 29.712 181.813 ;
     RECT  33.6 181.237 33.624 181.813 ;
     RECT  34.8 180.851 35.112 181.813 ;
     RECT  37.536 181.237 37.56 181.813 ;
     RECT  39.312 181.237 40.512 181.813 ;
     RECT  56.448 181.547 56.712 181.813 ;
     RECT  61.8 33.251 62.112 181.813 ;
     RECT  64.368 181.237 64.392 181.813 ;
     RECT  66.096 181.237 66.12 181.813 ;
     RECT  67.2 180.755 67.512 181.813 ;
     RECT  85.44 181.237 85.464 181.813 ;
     RECT  88.8 30.861 89.112 181.813 ;
     RECT  94.2 149.833 94.512 181.813 ;
     RECT  96.864 181.237 96.888 181.813 ;
     RECT  115.8 31.417 116.112 181.813 ;
     RECT  121.2 180.421 121.704 181.813 ;
     RECT  123.648 181.237 123.672 181.813 ;
     RECT  18.192 181.675 18.216 181.867 ;
     RECT  56.448 181.813 67.896 182.341 ;
     RECT  69.168 181.813 70.104 182.341 ;
     RECT  85.008 181.813 98.184 182.341 ;
     RECT  112.656 181.813 126.552 182.483 ;
     RECT  112.656 182.483 126.456 183.019 ;
     RECT  52.368 181.547 52.392 183.531 ;
     RECT  71.712 181.803 71.736 183.531 ;
     RECT  73.488 181.803 73.512 183.531 ;
     RECT  77.472 181.675 77.496 183.531 ;
     RECT  108.288 181.547 108.312 183.531 ;
     RECT  0.192 181.813 13.848 183.568 ;
     RECT  28.32 181.813 41.976 183.568 ;
     RECT  56.448 182.341 70.104 183.568 ;
     RECT  84.576 182.341 98.184 183.568 ;
     RECT  112.656 183.019 126.312 183.568 ;
    LAYER M6 ;
     RECT  2.16 18.729 2.821 19.401 ;
     RECT  2.16 24.129 2.869 24.801 ;
     RECT  2.16 29.529 3.349 30.201 ;
     RECT  3.349 29.529 3.381 30.368 ;
     RECT  2.821 27.52 3.435 27.552 ;
     RECT  2.869 24.129 3.491 25.376 ;
     RECT  3.381 28.992 3.925 30.368 ;
     RECT  3.925 28.992 4.021 31.392 ;
     RECT  4.021 27.776 4.163 31.392 ;
     RECT  4.501 33.088 4.693 33.12 ;
     RECT  4.163 29.529 4.739 31.392 ;
     RECT  3.491 24.129 4.931 25.056 ;
     RECT  2.821 18.432 5.045 19.401 ;
     RECT  5.045 18.432 5.099 19.68 ;
     RECT  3.397 22.144 5.099 22.176 ;
     RECT  5.045 31.552 5.123 31.584 ;
     RECT  5.099 18.729 6.805 19.68 ;
     RECT  2.16 180.729 6.805 181.401 ;
     RECT  4.163 27.776 6.901 27.808 ;
     RECT  4.931 24.129 6.955 24.928 ;
     RECT  6.901 27.584 7.091 27.808 ;
     RECT  4.693 32.896 7.65 33.12 ;
     RECT  2.16 34.929 7.65 35.601 ;
     RECT  6.805 179.904 7.715 181.401 ;
     RECT  7.65 32.896 7.723 35.601 ;
     RECT  7.723 32.896 7.925 33.12 ;
     RECT  7.925 32.768 7.979 33.12 ;
     RECT  7.979 32.768 8.291 32.928 ;
     RECT  7.669 27.904 8.485 27.936 ;
     RECT  2.16 2.529 9.061 3.201 ;
     RECT  4.501 4.672 9.061 4.704 ;
     RECT  6.805 18.729 9.061 20.064 ;
     RECT  8.677 22.656 9.077 22.688 ;
     RECT  9.077 22.208 9.131 22.688 ;
     RECT  4.739 29.529 9.518 30.201 ;
     RECT  8.485 27.584 9.525 27.936 ;
     RECT  9.525 27.328 9.579 27.936 ;
     RECT  9.518 29.312 9.587 30.201 ;
     RECT  9.579 27.328 9.637 27.616 ;
     RECT  9.061 18.176 10.741 20.64 ;
     RECT  7.723 34.929 10.789 35.601 ;
     RECT  10.741 17.024 10.795 20.64 ;
     RECT  10.795 17.024 10.883 17.056 ;
     RECT  8.291 32.768 11.653 32.8 ;
     RECT  11.653 32.768 12.59 32.928 ;
     RECT  9.587 29.376 12.597 30.201 ;
     RECT  12.59 31.936 12.659 32.928 ;
     RECT  9.637 27.072 12.661 27.616 ;
     RECT  12.597 29.376 12.715 30.368 ;
     RECT  6.955 24.129 13.093 24.801 ;
     RECT  13.093 24.129 13.109 25.376 ;
     RECT  12.661 27.072 13.163 27.872 ;
     RECT  10.789 34.929 13.291 36.064 ;
     RECT  7.715 180.729 13.621 181.401 ;
     RECT  12.659 32.448 13.861 32.928 ;
     RECT  13.621 180.608 14.261 181.401 ;
     RECT  14.261 0.576 14.389 0.608 ;
     RECT  9.061 2.529 14.389 4.704 ;
     RECT  14.389 0.576 14.771 4.704 ;
     RECT  9.131 22.208 14.867 22.24 ;
     RECT  14.261 180.608 14.867 181.792 ;
     RECT  12.715 29.529 15.349 30.368 ;
     RECT  13.109 24.129 15.443 25.76 ;
     RECT  13.163 27.84 15.443 27.872 ;
     RECT  14.771 1.152 15.635 4.704 ;
     RECT  13.861 32.448 16.019 33.632 ;
     RECT  14.867 180.729 16.067 181.792 ;
     RECT  15.635 1.152 16.211 1.184 ;
     RECT  14.197 16.832 16.213 16.864 ;
     RECT  15.635 2.529 16.565 4.704 ;
     RECT  16.565 2.529 16.643 5.152 ;
     RECT  16.019 32.448 16.789 33.056 ;
     RECT  16.789 32.384 16.875 33.056 ;
     RECT  16.43 0.576 16.885 0.608 ;
     RECT  15.349 29.529 16.949 30.432 ;
     RECT  16.949 28.992 17.027 30.432 ;
     RECT  16.213 16.768 17.077 16.864 ;
     RECT  15.443 24.129 17.077 24.801 ;
     RECT  16.885 0.192 17.123 0.608 ;
     RECT  17.123 0.32 17.171 0.608 ;
     RECT  17.205 11.776 17.25 11.808 ;
     RECT  17.25 11.776 17.323 11.936 ;
     RECT  16.875 33.024 17.459 33.056 ;
     RECT  17.077 16.768 17.555 16.992 ;
     RECT  16.643 2.529 17.579 4.896 ;
     RECT  17.323 11.776 17.579 11.808 ;
     RECT  10.795 18.729 17.589 20.64 ;
     RECT  17.077 22.848 17.699 24.801 ;
     RECT  17.171 0.576 17.774 0.608 ;
     RECT  17.774 0.576 17.845 1.184 ;
     RECT  17.579 2.529 17.845 4.576 ;
     RECT  16.067 180.729 18.181 181.536 ;
     RECT  18.181 180.729 18.283 181.856 ;
     RECT  17.845 0.576 18.323 4.576 ;
     RECT  18.323 2.304 18.347 4.576 ;
     RECT  17.555 16.832 18.47 16.992 ;
     RECT  18.323 0.576 18.613 0.672 ;
     RECT  18.283 180.729 18.755 181.664 ;
     RECT  18.613 0.512 19.043 0.672 ;
     RECT  19.043 0.576 19.139 0.672 ;
     RECT  17.699 24.129 19.333 24.801 ;
     RECT  17.027 29.529 19.381 30.432 ;
     RECT  13.291 34.929 19.381 35.601 ;
     RECT  19.381 34.688 19.667 35.601 ;
     RECT  18.47 16.832 19.669 16.928 ;
     RECT  18.181 32.768 19.893 32.8 ;
     RECT  19.667 34.816 19.947 35.601 ;
     RECT  19.381 28.352 20.003 30.432 ;
     RECT  18.347 2.304 20.389 4.064 ;
     RECT  20.389 2.304 20.459 4.576 ;
     RECT  19.139 0.576 20.469 0.608 ;
     RECT  17.589 18.729 20.469 20.832 ;
     RECT  20.003 28.48 20.469 30.432 ;
     RECT  19.893 32.448 20.483 32.8 ;
     RECT  20.469 18.729 20.523 20.896 ;
     RECT  20.469 28.48 20.542 30.496 ;
     RECT  20.469 0.192 20.579 0.608 ;
     RECT  19.669 16.704 20.579 16.928 ;
     RECT  20.542 28.48 20.715 30.201 ;
     RECT  20.485 31.936 20.715 31.968 ;
     RECT  18.755 180.729 20.821 181.536 ;
     RECT  20.579 16.704 21.155 16.736 ;
     RECT  20.579 0.576 21.365 0.608 ;
     RECT  20.459 2.304 21.365 3.616 ;
     RECT  21.365 0.576 21.827 3.616 ;
     RECT  21.827 2.529 22.133 3.616 ;
     RECT  19.333 24.129 22.165 25.696 ;
     RECT  21.827 0.576 22.645 0.608 ;
     RECT  20.821 180.729 22.789 181.792 ;
     RECT  22.789 180.608 23.098 181.792 ;
     RECT  22.645 0.192 23.171 0.608 ;
     RECT  22.133 2.529 23.285 4.576 ;
     RECT  23.285 2.529 23.413 5.216 ;
     RECT  22.165 24.129 23.653 25.76 ;
     RECT  23.653 24.129 23.699 26.144 ;
     RECT  20.523 20.8 23.893 20.896 ;
     RECT  20.715 29.376 23.893 30.201 ;
     RECT  23.413 2.304 23.918 5.216 ;
     RECT  23.098 180.608 23.998 181.664 ;
     RECT  23.171 0.192 24.419 0.352 ;
     RECT  23.918 1.728 24.467 5.216 ;
     RECT  23.893 29.376 24.469 30.752 ;
     RECT  24.419 0.32 24.563 0.352 ;
     RECT  19.947 34.929 24.757 35.601 ;
     RECT  24.467 1.728 24.821 3.201 ;
     RECT  24.469 29.376 24.853 31.968 ;
     RECT  24.853 29.376 24.875 30.368 ;
     RECT  24.875 29.376 25.045 30.201 ;
     RECT  23.699 26.112 25.077 26.144 ;
     RECT  25.045 29.312 25.131 30.201 ;
     RECT  23.893 20.8 25.141 21.536 ;
     RECT  23.699 24.129 25.141 24.801 ;
     RECT  25.077 26.112 25.141 27.36 ;
     RECT  25.141 20.8 25.195 21.664 ;
     RECT  25.141 24.129 25.643 27.36 ;
     RECT  24.467 4.544 25.667 5.216 ;
     RECT  24.821 0.576 26.03 3.201 ;
     RECT  20.523 18.729 26.037 19.401 ;
     RECT  23.893 16.512 26.091 16.544 ;
     RECT  26.03 0.576 26.099 3.488 ;
     RECT  25.643 27.328 26.099 27.36 ;
     RECT  26.099 0.576 26.101 3.201 ;
     RECT  25.195 21.504 26.149 21.664 ;
     RECT  26.037 18.368 26.165 19.401 ;
     RECT  26.165 18.368 26.219 20.128 ;
     RECT  26.149 21.504 26.219 22.752 ;
     RECT  25.643 24.129 26.219 24.928 ;
     RECT  26.101 0.192 26.243 3.201 ;
     RECT  23.998 180.608 26.819 181.536 ;
     RECT  26.243 0.576 27.059 3.201 ;
     RECT  25.667 5.184 27.301 5.216 ;
     RECT  27.301 4.544 27.371 5.216 ;
     RECT  24.853 31.936 27.374 31.968 ;
     RECT  25.131 29.376 27.381 30.201 ;
     RECT  27.374 31.936 27.435 33.12 ;
     RECT  27.435 33.088 27.443 33.12 ;
     RECT  26.819 180.729 27.445 181.536 ;
     RECT  27.059 1.728 27.539 3.201 ;
     RECT  27.381 29.376 27.635 30.496 ;
     RECT  27.445 180.729 27.947 181.792 ;
     RECT  27.893 0.064 27.971 0.096 ;
     RECT  26.219 18.729 27.971 20.128 ;
     RECT  27.971 18.729 29.237 19.401 ;
     RECT  29.237 18.368 29.315 19.401 ;
     RECT  27.635 29.376 29.941 30.201 ;
     RECT  29.941 29.376 30.01 31.968 ;
     RECT  30.01 31.936 30.035 31.968 ;
     RECT  26.219 24.129 30.181 24.801 ;
     RECT  27.371 5.184 31.477 5.216 ;
     RECT  29.029 27.328 31.525 27.36 ;
     RECT  31.525 27.328 31.595 27.872 ;
     RECT  30.181 24 31.861 24.801 ;
     RECT  31.595 27.328 31.915 27.36 ;
     RECT  31.477 5.184 32.171 5.92 ;
     RECT  32.101 10.176 32.171 10.208 ;
     RECT  29.315 18.729 32.437 19.401 ;
     RECT  32.389 22.656 32.491 22.688 ;
     RECT  31.861 24 32.491 25.952 ;
     RECT  32.437 18.729 32.501 19.552 ;
     RECT  32.501 18.176 32.531 19.552 ;
     RECT  30.01 29.376 32.531 30.368 ;
     RECT  28.453 15.872 32.555 15.904 ;
     RECT  32.531 18.176 32.675 19.401 ;
     RECT  32.491 24.129 33.203 25.952 ;
     RECT  2.16 13.329 34.165 14.001 ;
     RECT  32.171 5.184 34.453 5.216 ;
     RECT  32.437 10.368 34.805 10.4 ;
     RECT  34.453 4.544 34.859 5.216 ;
     RECT  33.203 24.129 35.125 25.76 ;
     RECT  34.805 10.304 35.173 10.4 ;
     RECT  32.531 29.376 35.173 30.201 ;
     RECT  27.947 180.729 35.173 181.401 ;
     RECT  35.125 24.129 35.179 26.464 ;
     RECT  34.859 5.056 35.219 5.216 ;
     RECT  35.179 24.129 35.219 25.056 ;
     RECT  35.173 10.304 35.221 10.528 ;
     RECT  34.165 12.224 35.365 14.001 ;
     RECT  35.221 10.176 35.371 10.528 ;
     RECT  35.371 10.432 35.435 10.528 ;
     RECT  35.365 11.968 35.435 14.001 ;
     RECT  32.675 18.729 35.829 19.401 ;
     RECT  34.693 21.12 35.829 21.152 ;
     RECT  35.435 10.496 35.883 10.528 ;
     RECT  35.829 18.729 35.902 21.152 ;
     RECT  34.165 31.68 36.421 31.712 ;
     RECT  36.421 31.68 36.467 32.8 ;
     RECT  35.179 26.432 36.995 26.464 ;
     RECT  35.902 21.12 37.333 21.152 ;
     RECT  35.173 28.928 37.355 30.201 ;
     RECT  35.902 18.729 37.365 19.401 ;
     RECT  37.333 21.12 37.419 22.304 ;
     RECT  37.365 18.729 37.475 19.744 ;
     RECT  35.219 5.184 37.667 5.216 ;
     RECT  2.16 148.329 38.725 149.001 ;
     RECT  36.997 26.816 39.395 26.848 ;
     RECT  35.173 180.608 39.395 181.401 ;
     RECT  36.467 32.768 39.923 32.8 ;
     RECT  37.475 18.729 40.981 19.401 ;
     RECT  35.219 24.129 40.981 24.801 ;
     RECT  38.725 16.32 41.013 16.352 ;
     RECT  41.013 16.32 41.067 16.48 ;
     RECT  40.981 18.729 41.067 19.552 ;
     RECT  41.067 16.448 41.219 16.48 ;
     RECT  39.301 21.632 41.269 21.664 ;
     RECT  40.981 23.936 41.269 24.801 ;
     RECT  41.269 21.632 41.315 24.801 ;
     RECT  41.315 22.208 41.338 24.801 ;
     RECT  27.539 2.529 41.525 3.201 ;
     RECT  37.355 29.529 42.277 30.201 ;
     RECT  42.133 26.688 42.293 26.72 ;
     RECT  42.293 26.496 42.347 26.72 ;
     RECT  42.277 29.376 42.347 30.201 ;
     RECT  41.525 2.529 42.35 3.488 ;
     RECT  39.877 5.056 42.35 5.088 ;
     RECT  39.395 180.729 42.357 181.401 ;
     RECT  42.35 2.529 42.411 5.088 ;
     RECT  42.411 2.529 42.419 4.576 ;
     RECT  42.419 2.529 42.805 3.201 ;
     RECT  42.421 0.576 42.869 0.608 ;
     RECT  42.805 2.304 42.869 3.201 ;
     RECT  42.869 0.576 42.899 3.201 ;
     RECT  42.419 4.544 43.331 4.576 ;
     RECT  42.899 0.576 43.701 1.184 ;
     RECT  43.701 0.32 43.765 1.184 ;
     RECT  43.765 0.192 44.003 1.184 ;
     RECT  42.899 2.529 44.078 3.201 ;
     RECT  44.003 0.576 44.243 1.184 ;
     RECT  44.078 2.529 44.533 3.488 ;
     RECT  42.347 26.496 44.533 26.528 ;
     RECT  44.533 26.496 44.587 27.424 ;
     RECT  44.587 26.688 44.627 27.424 ;
     RECT  42.347 29.529 44.981 30.201 ;
     RECT  44.965 33.088 45.035 33.12 ;
     RECT  44.981 29.529 45.395 31.008 ;
     RECT  45.493 0.192 45.877 0.224 ;
     RECT  44.533 1.728 45.877 3.488 ;
     RECT  41.338 23.232 45.973 24.801 ;
     RECT  44.627 26.688 46.019 26.72 ;
     RECT  45.973 22.208 46.059 24.801 ;
     RECT  41.067 18.729 46.117 19.401 ;
     RECT  24.757 34.624 46.597 35.601 ;
     RECT  2.16 121.329 46.597 122.001 ;
     RECT  45.877 0.192 46.693 3.488 ;
     RECT  46.693 0.192 46.763 4.576 ;
     RECT  42.357 180.729 46.766 181.536 ;
     RECT  46.597 34.368 46.958 35.601 ;
     RECT  2.16 7.929 46.965 8.601 ;
     RECT  35.435 12.224 47.019 14.001 ;
     RECT  38.725 148.032 47.019 149.001 ;
     RECT  46.958 34.24 47.027 35.601 ;
     RECT  46.958 150.528 47.027 150.56 ;
     RECT  42.357 6.528 47.125 6.56 ;
     RECT  46.965 7.929 47.125 9.056 ;
     RECT  46.763 0.192 47.221 3.36 ;
     RECT  47.221 0.064 47.363 3.36 ;
     RECT  45.395 29.529 47.989 30.88 ;
     RECT  47.125 6.528 48.117 9.056 ;
     RECT  48.117 6.528 48.171 9.76 ;
     RECT  44.437 15.488 48.309 15.52 ;
     RECT  48.309 15.488 48.363 16.736 ;
     RECT  46.117 18.624 48.363 19.401 ;
     RECT  48.171 6.72 48.419 9.76 ;
     RECT  48.363 16.704 48.419 16.736 ;
     RECT  46.766 180.729 48.421 181.792 ;
     RECT  48.419 6.72 48.515 8.928 ;
     RECT  47.363 0.576 48.563 3.36 ;
     RECT  48.421 180.608 48.563 181.792 ;
     RECT  48.563 180.608 48.565 181.536 ;
     RECT  47.989 29.376 48.619 30.88 ;
     RECT  47.029 150.912 48.619 150.944 ;
     RECT  48.565 32.96 48.755 32.992 ;
     RECT  48.563 2.529 48.821 3.36 ;
     RECT  48.563 0.576 48.949 1.184 ;
     RECT  48.949 0.064 49.043 1.184 ;
     RECT  49.043 0.576 49.475 1.184 ;
     RECT  48.363 18.729 49.525 19.401 ;
     RECT  48.515 7.929 49.667 8.928 ;
     RECT  48.821 2.529 49.811 3.488 ;
     RECT  48.619 29.529 50.005 30.88 ;
     RECT  2.16 83.529 50.037 84.201 ;
     RECT  46.059 23.296 50.091 24.801 ;
     RECT  50.037 83.529 50.101 84.896 ;
     RECT  46.597 120.768 50.165 122.001 ;
     RECT  48.517 27.328 50.195 27.36 ;
     RECT  49.475 1.152 50.293 1.184 ;
     RECT  49.811 2.529 50.293 3.201 ;
     RECT  50.466 119.104 50.539 119.136 ;
     RECT  50.005 5.696 50.549 5.728 ;
     RECT  50.293 1.152 50.819 3.201 ;
     RECT  50.819 2.304 51.051 3.201 ;
     RECT  48.565 179.904 51.125 181.536 ;
     RECT  51.125 179.904 51.203 181.6 ;
     RECT  51.051 2.529 51.445 3.201 ;
     RECT  50.549 4.544 51.445 5.728 ;
     RECT  51.125 0.576 51.573 0.608 ;
     RECT  49.667 7.929 51.573 8.736 ;
     RECT  51.445 2.529 51.627 5.728 ;
     RECT  51.573 7.929 51.755 9.184 ;
     RECT  49.525 18.729 51.755 19.552 ;
     RECT  51.573 0.064 51.923 0.608 ;
     RECT  50.101 83.529 52.149 85.152 ;
     RECT  52.149 83.529 52.203 85.6 ;
     RECT  51.701 15.424 52.307 16.032 ;
     RECT  52.203 85.568 52.331 85.6 ;
     RECT  52.261 118.592 52.331 118.624 ;
     RECT  51.923 0.576 52.469 0.608 ;
     RECT  52.357 183.488 52.523 183.52 ;
     RECT  52.469 0.576 52.547 1.184 ;
     RECT  51.627 2.529 52.787 4.576 ;
     RECT  50.091 23.488 53.173 24.801 ;
     RECT  50.005 29.529 53.173 31.072 ;
     RECT  53.173 29.056 53.242 31.072 ;
     RECT  51.755 7.929 53.291 8.736 ;
     RECT  52.547 0.576 53.365 0.608 ;
     RECT  51.203 179.904 53.365 181.536 ;
     RECT  53.365 179.904 53.434 181.792 ;
     RECT  53.173 23.36 53.493 24.801 ;
     RECT  53.493 22.656 53.547 24.801 ;
     RECT  52.787 2.529 53.557 4.128 ;
     RECT  53.557 2.304 53.651 4.128 ;
     RECT  51.755 18.729 53.653 19.401 ;
     RECT  53.547 22.656 53.685 22.688 ;
     RECT  53.653 18.729 53.739 19.936 ;
     RECT  53.685 22.208 53.795 22.688 ;
     RECT  53.365 0.064 54.254 0.608 ;
     RECT  53.547 24.129 54.661 24.801 ;
     RECT  52.307 16 54.755 16.032 ;
     RECT  53.795 22.208 55.237 22.24 ;
     RECT  53.242 29.529 55.237 31.072 ;
     RECT  55.237 21.952 55.283 22.24 ;
     RECT  54.254 0.064 55.427 1.184 ;
     RECT  55.427 1.152 55.541 1.184 ;
     RECT  53.651 2.529 55.541 4.128 ;
     RECT  55.541 1.152 55.619 4.128 ;
     RECT  55.141 27.264 55.813 27.296 ;
     RECT  55.237 29.529 55.813 31.392 ;
     RECT  55.619 1.152 56.051 1.184 ;
     RECT  53.434 179.904 56.099 181.536 ;
     RECT  47.027 34.368 56.757 35.601 ;
     RECT  56.757 34.24 56.83 35.601 ;
     RECT  53.739 18.729 56.949 19.401 ;
     RECT  56.949 18.432 57.022 19.401 ;
     RECT  56.099 179.904 57.059 181.401 ;
     RECT  55.283 21.952 57.251 21.984 ;
     RECT  55.813 27.264 57.451 31.392 ;
     RECT  55.619 2.529 57.635 4.128 ;
     RECT  54.661 24.129 57.653 25.184 ;
     RECT  57.653 24.129 57.835 25.696 ;
     RECT  57.451 27.264 57.835 31.072 ;
     RECT  57.059 180.729 58.645 181.401 ;
     RECT  57.835 24.129 58.691 25.056 ;
     RECT  56.949 17.024 58.835 17.056 ;
     RECT  58.645 179.52 59.459 181.401 ;
     RECT  53.797 85.632 60.139 85.664 ;
     RECT  57.022 18.729 60.565 19.401 ;
     RECT  57.541 22.016 60.59 22.752 ;
     RECT  58.691 24.129 60.59 24.801 ;
     RECT  60.565 18.729 60.651 20.512 ;
     RECT  60.59 22.016 60.651 24.801 ;
     RECT  57.835 28.928 60.707 31.072 ;
     RECT  60.707 29.376 61.043 31.072 ;
     RECT  60.949 16.512 62.133 16.544 ;
     RECT  62.133 16.512 62.187 17.312 ;
     RECT  62.187 16.832 62.243 17.312 ;
     RECT  60.085 6.208 62.771 6.24 ;
     RECT  60.651 23.296 62.946 24.801 ;
     RECT  62.946 23.296 62.965 25.056 ;
     RECT  57.835 27.264 62.965 27.296 ;
     RECT  62.965 22.848 63.019 27.296 ;
     RECT  56.83 34.368 63.061 35.601 ;
     RECT  61.043 29.376 63.093 30.201 ;
     RECT  63.061 33.152 63.093 35.601 ;
     RECT  63.093 29.376 63.147 30.368 ;
     RECT  63.093 33.152 63.147 35.744 ;
     RECT  63.147 29.529 63.166 30.368 ;
     RECT  2.16 56.529 63.877 57.201 ;
     RECT  63.147 34.368 64.299 35.744 ;
     RECT  62.243 16.832 64.451 16.864 ;
     RECT  63.019 22.848 64.451 24.801 ;
     RECT  64.299 34.624 64.451 35.744 ;
     RECT  63.019 26.112 64.739 27.296 ;
     RECT  2.16 88.929 64.757 89.601 ;
     RECT  64.741 6.208 64.811 6.24 ;
     RECT  64.501 16.768 64.811 16.8 ;
     RECT  64.741 91.84 64.811 91.872 ;
     RECT  59.459 180.729 64.933 181.401 ;
     RECT  60.651 18.729 66.085 19.401 ;
     RECT  2.16 126.729 66.277 127.401 ;
     RECT  64.739 27.264 66.293 27.296 ;
     RECT  63.166 29.529 66.293 30.201 ;
     RECT  63.877 56.529 66.347 57.568 ;
     RECT  66.277 91.968 66.347 92 ;
     RECT  66.277 125.44 66.347 127.401 ;
     RECT  64.451 24.129 66.594 24.801 ;
     RECT  66.594 24.129 66.667 25.952 ;
     RECT  64.933 179.584 66.755 181.401 ;
     RECT  50.165 120.512 67.307 122.001 ;
     RECT  66.347 126.729 67.669 127.401 ;
     RECT  67.669 125.44 67.755 127.401 ;
     RECT  66.085 17.344 68.085 17.376 ;
     RECT  66.085 18.729 68.085 20.384 ;
     RECT  66.085 31.68 68.099 31.712 ;
     RECT  57.635 2.529 68.101 3.201 ;
     RECT  68.085 17.344 68.139 20.384 ;
     RECT  68.101 2.529 68.203 4.32 ;
     RECT  68.139 17.792 68.213 20.384 ;
     RECT  68.213 17.792 68.267 20.576 ;
     RECT  66.667 24.129 68.917 24.801 ;
     RECT  68.917 22.848 68.986 24.801 ;
     RECT  68.203 2.529 69.109 3.201 ;
     RECT  69.109 1.728 69.203 3.201 ;
     RECT  53.291 7.929 69.493 8.601 ;
     RECT  69.493 7.424 69.562 8.601 ;
     RECT  68.267 18.729 70.069 20.576 ;
     RECT  70.382 1.152 70.453 1.184 ;
     RECT  66.755 179.904 70.453 181.401 ;
     RECT  70.453 0.192 70.739 1.184 ;
     RECT  66.293 27.264 70.766 30.201 ;
     RECT  70.766 26.176 70.835 30.201 ;
     RECT  69.562 7.808 71.315 8.601 ;
     RECT  71.221 4.544 71.747 4.576 ;
     RECT  70.739 0.576 71.797 1.184 ;
     RECT  69.203 2.529 71.797 3.201 ;
     RECT  71.701 183.488 71.851 183.52 ;
     RECT  71.797 0.576 71.891 3.201 ;
     RECT  70.835 27.264 72.083 30.201 ;
     RECT  71.891 0.576 72.117 1.184 ;
     RECT  70.453 179.904 72.229 181.536 ;
     RECT  72.117 0.192 72.245 1.184 ;
     RECT  64.757 88.704 72.245 89.601 ;
     RECT  72.083 28.864 72.299 30.201 ;
     RECT  72.229 179.904 72.299 181.792 ;
     RECT  72.245 0.064 72.419 1.184 ;
     RECT  72.419 0.192 72.467 1.184 ;
     RECT  71.891 2.529 72.469 3.201 ;
     RECT  72.299 179.904 72.766 181.664 ;
     RECT  70.069 18.729 72.997 20.64 ;
     RECT  72.469 2.529 73.397 3.424 ;
     RECT  73.397 2.529 73.475 4.576 ;
     RECT  68.986 24.129 73.477 24.801 ;
     RECT  72.467 0.576 73.589 1.184 ;
     RECT  73.475 2.529 73.589 4.32 ;
     RECT  73.477 183.488 73.643 183.52 ;
     RECT  73.589 0.576 73.973 4.32 ;
     RECT  70.069 15.744 74.082 15.776 ;
     RECT  74.082 15.744 74.155 17.056 ;
     RECT  72.997 18.729 74.229 20.704 ;
     RECT  74.155 17.024 74.283 17.056 ;
     RECT  73.477 23.936 74.357 24.801 ;
     RECT  74.229 18.624 74.411 20.704 ;
     RECT  74.357 22.72 74.411 24.801 ;
     RECT  72.766 179.904 74.414 181.536 ;
     RECT  73.973 0.064 74.483 4.32 ;
     RECT  74.414 179.904 74.483 181.792 ;
     RECT  74.411 24.129 74.629 24.801 ;
     RECT  74.483 1.728 75.125 4.32 ;
     RECT  75.125 1.728 75.203 4.576 ;
     RECT  74.411 18.624 75.299 19.401 ;
     RECT  75.203 1.728 75.587 4.128 ;
     RECT  74.411 22.72 75.875 22.752 ;
     RECT  74.483 0.064 75.923 0.096 ;
     RECT  72.083 27.264 76.021 27.296 ;
     RECT  72.299 28.992 76.021 30.201 ;
     RECT  76.002 32.384 76.021 32.416 ;
     RECT  76.021 27.264 76.075 30.201 ;
     RECT  76.021 32.384 76.075 33.248 ;
     RECT  74.629 24.129 76.395 25.504 ;
     RECT  76.075 27.264 76.395 27.936 ;
     RECT  76.213 0.576 77.045 1.184 ;
     RECT  75.587 2.529 77.045 4.128 ;
     RECT  77.045 0.576 77.123 4.128 ;
     RECT  76.075 33.216 77.171 33.248 ;
     RECT  77.461 183.488 77.547 183.52 ;
     RECT  74.483 179.904 77.922 181.536 ;
     RECT  77.123 0.576 78.133 0.608 ;
     RECT  75.299 18.729 78.197 19.401 ;
     RECT  77.893 21.696 78.251 21.728 ;
     RECT  76.357 15.936 78.325 15.968 ;
     RECT  71.315 7.929 78.373 8.601 ;
     RECT  78.373 7.04 78.389 8.736 ;
     RECT  78.325 15.936 78.419 17.056 ;
     RECT  77.123 2.304 78.498 4.128 ;
     RECT  78.498 2.304 78.571 5.152 ;
     RECT  78.389 7.04 78.571 10.016 ;
     RECT  78.419 15.936 78.571 15.968 ;
     RECT  76.395 27.264 78.613 27.296 ;
     RECT  78.571 2.304 78.659 4.576 ;
     RECT  78.133 0.064 78.707 0.608 ;
     RECT  78.571 7.929 78.707 10.016 ;
     RECT  77.922 179.904 78.805 181.664 ;
     RECT  76.395 24.129 78.899 25.056 ;
     RECT  78.707 0.576 78.965 0.608 ;
     RECT  78.659 2.304 78.965 3.201 ;
     RECT  78.965 0.576 79.043 3.201 ;
     RECT  78.805 179.904 79.354 181.792 ;
     RECT  78.197 18.729 79.859 19.808 ;
     RECT  78.613 27.264 80.174 27.616 ;
     RECT  79.043 0.576 80.181 1.184 ;
     RECT  80.174 26.176 80.243 27.616 ;
     RECT  78.659 4.544 80.339 4.576 ;
     RECT  80.181 0.192 80.435 1.184 ;
     RECT  80.435 0.64 80.558 1.184 ;
     RECT  79.043 2.529 80.558 3.201 ;
     RECT  80.558 0.64 80.693 3.201 ;
     RECT  76.075 29.529 80.869 30.201 ;
     RECT  80.243 27.264 80.885 27.616 ;
     RECT  80.869 29.376 80.885 30.201 ;
     RECT  80.885 27.264 80.917 30.201 ;
     RECT  79.189 31.872 80.917 31.904 ;
     RECT  80.917 27.264 80.939 31.904 ;
     RECT  80.939 28.608 81.259 31.904 ;
     RECT  64.451 34.624 81.349 35.601 ;
     RECT  78.899 24.129 81.445 24.801 ;
     RECT  81.259 31.872 81.461 31.904 ;
     RECT  81.461 31.872 81.515 32.16 ;
     RECT  81.349 33.984 81.515 35.601 ;
     RECT  81.259 28.608 81.683 30.201 ;
     RECT  81.515 34.624 81.731 35.601 ;
     RECT  80.693 0.64 81.973 4.512 ;
     RECT  81.973 0.64 82.067 4.64 ;
     RECT  82.067 0.64 82.357 4.512 ;
     RECT  81.445 17.024 82.357 17.056 ;
     RECT  79.859 18.729 82.357 19.401 ;
     RECT  82.357 0.576 82.451 4.512 ;
     RECT  81.445 22.848 82.475 24.801 ;
     RECT  78.707 9.984 82.549 10.016 ;
     RECT  81.515 32.128 82.595 32.16 ;
     RECT  82.451 1.728 82.603 4.512 ;
     RECT  82.421 20.736 82.603 20.768 ;
     RECT  81.683 29.529 82.645 30.201 ;
     RECT  82.357 17.024 82.667 19.401 ;
     RECT  82.549 9.984 83.077 11.36 ;
     RECT  81.731 34.929 83.125 35.601 ;
     RECT  83.125 34.24 83.194 35.601 ;
     RECT  72.245 87.808 83.253 89.601 ;
     RECT  67.307 121.024 83.269 122.001 ;
     RECT  79.354 179.904 83.269 181.536 ;
     RECT  82.603 1.728 83.315 3.201 ;
     RECT  83.253 87.168 83.326 89.601 ;
     RECT  83.125 15.424 83.445 15.456 ;
     RECT  83.077 9.92 83.499 11.36 ;
     RECT  82.667 17.6 83.499 19.401 ;
     RECT  83.326 87.808 83.755 89.601 ;
     RECT  83.269 120.832 83.755 122.001 ;
     RECT  83.637 0.064 83.843 0.096 ;
     RECT  83.445 15.424 83.939 16.224 ;
     RECT  83.269 179.584 84.139 181.536 ;
     RECT  84.085 0.576 84.179 0.608 ;
     RECT  80.939 27.264 84.277 27.296 ;
     RECT  82.475 23.744 84.331 24.801 ;
     RECT  84.085 6.208 84.341 6.24 ;
     RECT  84.277 26.24 84.346 27.296 ;
     RECT  84.341 5.696 84.395 6.24 ;
     RECT  83.499 9.92 84.395 10.336 ;
     RECT  84.395 10.304 84.419 10.336 ;
     RECT  83.315 2.529 84.597 3.201 ;
     RECT  84.395 5.696 84.651 5.728 ;
     RECT  83.194 34.816 84.981 35.601 ;
     RECT  84.949 86.656 85.035 86.688 ;
     RECT  84.139 179.584 85.035 181.401 ;
     RECT  84.901 152.192 85.093 152.224 ;
     RECT  2.16 153.729 85.093 154.401 ;
     RECT  85.093 152.192 85.163 154.401 ;
     RECT  85.035 179.904 85.163 181.401 ;
     RECT  84.331 24 85.173 24.801 ;
     RECT  84.981 34.752 85.227 35.601 ;
     RECT  82.645 29.529 85.765 30.368 ;
     RECT  83.755 121.024 86.723 122.001 ;
     RECT  47.019 148.329 86.901 149.001 ;
     RECT  85.163 152.192 86.955 152.224 ;
     RECT  86.723 121.329 87.013 122.001 ;
     RECT  87.013 121.329 87.083 122.144 ;
     RECT  86.901 148.329 87.083 149.92 ;
     RECT  83.499 18.729 87.207 19.401 ;
     RECT  85.477 21.184 87.207 21.216 ;
     RECT  86.677 16.96 87.221 16.992 ;
     RECT  87.207 18.729 87.221 21.216 ;
     RECT  87.221 16.96 87.275 21.216 ;
     RECT  84.346 27.264 87.493 27.296 ;
     RECT  87.275 18.176 87.531 21.216 ;
     RECT  85.173 24 87.827 24.928 ;
     RECT  85.765 29.529 87.827 30.88 ;
     RECT  87.827 24.129 88.165 24.928 ;
     RECT  87.493 26.816 88.165 27.296 ;
     RECT  88.165 24.129 88.235 27.296 ;
     RECT  87.827 29.529 89.269 30.816 ;
     RECT  89.269 29.376 89.323 30.816 ;
     RECT  84.597 2.368 89.555 3.201 ;
     RECT  88.235 26.816 89.973 27.296 ;
     RECT  89.323 29.376 90.027 30.201 ;
     RECT  87.531 18.176 90.083 19.401 ;
     RECT  83.939 15.424 90.565 15.456 ;
     RECT  87.531 21.184 90.659 21.216 ;
     RECT  89.973 26.304 90.659 27.296 ;
     RECT  85.109 178.56 91.235 178.592 ;
     RECT  90.565 15.424 92.341 16.032 ;
     RECT  92.341 15.424 92.395 17.056 ;
     RECT  92.395 17.024 92.581 17.056 ;
     RECT  90.083 18.729 92.581 19.401 ;
     RECT  88.235 24.129 92.869 24.801 ;
     RECT  92.005 5.12 92.963 5.152 ;
     RECT  90.027 29.529 93.157 30.201 ;
     RECT  92.581 17.024 93.429 19.401 ;
     RECT  92.869 23.36 93.429 24.801 ;
     RECT  93.429 17.024 93.483 20.512 ;
     RECT  93.483 18.729 93.502 20.512 ;
     RECT  92.293 31.616 93.875 31.648 ;
     RECT  78.707 7.929 94.021 8.601 ;
     RECT  94.021 7.929 94.069 8.736 ;
     RECT  92.395 15.424 94.069 15.456 ;
     RECT  93.483 17.024 94.069 17.056 ;
     RECT  94.069 15.424 94.115 17.056 ;
     RECT  93.429 23.168 94.115 24.801 ;
     RECT  94.069 5.056 94.261 5.088 ;
     RECT  94.261 5.056 94.315 6.176 ;
     RECT  94.069 7.929 94.315 8.928 ;
     RECT  94.115 15.424 94.315 16.608 ;
     RECT  87.083 148.329 94.574 149.408 ;
     RECT  94.574 148.329 94.643 149.792 ;
     RECT  94.115 23.296 94.691 24.801 ;
     RECT  94.315 6.144 94.787 6.176 ;
     RECT  93.502 18.729 95.701 19.401 ;
     RECT  89.555 2.529 96.629 3.201 ;
     RECT  90.659 27.264 96.853 27.296 ;
     RECT  94.315 15.424 96.947 15.456 ;
     RECT  95.701 18.729 96.949 19.552 ;
     RECT  96.949 18.624 97.003 19.552 ;
     RECT  96.949 21.12 97.018 21.152 ;
     RECT  94.315 7.929 97.141 8.736 ;
     RECT  96.997 4.864 97.195 4.896 ;
     RECT  96.037 6.464 97.195 6.496 ;
     RECT  97.141 7.929 97.429 9.76 ;
     RECT  93.157 29.248 97.429 30.201 ;
     RECT  96.629 2.529 97.525 3.488 ;
     RECT  97.525 2.529 97.619 4.064 ;
     RECT  97.429 7.929 98.099 10.528 ;
     RECT  85.163 180.729 98.613 181.401 ;
     RECT  98.099 10.496 98.629 10.528 ;
     RECT  97.429 29.184 98.667 30.201 ;
     RECT  98.667 29.248 98.675 30.201 ;
     RECT  98.613 0.576 98.686 0.608 ;
     RECT  97.003 18.624 98.709 19.401 ;
     RECT  94.691 24.129 98.725 24.801 ;
     RECT  98.725 23.936 98.795 24.801 ;
     RECT  97.619 2.529 98.798 3.488 ;
     RECT  97.429 16.512 98.869 16.544 ;
     RECT  96.853 26.688 98.869 27.296 ;
     RECT  85.227 34.816 98.923 35.601 ;
     RECT  98.869 15.424 98.938 17.056 ;
     RECT  98.629 10.496 98.987 10.592 ;
     RECT  98.938 16.512 98.987 17.056 ;
     RECT  98.675 29.376 99.125 30.201 ;
     RECT  96.853 32.448 99.179 32.48 ;
     RECT  99.125 29.376 99.203 30.752 ;
     RECT  98.099 7.929 99.445 8.736 ;
     RECT  99.445 6.784 99.499 8.736 ;
     RECT  99.445 5.056 99.539 5.088 ;
     RECT  98.798 1.728 99.691 3.488 ;
     RECT  98.613 180.729 99.947 181.792 ;
     RECT  99.509 0.064 100.019 0.096 ;
     RECT  98.987 16.64 100.163 17.056 ;
     RECT  98.741 21.824 100.309 21.856 ;
     RECT  99.691 1.728 100.334 3.201 ;
     RECT  100.163 17.024 100.355 17.056 ;
     RECT  100.309 21.824 100.355 22.176 ;
     RECT  100.334 0.576 100.883 3.201 ;
     RECT  100.085 4.544 101.459 4.576 ;
     RECT  100.883 1.152 101.813 3.201 ;
     RECT  101.813 1.152 102.227 3.488 ;
     RECT  102.373 31.808 102.389 31.84 ;
     RECT  102.389 31.808 102.443 32.736 ;
     RECT  100.355 22.144 102.659 22.176 ;
     RECT  99.203 29.376 102.947 30.201 ;
     RECT  98.709 18.729 103.157 19.401 ;
     RECT  102.949 22.208 103.157 22.24 ;
     RECT  102.227 1.728 103.162 3.488 ;
     RECT  103.157 22.208 103.211 22.496 ;
     RECT  103.157 18.729 103.531 19.936 ;
     RECT  98.795 24.129 103.717 24.801 ;
     RECT  98.869 26.496 103.717 27.296 ;
     RECT  102.965 0.064 103.811 0.096 ;
     RECT  103.162 1.728 103.925 3.201 ;
     RECT  103.925 0.192 104.003 3.201 ;
     RECT  102.443 32.704 104.339 32.736 ;
     RECT  104.003 1.728 104.387 3.201 ;
     RECT  104.387 2.529 104.821 3.201 ;
     RECT  104.366 4.544 104.821 4.576 ;
     RECT  103.211 22.464 104.821 22.496 ;
     RECT  104.821 22.208 104.89 22.496 ;
     RECT  103.189 16.704 104.915 16.736 ;
     RECT  104.821 2.529 105.141 4.576 ;
     RECT  99.499 6.784 105.141 8.601 ;
     RECT  98.987 10.496 105.195 10.528 ;
     RECT  99.947 180.729 105.205 181.536 ;
     RECT  105.205 180.729 105.274 181.792 ;
     RECT  102.947 29.529 105.397 30.201 ;
     RECT  105.141 2.529 105.443 8.601 ;
     RECT  105.443 2.529 105.71 4.064 ;
     RECT  103.717 24.129 106.037 27.296 ;
     RECT  105.397 29.376 106.091 30.201 ;
     RECT  105.71 1.728 106.163 4.064 ;
     RECT  104.89 22.464 106.293 22.496 ;
     RECT  106.037 24.129 106.293 27.36 ;
     RECT  106.293 21.696 106.347 22.496 ;
     RECT  106.293 24 106.347 27.36 ;
     RECT  106.347 21.696 106.366 22.176 ;
     RECT  106.347 24 106.643 24.801 ;
     RECT  103.531 18.729 106.914 19.401 ;
     RECT  106.366 21.696 106.914 21.728 ;
     RECT  105.274 180.729 106.933 181.536 ;
     RECT  106.914 18.729 106.987 21.728 ;
     RECT  106.933 180.729 107.002 181.792 ;
     RECT  106.163 1.728 107.027 3.488 ;
     RECT  106.987 21.696 107.219 21.728 ;
     RECT  106.091 29.529 107.269 30.201 ;
     RECT  104.003 0.192 107.438 0.224 ;
     RECT  107.438 0.192 108.341 1.184 ;
     RECT  107.027 2.529 108.341 3.488 ;
     RECT  108.277 183.488 108.346 183.52 ;
     RECT  98.923 34.929 108.533 35.601 ;
     RECT  106.347 26.432 108.587 27.296 ;
     RECT  108.587 26.432 108.851 26.72 ;
     RECT  108.341 0.192 108.899 3.488 ;
     RECT  94.581 179.328 109.141 179.36 ;
     RECT  107.002 180.729 109.141 181.536 ;
     RECT  109.141 179.328 109.173 181.536 ;
     RECT  109.173 178.816 109.227 181.536 ;
     RECT  105.443 5.632 109.941 8.601 ;
     RECT  109.941 5.184 110.014 8.601 ;
     RECT  108.899 0.576 110.099 3.488 ;
     RECT  108.805 32.896 110.291 32.928 ;
     RECT  110.099 2.529 110.293 3.488 ;
     RECT  110.014 5.184 110.293 5.216 ;
     RECT  109.227 180.729 110.341 181.536 ;
     RECT  110.099 0.576 110.453 1.184 ;
     RECT  107.269 29.529 110.581 30.496 ;
     RECT  110.453 0.064 110.819 1.184 ;
     RECT  110.293 2.529 110.819 5.216 ;
     RECT  110.581 29.529 110.837 30.624 ;
     RECT  108.851 26.688 110.891 26.72 ;
     RECT  110.819 0.576 110.963 1.184 ;
     RECT  106.643 24.129 111.109 24.801 ;
     RECT  110.837 29.312 111.403 30.624 ;
     RECT  106.987 18.729 111.413 19.401 ;
     RECT  110.963 1.152 111.443 1.184 ;
     RECT  111.397 22.272 111.467 22.304 ;
     RECT  111.413 18.729 111.491 19.936 ;
     RECT  108.229 17.024 111.531 17.056 ;
     RECT  111.491 18.729 111.531 19.552 ;
     RECT  111.403 29.312 111.541 30.496 ;
     RECT  111.109 24.129 111.595 25.056 ;
     RECT  111.541 29.248 111.595 30.496 ;
     RECT  111.541 26.816 111.635 26.848 ;
     RECT  110.341 180.729 111.781 181.664 ;
     RECT  110.819 2.529 111.797 3.201 ;
     RECT  111.781 180.729 111.851 181.792 ;
     RECT  111.797 1.728 111.875 3.201 ;
     RECT  111.851 180.729 112.299 181.536 ;
     RECT  112.245 0.064 112.355 0.096 ;
     RECT  111.875 2.529 113.317 3.201 ;
     RECT  110.819 5.184 113.317 5.216 ;
     RECT  111.349 32.384 113.459 32.416 ;
     RECT  111.595 29.248 113.747 30.201 ;
     RECT  113.317 2.529 114.046 5.216 ;
     RECT  111.685 16.832 114.402 16.864 ;
     RECT  111.531 18.729 114.402 19.401 ;
     RECT  114.402 16.832 114.475 19.401 ;
     RECT  111.595 24.129 114.517 24.801 ;
     RECT  110.014 6.784 114.611 8.601 ;
     RECT  113.747 29.312 115.189 30.201 ;
     RECT  115.189 28.544 115.258 30.201 ;
     RECT  114.475 16.832 115.715 16.864 ;
     RECT  115.189 26.176 115.755 26.208 ;
     RECT  114.517 23.872 116.075 24.801 ;
     RECT  114.475 18.729 116.197 19.401 ;
     RECT  116.197 18.729 116.267 20.512 ;
     RECT  114.046 5.184 116.339 5.216 ;
     RECT  114.046 2.529 116.725 3.201 ;
     RECT  116.677 5.12 116.725 5.152 ;
     RECT  116.725 2.529 116.779 5.152 ;
     RECT  115.258 29.312 116.821 30.201 ;
     RECT  108.533 34.816 117.925 35.601 ;
     RECT  116.267 18.729 118.165 19.401 ;
     RECT  118.242 32.96 118.315 32.992 ;
     RECT  117.925 34.816 118.355 35.744 ;
     RECT  118.165 17.6 118.837 19.401 ;
     RECT  118.837 17.6 118.891 19.552 ;
     RECT  118.891 18.729 118.901 19.552 ;
     RECT  116.021 22.4 118.901 22.432 ;
     RECT  116.075 24.129 118.901 24.801 ;
     RECT  118.901 22.4 118.955 24.801 ;
     RECT  118.901 18.729 118.979 19.872 ;
     RECT  118.955 22.72 119.038 24.801 ;
     RECT  116.821 29.312 120.949 31.392 ;
     RECT  118.355 34.929 121.397 35.744 ;
     RECT  120.949 29.312 121.451 32.48 ;
     RECT  121.397 34.24 121.619 35.744 ;
     RECT  121.451 29.312 122.003 30.496 ;
     RECT  121.619 34.929 122.533 35.744 ;
     RECT  117.925 27.328 122.581 27.36 ;
     RECT  119.038 24.129 122.773 24.801 ;
     RECT  122.581 27.328 123.115 27.872 ;
     RECT  109.227 178.816 123.731 178.848 ;
     RECT  116.779 2.529 124.165 4.384 ;
     RECT  124.165 2.529 124.267 4.576 ;
     RECT  122.003 29.529 124.651 30.496 ;
     RECT  124.549 32.832 124.651 32.864 ;
     RECT  124.597 0.192 124.666 0.224 ;
     RECT  124.267 2.529 125.029 4.384 ;
     RECT  125.029 2.304 125.123 4.384 ;
     RECT  112.299 180.729 125.125 181.401 ;
     RECT  119.038 22.72 125.459 22.752 ;
     RECT  123.115 27.84 125.459 27.872 ;
     RECT  124.651 29.529 125.459 30.368 ;
     RECT  125.123 2.304 125.461 3.36 ;
     RECT  122.773 24.129 125.555 25.056 ;
     RECT  122.533 34.929 125.675 35.872 ;
     RECT  125.125 180.729 126.421 182.368 ;
     RECT  125.621 107.2 126.515 107.232 ;
     RECT  126.421 180.729 126.763 183.008 ;
     RECT  125.461 1.728 126.773 3.36 ;
     RECT  126.773 1.728 127.043 3.744 ;
     RECT  126.709 5.696 127.043 5.728 ;
     RECT  127.157 0.192 127.189 0.224 ;
     RECT  127.043 1.728 127.189 3.488 ;
     RECT  127.189 0.192 127.44 3.488 ;
     RECT  114.611 7.929 127.44 8.601 ;
     RECT  47.019 13.329 127.44 14.001 ;
     RECT  118.979 18.729 127.44 19.401 ;
     RECT  125.555 24.129 127.44 24.801 ;
     RECT  125.459 29.529 127.44 30.201 ;
     RECT  125.675 34.929 127.44 35.601 ;
     RECT  2.16 40.329 127.44 41.001 ;
     RECT  2.16 45.729 127.44 46.401 ;
     RECT  2.16 51.129 127.44 51.801 ;
     RECT  66.347 56.529 127.44 57.201 ;
     RECT  2.16 61.929 127.44 62.601 ;
     RECT  2.16 67.329 127.44 68.001 ;
     RECT  2.16 72.729 127.44 73.401 ;
     RECT  2.16 78.129 127.44 78.801 ;
     RECT  52.203 83.529 127.44 84.201 ;
     RECT  83.755 88.704 127.44 89.601 ;
     RECT  2.16 94.329 127.44 95.001 ;
     RECT  2.16 99.729 127.44 100.401 ;
     RECT  2.16 105.129 127.44 105.801 ;
     RECT  2.16 110.529 127.44 111.201 ;
     RECT  2.16 115.929 127.44 116.601 ;
     RECT  87.083 121.329 127.44 122.001 ;
     RECT  67.755 126.729 127.44 127.401 ;
     RECT  2.16 132.129 127.44 132.801 ;
     RECT  2.16 137.529 127.44 138.201 ;
     RECT  2.16 142.929 127.44 143.601 ;
     RECT  94.643 148.329 127.44 149.001 ;
     RECT  85.163 153.729 127.44 154.401 ;
     RECT  2.16 159.129 127.44 159.801 ;
     RECT  2.16 164.529 127.44 165.201 ;
     RECT  2.16 169.929 127.44 170.601 ;
     RECT  2.16 175.329 127.44 176.001 ;
     RECT  126.763 180.729 127.44 182.368 ;
     RECT  127.44 181.504 127.659 182.368 ;
     RECT  127.659 181.76 128.107 182.368 ;
     RECT  127.44 0.192 128.195 1.888 ;
     RECT  128.195 0.576 128.555 1.888 ;
     RECT  128.555 0.576 128.619 1.76 ;
     RECT  128.619 0.576 128.939 0.736 ;
     RECT  127.44 3.328 129.003 3.488 ;
     RECT  129.003 3.328 129.387 3.36 ;
     RECT  128.107 181.76 129.387 181.792 ;
     RECT  127.44 88.704 129.443 88.736 ;
     RECT  128.939 0.704 129.451 0.736 ;
    LAYER M7 ;
     RECT  13.952 0.035 27.936 0.107 ;
     RECT  96.64 0.035 112.288 0.107 ;
     RECT  69.12 0.035 84.128 0.619 ;
     RECT  124.224 0.035 129.44 0.747 ;
     RECT  41.536 0.035 56.032 1.195 ;
     RECT  96.64 0.107 111.84 1.195 ;
     RECT  13.952 0.107 27.488 1.771 ;
     RECT  41.536 1.195 55.584 1.771 ;
     RECT  69.12 0.619 83.296 1.771 ;
     RECT  111.808 1.195 111.84 1.771 ;
     RECT  124.224 0.747 129.376 1.771 ;
     RECT  128.512 1.771 129.376 1.899 ;
     RECT  69.504 1.771 82.464 2.347 ;
     RECT  96.64 1.195 110.048 2.347 ;
     RECT  124.224 1.771 125.088 2.347 ;
     RECT  41.536 1.771 54.944 3.371 ;
     RECT  69.504 2.347 77.28 3.371 ;
     RECT  128.96 1.899 129.376 3.371 ;
     RECT  69.504 3.371 73.44 3.435 ;
     RECT  15.296 1.771 27.36 3.499 ;
     RECT  41.536 3.371 46.752 3.499 ;
     RECT  48.832 3.371 54.048 3.499 ;
     RECT  75.136 3.371 77.28 3.499 ;
     RECT  78.592 2.347 82.464 3.499 ;
     RECT  96.64 2.347 109.152 3.499 ;
     RECT  128.96 3.371 128.992 3.499 ;
     RECT  126.72 1.771 126.816 3.755 ;
     RECT  15.68 3.499 20.448 4.075 ;
     RECT  77.248 3.499 77.28 4.075 ;
     RECT  97.536 3.499 97.568 4.075 ;
     RECT  104.384 3.499 106.144 4.075 ;
     RECT  78.592 3.499 80.288 4.085 ;
     RECT  81.984 3.499 82.464 4.469 ;
     RECT  13.952 1.771 13.984 4.587 ;
     RECT  16.576 4.075 18.336 4.587 ;
     RECT  20.416 4.075 20.448 4.587 ;
     RECT  22.144 3.499 25.632 4.587 ;
     RECT  27.328 3.499 27.36 4.587 ;
     RECT  42.368 3.499 43.296 4.587 ;
     RECT  46.72 3.499 46.752 4.587 ;
     RECT  50.56 3.499 53.28 4.587 ;
     RECT  69.504 3.435 71.712 4.587 ;
     RECT  73.408 3.435 73.44 4.587 ;
     RECT  75.136 3.499 75.168 4.587 ;
     RECT  78.4 4.085 80.288 4.587 ;
     RECT  100.096 3.499 101.408 4.587 ;
     RECT  104.384 4.075 105.44 4.587 ;
     RECT  124.224 2.347 124.256 4.587 ;
     RECT  81.984 4.469 82.592 4.651 ;
     RECT  16.576 4.587 17.568 5.163 ;
     RECT  116.736 4.341 116.768 5.163 ;
     RECT  34.816 4.533 34.848 5.173 ;
     RECT  23.296 4.587 23.328 5.227 ;
     RECT  105.152 4.587 105.44 5.675 ;
     RECT  84.608 2.357 84.64 5.685 ;
     RECT  84.352 5.685 84.64 5.739 ;
     RECT  126.72 3.755 126.752 5.739 ;
     RECT  109.952 5.173 109.984 6.507 ;
     RECT  42.368 4.587 42.4 6.571 ;
     RECT  48.128 6.517 48.16 6.709 ;
     RECT  69.504 4.587 70.816 7.467 ;
     RECT  69.952 7.467 70.816 7.851 ;
     RECT  53.248 4.587 53.28 8.747 ;
     RECT  47.872 6.709 48.16 9.013 ;
     RECT  51.584 4.587 51.616 9.141 ;
     RECT  51.584 9.141 51.744 9.195 ;
     RECT  46.976 9.013 48.16 9.771 ;
     RECT  97.152 4.853 97.184 9.771 ;
     RECT  78.4 4.587 78.56 10.027 ;
     RECT  34.816 5.173 35.36 10.347 ;
     RECT  84.352 5.739 84.384 10.347 ;
     RECT  35.328 10.347 35.36 10.421 ;
     RECT  35.328 10.421 35.424 10.422 ;
     RECT  35.392 10.422 35.424 10.485 ;
     RECT  99.456 5.045 99.488 10.485 ;
     RECT  105.152 5.675 105.184 10.539 ;
     RECT  82.56 4.651 82.592 10.741 ;
     RECT  82.56 10.741 83.488 10.859 ;
     RECT  17.28 5.163 17.568 11.765 ;
     RECT  17.216 11.765 17.568 11.819 ;
     RECT  35.392 10.485 35.872 12.011 ;
     RECT  46.976 9.771 47.904 15.477 ;
     RECT  46.976 15.477 48.352 15.531 ;
     RECT  32.128 5.877 32.16 15.861 ;
     RECT  32.128 15.861 32.544 15.915 ;
     RECT  78.528 10.027 78.56 15.925 ;
     RECT  78.336 15.925 78.56 15.979 ;
     RECT  98.88 10.485 99.488 16.501 ;
     RECT  94.272 5.045 94.304 16.619 ;
     RECT  17.216 11.819 17.312 16.757 ;
     RECT  64.768 6.197 64.8 16.811 ;
     RECT  113.984 4.277 114.016 16.821 ;
     RECT  113.984 16.821 114.464 16.875 ;
     RECT  74.112 15.733 74.144 17.013 ;
     RECT  83.136 10.859 83.488 17.013 ;
     RECT  92.352 15.989 92.384 17.013 ;
     RECT  74.112 17.013 74.272 17.067 ;
     RECT  92.352 17.013 93.472 17.067 ;
     RECT  110.016 7.285 110.048 17.067 ;
     RECT  62.144 16.501 62.176 17.323 ;
     RECT  68.16 4.277 68.192 17.333 ;
     RECT  82.368 17.013 83.488 17.579 ;
     RECT  82.56 17.579 83.488 17.643 ;
     RECT  68.096 17.333 68.192 17.781 ;
     RECT  68.096 17.781 68.256 17.835 ;
     RECT  114.432 16.875 114.464 17.963 ;
     RECT  32.512 15.915 32.544 18.219 ;
     RECT  26.048 16.501 26.08 18.357 ;
     RECT  26.048 18.357 26.208 18.411 ;
     RECT  29.248 15.861 29.28 18.411 ;
     RECT  48.32 15.531 48.352 18.667 ;
     RECT  98.624 16.501 99.488 18.667 ;
     RECT  10.752 17.013 10.784 19.563 ;
     RECT  51.712 9.195 51.744 19.563 ;
     RECT  111.488 17.013 111.52 19.563 ;
     RECT  118.848 17.589 118.88 19.563 ;
     RECT  78.336 15.979 78.368 19.765 ;
     RECT  68.16 17.835 68.256 19.819 ;
     RECT  78.208 19.765 78.368 19.819 ;
     RECT  87.232 16.949 87.264 19.893 ;
     RECT  103.488 16.693 103.52 19.893 ;
     RECT  87.232 19.893 87.52 19.947 ;
     RECT  103.168 19.893 103.52 19.947 ;
     RECT  60.096 6.197 60.128 20.469 ;
     RECT  74.24 17.067 74.272 20.469 ;
     RECT  74.24 20.469 74.4 20.523 ;
     RECT  68.224 19.819 68.256 20.533 ;
     RECT  10.688 19.637 10.72 20.587 ;
     RECT  68.224 20.533 68.96 20.587 ;
     RECT  17.088 16.757 17.312 20.597 ;
     RECT  82.56 17.643 83.168 20.725 ;
     RECT  26.176 18.411 26.208 20.789 ;
     RECT  17.088 20.597 17.632 20.843 ;
     RECT  20.48 16.885 20.512 20.907 ;
     RECT  35.84 12.011 35.872 21.163 ;
     RECT  96.96 18.613 96.992 21.163 ;
     RECT  25.152 20.789 26.208 21.301 ;
     RECT  41.024 16.309 41.056 21.675 ;
     RECT  106.944 20.469 106.976 21.685 ;
     RECT  78.208 19.819 78.24 21.739 ;
     RECT  106.304 21.685 106.976 21.739 ;
     RECT  98.88 18.667 99.488 21.813 ;
     RECT  56.96 17.013 56.992 21.995 ;
     RECT  5.056 18.421 5.088 22.187 ;
     RECT  46.976 15.531 47.008 22.197 ;
     RECT  37.376 19.701 37.408 22.315 ;
     RECT  111.424 19.893 111.456 22.315 ;
     RECT  116.224 20.469 116.256 22.389 ;
     RECT  116.032 22.389 116.256 22.443 ;
     RECT  103.168 19.947 103.2 22.507 ;
     RECT  53.696 19.893 53.728 22.645 ;
     RECT  9.088 20.021 9.12 22.699 ;
     RECT  53.504 22.645 53.728 22.699 ;
     RECT  17.088 20.843 17.12 22.891 ;
     RECT  68.928 20.587 68.96 22.891 ;
     RECT  82.432 20.725 83.168 22.891 ;
     RECT  118.912 19.829 118.944 22.891 ;
     RECT  60.096 20.469 60.64 23.339 ;
     RECT  53.504 22.699 53.536 23.349 ;
     RECT  46.016 22.197 47.008 23.403 ;
     RECT  53.184 23.349 53.536 23.403 ;
     RECT  93.44 17.067 93.472 23.403 ;
     RECT  83.136 22.891 83.168 23.733 ;
     RECT  116.032 22.443 116.064 23.861 ;
     RECT  115.712 23.861 116.064 23.915 ;
     RECT  41.28 22.197 41.312 23.979 ;
     RECT  74.368 20.523 74.4 23.979 ;
     RECT  98.752 21.813 99.488 23.979 ;
     RECT  32.448 19.509 32.48 24.043 ;
     RECT  87.488 19.947 87.52 24.043 ;
     RECT  83.136 23.733 84.32 24.885 ;
     RECT  24.832 21.301 26.208 24.939 ;
     RECT  57.664 25.013 57.696 25.653 ;
     RECT  57.664 25.653 57.824 25.707 ;
     RECT  115.712 23.915 115.744 26.165 ;
     RECT  115.2 26.165 115.744 26.219 ;
     RECT  83.136 24.885 85.216 26.283 ;
     RECT  35.136 25.013 35.168 26.475 ;
     RECT  104.832 22.197 104.864 26.475 ;
     RECT  44.096 23.221 44.128 26.485 ;
     RECT  44.096 26.485 44.576 26.539 ;
     RECT  98.88 23.979 99.488 26.677 ;
     RECT  111.552 25.013 111.584 26.677 ;
     RECT  88.192 25.589 88.224 26.859 ;
     RECT  13.12 25.333 13.152 27.115 ;
     RECT  9.664 27.061 9.696 27.317 ;
     RECT  106.304 21.739 106.336 27.317 ;
     RECT  24.832 24.939 25.632 27.371 ;
     RECT  31.872 25.909 31.904 27.371 ;
     RECT  106.048 27.317 106.336 27.371 ;
     RECT  123.072 25.013 123.104 27.371 ;
     RECT  44.544 26.539 44.576 27.435 ;
     RECT  2.88 25.333 2.912 27.509 ;
     RECT  2.88 27.509 3.424 27.563 ;
     RECT  80.192 26.165 80.224 27.573 ;
     RECT  6.912 24.885 6.944 27.627 ;
     RECT  80.192 27.573 80.928 27.627 ;
     RECT  76.352 25.013 76.384 27.893 ;
     RECT  76.032 27.893 76.384 27.947 ;
     RECT  66.624 25.909 66.656 28.405 ;
     RECT  66.304 28.405 66.656 28.459 ;
     RECT  70.784 26.165 70.816 28.459 ;
     RECT  19.392 28.341 19.424 28.469 ;
     RECT  57.792 25.707 57.824 28.469 ;
     RECT  57.408 28.469 57.824 28.523 ;
     RECT  115.2 26.219 115.232 28.587 ;
     RECT  3.392 27.563 3.424 28.789 ;
     RECT  37.312 26.805 37.344 28.971 ;
     RECT  53.184 23.403 53.216 29.099 ;
     RECT  98.624 26.677 99.488 29.227 ;
     RECT  9.536 27.317 9.696 29.355 ;
     RECT  118.976 23.221 119.008 29.355 ;
     RECT  62.976 25.013 63.008 29.365 ;
     RECT  89.984 26.293 90.016 29.365 ;
     RECT  9.664 29.355 9.696 29.419 ;
     RECT  12.608 27.573 12.704 29.419 ;
     RECT  42.304 26.485 42.336 29.419 ;
     RECT  62.976 29.365 63.136 29.419 ;
     RECT  80.896 27.627 80.928 29.419 ;
     RECT  89.28 29.365 90.016 29.419 ;
     RECT  98.88 29.227 99.488 29.419 ;
     RECT  106.048 27.371 106.08 29.419 ;
     RECT  3.392 28.789 4.064 30.379 ;
     RECT  31.552 27.829 31.584 30.379 ;
     RECT  16.96 28.981 16.992 30.389 ;
     RECT  16.832 30.389 16.992 30.443 ;
     RECT  110.848 26.677 111.584 30.453 ;
     RECT  110.592 30.453 111.584 30.507 ;
     RECT  110.592 30.507 111.392 30.635 ;
     RECT  24.832 27.371 25.12 30.709 ;
     RECT  98.88 29.419 98.912 30.709 ;
     RECT  89.28 29.419 89.312 30.827 ;
     RECT  4.032 30.379 4.064 30.955 ;
     RECT  57.408 28.523 57.44 31.349 ;
     RECT  118.72 30.325 118.752 31.349 ;
     RECT  56.768 31.349 57.44 31.403 ;
     RECT  118.272 31.349 118.752 31.403 ;
     RECT  93.504 29.237 93.536 31.659 ;
     RECT  35.904 28.917 35.936 31.723 ;
     RECT  66.304 28.459 66.336 31.723 ;
     RECT  81.216 30.709 81.248 31.861 ;
     RECT  81.216 31.861 81.504 31.915 ;
     RECT  19.392 28.469 20.704 31.979 ;
     RECT  24.768 30.709 25.12 31.979 ;
     RECT  29.952 30.709 29.984 31.979 ;
     RECT  16.832 30.443 16.864 32.427 ;
     RECT  111.36 30.635 111.392 32.427 ;
     RECT  12.608 29.419 12.64 32.437 ;
     RECT  98.88 30.709 99.168 32.491 ;
     RECT  102.4 29.365 102.432 32.747 ;
     RECT  7.936 32.757 7.968 32.885 ;
     RECT  12.608 32.437 13.28 32.885 ;
     RECT  48.576 27.317 48.608 33.003 ;
     RECT  118.272 31.403 118.304 33.003 ;
     RECT  5.056 31.541 5.088 33.131 ;
     RECT  7.68 32.885 7.968 33.131 ;
     RECT  27.392 30.453 27.424 33.131 ;
     RECT  44.992 30.965 45.024 33.131 ;
     RECT  76.032 27.947 76.064 33.259 ;
     RECT  7.68 33.131 7.712 33.707 ;
     RECT  81.472 31.915 81.504 34.027 ;
     RECT  46.976 23.403 47.008 34.283 ;
     RECT  56.768 31.403 56.8 34.283 ;
     RECT  83.136 26.283 83.168 34.283 ;
     RECT  121.408 30.453 121.44 34.283 ;
     RECT  63.104 29.419 63.136 34.357 ;
     RECT  24.768 31.979 24.8 34.667 ;
     RECT  19.392 31.979 19.936 34.731 ;
     RECT  85.184 26.283 85.216 34.741 ;
     RECT  84.992 34.741 85.216 34.795 ;
     RECT  19.904 34.731 19.936 34.859 ;
     RECT  98.88 32.491 98.912 34.859 ;
     RECT  108.544 26.805 108.576 34.859 ;
     RECT  11.968 32.885 13.28 35.755 ;
     RECT  63.104 34.357 64.288 35.755 ;
     RECT  124.608 30.325 124.64 35.755 ;
     RECT  13.248 35.755 13.28 36.075 ;
     RECT  64.256 35.755 64.288 57.323 ;
     RECT  50.048 23.285 50.08 84.907 ;
     RECT  52.16 85.109 52.192 85.557 ;
     RECT  52.16 85.557 52.32 85.611 ;
     RECT  60.096 23.339 60.128 85.675 ;
     RECT  83.264 87.157 83.296 87.797 ;
     RECT  84.992 34.795 85.024 87.797 ;
     RECT  72.256 19.893 72.288 87.851 ;
     RECT  83.264 87.797 85.024 87.851 ;
     RECT  64.768 88.693 64.8 91.883 ;
     RECT  125.632 35.829 125.664 107.243 ;
     RECT  52.288 85.611 52.32 118.635 ;
     RECT  50.496 119.093 50.528 120.501 ;
     RECT  66.304 57.525 66.336 120.501 ;
     RECT  50.176 120.501 50.528 120.555 ;
     RECT  50.176 120.555 50.208 120.811 ;
     RECT  83.712 87.851 85.024 120.875 ;
     RECT  66.304 120.501 67.296 121.013 ;
     RECT  66.304 121.013 67.744 121.067 ;
     RECT  66.304 121.067 66.336 125.483 ;
     RECT  67.712 121.067 67.744 125.483 ;
     RECT  87.04 122.101 87.072 149.877 ;
     RECT  86.912 149.877 87.072 149.931 ;
     RECT  46.976 120.885 47.008 150.571 ;
     RECT  86.912 149.931 86.944 152.235 ;
     RECT  84.992 120.875 85.024 152.501 ;
     RECT  94.592 149.749 94.624 179.371 ;
     RECT  84.992 152.501 85.152 179.627 ;
     RECT  85.12 179.627 85.152 179.947 ;
     RECT  39.104 148.149 39.136 180.651 ;
     RECT  48.576 150.901 48.608 181.493 ;
     RECT  109.184 178.805 109.216 181.493 ;
     RECT  73.152 181.493 77.088 181.621 ;
     RECT  78.4 181.493 78.432 181.621 ;
     RECT  15.168 181.493 20.448 181.749 ;
     RECT  21.76 181.493 22.176 181.749 ;
     RECT  23.488 181.493 27.04 181.749 ;
     RECT  42.368 181.493 46.368 181.749 ;
     RECT  48.064 181.493 56.032 181.749 ;
     RECT  70.464 181.493 71.392 181.749 ;
     RECT  72.704 181.621 78.432 181.749 ;
     RECT  79.744 181.493 84.128 181.749 ;
     RECT  99.072 181.493 112.288 181.749 ;
     RECT  127.616 181.493 127.648 181.749 ;
     RECT  127.168 181.749 129.376 182.965 ;
     RECT  14.272 181.749 27.936 183.556 ;
     RECT  42.368 181.749 56.032 183.556 ;
     RECT  70.464 181.749 84.128 183.556 ;
     RECT  98.624 181.749 112.288 183.556 ;
     RECT  126.72 182.965 129.376 183.556 ;
  END
END ot_qkvd_kv_wq_leaf
END LIBRARY
